# Generated by FakeRAM 2.0
VERSION 5.7 ;
BUSBITCHARS "[]" ;
PROPERTYDEFINITIONS
  MACRO width INTEGER ;
  MACRO depth INTEGER ;
  MACRO banks INTEGER ;
END PROPERTYDEFINITIONS
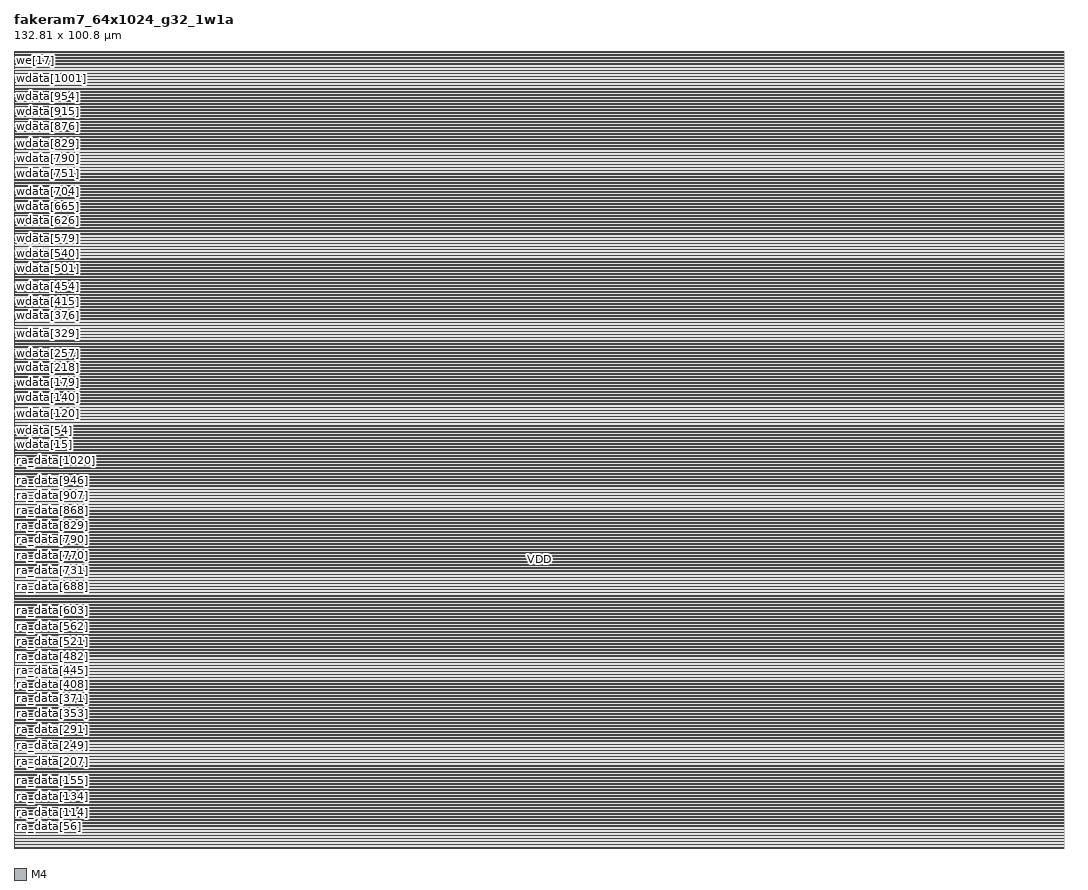
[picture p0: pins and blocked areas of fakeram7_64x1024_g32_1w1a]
MACRO fakeram7_64x1024_g32_1w1a
  PROPERTY width 1024 ;
  PROPERTY depth 64 ;
  PROPERTY banks 1 ;
  FOREIGN fakeram7_64x1024_g32_1w1a 0 0 ;
  SYMMETRY X Y R90 ;
  SIZE 132.8100 BY 100.8000 ;
  CLASS BLOCK ;
  PIN wdata[0]
    DIRECTION INPUT ;
    USE SIGNAL ;
    PORT
      LAYER M4 ;
      RECT 0.00000 49.24800 0.03600 49.27200 ;
    END
  END wdata[0]
  PIN wdata[1]
    DIRECTION INPUT ;
    USE SIGNAL ;
    PORT
      LAYER M4 ;
      RECT 0.00000 49.29600 0.03600 49.32000 ;
    END
  END wdata[1]
  PIN wdata[2]
    DIRECTION INPUT ;
    USE SIGNAL ;
    PORT
      LAYER M4 ;
      RECT 0.00000 49.34400 0.03600 49.36800 ;
    END
  END wdata[2]
  PIN wdata[3]
    DIRECTION INPUT ;
    USE SIGNAL ;
    PORT
      LAYER M4 ;
      RECT 0.00000 49.39200 0.03600 49.41600 ;
    END
  END wdata[3]
  PIN wdata[4]
    DIRECTION INPUT ;
    USE SIGNAL ;
    PORT
      LAYER M4 ;
      RECT 0.00000 49.44000 0.03600 49.46400 ;
    END
  END wdata[4]
  PIN wdata[5]
    DIRECTION INPUT ;
    USE SIGNAL ;
    PORT
      LAYER M4 ;
      RECT 0.00000 49.48800 0.03600 49.51200 ;
    END
  END wdata[5]
  PIN wdata[6]
    DIRECTION INPUT ;
    USE SIGNAL ;
    PORT
      LAYER M4 ;
      RECT 0.00000 49.53600 0.03600 49.56000 ;
    END
  END wdata[6]
  PIN wdata[7]
    DIRECTION INPUT ;
    USE SIGNAL ;
    PORT
      LAYER M4 ;
      RECT 0.00000 49.58400 0.03600 49.60800 ;
    END
  END wdata[7]
  PIN wdata[8]
    DIRECTION INPUT ;
    USE SIGNAL ;
    PORT
      LAYER M4 ;
      RECT 0.00000 49.63200 0.03600 49.65600 ;
    END
  END wdata[8]
  PIN wdata[9]
    DIRECTION INPUT ;
    USE SIGNAL ;
    PORT
      LAYER M4 ;
      RECT 0.00000 49.68000 0.03600 49.70400 ;
    END
  END wdata[9]
  PIN wdata[10]
    DIRECTION INPUT ;
    USE SIGNAL ;
    PORT
      LAYER M4 ;
      RECT 0.00000 49.72800 0.03600 49.75200 ;
    END
  END wdata[10]
  PIN wdata[11]
    DIRECTION INPUT ;
    USE SIGNAL ;
    PORT
      LAYER M4 ;
      RECT 0.00000 49.77600 0.03600 49.80000 ;
    END
  END wdata[11]
  PIN wdata[12]
    DIRECTION INPUT ;
    USE SIGNAL ;
    PORT
      LAYER M4 ;
      RECT 0.00000 49.82400 0.03600 49.84800 ;
    END
  END wdata[12]
  PIN wdata[13]
    DIRECTION INPUT ;
    USE SIGNAL ;
    PORT
      LAYER M4 ;
      RECT 0.00000 49.87200 0.03600 49.89600 ;
    END
  END wdata[13]
  PIN wdata[14]
    DIRECTION INPUT ;
    USE SIGNAL ;
    PORT
      LAYER M4 ;
      RECT 0.00000 49.92000 0.03600 49.94400 ;
    END
  END wdata[14]
  PIN wdata[15]
    DIRECTION INPUT ;
    USE SIGNAL ;
    PORT
      LAYER M4 ;
      RECT 0.00000 49.96800 0.03600 49.99200 ;
    END
  END wdata[15]
  PIN wdata[16]
    DIRECTION INPUT ;
    USE SIGNAL ;
    PORT
      LAYER M4 ;
      RECT 0.00000 50.01600 0.03600 50.04000 ;
    END
  END wdata[16]
  PIN wdata[17]
    DIRECTION INPUT ;
    USE SIGNAL ;
    PORT
      LAYER M4 ;
      RECT 0.00000 50.06400 0.03600 50.08800 ;
    END
  END wdata[17]
  PIN wdata[18]
    DIRECTION INPUT ;
    USE SIGNAL ;
    PORT
      LAYER M4 ;
      RECT 0.00000 50.11200 0.03600 50.13600 ;
    END
  END wdata[18]
  PIN wdata[19]
    DIRECTION INPUT ;
    USE SIGNAL ;
    PORT
      LAYER M4 ;
      RECT 0.00000 50.16000 0.03600 50.18400 ;
    END
  END wdata[19]
  PIN wdata[20]
    DIRECTION INPUT ;
    USE SIGNAL ;
    PORT
      LAYER M4 ;
      RECT 0.00000 50.20800 0.03600 50.23200 ;
    END
  END wdata[20]
  PIN wdata[21]
    DIRECTION INPUT ;
    USE SIGNAL ;
    PORT
      LAYER M4 ;
      RECT 0.00000 50.25600 0.03600 50.28000 ;
    END
  END wdata[21]
  PIN wdata[22]
    DIRECTION INPUT ;
    USE SIGNAL ;
    PORT
      LAYER M4 ;
      RECT 0.00000 50.30400 0.03600 50.32800 ;
    END
  END wdata[22]
  PIN wdata[23]
    DIRECTION INPUT ;
    USE SIGNAL ;
    PORT
      LAYER M4 ;
      RECT 0.00000 50.35200 0.03600 50.37600 ;
    END
  END wdata[23]
  PIN wdata[24]
    DIRECTION INPUT ;
    USE SIGNAL ;
    PORT
      LAYER M4 ;
      RECT 0.00000 50.40000 0.03600 50.42400 ;
    END
  END wdata[24]
  PIN wdata[25]
    DIRECTION INPUT ;
    USE SIGNAL ;
    PORT
      LAYER M4 ;
      RECT 0.00000 50.44800 0.03600 50.47200 ;
    END
  END wdata[25]
  PIN wdata[26]
    DIRECTION INPUT ;
    USE SIGNAL ;
    PORT
      LAYER M4 ;
      RECT 0.00000 50.49600 0.03600 50.52000 ;
    END
  END wdata[26]
  PIN wdata[27]
    DIRECTION INPUT ;
    USE SIGNAL ;
    PORT
      LAYER M4 ;
      RECT 0.00000 50.54400 0.03600 50.56800 ;
    END
  END wdata[27]
  PIN wdata[28]
    DIRECTION INPUT ;
    USE SIGNAL ;
    PORT
      LAYER M4 ;
      RECT 0.00000 50.59200 0.03600 50.61600 ;
    END
  END wdata[28]
  PIN wdata[29]
    DIRECTION INPUT ;
    USE SIGNAL ;
    PORT
      LAYER M4 ;
      RECT 0.00000 50.64000 0.03600 50.66400 ;
    END
  END wdata[29]
  PIN wdata[30]
    DIRECTION INPUT ;
    USE SIGNAL ;
    PORT
      LAYER M4 ;
      RECT 0.00000 50.68800 0.03600 50.71200 ;
    END
  END wdata[30]
  PIN wdata[31]
    DIRECTION INPUT ;
    USE SIGNAL ;
    PORT
      LAYER M4 ;
      RECT 0.00000 50.73600 0.03600 50.76000 ;
    END
  END wdata[31]
  PIN wdata[32]
    DIRECTION INPUT ;
    USE SIGNAL ;
    PORT
      LAYER M4 ;
      RECT 0.00000 50.78400 0.03600 50.80800 ;
    END
  END wdata[32]
  PIN wdata[33]
    DIRECTION INPUT ;
    USE SIGNAL ;
    PORT
      LAYER M4 ;
      RECT 0.00000 50.83200 0.03600 50.85600 ;
    END
  END wdata[33]
  PIN wdata[34]
    DIRECTION INPUT ;
    USE SIGNAL ;
    PORT
      LAYER M4 ;
      RECT 0.00000 50.88000 0.03600 50.90400 ;
    END
  END wdata[34]
  PIN wdata[35]
    DIRECTION INPUT ;
    USE SIGNAL ;
    PORT
      LAYER M4 ;
      RECT 0.00000 50.92800 0.03600 50.95200 ;
    END
  END wdata[35]
  PIN wdata[36]
    DIRECTION INPUT ;
    USE SIGNAL ;
    PORT
      LAYER M4 ;
      RECT 0.00000 50.97600 0.03600 51.00000 ;
    END
  END wdata[36]
  PIN wdata[37]
    DIRECTION INPUT ;
    USE SIGNAL ;
    PORT
      LAYER M4 ;
      RECT 0.00000 51.02400 0.03600 51.04800 ;
    END
  END wdata[37]
  PIN wdata[38]
    DIRECTION INPUT ;
    USE SIGNAL ;
    PORT
      LAYER M4 ;
      RECT 0.00000 51.07200 0.03600 51.09600 ;
    END
  END wdata[38]
  PIN wdata[39]
    DIRECTION INPUT ;
    USE SIGNAL ;
    PORT
      LAYER M4 ;
      RECT 0.00000 51.12000 0.03600 51.14400 ;
    END
  END wdata[39]
  PIN wdata[40]
    DIRECTION INPUT ;
    USE SIGNAL ;
    PORT
      LAYER M4 ;
      RECT 0.00000 51.16800 0.03600 51.19200 ;
    END
  END wdata[40]
  PIN wdata[41]
    DIRECTION INPUT ;
    USE SIGNAL ;
    PORT
      LAYER M4 ;
      RECT 0.00000 51.21600 0.03600 51.24000 ;
    END
  END wdata[41]
  PIN wdata[42]
    DIRECTION INPUT ;
    USE SIGNAL ;
    PORT
      LAYER M4 ;
      RECT 0.00000 51.26400 0.03600 51.28800 ;
    END
  END wdata[42]
  PIN wdata[43]
    DIRECTION INPUT ;
    USE SIGNAL ;
    PORT
      LAYER M4 ;
      RECT 0.00000 51.31200 0.03600 51.33600 ;
    END
  END wdata[43]
  PIN wdata[44]
    DIRECTION INPUT ;
    USE SIGNAL ;
    PORT
      LAYER M4 ;
      RECT 0.00000 51.36000 0.03600 51.38400 ;
    END
  END wdata[44]
  PIN wdata[45]
    DIRECTION INPUT ;
    USE SIGNAL ;
    PORT
      LAYER M4 ;
      RECT 0.00000 51.40800 0.03600 51.43200 ;
    END
  END wdata[45]
  PIN wdata[46]
    DIRECTION INPUT ;
    USE SIGNAL ;
    PORT
      LAYER M4 ;
      RECT 0.00000 51.45600 0.03600 51.48000 ;
    END
  END wdata[46]
  PIN wdata[47]
    DIRECTION INPUT ;
    USE SIGNAL ;
    PORT
      LAYER M4 ;
      RECT 0.00000 51.50400 0.03600 51.52800 ;
    END
  END wdata[47]
  PIN wdata[48]
    DIRECTION INPUT ;
    USE SIGNAL ;
    PORT
      LAYER M4 ;
      RECT 0.00000 51.55200 0.03600 51.57600 ;
    END
  END wdata[48]
  PIN wdata[49]
    DIRECTION INPUT ;
    USE SIGNAL ;
    PORT
      LAYER M4 ;
      RECT 0.00000 51.60000 0.03600 51.62400 ;
    END
  END wdata[49]
  PIN wdata[50]
    DIRECTION INPUT ;
    USE SIGNAL ;
    PORT
      LAYER M4 ;
      RECT 0.00000 51.64800 0.03600 51.67200 ;
    END
  END wdata[50]
  PIN wdata[51]
    DIRECTION INPUT ;
    USE SIGNAL ;
    PORT
      LAYER M4 ;
      RECT 0.00000 51.69600 0.03600 51.72000 ;
    END
  END wdata[51]
  PIN wdata[52]
    DIRECTION INPUT ;
    USE SIGNAL ;
    PORT
      LAYER M4 ;
      RECT 0.00000 51.74400 0.03600 51.76800 ;
    END
  END wdata[52]
  PIN wdata[53]
    DIRECTION INPUT ;
    USE SIGNAL ;
    PORT
      LAYER M4 ;
      RECT 0.00000 51.79200 0.03600 51.81600 ;
    END
  END wdata[53]
  PIN wdata[54]
    DIRECTION INPUT ;
    USE SIGNAL ;
    PORT
      LAYER M4 ;
      RECT 0.00000 51.84000 0.03600 51.86400 ;
    END
  END wdata[54]
  PIN wdata[55]
    DIRECTION INPUT ;
    USE SIGNAL ;
    PORT
      LAYER M4 ;
      RECT 0.00000 51.88800 0.03600 51.91200 ;
    END
  END wdata[55]
  PIN wdata[56]
    DIRECTION INPUT ;
    USE SIGNAL ;
    PORT
      LAYER M4 ;
      RECT 0.00000 51.93600 0.03600 51.96000 ;
    END
  END wdata[56]
  PIN wdata[57]
    DIRECTION INPUT ;
    USE SIGNAL ;
    PORT
      LAYER M4 ;
      RECT 0.00000 51.98400 0.03600 52.00800 ;
    END
  END wdata[57]
  PIN wdata[58]
    DIRECTION INPUT ;
    USE SIGNAL ;
    PORT
      LAYER M4 ;
      RECT 0.00000 52.03200 0.03600 52.05600 ;
    END
  END wdata[58]
  PIN wdata[59]
    DIRECTION INPUT ;
    USE SIGNAL ;
    PORT
      LAYER M4 ;
      RECT 0.00000 52.08000 0.03600 52.10400 ;
    END
  END wdata[59]
  PIN wdata[60]
    DIRECTION INPUT ;
    USE SIGNAL ;
    PORT
      LAYER M4 ;
      RECT 0.00000 52.12800 0.03600 52.15200 ;
    END
  END wdata[60]
  PIN wdata[61]
    DIRECTION INPUT ;
    USE SIGNAL ;
    PORT
      LAYER M4 ;
      RECT 0.00000 52.17600 0.03600 52.20000 ;
    END
  END wdata[61]
  PIN wdata[62]
    DIRECTION INPUT ;
    USE SIGNAL ;
    PORT
      LAYER M4 ;
      RECT 0.00000 52.22400 0.03600 52.24800 ;
    END
  END wdata[62]
  PIN wdata[63]
    DIRECTION INPUT ;
    USE SIGNAL ;
    PORT
      LAYER M4 ;
      RECT 0.00000 52.27200 0.03600 52.29600 ;
    END
  END wdata[63]
  PIN wdata[64]
    DIRECTION INPUT ;
    USE SIGNAL ;
    PORT
      LAYER M4 ;
      RECT 0.00000 52.32000 0.03600 52.34400 ;
    END
  END wdata[64]
  PIN wdata[65]
    DIRECTION INPUT ;
    USE SIGNAL ;
    PORT
      LAYER M4 ;
      RECT 0.00000 52.36800 0.03600 52.39200 ;
    END
  END wdata[65]
  PIN wdata[66]
    DIRECTION INPUT ;
    USE SIGNAL ;
    PORT
      LAYER M4 ;
      RECT 0.00000 52.41600 0.03600 52.44000 ;
    END
  END wdata[66]
  PIN wdata[67]
    DIRECTION INPUT ;
    USE SIGNAL ;
    PORT
      LAYER M4 ;
      RECT 0.00000 52.46400 0.03600 52.48800 ;
    END
  END wdata[67]
  PIN wdata[68]
    DIRECTION INPUT ;
    USE SIGNAL ;
    PORT
      LAYER M4 ;
      RECT 0.00000 52.51200 0.03600 52.53600 ;
    END
  END wdata[68]
  PIN wdata[69]
    DIRECTION INPUT ;
    USE SIGNAL ;
    PORT
      LAYER M4 ;
      RECT 0.00000 52.56000 0.03600 52.58400 ;
    END
  END wdata[69]
  PIN wdata[70]
    DIRECTION INPUT ;
    USE SIGNAL ;
    PORT
      LAYER M4 ;
      RECT 0.00000 52.60800 0.03600 52.63200 ;
    END
  END wdata[70]
  PIN wdata[71]
    DIRECTION INPUT ;
    USE SIGNAL ;
    PORT
      LAYER M4 ;
      RECT 0.00000 52.65600 0.03600 52.68000 ;
    END
  END wdata[71]
  PIN wdata[72]
    DIRECTION INPUT ;
    USE SIGNAL ;
    PORT
      LAYER M4 ;
      RECT 0.00000 52.70400 0.03600 52.72800 ;
    END
  END wdata[72]
  PIN wdata[73]
    DIRECTION INPUT ;
    USE SIGNAL ;
    PORT
      LAYER M4 ;
      RECT 0.00000 52.75200 0.03600 52.77600 ;
    END
  END wdata[73]
  PIN wdata[74]
    DIRECTION INPUT ;
    USE SIGNAL ;
    PORT
      LAYER M4 ;
      RECT 0.00000 52.80000 0.03600 52.82400 ;
    END
  END wdata[74]
  PIN wdata[75]
    DIRECTION INPUT ;
    USE SIGNAL ;
    PORT
      LAYER M4 ;
      RECT 0.00000 52.84800 0.03600 52.87200 ;
    END
  END wdata[75]
  PIN wdata[76]
    DIRECTION INPUT ;
    USE SIGNAL ;
    PORT
      LAYER M4 ;
      RECT 0.00000 52.89600 0.03600 52.92000 ;
    END
  END wdata[76]
  PIN wdata[77]
    DIRECTION INPUT ;
    USE SIGNAL ;
    PORT
      LAYER M4 ;
      RECT 0.00000 52.94400 0.03600 52.96800 ;
    END
  END wdata[77]
  PIN wdata[78]
    DIRECTION INPUT ;
    USE SIGNAL ;
    PORT
      LAYER M4 ;
      RECT 0.00000 52.99200 0.03600 53.01600 ;
    END
  END wdata[78]
  PIN wdata[79]
    DIRECTION INPUT ;
    USE SIGNAL ;
    PORT
      LAYER M4 ;
      RECT 0.00000 53.04000 0.03600 53.06400 ;
    END
  END wdata[79]
  PIN wdata[80]
    DIRECTION INPUT ;
    USE SIGNAL ;
    PORT
      LAYER M4 ;
      RECT 0.00000 53.08800 0.03600 53.11200 ;
    END
  END wdata[80]
  PIN wdata[81]
    DIRECTION INPUT ;
    USE SIGNAL ;
    PORT
      LAYER M4 ;
      RECT 0.00000 53.13600 0.03600 53.16000 ;
    END
  END wdata[81]
  PIN wdata[82]
    DIRECTION INPUT ;
    USE SIGNAL ;
    PORT
      LAYER M4 ;
      RECT 0.00000 53.18400 0.03600 53.20800 ;
    END
  END wdata[82]
  PIN wdata[83]
    DIRECTION INPUT ;
    USE SIGNAL ;
    PORT
      LAYER M4 ;
      RECT 0.00000 53.23200 0.03600 53.25600 ;
    END
  END wdata[83]
  PIN wdata[84]
    DIRECTION INPUT ;
    USE SIGNAL ;
    PORT
      LAYER M4 ;
      RECT 0.00000 53.28000 0.03600 53.30400 ;
    END
  END wdata[84]
  PIN wdata[85]
    DIRECTION INPUT ;
    USE SIGNAL ;
    PORT
      LAYER M4 ;
      RECT 0.00000 53.32800 0.03600 53.35200 ;
    END
  END wdata[85]
  PIN wdata[86]
    DIRECTION INPUT ;
    USE SIGNAL ;
    PORT
      LAYER M4 ;
      RECT 0.00000 53.37600 0.03600 53.40000 ;
    END
  END wdata[86]
  PIN wdata[87]
    DIRECTION INPUT ;
    USE SIGNAL ;
    PORT
      LAYER M4 ;
      RECT 0.00000 53.42400 0.03600 53.44800 ;
    END
  END wdata[87]
  PIN wdata[88]
    DIRECTION INPUT ;
    USE SIGNAL ;
    PORT
      LAYER M4 ;
      RECT 0.00000 53.47200 0.03600 53.49600 ;
    END
  END wdata[88]
  PIN wdata[89]
    DIRECTION INPUT ;
    USE SIGNAL ;
    PORT
      LAYER M4 ;
      RECT 0.00000 53.52000 0.03600 53.54400 ;
    END
  END wdata[89]
  PIN wdata[90]
    DIRECTION INPUT ;
    USE SIGNAL ;
    PORT
      LAYER M4 ;
      RECT 0.00000 53.56800 0.03600 53.59200 ;
    END
  END wdata[90]
  PIN wdata[91]
    DIRECTION INPUT ;
    USE SIGNAL ;
    PORT
      LAYER M4 ;
      RECT 0.00000 53.61600 0.03600 53.64000 ;
    END
  END wdata[91]
  PIN wdata[92]
    DIRECTION INPUT ;
    USE SIGNAL ;
    PORT
      LAYER M4 ;
      RECT 0.00000 53.66400 0.03600 53.68800 ;
    END
  END wdata[92]
  PIN wdata[93]
    DIRECTION INPUT ;
    USE SIGNAL ;
    PORT
      LAYER M4 ;
      RECT 0.00000 53.71200 0.03600 53.73600 ;
    END
  END wdata[93]
  PIN wdata[94]
    DIRECTION INPUT ;
    USE SIGNAL ;
    PORT
      LAYER M4 ;
      RECT 0.00000 53.76000 0.03600 53.78400 ;
    END
  END wdata[94]
  PIN wdata[95]
    DIRECTION INPUT ;
    USE SIGNAL ;
    PORT
      LAYER M4 ;
      RECT 0.00000 53.80800 0.03600 53.83200 ;
    END
  END wdata[95]
  PIN wdata[96]
    DIRECTION INPUT ;
    USE SIGNAL ;
    PORT
      LAYER M4 ;
      RECT 0.00000 53.85600 0.03600 53.88000 ;
    END
  END wdata[96]
  PIN wdata[97]
    DIRECTION INPUT ;
    USE SIGNAL ;
    PORT
      LAYER M4 ;
      RECT 0.00000 53.90400 0.03600 53.92800 ;
    END
  END wdata[97]
  PIN wdata[98]
    DIRECTION INPUT ;
    USE SIGNAL ;
    PORT
      LAYER M4 ;
      RECT 0.00000 53.95200 0.03600 53.97600 ;
    END
  END wdata[98]
  PIN wdata[99]
    DIRECTION INPUT ;
    USE SIGNAL ;
    PORT
      LAYER M4 ;
      RECT 0.00000 54.00000 0.03600 54.02400 ;
    END
  END wdata[99]
  PIN wdata[100]
    DIRECTION INPUT ;
    USE SIGNAL ;
    PORT
      LAYER M4 ;
      RECT 0.00000 54.04800 0.03600 54.07200 ;
    END
  END wdata[100]
  PIN wdata[101]
    DIRECTION INPUT ;
    USE SIGNAL ;
    PORT
      LAYER M4 ;
      RECT 0.00000 54.09600 0.03600 54.12000 ;
    END
  END wdata[101]
  PIN wdata[102]
    DIRECTION INPUT ;
    USE SIGNAL ;
    PORT
      LAYER M4 ;
      RECT 0.00000 54.14400 0.03600 54.16800 ;
    END
  END wdata[102]
  PIN wdata[103]
    DIRECTION INPUT ;
    USE SIGNAL ;
    PORT
      LAYER M4 ;
      RECT 0.00000 54.19200 0.03600 54.21600 ;
    END
  END wdata[103]
  PIN wdata[104]
    DIRECTION INPUT ;
    USE SIGNAL ;
    PORT
      LAYER M4 ;
      RECT 0.00000 54.24000 0.03600 54.26400 ;
    END
  END wdata[104]
  PIN wdata[105]
    DIRECTION INPUT ;
    USE SIGNAL ;
    PORT
      LAYER M4 ;
      RECT 0.00000 54.28800 0.03600 54.31200 ;
    END
  END wdata[105]
  PIN wdata[106]
    DIRECTION INPUT ;
    USE SIGNAL ;
    PORT
      LAYER M4 ;
      RECT 0.00000 54.33600 0.03600 54.36000 ;
    END
  END wdata[106]
  PIN wdata[107]
    DIRECTION INPUT ;
    USE SIGNAL ;
    PORT
      LAYER M4 ;
      RECT 0.00000 54.38400 0.03600 54.40800 ;
    END
  END wdata[107]
  PIN wdata[108]
    DIRECTION INPUT ;
    USE SIGNAL ;
    PORT
      LAYER M4 ;
      RECT 0.00000 54.43200 0.03600 54.45600 ;
    END
  END wdata[108]
  PIN wdata[109]
    DIRECTION INPUT ;
    USE SIGNAL ;
    PORT
      LAYER M4 ;
      RECT 0.00000 54.48000 0.03600 54.50400 ;
    END
  END wdata[109]
  PIN wdata[110]
    DIRECTION INPUT ;
    USE SIGNAL ;
    PORT
      LAYER M4 ;
      RECT 0.00000 54.52800 0.03600 54.55200 ;
    END
  END wdata[110]
  PIN wdata[111]
    DIRECTION INPUT ;
    USE SIGNAL ;
    PORT
      LAYER M4 ;
      RECT 0.00000 54.57600 0.03600 54.60000 ;
    END
  END wdata[111]
  PIN wdata[112]
    DIRECTION INPUT ;
    USE SIGNAL ;
    PORT
      LAYER M4 ;
      RECT 0.00000 54.62400 0.03600 54.64800 ;
    END
  END wdata[112]
  PIN wdata[113]
    DIRECTION INPUT ;
    USE SIGNAL ;
    PORT
      LAYER M4 ;
      RECT 0.00000 54.67200 0.03600 54.69600 ;
    END
  END wdata[113]
  PIN wdata[114]
    DIRECTION INPUT ;
    USE SIGNAL ;
    PORT
      LAYER M4 ;
      RECT 0.00000 54.72000 0.03600 54.74400 ;
    END
  END wdata[114]
  PIN wdata[115]
    DIRECTION INPUT ;
    USE SIGNAL ;
    PORT
      LAYER M4 ;
      RECT 0.00000 54.76800 0.03600 54.79200 ;
    END
  END wdata[115]
  PIN wdata[116]
    DIRECTION INPUT ;
    USE SIGNAL ;
    PORT
      LAYER M4 ;
      RECT 0.00000 54.81600 0.03600 54.84000 ;
    END
  END wdata[116]
  PIN wdata[117]
    DIRECTION INPUT ;
    USE SIGNAL ;
    PORT
      LAYER M4 ;
      RECT 0.00000 54.86400 0.03600 54.88800 ;
    END
  END wdata[117]
  PIN wdata[118]
    DIRECTION INPUT ;
    USE SIGNAL ;
    PORT
      LAYER M4 ;
      RECT 0.00000 54.91200 0.03600 54.93600 ;
    END
  END wdata[118]
  PIN wdata[119]
    DIRECTION INPUT ;
    USE SIGNAL ;
    PORT
      LAYER M4 ;
      RECT 0.00000 54.96000 0.03600 54.98400 ;
    END
  END wdata[119]
  PIN wdata[120]
    DIRECTION INPUT ;
    USE SIGNAL ;
    PORT
      LAYER M4 ;
      RECT 0.00000 55.00800 0.03600 55.03200 ;
    END
  END wdata[120]
  PIN wdata[121]
    DIRECTION INPUT ;
    USE SIGNAL ;
    PORT
      LAYER M4 ;
      RECT 0.00000 55.05600 0.03600 55.08000 ;
    END
  END wdata[121]
  PIN wdata[122]
    DIRECTION INPUT ;
    USE SIGNAL ;
    PORT
      LAYER M4 ;
      RECT 0.00000 55.10400 0.03600 55.12800 ;
    END
  END wdata[122]
  PIN wdata[123]
    DIRECTION INPUT ;
    USE SIGNAL ;
    PORT
      LAYER M4 ;
      RECT 0.00000 55.15200 0.03600 55.17600 ;
    END
  END wdata[123]
  PIN wdata[124]
    DIRECTION INPUT ;
    USE SIGNAL ;
    PORT
      LAYER M4 ;
      RECT 0.00000 55.20000 0.03600 55.22400 ;
    END
  END wdata[124]
  PIN wdata[125]
    DIRECTION INPUT ;
    USE SIGNAL ;
    PORT
      LAYER M4 ;
      RECT 0.00000 55.24800 0.03600 55.27200 ;
    END
  END wdata[125]
  PIN wdata[126]
    DIRECTION INPUT ;
    USE SIGNAL ;
    PORT
      LAYER M4 ;
      RECT 0.00000 55.29600 0.03600 55.32000 ;
    END
  END wdata[126]
  PIN wdata[127]
    DIRECTION INPUT ;
    USE SIGNAL ;
    PORT
      LAYER M4 ;
      RECT 0.00000 55.34400 0.03600 55.36800 ;
    END
  END wdata[127]
  PIN wdata[128]
    DIRECTION INPUT ;
    USE SIGNAL ;
    PORT
      LAYER M4 ;
      RECT 0.00000 55.39200 0.03600 55.41600 ;
    END
  END wdata[128]
  PIN wdata[129]
    DIRECTION INPUT ;
    USE SIGNAL ;
    PORT
      LAYER M4 ;
      RECT 0.00000 55.44000 0.03600 55.46400 ;
    END
  END wdata[129]
  PIN wdata[130]
    DIRECTION INPUT ;
    USE SIGNAL ;
    PORT
      LAYER M4 ;
      RECT 0.00000 55.48800 0.03600 55.51200 ;
    END
  END wdata[130]
  PIN wdata[131]
    DIRECTION INPUT ;
    USE SIGNAL ;
    PORT
      LAYER M4 ;
      RECT 0.00000 55.53600 0.03600 55.56000 ;
    END
  END wdata[131]
  PIN wdata[132]
    DIRECTION INPUT ;
    USE SIGNAL ;
    PORT
      LAYER M4 ;
      RECT 0.00000 55.58400 0.03600 55.60800 ;
    END
  END wdata[132]
  PIN wdata[133]
    DIRECTION INPUT ;
    USE SIGNAL ;
    PORT
      LAYER M4 ;
      RECT 0.00000 55.63200 0.03600 55.65600 ;
    END
  END wdata[133]
  PIN wdata[134]
    DIRECTION INPUT ;
    USE SIGNAL ;
    PORT
      LAYER M4 ;
      RECT 0.00000 55.68000 0.03600 55.70400 ;
    END
  END wdata[134]
  PIN wdata[135]
    DIRECTION INPUT ;
    USE SIGNAL ;
    PORT
      LAYER M4 ;
      RECT 0.00000 55.72800 0.03600 55.75200 ;
    END
  END wdata[135]
  PIN wdata[136]
    DIRECTION INPUT ;
    USE SIGNAL ;
    PORT
      LAYER M4 ;
      RECT 0.00000 55.77600 0.03600 55.80000 ;
    END
  END wdata[136]
  PIN wdata[137]
    DIRECTION INPUT ;
    USE SIGNAL ;
    PORT
      LAYER M4 ;
      RECT 0.00000 55.82400 0.03600 55.84800 ;
    END
  END wdata[137]
  PIN wdata[138]
    DIRECTION INPUT ;
    USE SIGNAL ;
    PORT
      LAYER M4 ;
      RECT 0.00000 55.87200 0.03600 55.89600 ;
    END
  END wdata[138]
  PIN wdata[139]
    DIRECTION INPUT ;
    USE SIGNAL ;
    PORT
      LAYER M4 ;
      RECT 0.00000 55.92000 0.03600 55.94400 ;
    END
  END wdata[139]
  PIN wdata[140]
    DIRECTION INPUT ;
    USE SIGNAL ;
    PORT
      LAYER M4 ;
      RECT 0.00000 55.96800 0.03600 55.99200 ;
    END
  END wdata[140]
  PIN wdata[141]
    DIRECTION INPUT ;
    USE SIGNAL ;
    PORT
      LAYER M4 ;
      RECT 0.00000 56.01600 0.03600 56.04000 ;
    END
  END wdata[141]
  PIN wdata[142]
    DIRECTION INPUT ;
    USE SIGNAL ;
    PORT
      LAYER M4 ;
      RECT 0.00000 56.06400 0.03600 56.08800 ;
    END
  END wdata[142]
  PIN wdata[143]
    DIRECTION INPUT ;
    USE SIGNAL ;
    PORT
      LAYER M4 ;
      RECT 0.00000 56.11200 0.03600 56.13600 ;
    END
  END wdata[143]
  PIN wdata[144]
    DIRECTION INPUT ;
    USE SIGNAL ;
    PORT
      LAYER M4 ;
      RECT 0.00000 56.16000 0.03600 56.18400 ;
    END
  END wdata[144]
  PIN wdata[145]
    DIRECTION INPUT ;
    USE SIGNAL ;
    PORT
      LAYER M4 ;
      RECT 0.00000 56.20800 0.03600 56.23200 ;
    END
  END wdata[145]
  PIN wdata[146]
    DIRECTION INPUT ;
    USE SIGNAL ;
    PORT
      LAYER M4 ;
      RECT 0.00000 56.25600 0.03600 56.28000 ;
    END
  END wdata[146]
  PIN wdata[147]
    DIRECTION INPUT ;
    USE SIGNAL ;
    PORT
      LAYER M4 ;
      RECT 0.00000 56.30400 0.03600 56.32800 ;
    END
  END wdata[147]
  PIN wdata[148]
    DIRECTION INPUT ;
    USE SIGNAL ;
    PORT
      LAYER M4 ;
      RECT 0.00000 56.35200 0.03600 56.37600 ;
    END
  END wdata[148]
  PIN wdata[149]
    DIRECTION INPUT ;
    USE SIGNAL ;
    PORT
      LAYER M4 ;
      RECT 0.00000 56.40000 0.03600 56.42400 ;
    END
  END wdata[149]
  PIN wdata[150]
    DIRECTION INPUT ;
    USE SIGNAL ;
    PORT
      LAYER M4 ;
      RECT 0.00000 56.44800 0.03600 56.47200 ;
    END
  END wdata[150]
  PIN wdata[151]
    DIRECTION INPUT ;
    USE SIGNAL ;
    PORT
      LAYER M4 ;
      RECT 0.00000 56.49600 0.03600 56.52000 ;
    END
  END wdata[151]
  PIN wdata[152]
    DIRECTION INPUT ;
    USE SIGNAL ;
    PORT
      LAYER M4 ;
      RECT 0.00000 56.54400 0.03600 56.56800 ;
    END
  END wdata[152]
  PIN wdata[153]
    DIRECTION INPUT ;
    USE SIGNAL ;
    PORT
      LAYER M4 ;
      RECT 0.00000 56.59200 0.03600 56.61600 ;
    END
  END wdata[153]
  PIN wdata[154]
    DIRECTION INPUT ;
    USE SIGNAL ;
    PORT
      LAYER M4 ;
      RECT 0.00000 56.64000 0.03600 56.66400 ;
    END
  END wdata[154]
  PIN wdata[155]
    DIRECTION INPUT ;
    USE SIGNAL ;
    PORT
      LAYER M4 ;
      RECT 0.00000 56.68800 0.03600 56.71200 ;
    END
  END wdata[155]
  PIN wdata[156]
    DIRECTION INPUT ;
    USE SIGNAL ;
    PORT
      LAYER M4 ;
      RECT 0.00000 56.73600 0.03600 56.76000 ;
    END
  END wdata[156]
  PIN wdata[157]
    DIRECTION INPUT ;
    USE SIGNAL ;
    PORT
      LAYER M4 ;
      RECT 0.00000 56.78400 0.03600 56.80800 ;
    END
  END wdata[157]
  PIN wdata[158]
    DIRECTION INPUT ;
    USE SIGNAL ;
    PORT
      LAYER M4 ;
      RECT 0.00000 56.83200 0.03600 56.85600 ;
    END
  END wdata[158]
  PIN wdata[159]
    DIRECTION INPUT ;
    USE SIGNAL ;
    PORT
      LAYER M4 ;
      RECT 0.00000 56.88000 0.03600 56.90400 ;
    END
  END wdata[159]
  PIN wdata[160]
    DIRECTION INPUT ;
    USE SIGNAL ;
    PORT
      LAYER M4 ;
      RECT 0.00000 56.92800 0.03600 56.95200 ;
    END
  END wdata[160]
  PIN wdata[161]
    DIRECTION INPUT ;
    USE SIGNAL ;
    PORT
      LAYER M4 ;
      RECT 0.00000 56.97600 0.03600 57.00000 ;
    END
  END wdata[161]
  PIN wdata[162]
    DIRECTION INPUT ;
    USE SIGNAL ;
    PORT
      LAYER M4 ;
      RECT 0.00000 57.02400 0.03600 57.04800 ;
    END
  END wdata[162]
  PIN wdata[163]
    DIRECTION INPUT ;
    USE SIGNAL ;
    PORT
      LAYER M4 ;
      RECT 0.00000 57.07200 0.03600 57.09600 ;
    END
  END wdata[163]
  PIN wdata[164]
    DIRECTION INPUT ;
    USE SIGNAL ;
    PORT
      LAYER M4 ;
      RECT 0.00000 57.12000 0.03600 57.14400 ;
    END
  END wdata[164]
  PIN wdata[165]
    DIRECTION INPUT ;
    USE SIGNAL ;
    PORT
      LAYER M4 ;
      RECT 0.00000 57.16800 0.03600 57.19200 ;
    END
  END wdata[165]
  PIN wdata[166]
    DIRECTION INPUT ;
    USE SIGNAL ;
    PORT
      LAYER M4 ;
      RECT 0.00000 57.21600 0.03600 57.24000 ;
    END
  END wdata[166]
  PIN wdata[167]
    DIRECTION INPUT ;
    USE SIGNAL ;
    PORT
      LAYER M4 ;
      RECT 0.00000 57.26400 0.03600 57.28800 ;
    END
  END wdata[167]
  PIN wdata[168]
    DIRECTION INPUT ;
    USE SIGNAL ;
    PORT
      LAYER M4 ;
      RECT 0.00000 57.31200 0.03600 57.33600 ;
    END
  END wdata[168]
  PIN wdata[169]
    DIRECTION INPUT ;
    USE SIGNAL ;
    PORT
      LAYER M4 ;
      RECT 0.00000 57.36000 0.03600 57.38400 ;
    END
  END wdata[169]
  PIN wdata[170]
    DIRECTION INPUT ;
    USE SIGNAL ;
    PORT
      LAYER M4 ;
      RECT 0.00000 57.40800 0.03600 57.43200 ;
    END
  END wdata[170]
  PIN wdata[171]
    DIRECTION INPUT ;
    USE SIGNAL ;
    PORT
      LAYER M4 ;
      RECT 0.00000 57.45600 0.03600 57.48000 ;
    END
  END wdata[171]
  PIN wdata[172]
    DIRECTION INPUT ;
    USE SIGNAL ;
    PORT
      LAYER M4 ;
      RECT 0.00000 57.50400 0.03600 57.52800 ;
    END
  END wdata[172]
  PIN wdata[173]
    DIRECTION INPUT ;
    USE SIGNAL ;
    PORT
      LAYER M4 ;
      RECT 0.00000 57.55200 0.03600 57.57600 ;
    END
  END wdata[173]
  PIN wdata[174]
    DIRECTION INPUT ;
    USE SIGNAL ;
    PORT
      LAYER M4 ;
      RECT 0.00000 57.60000 0.03600 57.62400 ;
    END
  END wdata[174]
  PIN wdata[175]
    DIRECTION INPUT ;
    USE SIGNAL ;
    PORT
      LAYER M4 ;
      RECT 0.00000 57.64800 0.03600 57.67200 ;
    END
  END wdata[175]
  PIN wdata[176]
    DIRECTION INPUT ;
    USE SIGNAL ;
    PORT
      LAYER M4 ;
      RECT 0.00000 57.69600 0.03600 57.72000 ;
    END
  END wdata[176]
  PIN wdata[177]
    DIRECTION INPUT ;
    USE SIGNAL ;
    PORT
      LAYER M4 ;
      RECT 0.00000 57.74400 0.03600 57.76800 ;
    END
  END wdata[177]
  PIN wdata[178]
    DIRECTION INPUT ;
    USE SIGNAL ;
    PORT
      LAYER M4 ;
      RECT 0.00000 57.79200 0.03600 57.81600 ;
    END
  END wdata[178]
  PIN wdata[179]
    DIRECTION INPUT ;
    USE SIGNAL ;
    PORT
      LAYER M4 ;
      RECT 0.00000 57.84000 0.03600 57.86400 ;
    END
  END wdata[179]
  PIN wdata[180]
    DIRECTION INPUT ;
    USE SIGNAL ;
    PORT
      LAYER M4 ;
      RECT 0.00000 57.88800 0.03600 57.91200 ;
    END
  END wdata[180]
  PIN wdata[181]
    DIRECTION INPUT ;
    USE SIGNAL ;
    PORT
      LAYER M4 ;
      RECT 0.00000 57.93600 0.03600 57.96000 ;
    END
  END wdata[181]
  PIN wdata[182]
    DIRECTION INPUT ;
    USE SIGNAL ;
    PORT
      LAYER M4 ;
      RECT 0.00000 57.98400 0.03600 58.00800 ;
    END
  END wdata[182]
  PIN wdata[183]
    DIRECTION INPUT ;
    USE SIGNAL ;
    PORT
      LAYER M4 ;
      RECT 0.00000 58.03200 0.03600 58.05600 ;
    END
  END wdata[183]
  PIN wdata[184]
    DIRECTION INPUT ;
    USE SIGNAL ;
    PORT
      LAYER M4 ;
      RECT 0.00000 58.08000 0.03600 58.10400 ;
    END
  END wdata[184]
  PIN wdata[185]
    DIRECTION INPUT ;
    USE SIGNAL ;
    PORT
      LAYER M4 ;
      RECT 0.00000 58.12800 0.03600 58.15200 ;
    END
  END wdata[185]
  PIN wdata[186]
    DIRECTION INPUT ;
    USE SIGNAL ;
    PORT
      LAYER M4 ;
      RECT 0.00000 58.17600 0.03600 58.20000 ;
    END
  END wdata[186]
  PIN wdata[187]
    DIRECTION INPUT ;
    USE SIGNAL ;
    PORT
      LAYER M4 ;
      RECT 0.00000 58.22400 0.03600 58.24800 ;
    END
  END wdata[187]
  PIN wdata[188]
    DIRECTION INPUT ;
    USE SIGNAL ;
    PORT
      LAYER M4 ;
      RECT 0.00000 58.27200 0.03600 58.29600 ;
    END
  END wdata[188]
  PIN wdata[189]
    DIRECTION INPUT ;
    USE SIGNAL ;
    PORT
      LAYER M4 ;
      RECT 0.00000 58.32000 0.03600 58.34400 ;
    END
  END wdata[189]
  PIN wdata[190]
    DIRECTION INPUT ;
    USE SIGNAL ;
    PORT
      LAYER M4 ;
      RECT 0.00000 58.36800 0.03600 58.39200 ;
    END
  END wdata[190]
  PIN wdata[191]
    DIRECTION INPUT ;
    USE SIGNAL ;
    PORT
      LAYER M4 ;
      RECT 0.00000 58.41600 0.03600 58.44000 ;
    END
  END wdata[191]
  PIN wdata[192]
    DIRECTION INPUT ;
    USE SIGNAL ;
    PORT
      LAYER M4 ;
      RECT 0.00000 58.46400 0.03600 58.48800 ;
    END
  END wdata[192]
  PIN wdata[193]
    DIRECTION INPUT ;
    USE SIGNAL ;
    PORT
      LAYER M4 ;
      RECT 0.00000 58.51200 0.03600 58.53600 ;
    END
  END wdata[193]
  PIN wdata[194]
    DIRECTION INPUT ;
    USE SIGNAL ;
    PORT
      LAYER M4 ;
      RECT 0.00000 58.56000 0.03600 58.58400 ;
    END
  END wdata[194]
  PIN wdata[195]
    DIRECTION INPUT ;
    USE SIGNAL ;
    PORT
      LAYER M4 ;
      RECT 0.00000 58.60800 0.03600 58.63200 ;
    END
  END wdata[195]
  PIN wdata[196]
    DIRECTION INPUT ;
    USE SIGNAL ;
    PORT
      LAYER M4 ;
      RECT 0.00000 58.65600 0.03600 58.68000 ;
    END
  END wdata[196]
  PIN wdata[197]
    DIRECTION INPUT ;
    USE SIGNAL ;
    PORT
      LAYER M4 ;
      RECT 0.00000 58.70400 0.03600 58.72800 ;
    END
  END wdata[197]
  PIN wdata[198]
    DIRECTION INPUT ;
    USE SIGNAL ;
    PORT
      LAYER M4 ;
      RECT 0.00000 58.75200 0.03600 58.77600 ;
    END
  END wdata[198]
  PIN wdata[199]
    DIRECTION INPUT ;
    USE SIGNAL ;
    PORT
      LAYER M4 ;
      RECT 0.00000 58.80000 0.03600 58.82400 ;
    END
  END wdata[199]
  PIN wdata[200]
    DIRECTION INPUT ;
    USE SIGNAL ;
    PORT
      LAYER M4 ;
      RECT 0.00000 58.84800 0.03600 58.87200 ;
    END
  END wdata[200]
  PIN wdata[201]
    DIRECTION INPUT ;
    USE SIGNAL ;
    PORT
      LAYER M4 ;
      RECT 0.00000 58.89600 0.03600 58.92000 ;
    END
  END wdata[201]
  PIN wdata[202]
    DIRECTION INPUT ;
    USE SIGNAL ;
    PORT
      LAYER M4 ;
      RECT 0.00000 58.94400 0.03600 58.96800 ;
    END
  END wdata[202]
  PIN wdata[203]
    DIRECTION INPUT ;
    USE SIGNAL ;
    PORT
      LAYER M4 ;
      RECT 0.00000 58.99200 0.03600 59.01600 ;
    END
  END wdata[203]
  PIN wdata[204]
    DIRECTION INPUT ;
    USE SIGNAL ;
    PORT
      LAYER M4 ;
      RECT 0.00000 59.04000 0.03600 59.06400 ;
    END
  END wdata[204]
  PIN wdata[205]
    DIRECTION INPUT ;
    USE SIGNAL ;
    PORT
      LAYER M4 ;
      RECT 0.00000 59.08800 0.03600 59.11200 ;
    END
  END wdata[205]
  PIN wdata[206]
    DIRECTION INPUT ;
    USE SIGNAL ;
    PORT
      LAYER M4 ;
      RECT 0.00000 59.13600 0.03600 59.16000 ;
    END
  END wdata[206]
  PIN wdata[207]
    DIRECTION INPUT ;
    USE SIGNAL ;
    PORT
      LAYER M4 ;
      RECT 0.00000 59.18400 0.03600 59.20800 ;
    END
  END wdata[207]
  PIN wdata[208]
    DIRECTION INPUT ;
    USE SIGNAL ;
    PORT
      LAYER M4 ;
      RECT 0.00000 59.23200 0.03600 59.25600 ;
    END
  END wdata[208]
  PIN wdata[209]
    DIRECTION INPUT ;
    USE SIGNAL ;
    PORT
      LAYER M4 ;
      RECT 0.00000 59.28000 0.03600 59.30400 ;
    END
  END wdata[209]
  PIN wdata[210]
    DIRECTION INPUT ;
    USE SIGNAL ;
    PORT
      LAYER M4 ;
      RECT 0.00000 59.32800 0.03600 59.35200 ;
    END
  END wdata[210]
  PIN wdata[211]
    DIRECTION INPUT ;
    USE SIGNAL ;
    PORT
      LAYER M4 ;
      RECT 0.00000 59.37600 0.03600 59.40000 ;
    END
  END wdata[211]
  PIN wdata[212]
    DIRECTION INPUT ;
    USE SIGNAL ;
    PORT
      LAYER M4 ;
      RECT 0.00000 59.42400 0.03600 59.44800 ;
    END
  END wdata[212]
  PIN wdata[213]
    DIRECTION INPUT ;
    USE SIGNAL ;
    PORT
      LAYER M4 ;
      RECT 0.00000 59.47200 0.03600 59.49600 ;
    END
  END wdata[213]
  PIN wdata[214]
    DIRECTION INPUT ;
    USE SIGNAL ;
    PORT
      LAYER M4 ;
      RECT 0.00000 59.52000 0.03600 59.54400 ;
    END
  END wdata[214]
  PIN wdata[215]
    DIRECTION INPUT ;
    USE SIGNAL ;
    PORT
      LAYER M4 ;
      RECT 0.00000 59.56800 0.03600 59.59200 ;
    END
  END wdata[215]
  PIN wdata[216]
    DIRECTION INPUT ;
    USE SIGNAL ;
    PORT
      LAYER M4 ;
      RECT 0.00000 59.61600 0.03600 59.64000 ;
    END
  END wdata[216]
  PIN wdata[217]
    DIRECTION INPUT ;
    USE SIGNAL ;
    PORT
      LAYER M4 ;
      RECT 0.00000 59.66400 0.03600 59.68800 ;
    END
  END wdata[217]
  PIN wdata[218]
    DIRECTION INPUT ;
    USE SIGNAL ;
    PORT
      LAYER M4 ;
      RECT 0.00000 59.71200 0.03600 59.73600 ;
    END
  END wdata[218]
  PIN wdata[219]
    DIRECTION INPUT ;
    USE SIGNAL ;
    PORT
      LAYER M4 ;
      RECT 0.00000 59.76000 0.03600 59.78400 ;
    END
  END wdata[219]
  PIN wdata[220]
    DIRECTION INPUT ;
    USE SIGNAL ;
    PORT
      LAYER M4 ;
      RECT 0.00000 59.80800 0.03600 59.83200 ;
    END
  END wdata[220]
  PIN wdata[221]
    DIRECTION INPUT ;
    USE SIGNAL ;
    PORT
      LAYER M4 ;
      RECT 0.00000 59.85600 0.03600 59.88000 ;
    END
  END wdata[221]
  PIN wdata[222]
    DIRECTION INPUT ;
    USE SIGNAL ;
    PORT
      LAYER M4 ;
      RECT 0.00000 59.90400 0.03600 59.92800 ;
    END
  END wdata[222]
  PIN wdata[223]
    DIRECTION INPUT ;
    USE SIGNAL ;
    PORT
      LAYER M4 ;
      RECT 0.00000 59.95200 0.03600 59.97600 ;
    END
  END wdata[223]
  PIN wdata[224]
    DIRECTION INPUT ;
    USE SIGNAL ;
    PORT
      LAYER M4 ;
      RECT 0.00000 60.00000 0.03600 60.02400 ;
    END
  END wdata[224]
  PIN wdata[225]
    DIRECTION INPUT ;
    USE SIGNAL ;
    PORT
      LAYER M4 ;
      RECT 0.00000 60.04800 0.03600 60.07200 ;
    END
  END wdata[225]
  PIN wdata[226]
    DIRECTION INPUT ;
    USE SIGNAL ;
    PORT
      LAYER M4 ;
      RECT 0.00000 60.09600 0.03600 60.12000 ;
    END
  END wdata[226]
  PIN wdata[227]
    DIRECTION INPUT ;
    USE SIGNAL ;
    PORT
      LAYER M4 ;
      RECT 0.00000 60.14400 0.03600 60.16800 ;
    END
  END wdata[227]
  PIN wdata[228]
    DIRECTION INPUT ;
    USE SIGNAL ;
    PORT
      LAYER M4 ;
      RECT 0.00000 60.19200 0.03600 60.21600 ;
    END
  END wdata[228]
  PIN wdata[229]
    DIRECTION INPUT ;
    USE SIGNAL ;
    PORT
      LAYER M4 ;
      RECT 0.00000 60.24000 0.03600 60.26400 ;
    END
  END wdata[229]
  PIN wdata[230]
    DIRECTION INPUT ;
    USE SIGNAL ;
    PORT
      LAYER M4 ;
      RECT 0.00000 60.28800 0.03600 60.31200 ;
    END
  END wdata[230]
  PIN wdata[231]
    DIRECTION INPUT ;
    USE SIGNAL ;
    PORT
      LAYER M4 ;
      RECT 0.00000 60.33600 0.03600 60.36000 ;
    END
  END wdata[231]
  PIN wdata[232]
    DIRECTION INPUT ;
    USE SIGNAL ;
    PORT
      LAYER M4 ;
      RECT 0.00000 60.38400 0.03600 60.40800 ;
    END
  END wdata[232]
  PIN wdata[233]
    DIRECTION INPUT ;
    USE SIGNAL ;
    PORT
      LAYER M4 ;
      RECT 0.00000 60.43200 0.03600 60.45600 ;
    END
  END wdata[233]
  PIN wdata[234]
    DIRECTION INPUT ;
    USE SIGNAL ;
    PORT
      LAYER M4 ;
      RECT 0.00000 60.48000 0.03600 60.50400 ;
    END
  END wdata[234]
  PIN wdata[235]
    DIRECTION INPUT ;
    USE SIGNAL ;
    PORT
      LAYER M4 ;
      RECT 0.00000 60.52800 0.03600 60.55200 ;
    END
  END wdata[235]
  PIN wdata[236]
    DIRECTION INPUT ;
    USE SIGNAL ;
    PORT
      LAYER M4 ;
      RECT 0.00000 60.57600 0.03600 60.60000 ;
    END
  END wdata[236]
  PIN wdata[237]
    DIRECTION INPUT ;
    USE SIGNAL ;
    PORT
      LAYER M4 ;
      RECT 0.00000 60.62400 0.03600 60.64800 ;
    END
  END wdata[237]
  PIN wdata[238]
    DIRECTION INPUT ;
    USE SIGNAL ;
    PORT
      LAYER M4 ;
      RECT 0.00000 60.67200 0.03600 60.69600 ;
    END
  END wdata[238]
  PIN wdata[239]
    DIRECTION INPUT ;
    USE SIGNAL ;
    PORT
      LAYER M4 ;
      RECT 0.00000 60.72000 0.03600 60.74400 ;
    END
  END wdata[239]
  PIN wdata[240]
    DIRECTION INPUT ;
    USE SIGNAL ;
    PORT
      LAYER M4 ;
      RECT 0.00000 60.76800 0.03600 60.79200 ;
    END
  END wdata[240]
  PIN wdata[241]
    DIRECTION INPUT ;
    USE SIGNAL ;
    PORT
      LAYER M4 ;
      RECT 0.00000 60.81600 0.03600 60.84000 ;
    END
  END wdata[241]
  PIN wdata[242]
    DIRECTION INPUT ;
    USE SIGNAL ;
    PORT
      LAYER M4 ;
      RECT 0.00000 60.86400 0.03600 60.88800 ;
    END
  END wdata[242]
  PIN wdata[243]
    DIRECTION INPUT ;
    USE SIGNAL ;
    PORT
      LAYER M4 ;
      RECT 0.00000 60.91200 0.03600 60.93600 ;
    END
  END wdata[243]
  PIN wdata[244]
    DIRECTION INPUT ;
    USE SIGNAL ;
    PORT
      LAYER M4 ;
      RECT 0.00000 60.96000 0.03600 60.98400 ;
    END
  END wdata[244]
  PIN wdata[245]
    DIRECTION INPUT ;
    USE SIGNAL ;
    PORT
      LAYER M4 ;
      RECT 0.00000 61.00800 0.03600 61.03200 ;
    END
  END wdata[245]
  PIN wdata[246]
    DIRECTION INPUT ;
    USE SIGNAL ;
    PORT
      LAYER M4 ;
      RECT 0.00000 61.05600 0.03600 61.08000 ;
    END
  END wdata[246]
  PIN wdata[247]
    DIRECTION INPUT ;
    USE SIGNAL ;
    PORT
      LAYER M4 ;
      RECT 0.00000 61.10400 0.03600 61.12800 ;
    END
  END wdata[247]
  PIN wdata[248]
    DIRECTION INPUT ;
    USE SIGNAL ;
    PORT
      LAYER M4 ;
      RECT 0.00000 61.15200 0.03600 61.17600 ;
    END
  END wdata[248]
  PIN wdata[249]
    DIRECTION INPUT ;
    USE SIGNAL ;
    PORT
      LAYER M4 ;
      RECT 0.00000 61.20000 0.03600 61.22400 ;
    END
  END wdata[249]
  PIN wdata[250]
    DIRECTION INPUT ;
    USE SIGNAL ;
    PORT
      LAYER M4 ;
      RECT 0.00000 61.24800 0.03600 61.27200 ;
    END
  END wdata[250]
  PIN wdata[251]
    DIRECTION INPUT ;
    USE SIGNAL ;
    PORT
      LAYER M4 ;
      RECT 0.00000 61.29600 0.03600 61.32000 ;
    END
  END wdata[251]
  PIN wdata[252]
    DIRECTION INPUT ;
    USE SIGNAL ;
    PORT
      LAYER M4 ;
      RECT 0.00000 61.34400 0.03600 61.36800 ;
    END
  END wdata[252]
  PIN wdata[253]
    DIRECTION INPUT ;
    USE SIGNAL ;
    PORT
      LAYER M4 ;
      RECT 0.00000 61.39200 0.03600 61.41600 ;
    END
  END wdata[253]
  PIN wdata[254]
    DIRECTION INPUT ;
    USE SIGNAL ;
    PORT
      LAYER M4 ;
      RECT 0.00000 61.44000 0.03600 61.46400 ;
    END
  END wdata[254]
  PIN wdata[255]
    DIRECTION INPUT ;
    USE SIGNAL ;
    PORT
      LAYER M4 ;
      RECT 0.00000 61.48800 0.03600 61.51200 ;
    END
  END wdata[255]
  PIN wdata[256]
    DIRECTION INPUT ;
    USE SIGNAL ;
    PORT
      LAYER M4 ;
      RECT 0.00000 61.53600 0.03600 61.56000 ;
    END
  END wdata[256]
  PIN wdata[257]
    DIRECTION INPUT ;
    USE SIGNAL ;
    PORT
      LAYER M4 ;
      RECT 0.00000 61.58400 0.03600 61.60800 ;
    END
  END wdata[257]
  PIN wdata[258]
    DIRECTION INPUT ;
    USE SIGNAL ;
    PORT
      LAYER M4 ;
      RECT 0.00000 61.63200 0.03600 61.65600 ;
    END
  END wdata[258]
  PIN wdata[259]
    DIRECTION INPUT ;
    USE SIGNAL ;
    PORT
      LAYER M4 ;
      RECT 0.00000 61.68000 0.03600 61.70400 ;
    END
  END wdata[259]
  PIN wdata[260]
    DIRECTION INPUT ;
    USE SIGNAL ;
    PORT
      LAYER M4 ;
      RECT 0.00000 61.72800 0.03600 61.75200 ;
    END
  END wdata[260]
  PIN wdata[261]
    DIRECTION INPUT ;
    USE SIGNAL ;
    PORT
      LAYER M4 ;
      RECT 0.00000 61.77600 0.03600 61.80000 ;
    END
  END wdata[261]
  PIN wdata[262]
    DIRECTION INPUT ;
    USE SIGNAL ;
    PORT
      LAYER M4 ;
      RECT 0.00000 61.82400 0.03600 61.84800 ;
    END
  END wdata[262]
  PIN wdata[263]
    DIRECTION INPUT ;
    USE SIGNAL ;
    PORT
      LAYER M4 ;
      RECT 0.00000 61.87200 0.03600 61.89600 ;
    END
  END wdata[263]
  PIN wdata[264]
    DIRECTION INPUT ;
    USE SIGNAL ;
    PORT
      LAYER M4 ;
      RECT 0.00000 61.92000 0.03600 61.94400 ;
    END
  END wdata[264]
  PIN wdata[265]
    DIRECTION INPUT ;
    USE SIGNAL ;
    PORT
      LAYER M4 ;
      RECT 0.00000 61.96800 0.03600 61.99200 ;
    END
  END wdata[265]
  PIN wdata[266]
    DIRECTION INPUT ;
    USE SIGNAL ;
    PORT
      LAYER M4 ;
      RECT 0.00000 62.01600 0.03600 62.04000 ;
    END
  END wdata[266]
  PIN wdata[267]
    DIRECTION INPUT ;
    USE SIGNAL ;
    PORT
      LAYER M4 ;
      RECT 0.00000 62.06400 0.03600 62.08800 ;
    END
  END wdata[267]
  PIN wdata[268]
    DIRECTION INPUT ;
    USE SIGNAL ;
    PORT
      LAYER M4 ;
      RECT 0.00000 62.11200 0.03600 62.13600 ;
    END
  END wdata[268]
  PIN wdata[269]
    DIRECTION INPUT ;
    USE SIGNAL ;
    PORT
      LAYER M4 ;
      RECT 0.00000 62.16000 0.03600 62.18400 ;
    END
  END wdata[269]
  PIN wdata[270]
    DIRECTION INPUT ;
    USE SIGNAL ;
    PORT
      LAYER M4 ;
      RECT 0.00000 62.20800 0.03600 62.23200 ;
    END
  END wdata[270]
  PIN wdata[271]
    DIRECTION INPUT ;
    USE SIGNAL ;
    PORT
      LAYER M4 ;
      RECT 0.00000 62.25600 0.03600 62.28000 ;
    END
  END wdata[271]
  PIN wdata[272]
    DIRECTION INPUT ;
    USE SIGNAL ;
    PORT
      LAYER M4 ;
      RECT 0.00000 62.30400 0.03600 62.32800 ;
    END
  END wdata[272]
  PIN wdata[273]
    DIRECTION INPUT ;
    USE SIGNAL ;
    PORT
      LAYER M4 ;
      RECT 0.00000 62.35200 0.03600 62.37600 ;
    END
  END wdata[273]
  PIN wdata[274]
    DIRECTION INPUT ;
    USE SIGNAL ;
    PORT
      LAYER M4 ;
      RECT 0.00000 62.40000 0.03600 62.42400 ;
    END
  END wdata[274]
  PIN wdata[275]
    DIRECTION INPUT ;
    USE SIGNAL ;
    PORT
      LAYER M4 ;
      RECT 0.00000 62.44800 0.03600 62.47200 ;
    END
  END wdata[275]
  PIN wdata[276]
    DIRECTION INPUT ;
    USE SIGNAL ;
    PORT
      LAYER M4 ;
      RECT 0.00000 62.49600 0.03600 62.52000 ;
    END
  END wdata[276]
  PIN wdata[277]
    DIRECTION INPUT ;
    USE SIGNAL ;
    PORT
      LAYER M4 ;
      RECT 0.00000 62.54400 0.03600 62.56800 ;
    END
  END wdata[277]
  PIN wdata[278]
    DIRECTION INPUT ;
    USE SIGNAL ;
    PORT
      LAYER M4 ;
      RECT 0.00000 62.59200 0.03600 62.61600 ;
    END
  END wdata[278]
  PIN wdata[279]
    DIRECTION INPUT ;
    USE SIGNAL ;
    PORT
      LAYER M4 ;
      RECT 0.00000 62.64000 0.03600 62.66400 ;
    END
  END wdata[279]
  PIN wdata[280]
    DIRECTION INPUT ;
    USE SIGNAL ;
    PORT
      LAYER M4 ;
      RECT 0.00000 62.68800 0.03600 62.71200 ;
    END
  END wdata[280]
  PIN wdata[281]
    DIRECTION INPUT ;
    USE SIGNAL ;
    PORT
      LAYER M4 ;
      RECT 0.00000 62.73600 0.03600 62.76000 ;
    END
  END wdata[281]
  PIN wdata[282]
    DIRECTION INPUT ;
    USE SIGNAL ;
    PORT
      LAYER M4 ;
      RECT 0.00000 62.78400 0.03600 62.80800 ;
    END
  END wdata[282]
  PIN wdata[283]
    DIRECTION INPUT ;
    USE SIGNAL ;
    PORT
      LAYER M4 ;
      RECT 0.00000 62.83200 0.03600 62.85600 ;
    END
  END wdata[283]
  PIN wdata[284]
    DIRECTION INPUT ;
    USE SIGNAL ;
    PORT
      LAYER M4 ;
      RECT 0.00000 62.88000 0.03600 62.90400 ;
    END
  END wdata[284]
  PIN wdata[285]
    DIRECTION INPUT ;
    USE SIGNAL ;
    PORT
      LAYER M4 ;
      RECT 0.00000 62.92800 0.03600 62.95200 ;
    END
  END wdata[285]
  PIN wdata[286]
    DIRECTION INPUT ;
    USE SIGNAL ;
    PORT
      LAYER M4 ;
      RECT 0.00000 62.97600 0.03600 63.00000 ;
    END
  END wdata[286]
  PIN wdata[287]
    DIRECTION INPUT ;
    USE SIGNAL ;
    PORT
      LAYER M4 ;
      RECT 0.00000 63.02400 0.03600 63.04800 ;
    END
  END wdata[287]
  PIN wdata[288]
    DIRECTION INPUT ;
    USE SIGNAL ;
    PORT
      LAYER M4 ;
      RECT 0.00000 63.07200 0.03600 63.09600 ;
    END
  END wdata[288]
  PIN wdata[289]
    DIRECTION INPUT ;
    USE SIGNAL ;
    PORT
      LAYER M4 ;
      RECT 0.00000 63.12000 0.03600 63.14400 ;
    END
  END wdata[289]
  PIN wdata[290]
    DIRECTION INPUT ;
    USE SIGNAL ;
    PORT
      LAYER M4 ;
      RECT 0.00000 63.16800 0.03600 63.19200 ;
    END
  END wdata[290]
  PIN wdata[291]
    DIRECTION INPUT ;
    USE SIGNAL ;
    PORT
      LAYER M4 ;
      RECT 0.00000 63.21600 0.03600 63.24000 ;
    END
  END wdata[291]
  PIN wdata[292]
    DIRECTION INPUT ;
    USE SIGNAL ;
    PORT
      LAYER M4 ;
      RECT 0.00000 63.26400 0.03600 63.28800 ;
    END
  END wdata[292]
  PIN wdata[293]
    DIRECTION INPUT ;
    USE SIGNAL ;
    PORT
      LAYER M4 ;
      RECT 0.00000 63.31200 0.03600 63.33600 ;
    END
  END wdata[293]
  PIN wdata[294]
    DIRECTION INPUT ;
    USE SIGNAL ;
    PORT
      LAYER M4 ;
      RECT 0.00000 63.36000 0.03600 63.38400 ;
    END
  END wdata[294]
  PIN wdata[295]
    DIRECTION INPUT ;
    USE SIGNAL ;
    PORT
      LAYER M4 ;
      RECT 0.00000 63.40800 0.03600 63.43200 ;
    END
  END wdata[295]
  PIN wdata[296]
    DIRECTION INPUT ;
    USE SIGNAL ;
    PORT
      LAYER M4 ;
      RECT 0.00000 63.45600 0.03600 63.48000 ;
    END
  END wdata[296]
  PIN wdata[297]
    DIRECTION INPUT ;
    USE SIGNAL ;
    PORT
      LAYER M4 ;
      RECT 0.00000 63.50400 0.03600 63.52800 ;
    END
  END wdata[297]
  PIN wdata[298]
    DIRECTION INPUT ;
    USE SIGNAL ;
    PORT
      LAYER M4 ;
      RECT 0.00000 63.55200 0.03600 63.57600 ;
    END
  END wdata[298]
  PIN wdata[299]
    DIRECTION INPUT ;
    USE SIGNAL ;
    PORT
      LAYER M4 ;
      RECT 0.00000 63.60000 0.03600 63.62400 ;
    END
  END wdata[299]
  PIN wdata[300]
    DIRECTION INPUT ;
    USE SIGNAL ;
    PORT
      LAYER M4 ;
      RECT 0.00000 63.64800 0.03600 63.67200 ;
    END
  END wdata[300]
  PIN wdata[301]
    DIRECTION INPUT ;
    USE SIGNAL ;
    PORT
      LAYER M4 ;
      RECT 0.00000 63.69600 0.03600 63.72000 ;
    END
  END wdata[301]
  PIN wdata[302]
    DIRECTION INPUT ;
    USE SIGNAL ;
    PORT
      LAYER M4 ;
      RECT 0.00000 63.74400 0.03600 63.76800 ;
    END
  END wdata[302]
  PIN wdata[303]
    DIRECTION INPUT ;
    USE SIGNAL ;
    PORT
      LAYER M4 ;
      RECT 0.00000 63.79200 0.03600 63.81600 ;
    END
  END wdata[303]
  PIN wdata[304]
    DIRECTION INPUT ;
    USE SIGNAL ;
    PORT
      LAYER M4 ;
      RECT 0.00000 63.84000 0.03600 63.86400 ;
    END
  END wdata[304]
  PIN wdata[305]
    DIRECTION INPUT ;
    USE SIGNAL ;
    PORT
      LAYER M4 ;
      RECT 0.00000 63.88800 0.03600 63.91200 ;
    END
  END wdata[305]
  PIN wdata[306]
    DIRECTION INPUT ;
    USE SIGNAL ;
    PORT
      LAYER M4 ;
      RECT 0.00000 63.93600 0.03600 63.96000 ;
    END
  END wdata[306]
  PIN wdata[307]
    DIRECTION INPUT ;
    USE SIGNAL ;
    PORT
      LAYER M4 ;
      RECT 0.00000 63.98400 0.03600 64.00800 ;
    END
  END wdata[307]
  PIN wdata[308]
    DIRECTION INPUT ;
    USE SIGNAL ;
    PORT
      LAYER M4 ;
      RECT 0.00000 64.03200 0.03600 64.05600 ;
    END
  END wdata[308]
  PIN wdata[309]
    DIRECTION INPUT ;
    USE SIGNAL ;
    PORT
      LAYER M4 ;
      RECT 0.00000 64.08000 0.03600 64.10400 ;
    END
  END wdata[309]
  PIN wdata[310]
    DIRECTION INPUT ;
    USE SIGNAL ;
    PORT
      LAYER M4 ;
      RECT 0.00000 64.12800 0.03600 64.15200 ;
    END
  END wdata[310]
  PIN wdata[311]
    DIRECTION INPUT ;
    USE SIGNAL ;
    PORT
      LAYER M4 ;
      RECT 0.00000 64.17600 0.03600 64.20000 ;
    END
  END wdata[311]
  PIN wdata[312]
    DIRECTION INPUT ;
    USE SIGNAL ;
    PORT
      LAYER M4 ;
      RECT 0.00000 64.22400 0.03600 64.24800 ;
    END
  END wdata[312]
  PIN wdata[313]
    DIRECTION INPUT ;
    USE SIGNAL ;
    PORT
      LAYER M4 ;
      RECT 0.00000 64.27200 0.03600 64.29600 ;
    END
  END wdata[313]
  PIN wdata[314]
    DIRECTION INPUT ;
    USE SIGNAL ;
    PORT
      LAYER M4 ;
      RECT 0.00000 64.32000 0.03600 64.34400 ;
    END
  END wdata[314]
  PIN wdata[315]
    DIRECTION INPUT ;
    USE SIGNAL ;
    PORT
      LAYER M4 ;
      RECT 0.00000 64.36800 0.03600 64.39200 ;
    END
  END wdata[315]
  PIN wdata[316]
    DIRECTION INPUT ;
    USE SIGNAL ;
    PORT
      LAYER M4 ;
      RECT 0.00000 64.41600 0.03600 64.44000 ;
    END
  END wdata[316]
  PIN wdata[317]
    DIRECTION INPUT ;
    USE SIGNAL ;
    PORT
      LAYER M4 ;
      RECT 0.00000 64.46400 0.03600 64.48800 ;
    END
  END wdata[317]
  PIN wdata[318]
    DIRECTION INPUT ;
    USE SIGNAL ;
    PORT
      LAYER M4 ;
      RECT 0.00000 64.51200 0.03600 64.53600 ;
    END
  END wdata[318]
  PIN wdata[319]
    DIRECTION INPUT ;
    USE SIGNAL ;
    PORT
      LAYER M4 ;
      RECT 0.00000 64.56000 0.03600 64.58400 ;
    END
  END wdata[319]
  PIN wdata[320]
    DIRECTION INPUT ;
    USE SIGNAL ;
    PORT
      LAYER M4 ;
      RECT 0.00000 64.60800 0.03600 64.63200 ;
    END
  END wdata[320]
  PIN wdata[321]
    DIRECTION INPUT ;
    USE SIGNAL ;
    PORT
      LAYER M4 ;
      RECT 0.00000 64.65600 0.03600 64.68000 ;
    END
  END wdata[321]
  PIN wdata[322]
    DIRECTION INPUT ;
    USE SIGNAL ;
    PORT
      LAYER M4 ;
      RECT 0.00000 64.70400 0.03600 64.72800 ;
    END
  END wdata[322]
  PIN wdata[323]
    DIRECTION INPUT ;
    USE SIGNAL ;
    PORT
      LAYER M4 ;
      RECT 0.00000 64.75200 0.03600 64.77600 ;
    END
  END wdata[323]
  PIN wdata[324]
    DIRECTION INPUT ;
    USE SIGNAL ;
    PORT
      LAYER M4 ;
      RECT 0.00000 64.80000 0.03600 64.82400 ;
    END
  END wdata[324]
  PIN wdata[325]
    DIRECTION INPUT ;
    USE SIGNAL ;
    PORT
      LAYER M4 ;
      RECT 0.00000 64.84800 0.03600 64.87200 ;
    END
  END wdata[325]
  PIN wdata[326]
    DIRECTION INPUT ;
    USE SIGNAL ;
    PORT
      LAYER M4 ;
      RECT 0.00000 64.89600 0.03600 64.92000 ;
    END
  END wdata[326]
  PIN wdata[327]
    DIRECTION INPUT ;
    USE SIGNAL ;
    PORT
      LAYER M4 ;
      RECT 0.00000 64.94400 0.03600 64.96800 ;
    END
  END wdata[327]
  PIN wdata[328]
    DIRECTION INPUT ;
    USE SIGNAL ;
    PORT
      LAYER M4 ;
      RECT 0.00000 64.99200 0.03600 65.01600 ;
    END
  END wdata[328]
  PIN wdata[329]
    DIRECTION INPUT ;
    USE SIGNAL ;
    PORT
      LAYER M4 ;
      RECT 0.00000 65.04000 0.03600 65.06400 ;
    END
  END wdata[329]
  PIN wdata[330]
    DIRECTION INPUT ;
    USE SIGNAL ;
    PORT
      LAYER M4 ;
      RECT 0.00000 65.08800 0.03600 65.11200 ;
    END
  END wdata[330]
  PIN wdata[331]
    DIRECTION INPUT ;
    USE SIGNAL ;
    PORT
      LAYER M4 ;
      RECT 0.00000 65.13600 0.03600 65.16000 ;
    END
  END wdata[331]
  PIN wdata[332]
    DIRECTION INPUT ;
    USE SIGNAL ;
    PORT
      LAYER M4 ;
      RECT 0.00000 65.18400 0.03600 65.20800 ;
    END
  END wdata[332]
  PIN wdata[333]
    DIRECTION INPUT ;
    USE SIGNAL ;
    PORT
      LAYER M4 ;
      RECT 0.00000 65.23200 0.03600 65.25600 ;
    END
  END wdata[333]
  PIN wdata[334]
    DIRECTION INPUT ;
    USE SIGNAL ;
    PORT
      LAYER M4 ;
      RECT 0.00000 65.28000 0.03600 65.30400 ;
    END
  END wdata[334]
  PIN wdata[335]
    DIRECTION INPUT ;
    USE SIGNAL ;
    PORT
      LAYER M4 ;
      RECT 0.00000 65.32800 0.03600 65.35200 ;
    END
  END wdata[335]
  PIN wdata[336]
    DIRECTION INPUT ;
    USE SIGNAL ;
    PORT
      LAYER M4 ;
      RECT 0.00000 65.37600 0.03600 65.40000 ;
    END
  END wdata[336]
  PIN wdata[337]
    DIRECTION INPUT ;
    USE SIGNAL ;
    PORT
      LAYER M4 ;
      RECT 0.00000 65.42400 0.03600 65.44800 ;
    END
  END wdata[337]
  PIN wdata[338]
    DIRECTION INPUT ;
    USE SIGNAL ;
    PORT
      LAYER M4 ;
      RECT 0.00000 65.47200 0.03600 65.49600 ;
    END
  END wdata[338]
  PIN wdata[339]
    DIRECTION INPUT ;
    USE SIGNAL ;
    PORT
      LAYER M4 ;
      RECT 0.00000 65.52000 0.03600 65.54400 ;
    END
  END wdata[339]
  PIN wdata[340]
    DIRECTION INPUT ;
    USE SIGNAL ;
    PORT
      LAYER M4 ;
      RECT 0.00000 65.56800 0.03600 65.59200 ;
    END
  END wdata[340]
  PIN wdata[341]
    DIRECTION INPUT ;
    USE SIGNAL ;
    PORT
      LAYER M4 ;
      RECT 0.00000 65.61600 0.03600 65.64000 ;
    END
  END wdata[341]
  PIN wdata[342]
    DIRECTION INPUT ;
    USE SIGNAL ;
    PORT
      LAYER M4 ;
      RECT 0.00000 65.66400 0.03600 65.68800 ;
    END
  END wdata[342]
  PIN wdata[343]
    DIRECTION INPUT ;
    USE SIGNAL ;
    PORT
      LAYER M4 ;
      RECT 0.00000 65.71200 0.03600 65.73600 ;
    END
  END wdata[343]
  PIN wdata[344]
    DIRECTION INPUT ;
    USE SIGNAL ;
    PORT
      LAYER M4 ;
      RECT 0.00000 65.76000 0.03600 65.78400 ;
    END
  END wdata[344]
  PIN wdata[345]
    DIRECTION INPUT ;
    USE SIGNAL ;
    PORT
      LAYER M4 ;
      RECT 0.00000 65.80800 0.03600 65.83200 ;
    END
  END wdata[345]
  PIN wdata[346]
    DIRECTION INPUT ;
    USE SIGNAL ;
    PORT
      LAYER M4 ;
      RECT 0.00000 65.85600 0.03600 65.88000 ;
    END
  END wdata[346]
  PIN wdata[347]
    DIRECTION INPUT ;
    USE SIGNAL ;
    PORT
      LAYER M4 ;
      RECT 0.00000 65.90400 0.03600 65.92800 ;
    END
  END wdata[347]
  PIN wdata[348]
    DIRECTION INPUT ;
    USE SIGNAL ;
    PORT
      LAYER M4 ;
      RECT 0.00000 65.95200 0.03600 65.97600 ;
    END
  END wdata[348]
  PIN wdata[349]
    DIRECTION INPUT ;
    USE SIGNAL ;
    PORT
      LAYER M4 ;
      RECT 0.00000 66.00000 0.03600 66.02400 ;
    END
  END wdata[349]
  PIN wdata[350]
    DIRECTION INPUT ;
    USE SIGNAL ;
    PORT
      LAYER M4 ;
      RECT 0.00000 66.04800 0.03600 66.07200 ;
    END
  END wdata[350]
  PIN wdata[351]
    DIRECTION INPUT ;
    USE SIGNAL ;
    PORT
      LAYER M4 ;
      RECT 0.00000 66.09600 0.03600 66.12000 ;
    END
  END wdata[351]
  PIN wdata[352]
    DIRECTION INPUT ;
    USE SIGNAL ;
    PORT
      LAYER M4 ;
      RECT 0.00000 66.14400 0.03600 66.16800 ;
    END
  END wdata[352]
  PIN wdata[353]
    DIRECTION INPUT ;
    USE SIGNAL ;
    PORT
      LAYER M4 ;
      RECT 0.00000 66.19200 0.03600 66.21600 ;
    END
  END wdata[353]
  PIN wdata[354]
    DIRECTION INPUT ;
    USE SIGNAL ;
    PORT
      LAYER M4 ;
      RECT 0.00000 66.24000 0.03600 66.26400 ;
    END
  END wdata[354]
  PIN wdata[355]
    DIRECTION INPUT ;
    USE SIGNAL ;
    PORT
      LAYER M4 ;
      RECT 0.00000 66.28800 0.03600 66.31200 ;
    END
  END wdata[355]
  PIN wdata[356]
    DIRECTION INPUT ;
    USE SIGNAL ;
    PORT
      LAYER M4 ;
      RECT 0.00000 66.33600 0.03600 66.36000 ;
    END
  END wdata[356]
  PIN wdata[357]
    DIRECTION INPUT ;
    USE SIGNAL ;
    PORT
      LAYER M4 ;
      RECT 0.00000 66.38400 0.03600 66.40800 ;
    END
  END wdata[357]
  PIN wdata[358]
    DIRECTION INPUT ;
    USE SIGNAL ;
    PORT
      LAYER M4 ;
      RECT 0.00000 66.43200 0.03600 66.45600 ;
    END
  END wdata[358]
  PIN wdata[359]
    DIRECTION INPUT ;
    USE SIGNAL ;
    PORT
      LAYER M4 ;
      RECT 0.00000 66.48000 0.03600 66.50400 ;
    END
  END wdata[359]
  PIN wdata[360]
    DIRECTION INPUT ;
    USE SIGNAL ;
    PORT
      LAYER M4 ;
      RECT 0.00000 66.52800 0.03600 66.55200 ;
    END
  END wdata[360]
  PIN wdata[361]
    DIRECTION INPUT ;
    USE SIGNAL ;
    PORT
      LAYER M4 ;
      RECT 0.00000 66.57600 0.03600 66.60000 ;
    END
  END wdata[361]
  PIN wdata[362]
    DIRECTION INPUT ;
    USE SIGNAL ;
    PORT
      LAYER M4 ;
      RECT 0.00000 66.62400 0.03600 66.64800 ;
    END
  END wdata[362]
  PIN wdata[363]
    DIRECTION INPUT ;
    USE SIGNAL ;
    PORT
      LAYER M4 ;
      RECT 0.00000 66.67200 0.03600 66.69600 ;
    END
  END wdata[363]
  PIN wdata[364]
    DIRECTION INPUT ;
    USE SIGNAL ;
    PORT
      LAYER M4 ;
      RECT 0.00000 66.72000 0.03600 66.74400 ;
    END
  END wdata[364]
  PIN wdata[365]
    DIRECTION INPUT ;
    USE SIGNAL ;
    PORT
      LAYER M4 ;
      RECT 0.00000 66.76800 0.03600 66.79200 ;
    END
  END wdata[365]
  PIN wdata[366]
    DIRECTION INPUT ;
    USE SIGNAL ;
    PORT
      LAYER M4 ;
      RECT 0.00000 66.81600 0.03600 66.84000 ;
    END
  END wdata[366]
  PIN wdata[367]
    DIRECTION INPUT ;
    USE SIGNAL ;
    PORT
      LAYER M4 ;
      RECT 0.00000 66.86400 0.03600 66.88800 ;
    END
  END wdata[367]
  PIN wdata[368]
    DIRECTION INPUT ;
    USE SIGNAL ;
    PORT
      LAYER M4 ;
      RECT 0.00000 66.91200 0.03600 66.93600 ;
    END
  END wdata[368]
  PIN wdata[369]
    DIRECTION INPUT ;
    USE SIGNAL ;
    PORT
      LAYER M4 ;
      RECT 0.00000 66.96000 0.03600 66.98400 ;
    END
  END wdata[369]
  PIN wdata[370]
    DIRECTION INPUT ;
    USE SIGNAL ;
    PORT
      LAYER M4 ;
      RECT 0.00000 67.00800 0.03600 67.03200 ;
    END
  END wdata[370]
  PIN wdata[371]
    DIRECTION INPUT ;
    USE SIGNAL ;
    PORT
      LAYER M4 ;
      RECT 0.00000 67.05600 0.03600 67.08000 ;
    END
  END wdata[371]
  PIN wdata[372]
    DIRECTION INPUT ;
    USE SIGNAL ;
    PORT
      LAYER M4 ;
      RECT 0.00000 67.10400 0.03600 67.12800 ;
    END
  END wdata[372]
  PIN wdata[373]
    DIRECTION INPUT ;
    USE SIGNAL ;
    PORT
      LAYER M4 ;
      RECT 0.00000 67.15200 0.03600 67.17600 ;
    END
  END wdata[373]
  PIN wdata[374]
    DIRECTION INPUT ;
    USE SIGNAL ;
    PORT
      LAYER M4 ;
      RECT 0.00000 67.20000 0.03600 67.22400 ;
    END
  END wdata[374]
  PIN wdata[375]
    DIRECTION INPUT ;
    USE SIGNAL ;
    PORT
      LAYER M4 ;
      RECT 0.00000 67.24800 0.03600 67.27200 ;
    END
  END wdata[375]
  PIN wdata[376]
    DIRECTION INPUT ;
    USE SIGNAL ;
    PORT
      LAYER M4 ;
      RECT 0.00000 67.29600 0.03600 67.32000 ;
    END
  END wdata[376]
  PIN wdata[377]
    DIRECTION INPUT ;
    USE SIGNAL ;
    PORT
      LAYER M4 ;
      RECT 0.00000 67.34400 0.03600 67.36800 ;
    END
  END wdata[377]
  PIN wdata[378]
    DIRECTION INPUT ;
    USE SIGNAL ;
    PORT
      LAYER M4 ;
      RECT 0.00000 67.39200 0.03600 67.41600 ;
    END
  END wdata[378]
  PIN wdata[379]
    DIRECTION INPUT ;
    USE SIGNAL ;
    PORT
      LAYER M4 ;
      RECT 0.00000 67.44000 0.03600 67.46400 ;
    END
  END wdata[379]
  PIN wdata[380]
    DIRECTION INPUT ;
    USE SIGNAL ;
    PORT
      LAYER M4 ;
      RECT 0.00000 67.48800 0.03600 67.51200 ;
    END
  END wdata[380]
  PIN wdata[381]
    DIRECTION INPUT ;
    USE SIGNAL ;
    PORT
      LAYER M4 ;
      RECT 0.00000 67.53600 0.03600 67.56000 ;
    END
  END wdata[381]
  PIN wdata[382]
    DIRECTION INPUT ;
    USE SIGNAL ;
    PORT
      LAYER M4 ;
      RECT 0.00000 67.58400 0.03600 67.60800 ;
    END
  END wdata[382]
  PIN wdata[383]
    DIRECTION INPUT ;
    USE SIGNAL ;
    PORT
      LAYER M4 ;
      RECT 0.00000 67.63200 0.03600 67.65600 ;
    END
  END wdata[383]
  PIN wdata[384]
    DIRECTION INPUT ;
    USE SIGNAL ;
    PORT
      LAYER M4 ;
      RECT 0.00000 67.68000 0.03600 67.70400 ;
    END
  END wdata[384]
  PIN wdata[385]
    DIRECTION INPUT ;
    USE SIGNAL ;
    PORT
      LAYER M4 ;
      RECT 0.00000 67.72800 0.03600 67.75200 ;
    END
  END wdata[385]
  PIN wdata[386]
    DIRECTION INPUT ;
    USE SIGNAL ;
    PORT
      LAYER M4 ;
      RECT 0.00000 67.77600 0.03600 67.80000 ;
    END
  END wdata[386]
  PIN wdata[387]
    DIRECTION INPUT ;
    USE SIGNAL ;
    PORT
      LAYER M4 ;
      RECT 0.00000 67.82400 0.03600 67.84800 ;
    END
  END wdata[387]
  PIN wdata[388]
    DIRECTION INPUT ;
    USE SIGNAL ;
    PORT
      LAYER M4 ;
      RECT 0.00000 67.87200 0.03600 67.89600 ;
    END
  END wdata[388]
  PIN wdata[389]
    DIRECTION INPUT ;
    USE SIGNAL ;
    PORT
      LAYER M4 ;
      RECT 0.00000 67.92000 0.03600 67.94400 ;
    END
  END wdata[389]
  PIN wdata[390]
    DIRECTION INPUT ;
    USE SIGNAL ;
    PORT
      LAYER M4 ;
      RECT 0.00000 67.96800 0.03600 67.99200 ;
    END
  END wdata[390]
  PIN wdata[391]
    DIRECTION INPUT ;
    USE SIGNAL ;
    PORT
      LAYER M4 ;
      RECT 0.00000 68.01600 0.03600 68.04000 ;
    END
  END wdata[391]
  PIN wdata[392]
    DIRECTION INPUT ;
    USE SIGNAL ;
    PORT
      LAYER M4 ;
      RECT 0.00000 68.06400 0.03600 68.08800 ;
    END
  END wdata[392]
  PIN wdata[393]
    DIRECTION INPUT ;
    USE SIGNAL ;
    PORT
      LAYER M4 ;
      RECT 0.00000 68.11200 0.03600 68.13600 ;
    END
  END wdata[393]
  PIN wdata[394]
    DIRECTION INPUT ;
    USE SIGNAL ;
    PORT
      LAYER M4 ;
      RECT 0.00000 68.16000 0.03600 68.18400 ;
    END
  END wdata[394]
  PIN wdata[395]
    DIRECTION INPUT ;
    USE SIGNAL ;
    PORT
      LAYER M4 ;
      RECT 0.00000 68.20800 0.03600 68.23200 ;
    END
  END wdata[395]
  PIN wdata[396]
    DIRECTION INPUT ;
    USE SIGNAL ;
    PORT
      LAYER M4 ;
      RECT 0.00000 68.25600 0.03600 68.28000 ;
    END
  END wdata[396]
  PIN wdata[397]
    DIRECTION INPUT ;
    USE SIGNAL ;
    PORT
      LAYER M4 ;
      RECT 0.00000 68.30400 0.03600 68.32800 ;
    END
  END wdata[397]
  PIN wdata[398]
    DIRECTION INPUT ;
    USE SIGNAL ;
    PORT
      LAYER M4 ;
      RECT 0.00000 68.35200 0.03600 68.37600 ;
    END
  END wdata[398]
  PIN wdata[399]
    DIRECTION INPUT ;
    USE SIGNAL ;
    PORT
      LAYER M4 ;
      RECT 0.00000 68.40000 0.03600 68.42400 ;
    END
  END wdata[399]
  PIN wdata[400]
    DIRECTION INPUT ;
    USE SIGNAL ;
    PORT
      LAYER M4 ;
      RECT 0.00000 68.44800 0.03600 68.47200 ;
    END
  END wdata[400]
  PIN wdata[401]
    DIRECTION INPUT ;
    USE SIGNAL ;
    PORT
      LAYER M4 ;
      RECT 0.00000 68.49600 0.03600 68.52000 ;
    END
  END wdata[401]
  PIN wdata[402]
    DIRECTION INPUT ;
    USE SIGNAL ;
    PORT
      LAYER M4 ;
      RECT 0.00000 68.54400 0.03600 68.56800 ;
    END
  END wdata[402]
  PIN wdata[403]
    DIRECTION INPUT ;
    USE SIGNAL ;
    PORT
      LAYER M4 ;
      RECT 0.00000 68.59200 0.03600 68.61600 ;
    END
  END wdata[403]
  PIN wdata[404]
    DIRECTION INPUT ;
    USE SIGNAL ;
    PORT
      LAYER M4 ;
      RECT 0.00000 68.64000 0.03600 68.66400 ;
    END
  END wdata[404]
  PIN wdata[405]
    DIRECTION INPUT ;
    USE SIGNAL ;
    PORT
      LAYER M4 ;
      RECT 0.00000 68.68800 0.03600 68.71200 ;
    END
  END wdata[405]
  PIN wdata[406]
    DIRECTION INPUT ;
    USE SIGNAL ;
    PORT
      LAYER M4 ;
      RECT 0.00000 68.73600 0.03600 68.76000 ;
    END
  END wdata[406]
  PIN wdata[407]
    DIRECTION INPUT ;
    USE SIGNAL ;
    PORT
      LAYER M4 ;
      RECT 0.00000 68.78400 0.03600 68.80800 ;
    END
  END wdata[407]
  PIN wdata[408]
    DIRECTION INPUT ;
    USE SIGNAL ;
    PORT
      LAYER M4 ;
      RECT 0.00000 68.83200 0.03600 68.85600 ;
    END
  END wdata[408]
  PIN wdata[409]
    DIRECTION INPUT ;
    USE SIGNAL ;
    PORT
      LAYER M4 ;
      RECT 0.00000 68.88000 0.03600 68.90400 ;
    END
  END wdata[409]
  PIN wdata[410]
    DIRECTION INPUT ;
    USE SIGNAL ;
    PORT
      LAYER M4 ;
      RECT 0.00000 68.92800 0.03600 68.95200 ;
    END
  END wdata[410]
  PIN wdata[411]
    DIRECTION INPUT ;
    USE SIGNAL ;
    PORT
      LAYER M4 ;
      RECT 0.00000 68.97600 0.03600 69.00000 ;
    END
  END wdata[411]
  PIN wdata[412]
    DIRECTION INPUT ;
    USE SIGNAL ;
    PORT
      LAYER M4 ;
      RECT 0.00000 69.02400 0.03600 69.04800 ;
    END
  END wdata[412]
  PIN wdata[413]
    DIRECTION INPUT ;
    USE SIGNAL ;
    PORT
      LAYER M4 ;
      RECT 0.00000 69.07200 0.03600 69.09600 ;
    END
  END wdata[413]
  PIN wdata[414]
    DIRECTION INPUT ;
    USE SIGNAL ;
    PORT
      LAYER M4 ;
      RECT 0.00000 69.12000 0.03600 69.14400 ;
    END
  END wdata[414]
  PIN wdata[415]
    DIRECTION INPUT ;
    USE SIGNAL ;
    PORT
      LAYER M4 ;
      RECT 0.00000 69.16800 0.03600 69.19200 ;
    END
  END wdata[415]
  PIN wdata[416]
    DIRECTION INPUT ;
    USE SIGNAL ;
    PORT
      LAYER M4 ;
      RECT 0.00000 69.21600 0.03600 69.24000 ;
    END
  END wdata[416]
  PIN wdata[417]
    DIRECTION INPUT ;
    USE SIGNAL ;
    PORT
      LAYER M4 ;
      RECT 0.00000 69.26400 0.03600 69.28800 ;
    END
  END wdata[417]
  PIN wdata[418]
    DIRECTION INPUT ;
    USE SIGNAL ;
    PORT
      LAYER M4 ;
      RECT 0.00000 69.31200 0.03600 69.33600 ;
    END
  END wdata[418]
  PIN wdata[419]
    DIRECTION INPUT ;
    USE SIGNAL ;
    PORT
      LAYER M4 ;
      RECT 0.00000 69.36000 0.03600 69.38400 ;
    END
  END wdata[419]
  PIN wdata[420]
    DIRECTION INPUT ;
    USE SIGNAL ;
    PORT
      LAYER M4 ;
      RECT 0.00000 69.40800 0.03600 69.43200 ;
    END
  END wdata[420]
  PIN wdata[421]
    DIRECTION INPUT ;
    USE SIGNAL ;
    PORT
      LAYER M4 ;
      RECT 0.00000 69.45600 0.03600 69.48000 ;
    END
  END wdata[421]
  PIN wdata[422]
    DIRECTION INPUT ;
    USE SIGNAL ;
    PORT
      LAYER M4 ;
      RECT 0.00000 69.50400 0.03600 69.52800 ;
    END
  END wdata[422]
  PIN wdata[423]
    DIRECTION INPUT ;
    USE SIGNAL ;
    PORT
      LAYER M4 ;
      RECT 0.00000 69.55200 0.03600 69.57600 ;
    END
  END wdata[423]
  PIN wdata[424]
    DIRECTION INPUT ;
    USE SIGNAL ;
    PORT
      LAYER M4 ;
      RECT 0.00000 69.60000 0.03600 69.62400 ;
    END
  END wdata[424]
  PIN wdata[425]
    DIRECTION INPUT ;
    USE SIGNAL ;
    PORT
      LAYER M4 ;
      RECT 0.00000 69.64800 0.03600 69.67200 ;
    END
  END wdata[425]
  PIN wdata[426]
    DIRECTION INPUT ;
    USE SIGNAL ;
    PORT
      LAYER M4 ;
      RECT 0.00000 69.69600 0.03600 69.72000 ;
    END
  END wdata[426]
  PIN wdata[427]
    DIRECTION INPUT ;
    USE SIGNAL ;
    PORT
      LAYER M4 ;
      RECT 0.00000 69.74400 0.03600 69.76800 ;
    END
  END wdata[427]
  PIN wdata[428]
    DIRECTION INPUT ;
    USE SIGNAL ;
    PORT
      LAYER M4 ;
      RECT 0.00000 69.79200 0.03600 69.81600 ;
    END
  END wdata[428]
  PIN wdata[429]
    DIRECTION INPUT ;
    USE SIGNAL ;
    PORT
      LAYER M4 ;
      RECT 0.00000 69.84000 0.03600 69.86400 ;
    END
  END wdata[429]
  PIN wdata[430]
    DIRECTION INPUT ;
    USE SIGNAL ;
    PORT
      LAYER M4 ;
      RECT 0.00000 69.88800 0.03600 69.91200 ;
    END
  END wdata[430]
  PIN wdata[431]
    DIRECTION INPUT ;
    USE SIGNAL ;
    PORT
      LAYER M4 ;
      RECT 0.00000 69.93600 0.03600 69.96000 ;
    END
  END wdata[431]
  PIN wdata[432]
    DIRECTION INPUT ;
    USE SIGNAL ;
    PORT
      LAYER M4 ;
      RECT 0.00000 69.98400 0.03600 70.00800 ;
    END
  END wdata[432]
  PIN wdata[433]
    DIRECTION INPUT ;
    USE SIGNAL ;
    PORT
      LAYER M4 ;
      RECT 0.00000 70.03200 0.03600 70.05600 ;
    END
  END wdata[433]
  PIN wdata[434]
    DIRECTION INPUT ;
    USE SIGNAL ;
    PORT
      LAYER M4 ;
      RECT 0.00000 70.08000 0.03600 70.10400 ;
    END
  END wdata[434]
  PIN wdata[435]
    DIRECTION INPUT ;
    USE SIGNAL ;
    PORT
      LAYER M4 ;
      RECT 0.00000 70.12800 0.03600 70.15200 ;
    END
  END wdata[435]
  PIN wdata[436]
    DIRECTION INPUT ;
    USE SIGNAL ;
    PORT
      LAYER M4 ;
      RECT 0.00000 70.17600 0.03600 70.20000 ;
    END
  END wdata[436]
  PIN wdata[437]
    DIRECTION INPUT ;
    USE SIGNAL ;
    PORT
      LAYER M4 ;
      RECT 0.00000 70.22400 0.03600 70.24800 ;
    END
  END wdata[437]
  PIN wdata[438]
    DIRECTION INPUT ;
    USE SIGNAL ;
    PORT
      LAYER M4 ;
      RECT 0.00000 70.27200 0.03600 70.29600 ;
    END
  END wdata[438]
  PIN wdata[439]
    DIRECTION INPUT ;
    USE SIGNAL ;
    PORT
      LAYER M4 ;
      RECT 0.00000 70.32000 0.03600 70.34400 ;
    END
  END wdata[439]
  PIN wdata[440]
    DIRECTION INPUT ;
    USE SIGNAL ;
    PORT
      LAYER M4 ;
      RECT 0.00000 70.36800 0.03600 70.39200 ;
    END
  END wdata[440]
  PIN wdata[441]
    DIRECTION INPUT ;
    USE SIGNAL ;
    PORT
      LAYER M4 ;
      RECT 0.00000 70.41600 0.03600 70.44000 ;
    END
  END wdata[441]
  PIN wdata[442]
    DIRECTION INPUT ;
    USE SIGNAL ;
    PORT
      LAYER M4 ;
      RECT 0.00000 70.46400 0.03600 70.48800 ;
    END
  END wdata[442]
  PIN wdata[443]
    DIRECTION INPUT ;
    USE SIGNAL ;
    PORT
      LAYER M4 ;
      RECT 0.00000 70.51200 0.03600 70.53600 ;
    END
  END wdata[443]
  PIN wdata[444]
    DIRECTION INPUT ;
    USE SIGNAL ;
    PORT
      LAYER M4 ;
      RECT 0.00000 70.56000 0.03600 70.58400 ;
    END
  END wdata[444]
  PIN wdata[445]
    DIRECTION INPUT ;
    USE SIGNAL ;
    PORT
      LAYER M4 ;
      RECT 0.00000 70.60800 0.03600 70.63200 ;
    END
  END wdata[445]
  PIN wdata[446]
    DIRECTION INPUT ;
    USE SIGNAL ;
    PORT
      LAYER M4 ;
      RECT 0.00000 70.65600 0.03600 70.68000 ;
    END
  END wdata[446]
  PIN wdata[447]
    DIRECTION INPUT ;
    USE SIGNAL ;
    PORT
      LAYER M4 ;
      RECT 0.00000 70.70400 0.03600 70.72800 ;
    END
  END wdata[447]
  PIN wdata[448]
    DIRECTION INPUT ;
    USE SIGNAL ;
    PORT
      LAYER M4 ;
      RECT 0.00000 70.75200 0.03600 70.77600 ;
    END
  END wdata[448]
  PIN wdata[449]
    DIRECTION INPUT ;
    USE SIGNAL ;
    PORT
      LAYER M4 ;
      RECT 0.00000 70.80000 0.03600 70.82400 ;
    END
  END wdata[449]
  PIN wdata[450]
    DIRECTION INPUT ;
    USE SIGNAL ;
    PORT
      LAYER M4 ;
      RECT 0.00000 70.84800 0.03600 70.87200 ;
    END
  END wdata[450]
  PIN wdata[451]
    DIRECTION INPUT ;
    USE SIGNAL ;
    PORT
      LAYER M4 ;
      RECT 0.00000 70.89600 0.03600 70.92000 ;
    END
  END wdata[451]
  PIN wdata[452]
    DIRECTION INPUT ;
    USE SIGNAL ;
    PORT
      LAYER M4 ;
      RECT 0.00000 70.94400 0.03600 70.96800 ;
    END
  END wdata[452]
  PIN wdata[453]
    DIRECTION INPUT ;
    USE SIGNAL ;
    PORT
      LAYER M4 ;
      RECT 0.00000 70.99200 0.03600 71.01600 ;
    END
  END wdata[453]
  PIN wdata[454]
    DIRECTION INPUT ;
    USE SIGNAL ;
    PORT
      LAYER M4 ;
      RECT 0.00000 71.04000 0.03600 71.06400 ;
    END
  END wdata[454]
  PIN wdata[455]
    DIRECTION INPUT ;
    USE SIGNAL ;
    PORT
      LAYER M4 ;
      RECT 0.00000 71.08800 0.03600 71.11200 ;
    END
  END wdata[455]
  PIN wdata[456]
    DIRECTION INPUT ;
    USE SIGNAL ;
    PORT
      LAYER M4 ;
      RECT 0.00000 71.13600 0.03600 71.16000 ;
    END
  END wdata[456]
  PIN wdata[457]
    DIRECTION INPUT ;
    USE SIGNAL ;
    PORT
      LAYER M4 ;
      RECT 0.00000 71.18400 0.03600 71.20800 ;
    END
  END wdata[457]
  PIN wdata[458]
    DIRECTION INPUT ;
    USE SIGNAL ;
    PORT
      LAYER M4 ;
      RECT 0.00000 71.23200 0.03600 71.25600 ;
    END
  END wdata[458]
  PIN wdata[459]
    DIRECTION INPUT ;
    USE SIGNAL ;
    PORT
      LAYER M4 ;
      RECT 0.00000 71.28000 0.03600 71.30400 ;
    END
  END wdata[459]
  PIN wdata[460]
    DIRECTION INPUT ;
    USE SIGNAL ;
    PORT
      LAYER M4 ;
      RECT 0.00000 71.32800 0.03600 71.35200 ;
    END
  END wdata[460]
  PIN wdata[461]
    DIRECTION INPUT ;
    USE SIGNAL ;
    PORT
      LAYER M4 ;
      RECT 0.00000 71.37600 0.03600 71.40000 ;
    END
  END wdata[461]
  PIN wdata[462]
    DIRECTION INPUT ;
    USE SIGNAL ;
    PORT
      LAYER M4 ;
      RECT 0.00000 71.42400 0.03600 71.44800 ;
    END
  END wdata[462]
  PIN wdata[463]
    DIRECTION INPUT ;
    USE SIGNAL ;
    PORT
      LAYER M4 ;
      RECT 0.00000 71.47200 0.03600 71.49600 ;
    END
  END wdata[463]
  PIN wdata[464]
    DIRECTION INPUT ;
    USE SIGNAL ;
    PORT
      LAYER M4 ;
      RECT 0.00000 71.52000 0.03600 71.54400 ;
    END
  END wdata[464]
  PIN wdata[465]
    DIRECTION INPUT ;
    USE SIGNAL ;
    PORT
      LAYER M4 ;
      RECT 0.00000 71.56800 0.03600 71.59200 ;
    END
  END wdata[465]
  PIN wdata[466]
    DIRECTION INPUT ;
    USE SIGNAL ;
    PORT
      LAYER M4 ;
      RECT 0.00000 71.61600 0.03600 71.64000 ;
    END
  END wdata[466]
  PIN wdata[467]
    DIRECTION INPUT ;
    USE SIGNAL ;
    PORT
      LAYER M4 ;
      RECT 0.00000 71.66400 0.03600 71.68800 ;
    END
  END wdata[467]
  PIN wdata[468]
    DIRECTION INPUT ;
    USE SIGNAL ;
    PORT
      LAYER M4 ;
      RECT 0.00000 71.71200 0.03600 71.73600 ;
    END
  END wdata[468]
  PIN wdata[469]
    DIRECTION INPUT ;
    USE SIGNAL ;
    PORT
      LAYER M4 ;
      RECT 0.00000 71.76000 0.03600 71.78400 ;
    END
  END wdata[469]
  PIN wdata[470]
    DIRECTION INPUT ;
    USE SIGNAL ;
    PORT
      LAYER M4 ;
      RECT 0.00000 71.80800 0.03600 71.83200 ;
    END
  END wdata[470]
  PIN wdata[471]
    DIRECTION INPUT ;
    USE SIGNAL ;
    PORT
      LAYER M4 ;
      RECT 0.00000 71.85600 0.03600 71.88000 ;
    END
  END wdata[471]
  PIN wdata[472]
    DIRECTION INPUT ;
    USE SIGNAL ;
    PORT
      LAYER M4 ;
      RECT 0.00000 71.90400 0.03600 71.92800 ;
    END
  END wdata[472]
  PIN wdata[473]
    DIRECTION INPUT ;
    USE SIGNAL ;
    PORT
      LAYER M4 ;
      RECT 0.00000 71.95200 0.03600 71.97600 ;
    END
  END wdata[473]
  PIN wdata[474]
    DIRECTION INPUT ;
    USE SIGNAL ;
    PORT
      LAYER M4 ;
      RECT 0.00000 72.00000 0.03600 72.02400 ;
    END
  END wdata[474]
  PIN wdata[475]
    DIRECTION INPUT ;
    USE SIGNAL ;
    PORT
      LAYER M4 ;
      RECT 0.00000 72.04800 0.03600 72.07200 ;
    END
  END wdata[475]
  PIN wdata[476]
    DIRECTION INPUT ;
    USE SIGNAL ;
    PORT
      LAYER M4 ;
      RECT 0.00000 72.09600 0.03600 72.12000 ;
    END
  END wdata[476]
  PIN wdata[477]
    DIRECTION INPUT ;
    USE SIGNAL ;
    PORT
      LAYER M4 ;
      RECT 0.00000 72.14400 0.03600 72.16800 ;
    END
  END wdata[477]
  PIN wdata[478]
    DIRECTION INPUT ;
    USE SIGNAL ;
    PORT
      LAYER M4 ;
      RECT 0.00000 72.19200 0.03600 72.21600 ;
    END
  END wdata[478]
  PIN wdata[479]
    DIRECTION INPUT ;
    USE SIGNAL ;
    PORT
      LAYER M4 ;
      RECT 0.00000 72.24000 0.03600 72.26400 ;
    END
  END wdata[479]
  PIN wdata[480]
    DIRECTION INPUT ;
    USE SIGNAL ;
    PORT
      LAYER M4 ;
      RECT 0.00000 72.28800 0.03600 72.31200 ;
    END
  END wdata[480]
  PIN wdata[481]
    DIRECTION INPUT ;
    USE SIGNAL ;
    PORT
      LAYER M4 ;
      RECT 0.00000 72.33600 0.03600 72.36000 ;
    END
  END wdata[481]
  PIN wdata[482]
    DIRECTION INPUT ;
    USE SIGNAL ;
    PORT
      LAYER M4 ;
      RECT 0.00000 72.38400 0.03600 72.40800 ;
    END
  END wdata[482]
  PIN wdata[483]
    DIRECTION INPUT ;
    USE SIGNAL ;
    PORT
      LAYER M4 ;
      RECT 0.00000 72.43200 0.03600 72.45600 ;
    END
  END wdata[483]
  PIN wdata[484]
    DIRECTION INPUT ;
    USE SIGNAL ;
    PORT
      LAYER M4 ;
      RECT 0.00000 72.48000 0.03600 72.50400 ;
    END
  END wdata[484]
  PIN wdata[485]
    DIRECTION INPUT ;
    USE SIGNAL ;
    PORT
      LAYER M4 ;
      RECT 0.00000 72.52800 0.03600 72.55200 ;
    END
  END wdata[485]
  PIN wdata[486]
    DIRECTION INPUT ;
    USE SIGNAL ;
    PORT
      LAYER M4 ;
      RECT 0.00000 72.57600 0.03600 72.60000 ;
    END
  END wdata[486]
  PIN wdata[487]
    DIRECTION INPUT ;
    USE SIGNAL ;
    PORT
      LAYER M4 ;
      RECT 0.00000 72.62400 0.03600 72.64800 ;
    END
  END wdata[487]
  PIN wdata[488]
    DIRECTION INPUT ;
    USE SIGNAL ;
    PORT
      LAYER M4 ;
      RECT 0.00000 72.67200 0.03600 72.69600 ;
    END
  END wdata[488]
  PIN wdata[489]
    DIRECTION INPUT ;
    USE SIGNAL ;
    PORT
      LAYER M4 ;
      RECT 0.00000 72.72000 0.03600 72.74400 ;
    END
  END wdata[489]
  PIN wdata[490]
    DIRECTION INPUT ;
    USE SIGNAL ;
    PORT
      LAYER M4 ;
      RECT 0.00000 72.76800 0.03600 72.79200 ;
    END
  END wdata[490]
  PIN wdata[491]
    DIRECTION INPUT ;
    USE SIGNAL ;
    PORT
      LAYER M4 ;
      RECT 0.00000 72.81600 0.03600 72.84000 ;
    END
  END wdata[491]
  PIN wdata[492]
    DIRECTION INPUT ;
    USE SIGNAL ;
    PORT
      LAYER M4 ;
      RECT 0.00000 72.86400 0.03600 72.88800 ;
    END
  END wdata[492]
  PIN wdata[493]
    DIRECTION INPUT ;
    USE SIGNAL ;
    PORT
      LAYER M4 ;
      RECT 0.00000 72.91200 0.03600 72.93600 ;
    END
  END wdata[493]
  PIN wdata[494]
    DIRECTION INPUT ;
    USE SIGNAL ;
    PORT
      LAYER M4 ;
      RECT 0.00000 72.96000 0.03600 72.98400 ;
    END
  END wdata[494]
  PIN wdata[495]
    DIRECTION INPUT ;
    USE SIGNAL ;
    PORT
      LAYER M4 ;
      RECT 0.00000 73.00800 0.03600 73.03200 ;
    END
  END wdata[495]
  PIN wdata[496]
    DIRECTION INPUT ;
    USE SIGNAL ;
    PORT
      LAYER M4 ;
      RECT 0.00000 73.05600 0.03600 73.08000 ;
    END
  END wdata[496]
  PIN wdata[497]
    DIRECTION INPUT ;
    USE SIGNAL ;
    PORT
      LAYER M4 ;
      RECT 0.00000 73.10400 0.03600 73.12800 ;
    END
  END wdata[497]
  PIN wdata[498]
    DIRECTION INPUT ;
    USE SIGNAL ;
    PORT
      LAYER M4 ;
      RECT 0.00000 73.15200 0.03600 73.17600 ;
    END
  END wdata[498]
  PIN wdata[499]
    DIRECTION INPUT ;
    USE SIGNAL ;
    PORT
      LAYER M4 ;
      RECT 0.00000 73.20000 0.03600 73.22400 ;
    END
  END wdata[499]
  PIN wdata[500]
    DIRECTION INPUT ;
    USE SIGNAL ;
    PORT
      LAYER M4 ;
      RECT 0.00000 73.24800 0.03600 73.27200 ;
    END
  END wdata[500]
  PIN wdata[501]
    DIRECTION INPUT ;
    USE SIGNAL ;
    PORT
      LAYER M4 ;
      RECT 0.00000 73.29600 0.03600 73.32000 ;
    END
  END wdata[501]
  PIN wdata[502]
    DIRECTION INPUT ;
    USE SIGNAL ;
    PORT
      LAYER M4 ;
      RECT 0.00000 73.34400 0.03600 73.36800 ;
    END
  END wdata[502]
  PIN wdata[503]
    DIRECTION INPUT ;
    USE SIGNAL ;
    PORT
      LAYER M4 ;
      RECT 0.00000 73.39200 0.03600 73.41600 ;
    END
  END wdata[503]
  PIN wdata[504]
    DIRECTION INPUT ;
    USE SIGNAL ;
    PORT
      LAYER M4 ;
      RECT 0.00000 73.44000 0.03600 73.46400 ;
    END
  END wdata[504]
  PIN wdata[505]
    DIRECTION INPUT ;
    USE SIGNAL ;
    PORT
      LAYER M4 ;
      RECT 0.00000 73.48800 0.03600 73.51200 ;
    END
  END wdata[505]
  PIN wdata[506]
    DIRECTION INPUT ;
    USE SIGNAL ;
    PORT
      LAYER M4 ;
      RECT 0.00000 73.53600 0.03600 73.56000 ;
    END
  END wdata[506]
  PIN wdata[507]
    DIRECTION INPUT ;
    USE SIGNAL ;
    PORT
      LAYER M4 ;
      RECT 0.00000 73.58400 0.03600 73.60800 ;
    END
  END wdata[507]
  PIN wdata[508]
    DIRECTION INPUT ;
    USE SIGNAL ;
    PORT
      LAYER M4 ;
      RECT 0.00000 73.63200 0.03600 73.65600 ;
    END
  END wdata[508]
  PIN wdata[509]
    DIRECTION INPUT ;
    USE SIGNAL ;
    PORT
      LAYER M4 ;
      RECT 0.00000 73.68000 0.03600 73.70400 ;
    END
  END wdata[509]
  PIN wdata[510]
    DIRECTION INPUT ;
    USE SIGNAL ;
    PORT
      LAYER M4 ;
      RECT 0.00000 73.72800 0.03600 73.75200 ;
    END
  END wdata[510]
  PIN wdata[511]
    DIRECTION INPUT ;
    USE SIGNAL ;
    PORT
      LAYER M4 ;
      RECT 0.00000 73.77600 0.03600 73.80000 ;
    END
  END wdata[511]
  PIN wdata[512]
    DIRECTION INPUT ;
    USE SIGNAL ;
    PORT
      LAYER M4 ;
      RECT 0.00000 73.82400 0.03600 73.84800 ;
    END
  END wdata[512]
  PIN wdata[513]
    DIRECTION INPUT ;
    USE SIGNAL ;
    PORT
      LAYER M4 ;
      RECT 0.00000 73.87200 0.03600 73.89600 ;
    END
  END wdata[513]
  PIN wdata[514]
    DIRECTION INPUT ;
    USE SIGNAL ;
    PORT
      LAYER M4 ;
      RECT 0.00000 73.92000 0.03600 73.94400 ;
    END
  END wdata[514]
  PIN wdata[515]
    DIRECTION INPUT ;
    USE SIGNAL ;
    PORT
      LAYER M4 ;
      RECT 0.00000 73.96800 0.03600 73.99200 ;
    END
  END wdata[515]
  PIN wdata[516]
    DIRECTION INPUT ;
    USE SIGNAL ;
    PORT
      LAYER M4 ;
      RECT 0.00000 74.01600 0.03600 74.04000 ;
    END
  END wdata[516]
  PIN wdata[517]
    DIRECTION INPUT ;
    USE SIGNAL ;
    PORT
      LAYER M4 ;
      RECT 0.00000 74.06400 0.03600 74.08800 ;
    END
  END wdata[517]
  PIN wdata[518]
    DIRECTION INPUT ;
    USE SIGNAL ;
    PORT
      LAYER M4 ;
      RECT 0.00000 74.11200 0.03600 74.13600 ;
    END
  END wdata[518]
  PIN wdata[519]
    DIRECTION INPUT ;
    USE SIGNAL ;
    PORT
      LAYER M4 ;
      RECT 0.00000 74.16000 0.03600 74.18400 ;
    END
  END wdata[519]
  PIN wdata[520]
    DIRECTION INPUT ;
    USE SIGNAL ;
    PORT
      LAYER M4 ;
      RECT 0.00000 74.20800 0.03600 74.23200 ;
    END
  END wdata[520]
  PIN wdata[521]
    DIRECTION INPUT ;
    USE SIGNAL ;
    PORT
      LAYER M4 ;
      RECT 0.00000 74.25600 0.03600 74.28000 ;
    END
  END wdata[521]
  PIN wdata[522]
    DIRECTION INPUT ;
    USE SIGNAL ;
    PORT
      LAYER M4 ;
      RECT 0.00000 74.30400 0.03600 74.32800 ;
    END
  END wdata[522]
  PIN wdata[523]
    DIRECTION INPUT ;
    USE SIGNAL ;
    PORT
      LAYER M4 ;
      RECT 0.00000 74.35200 0.03600 74.37600 ;
    END
  END wdata[523]
  PIN wdata[524]
    DIRECTION INPUT ;
    USE SIGNAL ;
    PORT
      LAYER M4 ;
      RECT 0.00000 74.40000 0.03600 74.42400 ;
    END
  END wdata[524]
  PIN wdata[525]
    DIRECTION INPUT ;
    USE SIGNAL ;
    PORT
      LAYER M4 ;
      RECT 0.00000 74.44800 0.03600 74.47200 ;
    END
  END wdata[525]
  PIN wdata[526]
    DIRECTION INPUT ;
    USE SIGNAL ;
    PORT
      LAYER M4 ;
      RECT 0.00000 74.49600 0.03600 74.52000 ;
    END
  END wdata[526]
  PIN wdata[527]
    DIRECTION INPUT ;
    USE SIGNAL ;
    PORT
      LAYER M4 ;
      RECT 0.00000 74.54400 0.03600 74.56800 ;
    END
  END wdata[527]
  PIN wdata[528]
    DIRECTION INPUT ;
    USE SIGNAL ;
    PORT
      LAYER M4 ;
      RECT 0.00000 74.59200 0.03600 74.61600 ;
    END
  END wdata[528]
  PIN wdata[529]
    DIRECTION INPUT ;
    USE SIGNAL ;
    PORT
      LAYER M4 ;
      RECT 0.00000 74.64000 0.03600 74.66400 ;
    END
  END wdata[529]
  PIN wdata[530]
    DIRECTION INPUT ;
    USE SIGNAL ;
    PORT
      LAYER M4 ;
      RECT 0.00000 74.68800 0.03600 74.71200 ;
    END
  END wdata[530]
  PIN wdata[531]
    DIRECTION INPUT ;
    USE SIGNAL ;
    PORT
      LAYER M4 ;
      RECT 0.00000 74.73600 0.03600 74.76000 ;
    END
  END wdata[531]
  PIN wdata[532]
    DIRECTION INPUT ;
    USE SIGNAL ;
    PORT
      LAYER M4 ;
      RECT 0.00000 74.78400 0.03600 74.80800 ;
    END
  END wdata[532]
  PIN wdata[533]
    DIRECTION INPUT ;
    USE SIGNAL ;
    PORT
      LAYER M4 ;
      RECT 0.00000 74.83200 0.03600 74.85600 ;
    END
  END wdata[533]
  PIN wdata[534]
    DIRECTION INPUT ;
    USE SIGNAL ;
    PORT
      LAYER M4 ;
      RECT 0.00000 74.88000 0.03600 74.90400 ;
    END
  END wdata[534]
  PIN wdata[535]
    DIRECTION INPUT ;
    USE SIGNAL ;
    PORT
      LAYER M4 ;
      RECT 0.00000 74.92800 0.03600 74.95200 ;
    END
  END wdata[535]
  PIN wdata[536]
    DIRECTION INPUT ;
    USE SIGNAL ;
    PORT
      LAYER M4 ;
      RECT 0.00000 74.97600 0.03600 75.00000 ;
    END
  END wdata[536]
  PIN wdata[537]
    DIRECTION INPUT ;
    USE SIGNAL ;
    PORT
      LAYER M4 ;
      RECT 0.00000 75.02400 0.03600 75.04800 ;
    END
  END wdata[537]
  PIN wdata[538]
    DIRECTION INPUT ;
    USE SIGNAL ;
    PORT
      LAYER M4 ;
      RECT 0.00000 75.07200 0.03600 75.09600 ;
    END
  END wdata[538]
  PIN wdata[539]
    DIRECTION INPUT ;
    USE SIGNAL ;
    PORT
      LAYER M4 ;
      RECT 0.00000 75.12000 0.03600 75.14400 ;
    END
  END wdata[539]
  PIN wdata[540]
    DIRECTION INPUT ;
    USE SIGNAL ;
    PORT
      LAYER M4 ;
      RECT 0.00000 75.16800 0.03600 75.19200 ;
    END
  END wdata[540]
  PIN wdata[541]
    DIRECTION INPUT ;
    USE SIGNAL ;
    PORT
      LAYER M4 ;
      RECT 0.00000 75.21600 0.03600 75.24000 ;
    END
  END wdata[541]
  PIN wdata[542]
    DIRECTION INPUT ;
    USE SIGNAL ;
    PORT
      LAYER M4 ;
      RECT 0.00000 75.26400 0.03600 75.28800 ;
    END
  END wdata[542]
  PIN wdata[543]
    DIRECTION INPUT ;
    USE SIGNAL ;
    PORT
      LAYER M4 ;
      RECT 0.00000 75.31200 0.03600 75.33600 ;
    END
  END wdata[543]
  PIN wdata[544]
    DIRECTION INPUT ;
    USE SIGNAL ;
    PORT
      LAYER M4 ;
      RECT 0.00000 75.36000 0.03600 75.38400 ;
    END
  END wdata[544]
  PIN wdata[545]
    DIRECTION INPUT ;
    USE SIGNAL ;
    PORT
      LAYER M4 ;
      RECT 0.00000 75.40800 0.03600 75.43200 ;
    END
  END wdata[545]
  PIN wdata[546]
    DIRECTION INPUT ;
    USE SIGNAL ;
    PORT
      LAYER M4 ;
      RECT 0.00000 75.45600 0.03600 75.48000 ;
    END
  END wdata[546]
  PIN wdata[547]
    DIRECTION INPUT ;
    USE SIGNAL ;
    PORT
      LAYER M4 ;
      RECT 0.00000 75.50400 0.03600 75.52800 ;
    END
  END wdata[547]
  PIN wdata[548]
    DIRECTION INPUT ;
    USE SIGNAL ;
    PORT
      LAYER M4 ;
      RECT 0.00000 75.55200 0.03600 75.57600 ;
    END
  END wdata[548]
  PIN wdata[549]
    DIRECTION INPUT ;
    USE SIGNAL ;
    PORT
      LAYER M4 ;
      RECT 0.00000 75.60000 0.03600 75.62400 ;
    END
  END wdata[549]
  PIN wdata[550]
    DIRECTION INPUT ;
    USE SIGNAL ;
    PORT
      LAYER M4 ;
      RECT 0.00000 75.64800 0.03600 75.67200 ;
    END
  END wdata[550]
  PIN wdata[551]
    DIRECTION INPUT ;
    USE SIGNAL ;
    PORT
      LAYER M4 ;
      RECT 0.00000 75.69600 0.03600 75.72000 ;
    END
  END wdata[551]
  PIN wdata[552]
    DIRECTION INPUT ;
    USE SIGNAL ;
    PORT
      LAYER M4 ;
      RECT 0.00000 75.74400 0.03600 75.76800 ;
    END
  END wdata[552]
  PIN wdata[553]
    DIRECTION INPUT ;
    USE SIGNAL ;
    PORT
      LAYER M4 ;
      RECT 0.00000 75.79200 0.03600 75.81600 ;
    END
  END wdata[553]
  PIN wdata[554]
    DIRECTION INPUT ;
    USE SIGNAL ;
    PORT
      LAYER M4 ;
      RECT 0.00000 75.84000 0.03600 75.86400 ;
    END
  END wdata[554]
  PIN wdata[555]
    DIRECTION INPUT ;
    USE SIGNAL ;
    PORT
      LAYER M4 ;
      RECT 0.00000 75.88800 0.03600 75.91200 ;
    END
  END wdata[555]
  PIN wdata[556]
    DIRECTION INPUT ;
    USE SIGNAL ;
    PORT
      LAYER M4 ;
      RECT 0.00000 75.93600 0.03600 75.96000 ;
    END
  END wdata[556]
  PIN wdata[557]
    DIRECTION INPUT ;
    USE SIGNAL ;
    PORT
      LAYER M4 ;
      RECT 0.00000 75.98400 0.03600 76.00800 ;
    END
  END wdata[557]
  PIN wdata[558]
    DIRECTION INPUT ;
    USE SIGNAL ;
    PORT
      LAYER M4 ;
      RECT 0.00000 76.03200 0.03600 76.05600 ;
    END
  END wdata[558]
  PIN wdata[559]
    DIRECTION INPUT ;
    USE SIGNAL ;
    PORT
      LAYER M4 ;
      RECT 0.00000 76.08000 0.03600 76.10400 ;
    END
  END wdata[559]
  PIN wdata[560]
    DIRECTION INPUT ;
    USE SIGNAL ;
    PORT
      LAYER M4 ;
      RECT 0.00000 76.12800 0.03600 76.15200 ;
    END
  END wdata[560]
  PIN wdata[561]
    DIRECTION INPUT ;
    USE SIGNAL ;
    PORT
      LAYER M4 ;
      RECT 0.00000 76.17600 0.03600 76.20000 ;
    END
  END wdata[561]
  PIN wdata[562]
    DIRECTION INPUT ;
    USE SIGNAL ;
    PORT
      LAYER M4 ;
      RECT 0.00000 76.22400 0.03600 76.24800 ;
    END
  END wdata[562]
  PIN wdata[563]
    DIRECTION INPUT ;
    USE SIGNAL ;
    PORT
      LAYER M4 ;
      RECT 0.00000 76.27200 0.03600 76.29600 ;
    END
  END wdata[563]
  PIN wdata[564]
    DIRECTION INPUT ;
    USE SIGNAL ;
    PORT
      LAYER M4 ;
      RECT 0.00000 76.32000 0.03600 76.34400 ;
    END
  END wdata[564]
  PIN wdata[565]
    DIRECTION INPUT ;
    USE SIGNAL ;
    PORT
      LAYER M4 ;
      RECT 0.00000 76.36800 0.03600 76.39200 ;
    END
  END wdata[565]
  PIN wdata[566]
    DIRECTION INPUT ;
    USE SIGNAL ;
    PORT
      LAYER M4 ;
      RECT 0.00000 76.41600 0.03600 76.44000 ;
    END
  END wdata[566]
  PIN wdata[567]
    DIRECTION INPUT ;
    USE SIGNAL ;
    PORT
      LAYER M4 ;
      RECT 0.00000 76.46400 0.03600 76.48800 ;
    END
  END wdata[567]
  PIN wdata[568]
    DIRECTION INPUT ;
    USE SIGNAL ;
    PORT
      LAYER M4 ;
      RECT 0.00000 76.51200 0.03600 76.53600 ;
    END
  END wdata[568]
  PIN wdata[569]
    DIRECTION INPUT ;
    USE SIGNAL ;
    PORT
      LAYER M4 ;
      RECT 0.00000 76.56000 0.03600 76.58400 ;
    END
  END wdata[569]
  PIN wdata[570]
    DIRECTION INPUT ;
    USE SIGNAL ;
    PORT
      LAYER M4 ;
      RECT 0.00000 76.60800 0.03600 76.63200 ;
    END
  END wdata[570]
  PIN wdata[571]
    DIRECTION INPUT ;
    USE SIGNAL ;
    PORT
      LAYER M4 ;
      RECT 0.00000 76.65600 0.03600 76.68000 ;
    END
  END wdata[571]
  PIN wdata[572]
    DIRECTION INPUT ;
    USE SIGNAL ;
    PORT
      LAYER M4 ;
      RECT 0.00000 76.70400 0.03600 76.72800 ;
    END
  END wdata[572]
  PIN wdata[573]
    DIRECTION INPUT ;
    USE SIGNAL ;
    PORT
      LAYER M4 ;
      RECT 0.00000 76.75200 0.03600 76.77600 ;
    END
  END wdata[573]
  PIN wdata[574]
    DIRECTION INPUT ;
    USE SIGNAL ;
    PORT
      LAYER M4 ;
      RECT 0.00000 76.80000 0.03600 76.82400 ;
    END
  END wdata[574]
  PIN wdata[575]
    DIRECTION INPUT ;
    USE SIGNAL ;
    PORT
      LAYER M4 ;
      RECT 0.00000 76.84800 0.03600 76.87200 ;
    END
  END wdata[575]
  PIN wdata[576]
    DIRECTION INPUT ;
    USE SIGNAL ;
    PORT
      LAYER M4 ;
      RECT 0.00000 76.89600 0.03600 76.92000 ;
    END
  END wdata[576]
  PIN wdata[577]
    DIRECTION INPUT ;
    USE SIGNAL ;
    PORT
      LAYER M4 ;
      RECT 0.00000 76.94400 0.03600 76.96800 ;
    END
  END wdata[577]
  PIN wdata[578]
    DIRECTION INPUT ;
    USE SIGNAL ;
    PORT
      LAYER M4 ;
      RECT 0.00000 76.99200 0.03600 77.01600 ;
    END
  END wdata[578]
  PIN wdata[579]
    DIRECTION INPUT ;
    USE SIGNAL ;
    PORT
      LAYER M4 ;
      RECT 0.00000 77.04000 0.03600 77.06400 ;
    END
  END wdata[579]
  PIN wdata[580]
    DIRECTION INPUT ;
    USE SIGNAL ;
    PORT
      LAYER M4 ;
      RECT 0.00000 77.08800 0.03600 77.11200 ;
    END
  END wdata[580]
  PIN wdata[581]
    DIRECTION INPUT ;
    USE SIGNAL ;
    PORT
      LAYER M4 ;
      RECT 0.00000 77.13600 0.03600 77.16000 ;
    END
  END wdata[581]
  PIN wdata[582]
    DIRECTION INPUT ;
    USE SIGNAL ;
    PORT
      LAYER M4 ;
      RECT 0.00000 77.18400 0.03600 77.20800 ;
    END
  END wdata[582]
  PIN wdata[583]
    DIRECTION INPUT ;
    USE SIGNAL ;
    PORT
      LAYER M4 ;
      RECT 0.00000 77.23200 0.03600 77.25600 ;
    END
  END wdata[583]
  PIN wdata[584]
    DIRECTION INPUT ;
    USE SIGNAL ;
    PORT
      LAYER M4 ;
      RECT 0.00000 77.28000 0.03600 77.30400 ;
    END
  END wdata[584]
  PIN wdata[585]
    DIRECTION INPUT ;
    USE SIGNAL ;
    PORT
      LAYER M4 ;
      RECT 0.00000 77.32800 0.03600 77.35200 ;
    END
  END wdata[585]
  PIN wdata[586]
    DIRECTION INPUT ;
    USE SIGNAL ;
    PORT
      LAYER M4 ;
      RECT 0.00000 77.37600 0.03600 77.40000 ;
    END
  END wdata[586]
  PIN wdata[587]
    DIRECTION INPUT ;
    USE SIGNAL ;
    PORT
      LAYER M4 ;
      RECT 0.00000 77.42400 0.03600 77.44800 ;
    END
  END wdata[587]
  PIN wdata[588]
    DIRECTION INPUT ;
    USE SIGNAL ;
    PORT
      LAYER M4 ;
      RECT 0.00000 77.47200 0.03600 77.49600 ;
    END
  END wdata[588]
  PIN wdata[589]
    DIRECTION INPUT ;
    USE SIGNAL ;
    PORT
      LAYER M4 ;
      RECT 0.00000 77.52000 0.03600 77.54400 ;
    END
  END wdata[589]
  PIN wdata[590]
    DIRECTION INPUT ;
    USE SIGNAL ;
    PORT
      LAYER M4 ;
      RECT 0.00000 77.56800 0.03600 77.59200 ;
    END
  END wdata[590]
  PIN wdata[591]
    DIRECTION INPUT ;
    USE SIGNAL ;
    PORT
      LAYER M4 ;
      RECT 0.00000 77.61600 0.03600 77.64000 ;
    END
  END wdata[591]
  PIN wdata[592]
    DIRECTION INPUT ;
    USE SIGNAL ;
    PORT
      LAYER M4 ;
      RECT 0.00000 77.66400 0.03600 77.68800 ;
    END
  END wdata[592]
  PIN wdata[593]
    DIRECTION INPUT ;
    USE SIGNAL ;
    PORT
      LAYER M4 ;
      RECT 0.00000 77.71200 0.03600 77.73600 ;
    END
  END wdata[593]
  PIN wdata[594]
    DIRECTION INPUT ;
    USE SIGNAL ;
    PORT
      LAYER M4 ;
      RECT 0.00000 77.76000 0.03600 77.78400 ;
    END
  END wdata[594]
  PIN wdata[595]
    DIRECTION INPUT ;
    USE SIGNAL ;
    PORT
      LAYER M4 ;
      RECT 0.00000 77.80800 0.03600 77.83200 ;
    END
  END wdata[595]
  PIN wdata[596]
    DIRECTION INPUT ;
    USE SIGNAL ;
    PORT
      LAYER M4 ;
      RECT 0.00000 77.85600 0.03600 77.88000 ;
    END
  END wdata[596]
  PIN wdata[597]
    DIRECTION INPUT ;
    USE SIGNAL ;
    PORT
      LAYER M4 ;
      RECT 0.00000 77.90400 0.03600 77.92800 ;
    END
  END wdata[597]
  PIN wdata[598]
    DIRECTION INPUT ;
    USE SIGNAL ;
    PORT
      LAYER M4 ;
      RECT 0.00000 77.95200 0.03600 77.97600 ;
    END
  END wdata[598]
  PIN wdata[599]
    DIRECTION INPUT ;
    USE SIGNAL ;
    PORT
      LAYER M4 ;
      RECT 0.00000 78.00000 0.03600 78.02400 ;
    END
  END wdata[599]
  PIN wdata[600]
    DIRECTION INPUT ;
    USE SIGNAL ;
    PORT
      LAYER M4 ;
      RECT 0.00000 78.04800 0.03600 78.07200 ;
    END
  END wdata[600]
  PIN wdata[601]
    DIRECTION INPUT ;
    USE SIGNAL ;
    PORT
      LAYER M4 ;
      RECT 0.00000 78.09600 0.03600 78.12000 ;
    END
  END wdata[601]
  PIN wdata[602]
    DIRECTION INPUT ;
    USE SIGNAL ;
    PORT
      LAYER M4 ;
      RECT 0.00000 78.14400 0.03600 78.16800 ;
    END
  END wdata[602]
  PIN wdata[603]
    DIRECTION INPUT ;
    USE SIGNAL ;
    PORT
      LAYER M4 ;
      RECT 0.00000 78.19200 0.03600 78.21600 ;
    END
  END wdata[603]
  PIN wdata[604]
    DIRECTION INPUT ;
    USE SIGNAL ;
    PORT
      LAYER M4 ;
      RECT 0.00000 78.24000 0.03600 78.26400 ;
    END
  END wdata[604]
  PIN wdata[605]
    DIRECTION INPUT ;
    USE SIGNAL ;
    PORT
      LAYER M4 ;
      RECT 0.00000 78.28800 0.03600 78.31200 ;
    END
  END wdata[605]
  PIN wdata[606]
    DIRECTION INPUT ;
    USE SIGNAL ;
    PORT
      LAYER M4 ;
      RECT 0.00000 78.33600 0.03600 78.36000 ;
    END
  END wdata[606]
  PIN wdata[607]
    DIRECTION INPUT ;
    USE SIGNAL ;
    PORT
      LAYER M4 ;
      RECT 0.00000 78.38400 0.03600 78.40800 ;
    END
  END wdata[607]
  PIN wdata[608]
    DIRECTION INPUT ;
    USE SIGNAL ;
    PORT
      LAYER M4 ;
      RECT 0.00000 78.43200 0.03600 78.45600 ;
    END
  END wdata[608]
  PIN wdata[609]
    DIRECTION INPUT ;
    USE SIGNAL ;
    PORT
      LAYER M4 ;
      RECT 0.00000 78.48000 0.03600 78.50400 ;
    END
  END wdata[609]
  PIN wdata[610]
    DIRECTION INPUT ;
    USE SIGNAL ;
    PORT
      LAYER M4 ;
      RECT 0.00000 78.52800 0.03600 78.55200 ;
    END
  END wdata[610]
  PIN wdata[611]
    DIRECTION INPUT ;
    USE SIGNAL ;
    PORT
      LAYER M4 ;
      RECT 0.00000 78.57600 0.03600 78.60000 ;
    END
  END wdata[611]
  PIN wdata[612]
    DIRECTION INPUT ;
    USE SIGNAL ;
    PORT
      LAYER M4 ;
      RECT 0.00000 78.62400 0.03600 78.64800 ;
    END
  END wdata[612]
  PIN wdata[613]
    DIRECTION INPUT ;
    USE SIGNAL ;
    PORT
      LAYER M4 ;
      RECT 0.00000 78.67200 0.03600 78.69600 ;
    END
  END wdata[613]
  PIN wdata[614]
    DIRECTION INPUT ;
    USE SIGNAL ;
    PORT
      LAYER M4 ;
      RECT 0.00000 78.72000 0.03600 78.74400 ;
    END
  END wdata[614]
  PIN wdata[615]
    DIRECTION INPUT ;
    USE SIGNAL ;
    PORT
      LAYER M4 ;
      RECT 0.00000 78.76800 0.03600 78.79200 ;
    END
  END wdata[615]
  PIN wdata[616]
    DIRECTION INPUT ;
    USE SIGNAL ;
    PORT
      LAYER M4 ;
      RECT 0.00000 78.81600 0.03600 78.84000 ;
    END
  END wdata[616]
  PIN wdata[617]
    DIRECTION INPUT ;
    USE SIGNAL ;
    PORT
      LAYER M4 ;
      RECT 0.00000 78.86400 0.03600 78.88800 ;
    END
  END wdata[617]
  PIN wdata[618]
    DIRECTION INPUT ;
    USE SIGNAL ;
    PORT
      LAYER M4 ;
      RECT 0.00000 78.91200 0.03600 78.93600 ;
    END
  END wdata[618]
  PIN wdata[619]
    DIRECTION INPUT ;
    USE SIGNAL ;
    PORT
      LAYER M4 ;
      RECT 0.00000 78.96000 0.03600 78.98400 ;
    END
  END wdata[619]
  PIN wdata[620]
    DIRECTION INPUT ;
    USE SIGNAL ;
    PORT
      LAYER M4 ;
      RECT 0.00000 79.00800 0.03600 79.03200 ;
    END
  END wdata[620]
  PIN wdata[621]
    DIRECTION INPUT ;
    USE SIGNAL ;
    PORT
      LAYER M4 ;
      RECT 0.00000 79.05600 0.03600 79.08000 ;
    END
  END wdata[621]
  PIN wdata[622]
    DIRECTION INPUT ;
    USE SIGNAL ;
    PORT
      LAYER M4 ;
      RECT 0.00000 79.10400 0.03600 79.12800 ;
    END
  END wdata[622]
  PIN wdata[623]
    DIRECTION INPUT ;
    USE SIGNAL ;
    PORT
      LAYER M4 ;
      RECT 0.00000 79.15200 0.03600 79.17600 ;
    END
  END wdata[623]
  PIN wdata[624]
    DIRECTION INPUT ;
    USE SIGNAL ;
    PORT
      LAYER M4 ;
      RECT 0.00000 79.20000 0.03600 79.22400 ;
    END
  END wdata[624]
  PIN wdata[625]
    DIRECTION INPUT ;
    USE SIGNAL ;
    PORT
      LAYER M4 ;
      RECT 0.00000 79.24800 0.03600 79.27200 ;
    END
  END wdata[625]
  PIN wdata[626]
    DIRECTION INPUT ;
    USE SIGNAL ;
    PORT
      LAYER M4 ;
      RECT 0.00000 79.29600 0.03600 79.32000 ;
    END
  END wdata[626]
  PIN wdata[627]
    DIRECTION INPUT ;
    USE SIGNAL ;
    PORT
      LAYER M4 ;
      RECT 0.00000 79.34400 0.03600 79.36800 ;
    END
  END wdata[627]
  PIN wdata[628]
    DIRECTION INPUT ;
    USE SIGNAL ;
    PORT
      LAYER M4 ;
      RECT 0.00000 79.39200 0.03600 79.41600 ;
    END
  END wdata[628]
  PIN wdata[629]
    DIRECTION INPUT ;
    USE SIGNAL ;
    PORT
      LAYER M4 ;
      RECT 0.00000 79.44000 0.03600 79.46400 ;
    END
  END wdata[629]
  PIN wdata[630]
    DIRECTION INPUT ;
    USE SIGNAL ;
    PORT
      LAYER M4 ;
      RECT 0.00000 79.48800 0.03600 79.51200 ;
    END
  END wdata[630]
  PIN wdata[631]
    DIRECTION INPUT ;
    USE SIGNAL ;
    PORT
      LAYER M4 ;
      RECT 0.00000 79.53600 0.03600 79.56000 ;
    END
  END wdata[631]
  PIN wdata[632]
    DIRECTION INPUT ;
    USE SIGNAL ;
    PORT
      LAYER M4 ;
      RECT 0.00000 79.58400 0.03600 79.60800 ;
    END
  END wdata[632]
  PIN wdata[633]
    DIRECTION INPUT ;
    USE SIGNAL ;
    PORT
      LAYER M4 ;
      RECT 0.00000 79.63200 0.03600 79.65600 ;
    END
  END wdata[633]
  PIN wdata[634]
    DIRECTION INPUT ;
    USE SIGNAL ;
    PORT
      LAYER M4 ;
      RECT 0.00000 79.68000 0.03600 79.70400 ;
    END
  END wdata[634]
  PIN wdata[635]
    DIRECTION INPUT ;
    USE SIGNAL ;
    PORT
      LAYER M4 ;
      RECT 0.00000 79.72800 0.03600 79.75200 ;
    END
  END wdata[635]
  PIN wdata[636]
    DIRECTION INPUT ;
    USE SIGNAL ;
    PORT
      LAYER M4 ;
      RECT 0.00000 79.77600 0.03600 79.80000 ;
    END
  END wdata[636]
  PIN wdata[637]
    DIRECTION INPUT ;
    USE SIGNAL ;
    PORT
      LAYER M4 ;
      RECT 0.00000 79.82400 0.03600 79.84800 ;
    END
  END wdata[637]
  PIN wdata[638]
    DIRECTION INPUT ;
    USE SIGNAL ;
    PORT
      LAYER M4 ;
      RECT 0.00000 79.87200 0.03600 79.89600 ;
    END
  END wdata[638]
  PIN wdata[639]
    DIRECTION INPUT ;
    USE SIGNAL ;
    PORT
      LAYER M4 ;
      RECT 0.00000 79.92000 0.03600 79.94400 ;
    END
  END wdata[639]
  PIN wdata[640]
    DIRECTION INPUT ;
    USE SIGNAL ;
    PORT
      LAYER M4 ;
      RECT 0.00000 79.96800 0.03600 79.99200 ;
    END
  END wdata[640]
  PIN wdata[641]
    DIRECTION INPUT ;
    USE SIGNAL ;
    PORT
      LAYER M4 ;
      RECT 0.00000 80.01600 0.03600 80.04000 ;
    END
  END wdata[641]
  PIN wdata[642]
    DIRECTION INPUT ;
    USE SIGNAL ;
    PORT
      LAYER M4 ;
      RECT 0.00000 80.06400 0.03600 80.08800 ;
    END
  END wdata[642]
  PIN wdata[643]
    DIRECTION INPUT ;
    USE SIGNAL ;
    PORT
      LAYER M4 ;
      RECT 0.00000 80.11200 0.03600 80.13600 ;
    END
  END wdata[643]
  PIN wdata[644]
    DIRECTION INPUT ;
    USE SIGNAL ;
    PORT
      LAYER M4 ;
      RECT 0.00000 80.16000 0.03600 80.18400 ;
    END
  END wdata[644]
  PIN wdata[645]
    DIRECTION INPUT ;
    USE SIGNAL ;
    PORT
      LAYER M4 ;
      RECT 0.00000 80.20800 0.03600 80.23200 ;
    END
  END wdata[645]
  PIN wdata[646]
    DIRECTION INPUT ;
    USE SIGNAL ;
    PORT
      LAYER M4 ;
      RECT 0.00000 80.25600 0.03600 80.28000 ;
    END
  END wdata[646]
  PIN wdata[647]
    DIRECTION INPUT ;
    USE SIGNAL ;
    PORT
      LAYER M4 ;
      RECT 0.00000 80.30400 0.03600 80.32800 ;
    END
  END wdata[647]
  PIN wdata[648]
    DIRECTION INPUT ;
    USE SIGNAL ;
    PORT
      LAYER M4 ;
      RECT 0.00000 80.35200 0.03600 80.37600 ;
    END
  END wdata[648]
  PIN wdata[649]
    DIRECTION INPUT ;
    USE SIGNAL ;
    PORT
      LAYER M4 ;
      RECT 0.00000 80.40000 0.03600 80.42400 ;
    END
  END wdata[649]
  PIN wdata[650]
    DIRECTION INPUT ;
    USE SIGNAL ;
    PORT
      LAYER M4 ;
      RECT 0.00000 80.44800 0.03600 80.47200 ;
    END
  END wdata[650]
  PIN wdata[651]
    DIRECTION INPUT ;
    USE SIGNAL ;
    PORT
      LAYER M4 ;
      RECT 0.00000 80.49600 0.03600 80.52000 ;
    END
  END wdata[651]
  PIN wdata[652]
    DIRECTION INPUT ;
    USE SIGNAL ;
    PORT
      LAYER M4 ;
      RECT 0.00000 80.54400 0.03600 80.56800 ;
    END
  END wdata[652]
  PIN wdata[653]
    DIRECTION INPUT ;
    USE SIGNAL ;
    PORT
      LAYER M4 ;
      RECT 0.00000 80.59200 0.03600 80.61600 ;
    END
  END wdata[653]
  PIN wdata[654]
    DIRECTION INPUT ;
    USE SIGNAL ;
    PORT
      LAYER M4 ;
      RECT 0.00000 80.64000 0.03600 80.66400 ;
    END
  END wdata[654]
  PIN wdata[655]
    DIRECTION INPUT ;
    USE SIGNAL ;
    PORT
      LAYER M4 ;
      RECT 0.00000 80.68800 0.03600 80.71200 ;
    END
  END wdata[655]
  PIN wdata[656]
    DIRECTION INPUT ;
    USE SIGNAL ;
    PORT
      LAYER M4 ;
      RECT 0.00000 80.73600 0.03600 80.76000 ;
    END
  END wdata[656]
  PIN wdata[657]
    DIRECTION INPUT ;
    USE SIGNAL ;
    PORT
      LAYER M4 ;
      RECT 0.00000 80.78400 0.03600 80.80800 ;
    END
  END wdata[657]
  PIN wdata[658]
    DIRECTION INPUT ;
    USE SIGNAL ;
    PORT
      LAYER M4 ;
      RECT 0.00000 80.83200 0.03600 80.85600 ;
    END
  END wdata[658]
  PIN wdata[659]
    DIRECTION INPUT ;
    USE SIGNAL ;
    PORT
      LAYER M4 ;
      RECT 0.00000 80.88000 0.03600 80.90400 ;
    END
  END wdata[659]
  PIN wdata[660]
    DIRECTION INPUT ;
    USE SIGNAL ;
    PORT
      LAYER M4 ;
      RECT 0.00000 80.92800 0.03600 80.95200 ;
    END
  END wdata[660]
  PIN wdata[661]
    DIRECTION INPUT ;
    USE SIGNAL ;
    PORT
      LAYER M4 ;
      RECT 0.00000 80.97600 0.03600 81.00000 ;
    END
  END wdata[661]
  PIN wdata[662]
    DIRECTION INPUT ;
    USE SIGNAL ;
    PORT
      LAYER M4 ;
      RECT 0.00000 81.02400 0.03600 81.04800 ;
    END
  END wdata[662]
  PIN wdata[663]
    DIRECTION INPUT ;
    USE SIGNAL ;
    PORT
      LAYER M4 ;
      RECT 0.00000 81.07200 0.03600 81.09600 ;
    END
  END wdata[663]
  PIN wdata[664]
    DIRECTION INPUT ;
    USE SIGNAL ;
    PORT
      LAYER M4 ;
      RECT 0.00000 81.12000 0.03600 81.14400 ;
    END
  END wdata[664]
  PIN wdata[665]
    DIRECTION INPUT ;
    USE SIGNAL ;
    PORT
      LAYER M4 ;
      RECT 0.00000 81.16800 0.03600 81.19200 ;
    END
  END wdata[665]
  PIN wdata[666]
    DIRECTION INPUT ;
    USE SIGNAL ;
    PORT
      LAYER M4 ;
      RECT 0.00000 81.21600 0.03600 81.24000 ;
    END
  END wdata[666]
  PIN wdata[667]
    DIRECTION INPUT ;
    USE SIGNAL ;
    PORT
      LAYER M4 ;
      RECT 0.00000 81.26400 0.03600 81.28800 ;
    END
  END wdata[667]
  PIN wdata[668]
    DIRECTION INPUT ;
    USE SIGNAL ;
    PORT
      LAYER M4 ;
      RECT 0.00000 81.31200 0.03600 81.33600 ;
    END
  END wdata[668]
  PIN wdata[669]
    DIRECTION INPUT ;
    USE SIGNAL ;
    PORT
      LAYER M4 ;
      RECT 0.00000 81.36000 0.03600 81.38400 ;
    END
  END wdata[669]
  PIN wdata[670]
    DIRECTION INPUT ;
    USE SIGNAL ;
    PORT
      LAYER M4 ;
      RECT 0.00000 81.40800 0.03600 81.43200 ;
    END
  END wdata[670]
  PIN wdata[671]
    DIRECTION INPUT ;
    USE SIGNAL ;
    PORT
      LAYER M4 ;
      RECT 0.00000 81.45600 0.03600 81.48000 ;
    END
  END wdata[671]
  PIN wdata[672]
    DIRECTION INPUT ;
    USE SIGNAL ;
    PORT
      LAYER M4 ;
      RECT 0.00000 81.50400 0.03600 81.52800 ;
    END
  END wdata[672]
  PIN wdata[673]
    DIRECTION INPUT ;
    USE SIGNAL ;
    PORT
      LAYER M4 ;
      RECT 0.00000 81.55200 0.03600 81.57600 ;
    END
  END wdata[673]
  PIN wdata[674]
    DIRECTION INPUT ;
    USE SIGNAL ;
    PORT
      LAYER M4 ;
      RECT 0.00000 81.60000 0.03600 81.62400 ;
    END
  END wdata[674]
  PIN wdata[675]
    DIRECTION INPUT ;
    USE SIGNAL ;
    PORT
      LAYER M4 ;
      RECT 0.00000 81.64800 0.03600 81.67200 ;
    END
  END wdata[675]
  PIN wdata[676]
    DIRECTION INPUT ;
    USE SIGNAL ;
    PORT
      LAYER M4 ;
      RECT 0.00000 81.69600 0.03600 81.72000 ;
    END
  END wdata[676]
  PIN wdata[677]
    DIRECTION INPUT ;
    USE SIGNAL ;
    PORT
      LAYER M4 ;
      RECT 0.00000 81.74400 0.03600 81.76800 ;
    END
  END wdata[677]
  PIN wdata[678]
    DIRECTION INPUT ;
    USE SIGNAL ;
    PORT
      LAYER M4 ;
      RECT 0.00000 81.79200 0.03600 81.81600 ;
    END
  END wdata[678]
  PIN wdata[679]
    DIRECTION INPUT ;
    USE SIGNAL ;
    PORT
      LAYER M4 ;
      RECT 0.00000 81.84000 0.03600 81.86400 ;
    END
  END wdata[679]
  PIN wdata[680]
    DIRECTION INPUT ;
    USE SIGNAL ;
    PORT
      LAYER M4 ;
      RECT 0.00000 81.88800 0.03600 81.91200 ;
    END
  END wdata[680]
  PIN wdata[681]
    DIRECTION INPUT ;
    USE SIGNAL ;
    PORT
      LAYER M4 ;
      RECT 0.00000 81.93600 0.03600 81.96000 ;
    END
  END wdata[681]
  PIN wdata[682]
    DIRECTION INPUT ;
    USE SIGNAL ;
    PORT
      LAYER M4 ;
      RECT 0.00000 81.98400 0.03600 82.00800 ;
    END
  END wdata[682]
  PIN wdata[683]
    DIRECTION INPUT ;
    USE SIGNAL ;
    PORT
      LAYER M4 ;
      RECT 0.00000 82.03200 0.03600 82.05600 ;
    END
  END wdata[683]
  PIN wdata[684]
    DIRECTION INPUT ;
    USE SIGNAL ;
    PORT
      LAYER M4 ;
      RECT 0.00000 82.08000 0.03600 82.10400 ;
    END
  END wdata[684]
  PIN wdata[685]
    DIRECTION INPUT ;
    USE SIGNAL ;
    PORT
      LAYER M4 ;
      RECT 0.00000 82.12800 0.03600 82.15200 ;
    END
  END wdata[685]
  PIN wdata[686]
    DIRECTION INPUT ;
    USE SIGNAL ;
    PORT
      LAYER M4 ;
      RECT 0.00000 82.17600 0.03600 82.20000 ;
    END
  END wdata[686]
  PIN wdata[687]
    DIRECTION INPUT ;
    USE SIGNAL ;
    PORT
      LAYER M4 ;
      RECT 0.00000 82.22400 0.03600 82.24800 ;
    END
  END wdata[687]
  PIN wdata[688]
    DIRECTION INPUT ;
    USE SIGNAL ;
    PORT
      LAYER M4 ;
      RECT 0.00000 82.27200 0.03600 82.29600 ;
    END
  END wdata[688]
  PIN wdata[689]
    DIRECTION INPUT ;
    USE SIGNAL ;
    PORT
      LAYER M4 ;
      RECT 0.00000 82.32000 0.03600 82.34400 ;
    END
  END wdata[689]
  PIN wdata[690]
    DIRECTION INPUT ;
    USE SIGNAL ;
    PORT
      LAYER M4 ;
      RECT 0.00000 82.36800 0.03600 82.39200 ;
    END
  END wdata[690]
  PIN wdata[691]
    DIRECTION INPUT ;
    USE SIGNAL ;
    PORT
      LAYER M4 ;
      RECT 0.00000 82.41600 0.03600 82.44000 ;
    END
  END wdata[691]
  PIN wdata[692]
    DIRECTION INPUT ;
    USE SIGNAL ;
    PORT
      LAYER M4 ;
      RECT 0.00000 82.46400 0.03600 82.48800 ;
    END
  END wdata[692]
  PIN wdata[693]
    DIRECTION INPUT ;
    USE SIGNAL ;
    PORT
      LAYER M4 ;
      RECT 0.00000 82.51200 0.03600 82.53600 ;
    END
  END wdata[693]
  PIN wdata[694]
    DIRECTION INPUT ;
    USE SIGNAL ;
    PORT
      LAYER M4 ;
      RECT 0.00000 82.56000 0.03600 82.58400 ;
    END
  END wdata[694]
  PIN wdata[695]
    DIRECTION INPUT ;
    USE SIGNAL ;
    PORT
      LAYER M4 ;
      RECT 0.00000 82.60800 0.03600 82.63200 ;
    END
  END wdata[695]
  PIN wdata[696]
    DIRECTION INPUT ;
    USE SIGNAL ;
    PORT
      LAYER M4 ;
      RECT 0.00000 82.65600 0.03600 82.68000 ;
    END
  END wdata[696]
  PIN wdata[697]
    DIRECTION INPUT ;
    USE SIGNAL ;
    PORT
      LAYER M4 ;
      RECT 0.00000 82.70400 0.03600 82.72800 ;
    END
  END wdata[697]
  PIN wdata[698]
    DIRECTION INPUT ;
    USE SIGNAL ;
    PORT
      LAYER M4 ;
      RECT 0.00000 82.75200 0.03600 82.77600 ;
    END
  END wdata[698]
  PIN wdata[699]
    DIRECTION INPUT ;
    USE SIGNAL ;
    PORT
      LAYER M4 ;
      RECT 0.00000 82.80000 0.03600 82.82400 ;
    END
  END wdata[699]
  PIN wdata[700]
    DIRECTION INPUT ;
    USE SIGNAL ;
    PORT
      LAYER M4 ;
      RECT 0.00000 82.84800 0.03600 82.87200 ;
    END
  END wdata[700]
  PIN wdata[701]
    DIRECTION INPUT ;
    USE SIGNAL ;
    PORT
      LAYER M4 ;
      RECT 0.00000 82.89600 0.03600 82.92000 ;
    END
  END wdata[701]
  PIN wdata[702]
    DIRECTION INPUT ;
    USE SIGNAL ;
    PORT
      LAYER M4 ;
      RECT 0.00000 82.94400 0.03600 82.96800 ;
    END
  END wdata[702]
  PIN wdata[703]
    DIRECTION INPUT ;
    USE SIGNAL ;
    PORT
      LAYER M4 ;
      RECT 0.00000 82.99200 0.03600 83.01600 ;
    END
  END wdata[703]
  PIN wdata[704]
    DIRECTION INPUT ;
    USE SIGNAL ;
    PORT
      LAYER M4 ;
      RECT 0.00000 83.04000 0.03600 83.06400 ;
    END
  END wdata[704]
  PIN wdata[705]
    DIRECTION INPUT ;
    USE SIGNAL ;
    PORT
      LAYER M4 ;
      RECT 0.00000 83.08800 0.03600 83.11200 ;
    END
  END wdata[705]
  PIN wdata[706]
    DIRECTION INPUT ;
    USE SIGNAL ;
    PORT
      LAYER M4 ;
      RECT 0.00000 83.13600 0.03600 83.16000 ;
    END
  END wdata[706]
  PIN wdata[707]
    DIRECTION INPUT ;
    USE SIGNAL ;
    PORT
      LAYER M4 ;
      RECT 0.00000 83.18400 0.03600 83.20800 ;
    END
  END wdata[707]
  PIN wdata[708]
    DIRECTION INPUT ;
    USE SIGNAL ;
    PORT
      LAYER M4 ;
      RECT 0.00000 83.23200 0.03600 83.25600 ;
    END
  END wdata[708]
  PIN wdata[709]
    DIRECTION INPUT ;
    USE SIGNAL ;
    PORT
      LAYER M4 ;
      RECT 0.00000 83.28000 0.03600 83.30400 ;
    END
  END wdata[709]
  PIN wdata[710]
    DIRECTION INPUT ;
    USE SIGNAL ;
    PORT
      LAYER M4 ;
      RECT 0.00000 83.32800 0.03600 83.35200 ;
    END
  END wdata[710]
  PIN wdata[711]
    DIRECTION INPUT ;
    USE SIGNAL ;
    PORT
      LAYER M4 ;
      RECT 0.00000 83.37600 0.03600 83.40000 ;
    END
  END wdata[711]
  PIN wdata[712]
    DIRECTION INPUT ;
    USE SIGNAL ;
    PORT
      LAYER M4 ;
      RECT 0.00000 83.42400 0.03600 83.44800 ;
    END
  END wdata[712]
  PIN wdata[713]
    DIRECTION INPUT ;
    USE SIGNAL ;
    PORT
      LAYER M4 ;
      RECT 0.00000 83.47200 0.03600 83.49600 ;
    END
  END wdata[713]
  PIN wdata[714]
    DIRECTION INPUT ;
    USE SIGNAL ;
    PORT
      LAYER M4 ;
      RECT 0.00000 83.52000 0.03600 83.54400 ;
    END
  END wdata[714]
  PIN wdata[715]
    DIRECTION INPUT ;
    USE SIGNAL ;
    PORT
      LAYER M4 ;
      RECT 0.00000 83.56800 0.03600 83.59200 ;
    END
  END wdata[715]
  PIN wdata[716]
    DIRECTION INPUT ;
    USE SIGNAL ;
    PORT
      LAYER M4 ;
      RECT 0.00000 83.61600 0.03600 83.64000 ;
    END
  END wdata[716]
  PIN wdata[717]
    DIRECTION INPUT ;
    USE SIGNAL ;
    PORT
      LAYER M4 ;
      RECT 0.00000 83.66400 0.03600 83.68800 ;
    END
  END wdata[717]
  PIN wdata[718]
    DIRECTION INPUT ;
    USE SIGNAL ;
    PORT
      LAYER M4 ;
      RECT 0.00000 83.71200 0.03600 83.73600 ;
    END
  END wdata[718]
  PIN wdata[719]
    DIRECTION INPUT ;
    USE SIGNAL ;
    PORT
      LAYER M4 ;
      RECT 0.00000 83.76000 0.03600 83.78400 ;
    END
  END wdata[719]
  PIN wdata[720]
    DIRECTION INPUT ;
    USE SIGNAL ;
    PORT
      LAYER M4 ;
      RECT 0.00000 83.80800 0.03600 83.83200 ;
    END
  END wdata[720]
  PIN wdata[721]
    DIRECTION INPUT ;
    USE SIGNAL ;
    PORT
      LAYER M4 ;
      RECT 0.00000 83.85600 0.03600 83.88000 ;
    END
  END wdata[721]
  PIN wdata[722]
    DIRECTION INPUT ;
    USE SIGNAL ;
    PORT
      LAYER M4 ;
      RECT 0.00000 83.90400 0.03600 83.92800 ;
    END
  END wdata[722]
  PIN wdata[723]
    DIRECTION INPUT ;
    USE SIGNAL ;
    PORT
      LAYER M4 ;
      RECT 0.00000 83.95200 0.03600 83.97600 ;
    END
  END wdata[723]
  PIN wdata[724]
    DIRECTION INPUT ;
    USE SIGNAL ;
    PORT
      LAYER M4 ;
      RECT 0.00000 84.00000 0.03600 84.02400 ;
    END
  END wdata[724]
  PIN wdata[725]
    DIRECTION INPUT ;
    USE SIGNAL ;
    PORT
      LAYER M4 ;
      RECT 0.00000 84.04800 0.03600 84.07200 ;
    END
  END wdata[725]
  PIN wdata[726]
    DIRECTION INPUT ;
    USE SIGNAL ;
    PORT
      LAYER M4 ;
      RECT 0.00000 84.09600 0.03600 84.12000 ;
    END
  END wdata[726]
  PIN wdata[727]
    DIRECTION INPUT ;
    USE SIGNAL ;
    PORT
      LAYER M4 ;
      RECT 0.00000 84.14400 0.03600 84.16800 ;
    END
  END wdata[727]
  PIN wdata[728]
    DIRECTION INPUT ;
    USE SIGNAL ;
    PORT
      LAYER M4 ;
      RECT 0.00000 84.19200 0.03600 84.21600 ;
    END
  END wdata[728]
  PIN wdata[729]
    DIRECTION INPUT ;
    USE SIGNAL ;
    PORT
      LAYER M4 ;
      RECT 0.00000 84.24000 0.03600 84.26400 ;
    END
  END wdata[729]
  PIN wdata[730]
    DIRECTION INPUT ;
    USE SIGNAL ;
    PORT
      LAYER M4 ;
      RECT 0.00000 84.28800 0.03600 84.31200 ;
    END
  END wdata[730]
  PIN wdata[731]
    DIRECTION INPUT ;
    USE SIGNAL ;
    PORT
      LAYER M4 ;
      RECT 0.00000 84.33600 0.03600 84.36000 ;
    END
  END wdata[731]
  PIN wdata[732]
    DIRECTION INPUT ;
    USE SIGNAL ;
    PORT
      LAYER M4 ;
      RECT 0.00000 84.38400 0.03600 84.40800 ;
    END
  END wdata[732]
  PIN wdata[733]
    DIRECTION INPUT ;
    USE SIGNAL ;
    PORT
      LAYER M4 ;
      RECT 0.00000 84.43200 0.03600 84.45600 ;
    END
  END wdata[733]
  PIN wdata[734]
    DIRECTION INPUT ;
    USE SIGNAL ;
    PORT
      LAYER M4 ;
      RECT 0.00000 84.48000 0.03600 84.50400 ;
    END
  END wdata[734]
  PIN wdata[735]
    DIRECTION INPUT ;
    USE SIGNAL ;
    PORT
      LAYER M4 ;
      RECT 0.00000 84.52800 0.03600 84.55200 ;
    END
  END wdata[735]
  PIN wdata[736]
    DIRECTION INPUT ;
    USE SIGNAL ;
    PORT
      LAYER M4 ;
      RECT 0.00000 84.57600 0.03600 84.60000 ;
    END
  END wdata[736]
  PIN wdata[737]
    DIRECTION INPUT ;
    USE SIGNAL ;
    PORT
      LAYER M4 ;
      RECT 0.00000 84.62400 0.03600 84.64800 ;
    END
  END wdata[737]
  PIN wdata[738]
    DIRECTION INPUT ;
    USE SIGNAL ;
    PORT
      LAYER M4 ;
      RECT 0.00000 84.67200 0.03600 84.69600 ;
    END
  END wdata[738]
  PIN wdata[739]
    DIRECTION INPUT ;
    USE SIGNAL ;
    PORT
      LAYER M4 ;
      RECT 0.00000 84.72000 0.03600 84.74400 ;
    END
  END wdata[739]
  PIN wdata[740]
    DIRECTION INPUT ;
    USE SIGNAL ;
    PORT
      LAYER M4 ;
      RECT 0.00000 84.76800 0.03600 84.79200 ;
    END
  END wdata[740]
  PIN wdata[741]
    DIRECTION INPUT ;
    USE SIGNAL ;
    PORT
      LAYER M4 ;
      RECT 0.00000 84.81600 0.03600 84.84000 ;
    END
  END wdata[741]
  PIN wdata[742]
    DIRECTION INPUT ;
    USE SIGNAL ;
    PORT
      LAYER M4 ;
      RECT 0.00000 84.86400 0.03600 84.88800 ;
    END
  END wdata[742]
  PIN wdata[743]
    DIRECTION INPUT ;
    USE SIGNAL ;
    PORT
      LAYER M4 ;
      RECT 0.00000 84.91200 0.03600 84.93600 ;
    END
  END wdata[743]
  PIN wdata[744]
    DIRECTION INPUT ;
    USE SIGNAL ;
    PORT
      LAYER M4 ;
      RECT 0.00000 84.96000 0.03600 84.98400 ;
    END
  END wdata[744]
  PIN wdata[745]
    DIRECTION INPUT ;
    USE SIGNAL ;
    PORT
      LAYER M4 ;
      RECT 0.00000 85.00800 0.03600 85.03200 ;
    END
  END wdata[745]
  PIN wdata[746]
    DIRECTION INPUT ;
    USE SIGNAL ;
    PORT
      LAYER M4 ;
      RECT 0.00000 85.05600 0.03600 85.08000 ;
    END
  END wdata[746]
  PIN wdata[747]
    DIRECTION INPUT ;
    USE SIGNAL ;
    PORT
      LAYER M4 ;
      RECT 0.00000 85.10400 0.03600 85.12800 ;
    END
  END wdata[747]
  PIN wdata[748]
    DIRECTION INPUT ;
    USE SIGNAL ;
    PORT
      LAYER M4 ;
      RECT 0.00000 85.15200 0.03600 85.17600 ;
    END
  END wdata[748]
  PIN wdata[749]
    DIRECTION INPUT ;
    USE SIGNAL ;
    PORT
      LAYER M4 ;
      RECT 0.00000 85.20000 0.03600 85.22400 ;
    END
  END wdata[749]
  PIN wdata[750]
    DIRECTION INPUT ;
    USE SIGNAL ;
    PORT
      LAYER M4 ;
      RECT 0.00000 85.24800 0.03600 85.27200 ;
    END
  END wdata[750]
  PIN wdata[751]
    DIRECTION INPUT ;
    USE SIGNAL ;
    PORT
      LAYER M4 ;
      RECT 0.00000 85.29600 0.03600 85.32000 ;
    END
  END wdata[751]
  PIN wdata[752]
    DIRECTION INPUT ;
    USE SIGNAL ;
    PORT
      LAYER M4 ;
      RECT 0.00000 85.34400 0.03600 85.36800 ;
    END
  END wdata[752]
  PIN wdata[753]
    DIRECTION INPUT ;
    USE SIGNAL ;
    PORT
      LAYER M4 ;
      RECT 0.00000 85.39200 0.03600 85.41600 ;
    END
  END wdata[753]
  PIN wdata[754]
    DIRECTION INPUT ;
    USE SIGNAL ;
    PORT
      LAYER M4 ;
      RECT 0.00000 85.44000 0.03600 85.46400 ;
    END
  END wdata[754]
  PIN wdata[755]
    DIRECTION INPUT ;
    USE SIGNAL ;
    PORT
      LAYER M4 ;
      RECT 0.00000 85.48800 0.03600 85.51200 ;
    END
  END wdata[755]
  PIN wdata[756]
    DIRECTION INPUT ;
    USE SIGNAL ;
    PORT
      LAYER M4 ;
      RECT 0.00000 85.53600 0.03600 85.56000 ;
    END
  END wdata[756]
  PIN wdata[757]
    DIRECTION INPUT ;
    USE SIGNAL ;
    PORT
      LAYER M4 ;
      RECT 0.00000 85.58400 0.03600 85.60800 ;
    END
  END wdata[757]
  PIN wdata[758]
    DIRECTION INPUT ;
    USE SIGNAL ;
    PORT
      LAYER M4 ;
      RECT 0.00000 85.63200 0.03600 85.65600 ;
    END
  END wdata[758]
  PIN wdata[759]
    DIRECTION INPUT ;
    USE SIGNAL ;
    PORT
      LAYER M4 ;
      RECT 0.00000 85.68000 0.03600 85.70400 ;
    END
  END wdata[759]
  PIN wdata[760]
    DIRECTION INPUT ;
    USE SIGNAL ;
    PORT
      LAYER M4 ;
      RECT 0.00000 85.72800 0.03600 85.75200 ;
    END
  END wdata[760]
  PIN wdata[761]
    DIRECTION INPUT ;
    USE SIGNAL ;
    PORT
      LAYER M4 ;
      RECT 0.00000 85.77600 0.03600 85.80000 ;
    END
  END wdata[761]
  PIN wdata[762]
    DIRECTION INPUT ;
    USE SIGNAL ;
    PORT
      LAYER M4 ;
      RECT 0.00000 85.82400 0.03600 85.84800 ;
    END
  END wdata[762]
  PIN wdata[763]
    DIRECTION INPUT ;
    USE SIGNAL ;
    PORT
      LAYER M4 ;
      RECT 0.00000 85.87200 0.03600 85.89600 ;
    END
  END wdata[763]
  PIN wdata[764]
    DIRECTION INPUT ;
    USE SIGNAL ;
    PORT
      LAYER M4 ;
      RECT 0.00000 85.92000 0.03600 85.94400 ;
    END
  END wdata[764]
  PIN wdata[765]
    DIRECTION INPUT ;
    USE SIGNAL ;
    PORT
      LAYER M4 ;
      RECT 0.00000 85.96800 0.03600 85.99200 ;
    END
  END wdata[765]
  PIN wdata[766]
    DIRECTION INPUT ;
    USE SIGNAL ;
    PORT
      LAYER M4 ;
      RECT 0.00000 86.01600 0.03600 86.04000 ;
    END
  END wdata[766]
  PIN wdata[767]
    DIRECTION INPUT ;
    USE SIGNAL ;
    PORT
      LAYER M4 ;
      RECT 0.00000 86.06400 0.03600 86.08800 ;
    END
  END wdata[767]
  PIN wdata[768]
    DIRECTION INPUT ;
    USE SIGNAL ;
    PORT
      LAYER M4 ;
      RECT 0.00000 86.11200 0.03600 86.13600 ;
    END
  END wdata[768]
  PIN wdata[769]
    DIRECTION INPUT ;
    USE SIGNAL ;
    PORT
      LAYER M4 ;
      RECT 0.00000 86.16000 0.03600 86.18400 ;
    END
  END wdata[769]
  PIN wdata[770]
    DIRECTION INPUT ;
    USE SIGNAL ;
    PORT
      LAYER M4 ;
      RECT 0.00000 86.20800 0.03600 86.23200 ;
    END
  END wdata[770]
  PIN wdata[771]
    DIRECTION INPUT ;
    USE SIGNAL ;
    PORT
      LAYER M4 ;
      RECT 0.00000 86.25600 0.03600 86.28000 ;
    END
  END wdata[771]
  PIN wdata[772]
    DIRECTION INPUT ;
    USE SIGNAL ;
    PORT
      LAYER M4 ;
      RECT 0.00000 86.30400 0.03600 86.32800 ;
    END
  END wdata[772]
  PIN wdata[773]
    DIRECTION INPUT ;
    USE SIGNAL ;
    PORT
      LAYER M4 ;
      RECT 0.00000 86.35200 0.03600 86.37600 ;
    END
  END wdata[773]
  PIN wdata[774]
    DIRECTION INPUT ;
    USE SIGNAL ;
    PORT
      LAYER M4 ;
      RECT 0.00000 86.40000 0.03600 86.42400 ;
    END
  END wdata[774]
  PIN wdata[775]
    DIRECTION INPUT ;
    USE SIGNAL ;
    PORT
      LAYER M4 ;
      RECT 0.00000 86.44800 0.03600 86.47200 ;
    END
  END wdata[775]
  PIN wdata[776]
    DIRECTION INPUT ;
    USE SIGNAL ;
    PORT
      LAYER M4 ;
      RECT 0.00000 86.49600 0.03600 86.52000 ;
    END
  END wdata[776]
  PIN wdata[777]
    DIRECTION INPUT ;
    USE SIGNAL ;
    PORT
      LAYER M4 ;
      RECT 0.00000 86.54400 0.03600 86.56800 ;
    END
  END wdata[777]
  PIN wdata[778]
    DIRECTION INPUT ;
    USE SIGNAL ;
    PORT
      LAYER M4 ;
      RECT 0.00000 86.59200 0.03600 86.61600 ;
    END
  END wdata[778]
  PIN wdata[779]
    DIRECTION INPUT ;
    USE SIGNAL ;
    PORT
      LAYER M4 ;
      RECT 0.00000 86.64000 0.03600 86.66400 ;
    END
  END wdata[779]
  PIN wdata[780]
    DIRECTION INPUT ;
    USE SIGNAL ;
    PORT
      LAYER M4 ;
      RECT 0.00000 86.68800 0.03600 86.71200 ;
    END
  END wdata[780]
  PIN wdata[781]
    DIRECTION INPUT ;
    USE SIGNAL ;
    PORT
      LAYER M4 ;
      RECT 0.00000 86.73600 0.03600 86.76000 ;
    END
  END wdata[781]
  PIN wdata[782]
    DIRECTION INPUT ;
    USE SIGNAL ;
    PORT
      LAYER M4 ;
      RECT 0.00000 86.78400 0.03600 86.80800 ;
    END
  END wdata[782]
  PIN wdata[783]
    DIRECTION INPUT ;
    USE SIGNAL ;
    PORT
      LAYER M4 ;
      RECT 0.00000 86.83200 0.03600 86.85600 ;
    END
  END wdata[783]
  PIN wdata[784]
    DIRECTION INPUT ;
    USE SIGNAL ;
    PORT
      LAYER M4 ;
      RECT 0.00000 86.88000 0.03600 86.90400 ;
    END
  END wdata[784]
  PIN wdata[785]
    DIRECTION INPUT ;
    USE SIGNAL ;
    PORT
      LAYER M4 ;
      RECT 0.00000 86.92800 0.03600 86.95200 ;
    END
  END wdata[785]
  PIN wdata[786]
    DIRECTION INPUT ;
    USE SIGNAL ;
    PORT
      LAYER M4 ;
      RECT 0.00000 86.97600 0.03600 87.00000 ;
    END
  END wdata[786]
  PIN wdata[787]
    DIRECTION INPUT ;
    USE SIGNAL ;
    PORT
      LAYER M4 ;
      RECT 0.00000 87.02400 0.03600 87.04800 ;
    END
  END wdata[787]
  PIN wdata[788]
    DIRECTION INPUT ;
    USE SIGNAL ;
    PORT
      LAYER M4 ;
      RECT 0.00000 87.07200 0.03600 87.09600 ;
    END
  END wdata[788]
  PIN wdata[789]
    DIRECTION INPUT ;
    USE SIGNAL ;
    PORT
      LAYER M4 ;
      RECT 0.00000 87.12000 0.03600 87.14400 ;
    END
  END wdata[789]
  PIN wdata[790]
    DIRECTION INPUT ;
    USE SIGNAL ;
    PORT
      LAYER M4 ;
      RECT 0.00000 87.16800 0.03600 87.19200 ;
    END
  END wdata[790]
  PIN wdata[791]
    DIRECTION INPUT ;
    USE SIGNAL ;
    PORT
      LAYER M4 ;
      RECT 0.00000 87.21600 0.03600 87.24000 ;
    END
  END wdata[791]
  PIN wdata[792]
    DIRECTION INPUT ;
    USE SIGNAL ;
    PORT
      LAYER M4 ;
      RECT 0.00000 87.26400 0.03600 87.28800 ;
    END
  END wdata[792]
  PIN wdata[793]
    DIRECTION INPUT ;
    USE SIGNAL ;
    PORT
      LAYER M4 ;
      RECT 0.00000 87.31200 0.03600 87.33600 ;
    END
  END wdata[793]
  PIN wdata[794]
    DIRECTION INPUT ;
    USE SIGNAL ;
    PORT
      LAYER M4 ;
      RECT 0.00000 87.36000 0.03600 87.38400 ;
    END
  END wdata[794]
  PIN wdata[795]
    DIRECTION INPUT ;
    USE SIGNAL ;
    PORT
      LAYER M4 ;
      RECT 0.00000 87.40800 0.03600 87.43200 ;
    END
  END wdata[795]
  PIN wdata[796]
    DIRECTION INPUT ;
    USE SIGNAL ;
    PORT
      LAYER M4 ;
      RECT 0.00000 87.45600 0.03600 87.48000 ;
    END
  END wdata[796]
  PIN wdata[797]
    DIRECTION INPUT ;
    USE SIGNAL ;
    PORT
      LAYER M4 ;
      RECT 0.00000 87.50400 0.03600 87.52800 ;
    END
  END wdata[797]
  PIN wdata[798]
    DIRECTION INPUT ;
    USE SIGNAL ;
    PORT
      LAYER M4 ;
      RECT 0.00000 87.55200 0.03600 87.57600 ;
    END
  END wdata[798]
  PIN wdata[799]
    DIRECTION INPUT ;
    USE SIGNAL ;
    PORT
      LAYER M4 ;
      RECT 0.00000 87.60000 0.03600 87.62400 ;
    END
  END wdata[799]
  PIN wdata[800]
    DIRECTION INPUT ;
    USE SIGNAL ;
    PORT
      LAYER M4 ;
      RECT 0.00000 87.64800 0.03600 87.67200 ;
    END
  END wdata[800]
  PIN wdata[801]
    DIRECTION INPUT ;
    USE SIGNAL ;
    PORT
      LAYER M4 ;
      RECT 0.00000 87.69600 0.03600 87.72000 ;
    END
  END wdata[801]
  PIN wdata[802]
    DIRECTION INPUT ;
    USE SIGNAL ;
    PORT
      LAYER M4 ;
      RECT 0.00000 87.74400 0.03600 87.76800 ;
    END
  END wdata[802]
  PIN wdata[803]
    DIRECTION INPUT ;
    USE SIGNAL ;
    PORT
      LAYER M4 ;
      RECT 0.00000 87.79200 0.03600 87.81600 ;
    END
  END wdata[803]
  PIN wdata[804]
    DIRECTION INPUT ;
    USE SIGNAL ;
    PORT
      LAYER M4 ;
      RECT 0.00000 87.84000 0.03600 87.86400 ;
    END
  END wdata[804]
  PIN wdata[805]
    DIRECTION INPUT ;
    USE SIGNAL ;
    PORT
      LAYER M4 ;
      RECT 0.00000 87.88800 0.03600 87.91200 ;
    END
  END wdata[805]
  PIN wdata[806]
    DIRECTION INPUT ;
    USE SIGNAL ;
    PORT
      LAYER M4 ;
      RECT 0.00000 87.93600 0.03600 87.96000 ;
    END
  END wdata[806]
  PIN wdata[807]
    DIRECTION INPUT ;
    USE SIGNAL ;
    PORT
      LAYER M4 ;
      RECT 0.00000 87.98400 0.03600 88.00800 ;
    END
  END wdata[807]
  PIN wdata[808]
    DIRECTION INPUT ;
    USE SIGNAL ;
    PORT
      LAYER M4 ;
      RECT 0.00000 88.03200 0.03600 88.05600 ;
    END
  END wdata[808]
  PIN wdata[809]
    DIRECTION INPUT ;
    USE SIGNAL ;
    PORT
      LAYER M4 ;
      RECT 0.00000 88.08000 0.03600 88.10400 ;
    END
  END wdata[809]
  PIN wdata[810]
    DIRECTION INPUT ;
    USE SIGNAL ;
    PORT
      LAYER M4 ;
      RECT 0.00000 88.12800 0.03600 88.15200 ;
    END
  END wdata[810]
  PIN wdata[811]
    DIRECTION INPUT ;
    USE SIGNAL ;
    PORT
      LAYER M4 ;
      RECT 0.00000 88.17600 0.03600 88.20000 ;
    END
  END wdata[811]
  PIN wdata[812]
    DIRECTION INPUT ;
    USE SIGNAL ;
    PORT
      LAYER M4 ;
      RECT 0.00000 88.22400 0.03600 88.24800 ;
    END
  END wdata[812]
  PIN wdata[813]
    DIRECTION INPUT ;
    USE SIGNAL ;
    PORT
      LAYER M4 ;
      RECT 0.00000 88.27200 0.03600 88.29600 ;
    END
  END wdata[813]
  PIN wdata[814]
    DIRECTION INPUT ;
    USE SIGNAL ;
    PORT
      LAYER M4 ;
      RECT 0.00000 88.32000 0.03600 88.34400 ;
    END
  END wdata[814]
  PIN wdata[815]
    DIRECTION INPUT ;
    USE SIGNAL ;
    PORT
      LAYER M4 ;
      RECT 0.00000 88.36800 0.03600 88.39200 ;
    END
  END wdata[815]
  PIN wdata[816]
    DIRECTION INPUT ;
    USE SIGNAL ;
    PORT
      LAYER M4 ;
      RECT 0.00000 88.41600 0.03600 88.44000 ;
    END
  END wdata[816]
  PIN wdata[817]
    DIRECTION INPUT ;
    USE SIGNAL ;
    PORT
      LAYER M4 ;
      RECT 0.00000 88.46400 0.03600 88.48800 ;
    END
  END wdata[817]
  PIN wdata[818]
    DIRECTION INPUT ;
    USE SIGNAL ;
    PORT
      LAYER M4 ;
      RECT 0.00000 88.51200 0.03600 88.53600 ;
    END
  END wdata[818]
  PIN wdata[819]
    DIRECTION INPUT ;
    USE SIGNAL ;
    PORT
      LAYER M4 ;
      RECT 0.00000 88.56000 0.03600 88.58400 ;
    END
  END wdata[819]
  PIN wdata[820]
    DIRECTION INPUT ;
    USE SIGNAL ;
    PORT
      LAYER M4 ;
      RECT 0.00000 88.60800 0.03600 88.63200 ;
    END
  END wdata[820]
  PIN wdata[821]
    DIRECTION INPUT ;
    USE SIGNAL ;
    PORT
      LAYER M4 ;
      RECT 0.00000 88.65600 0.03600 88.68000 ;
    END
  END wdata[821]
  PIN wdata[822]
    DIRECTION INPUT ;
    USE SIGNAL ;
    PORT
      LAYER M4 ;
      RECT 0.00000 88.70400 0.03600 88.72800 ;
    END
  END wdata[822]
  PIN wdata[823]
    DIRECTION INPUT ;
    USE SIGNAL ;
    PORT
      LAYER M4 ;
      RECT 0.00000 88.75200 0.03600 88.77600 ;
    END
  END wdata[823]
  PIN wdata[824]
    DIRECTION INPUT ;
    USE SIGNAL ;
    PORT
      LAYER M4 ;
      RECT 0.00000 88.80000 0.03600 88.82400 ;
    END
  END wdata[824]
  PIN wdata[825]
    DIRECTION INPUT ;
    USE SIGNAL ;
    PORT
      LAYER M4 ;
      RECT 0.00000 88.84800 0.03600 88.87200 ;
    END
  END wdata[825]
  PIN wdata[826]
    DIRECTION INPUT ;
    USE SIGNAL ;
    PORT
      LAYER M4 ;
      RECT 0.00000 88.89600 0.03600 88.92000 ;
    END
  END wdata[826]
  PIN wdata[827]
    DIRECTION INPUT ;
    USE SIGNAL ;
    PORT
      LAYER M4 ;
      RECT 0.00000 88.94400 0.03600 88.96800 ;
    END
  END wdata[827]
  PIN wdata[828]
    DIRECTION INPUT ;
    USE SIGNAL ;
    PORT
      LAYER M4 ;
      RECT 0.00000 88.99200 0.03600 89.01600 ;
    END
  END wdata[828]
  PIN wdata[829]
    DIRECTION INPUT ;
    USE SIGNAL ;
    PORT
      LAYER M4 ;
      RECT 0.00000 89.04000 0.03600 89.06400 ;
    END
  END wdata[829]
  PIN wdata[830]
    DIRECTION INPUT ;
    USE SIGNAL ;
    PORT
      LAYER M4 ;
      RECT 0.00000 89.08800 0.03600 89.11200 ;
    END
  END wdata[830]
  PIN wdata[831]
    DIRECTION INPUT ;
    USE SIGNAL ;
    PORT
      LAYER M4 ;
      RECT 0.00000 89.13600 0.03600 89.16000 ;
    END
  END wdata[831]
  PIN wdata[832]
    DIRECTION INPUT ;
    USE SIGNAL ;
    PORT
      LAYER M4 ;
      RECT 0.00000 89.18400 0.03600 89.20800 ;
    END
  END wdata[832]
  PIN wdata[833]
    DIRECTION INPUT ;
    USE SIGNAL ;
    PORT
      LAYER M4 ;
      RECT 0.00000 89.23200 0.03600 89.25600 ;
    END
  END wdata[833]
  PIN wdata[834]
    DIRECTION INPUT ;
    USE SIGNAL ;
    PORT
      LAYER M4 ;
      RECT 0.00000 89.28000 0.03600 89.30400 ;
    END
  END wdata[834]
  PIN wdata[835]
    DIRECTION INPUT ;
    USE SIGNAL ;
    PORT
      LAYER M4 ;
      RECT 0.00000 89.32800 0.03600 89.35200 ;
    END
  END wdata[835]
  PIN wdata[836]
    DIRECTION INPUT ;
    USE SIGNAL ;
    PORT
      LAYER M4 ;
      RECT 0.00000 89.37600 0.03600 89.40000 ;
    END
  END wdata[836]
  PIN wdata[837]
    DIRECTION INPUT ;
    USE SIGNAL ;
    PORT
      LAYER M4 ;
      RECT 0.00000 89.42400 0.03600 89.44800 ;
    END
  END wdata[837]
  PIN wdata[838]
    DIRECTION INPUT ;
    USE SIGNAL ;
    PORT
      LAYER M4 ;
      RECT 0.00000 89.47200 0.03600 89.49600 ;
    END
  END wdata[838]
  PIN wdata[839]
    DIRECTION INPUT ;
    USE SIGNAL ;
    PORT
      LAYER M4 ;
      RECT 0.00000 89.52000 0.03600 89.54400 ;
    END
  END wdata[839]
  PIN wdata[840]
    DIRECTION INPUT ;
    USE SIGNAL ;
    PORT
      LAYER M4 ;
      RECT 0.00000 89.56800 0.03600 89.59200 ;
    END
  END wdata[840]
  PIN wdata[841]
    DIRECTION INPUT ;
    USE SIGNAL ;
    PORT
      LAYER M4 ;
      RECT 0.00000 89.61600 0.03600 89.64000 ;
    END
  END wdata[841]
  PIN wdata[842]
    DIRECTION INPUT ;
    USE SIGNAL ;
    PORT
      LAYER M4 ;
      RECT 0.00000 89.66400 0.03600 89.68800 ;
    END
  END wdata[842]
  PIN wdata[843]
    DIRECTION INPUT ;
    USE SIGNAL ;
    PORT
      LAYER M4 ;
      RECT 0.00000 89.71200 0.03600 89.73600 ;
    END
  END wdata[843]
  PIN wdata[844]
    DIRECTION INPUT ;
    USE SIGNAL ;
    PORT
      LAYER M4 ;
      RECT 0.00000 89.76000 0.03600 89.78400 ;
    END
  END wdata[844]
  PIN wdata[845]
    DIRECTION INPUT ;
    USE SIGNAL ;
    PORT
      LAYER M4 ;
      RECT 0.00000 89.80800 0.03600 89.83200 ;
    END
  END wdata[845]
  PIN wdata[846]
    DIRECTION INPUT ;
    USE SIGNAL ;
    PORT
      LAYER M4 ;
      RECT 0.00000 89.85600 0.03600 89.88000 ;
    END
  END wdata[846]
  PIN wdata[847]
    DIRECTION INPUT ;
    USE SIGNAL ;
    PORT
      LAYER M4 ;
      RECT 0.00000 89.90400 0.03600 89.92800 ;
    END
  END wdata[847]
  PIN wdata[848]
    DIRECTION INPUT ;
    USE SIGNAL ;
    PORT
      LAYER M4 ;
      RECT 0.00000 89.95200 0.03600 89.97600 ;
    END
  END wdata[848]
  PIN wdata[849]
    DIRECTION INPUT ;
    USE SIGNAL ;
    PORT
      LAYER M4 ;
      RECT 0.00000 90.00000 0.03600 90.02400 ;
    END
  END wdata[849]
  PIN wdata[850]
    DIRECTION INPUT ;
    USE SIGNAL ;
    PORT
      LAYER M4 ;
      RECT 0.00000 90.04800 0.03600 90.07200 ;
    END
  END wdata[850]
  PIN wdata[851]
    DIRECTION INPUT ;
    USE SIGNAL ;
    PORT
      LAYER M4 ;
      RECT 0.00000 90.09600 0.03600 90.12000 ;
    END
  END wdata[851]
  PIN wdata[852]
    DIRECTION INPUT ;
    USE SIGNAL ;
    PORT
      LAYER M4 ;
      RECT 0.00000 90.14400 0.03600 90.16800 ;
    END
  END wdata[852]
  PIN wdata[853]
    DIRECTION INPUT ;
    USE SIGNAL ;
    PORT
      LAYER M4 ;
      RECT 0.00000 90.19200 0.03600 90.21600 ;
    END
  END wdata[853]
  PIN wdata[854]
    DIRECTION INPUT ;
    USE SIGNAL ;
    PORT
      LAYER M4 ;
      RECT 0.00000 90.24000 0.03600 90.26400 ;
    END
  END wdata[854]
  PIN wdata[855]
    DIRECTION INPUT ;
    USE SIGNAL ;
    PORT
      LAYER M4 ;
      RECT 0.00000 90.28800 0.03600 90.31200 ;
    END
  END wdata[855]
  PIN wdata[856]
    DIRECTION INPUT ;
    USE SIGNAL ;
    PORT
      LAYER M4 ;
      RECT 0.00000 90.33600 0.03600 90.36000 ;
    END
  END wdata[856]
  PIN wdata[857]
    DIRECTION INPUT ;
    USE SIGNAL ;
    PORT
      LAYER M4 ;
      RECT 0.00000 90.38400 0.03600 90.40800 ;
    END
  END wdata[857]
  PIN wdata[858]
    DIRECTION INPUT ;
    USE SIGNAL ;
    PORT
      LAYER M4 ;
      RECT 0.00000 90.43200 0.03600 90.45600 ;
    END
  END wdata[858]
  PIN wdata[859]
    DIRECTION INPUT ;
    USE SIGNAL ;
    PORT
      LAYER M4 ;
      RECT 0.00000 90.48000 0.03600 90.50400 ;
    END
  END wdata[859]
  PIN wdata[860]
    DIRECTION INPUT ;
    USE SIGNAL ;
    PORT
      LAYER M4 ;
      RECT 0.00000 90.52800 0.03600 90.55200 ;
    END
  END wdata[860]
  PIN wdata[861]
    DIRECTION INPUT ;
    USE SIGNAL ;
    PORT
      LAYER M4 ;
      RECT 0.00000 90.57600 0.03600 90.60000 ;
    END
  END wdata[861]
  PIN wdata[862]
    DIRECTION INPUT ;
    USE SIGNAL ;
    PORT
      LAYER M4 ;
      RECT 0.00000 90.62400 0.03600 90.64800 ;
    END
  END wdata[862]
  PIN wdata[863]
    DIRECTION INPUT ;
    USE SIGNAL ;
    PORT
      LAYER M4 ;
      RECT 0.00000 90.67200 0.03600 90.69600 ;
    END
  END wdata[863]
  PIN wdata[864]
    DIRECTION INPUT ;
    USE SIGNAL ;
    PORT
      LAYER M4 ;
      RECT 0.00000 90.72000 0.03600 90.74400 ;
    END
  END wdata[864]
  PIN wdata[865]
    DIRECTION INPUT ;
    USE SIGNAL ;
    PORT
      LAYER M4 ;
      RECT 0.00000 90.76800 0.03600 90.79200 ;
    END
  END wdata[865]
  PIN wdata[866]
    DIRECTION INPUT ;
    USE SIGNAL ;
    PORT
      LAYER M4 ;
      RECT 0.00000 90.81600 0.03600 90.84000 ;
    END
  END wdata[866]
  PIN wdata[867]
    DIRECTION INPUT ;
    USE SIGNAL ;
    PORT
      LAYER M4 ;
      RECT 0.00000 90.86400 0.03600 90.88800 ;
    END
  END wdata[867]
  PIN wdata[868]
    DIRECTION INPUT ;
    USE SIGNAL ;
    PORT
      LAYER M4 ;
      RECT 0.00000 90.91200 0.03600 90.93600 ;
    END
  END wdata[868]
  PIN wdata[869]
    DIRECTION INPUT ;
    USE SIGNAL ;
    PORT
      LAYER M4 ;
      RECT 0.00000 90.96000 0.03600 90.98400 ;
    END
  END wdata[869]
  PIN wdata[870]
    DIRECTION INPUT ;
    USE SIGNAL ;
    PORT
      LAYER M4 ;
      RECT 0.00000 91.00800 0.03600 91.03200 ;
    END
  END wdata[870]
  PIN wdata[871]
    DIRECTION INPUT ;
    USE SIGNAL ;
    PORT
      LAYER M4 ;
      RECT 0.00000 91.05600 0.03600 91.08000 ;
    END
  END wdata[871]
  PIN wdata[872]
    DIRECTION INPUT ;
    USE SIGNAL ;
    PORT
      LAYER M4 ;
      RECT 0.00000 91.10400 0.03600 91.12800 ;
    END
  END wdata[872]
  PIN wdata[873]
    DIRECTION INPUT ;
    USE SIGNAL ;
    PORT
      LAYER M4 ;
      RECT 0.00000 91.15200 0.03600 91.17600 ;
    END
  END wdata[873]
  PIN wdata[874]
    DIRECTION INPUT ;
    USE SIGNAL ;
    PORT
      LAYER M4 ;
      RECT 0.00000 91.20000 0.03600 91.22400 ;
    END
  END wdata[874]
  PIN wdata[875]
    DIRECTION INPUT ;
    USE SIGNAL ;
    PORT
      LAYER M4 ;
      RECT 0.00000 91.24800 0.03600 91.27200 ;
    END
  END wdata[875]
  PIN wdata[876]
    DIRECTION INPUT ;
    USE SIGNAL ;
    PORT
      LAYER M4 ;
      RECT 0.00000 91.29600 0.03600 91.32000 ;
    END
  END wdata[876]
  PIN wdata[877]
    DIRECTION INPUT ;
    USE SIGNAL ;
    PORT
      LAYER M4 ;
      RECT 0.00000 91.34400 0.03600 91.36800 ;
    END
  END wdata[877]
  PIN wdata[878]
    DIRECTION INPUT ;
    USE SIGNAL ;
    PORT
      LAYER M4 ;
      RECT 0.00000 91.39200 0.03600 91.41600 ;
    END
  END wdata[878]
  PIN wdata[879]
    DIRECTION INPUT ;
    USE SIGNAL ;
    PORT
      LAYER M4 ;
      RECT 0.00000 91.44000 0.03600 91.46400 ;
    END
  END wdata[879]
  PIN wdata[880]
    DIRECTION INPUT ;
    USE SIGNAL ;
    PORT
      LAYER M4 ;
      RECT 0.00000 91.48800 0.03600 91.51200 ;
    END
  END wdata[880]
  PIN wdata[881]
    DIRECTION INPUT ;
    USE SIGNAL ;
    PORT
      LAYER M4 ;
      RECT 0.00000 91.53600 0.03600 91.56000 ;
    END
  END wdata[881]
  PIN wdata[882]
    DIRECTION INPUT ;
    USE SIGNAL ;
    PORT
      LAYER M4 ;
      RECT 0.00000 91.58400 0.03600 91.60800 ;
    END
  END wdata[882]
  PIN wdata[883]
    DIRECTION INPUT ;
    USE SIGNAL ;
    PORT
      LAYER M4 ;
      RECT 0.00000 91.63200 0.03600 91.65600 ;
    END
  END wdata[883]
  PIN wdata[884]
    DIRECTION INPUT ;
    USE SIGNAL ;
    PORT
      LAYER M4 ;
      RECT 0.00000 91.68000 0.03600 91.70400 ;
    END
  END wdata[884]
  PIN wdata[885]
    DIRECTION INPUT ;
    USE SIGNAL ;
    PORT
      LAYER M4 ;
      RECT 0.00000 91.72800 0.03600 91.75200 ;
    END
  END wdata[885]
  PIN wdata[886]
    DIRECTION INPUT ;
    USE SIGNAL ;
    PORT
      LAYER M4 ;
      RECT 0.00000 91.77600 0.03600 91.80000 ;
    END
  END wdata[886]
  PIN wdata[887]
    DIRECTION INPUT ;
    USE SIGNAL ;
    PORT
      LAYER M4 ;
      RECT 0.00000 91.82400 0.03600 91.84800 ;
    END
  END wdata[887]
  PIN wdata[888]
    DIRECTION INPUT ;
    USE SIGNAL ;
    PORT
      LAYER M4 ;
      RECT 0.00000 91.87200 0.03600 91.89600 ;
    END
  END wdata[888]
  PIN wdata[889]
    DIRECTION INPUT ;
    USE SIGNAL ;
    PORT
      LAYER M4 ;
      RECT 0.00000 91.92000 0.03600 91.94400 ;
    END
  END wdata[889]
  PIN wdata[890]
    DIRECTION INPUT ;
    USE SIGNAL ;
    PORT
      LAYER M4 ;
      RECT 0.00000 91.96800 0.03600 91.99200 ;
    END
  END wdata[890]
  PIN wdata[891]
    DIRECTION INPUT ;
    USE SIGNAL ;
    PORT
      LAYER M4 ;
      RECT 0.00000 92.01600 0.03600 92.04000 ;
    END
  END wdata[891]
  PIN wdata[892]
    DIRECTION INPUT ;
    USE SIGNAL ;
    PORT
      LAYER M4 ;
      RECT 0.00000 92.06400 0.03600 92.08800 ;
    END
  END wdata[892]
  PIN wdata[893]
    DIRECTION INPUT ;
    USE SIGNAL ;
    PORT
      LAYER M4 ;
      RECT 0.00000 92.11200 0.03600 92.13600 ;
    END
  END wdata[893]
  PIN wdata[894]
    DIRECTION INPUT ;
    USE SIGNAL ;
    PORT
      LAYER M4 ;
      RECT 0.00000 92.16000 0.03600 92.18400 ;
    END
  END wdata[894]
  PIN wdata[895]
    DIRECTION INPUT ;
    USE SIGNAL ;
    PORT
      LAYER M4 ;
      RECT 0.00000 92.20800 0.03600 92.23200 ;
    END
  END wdata[895]
  PIN wdata[896]
    DIRECTION INPUT ;
    USE SIGNAL ;
    PORT
      LAYER M4 ;
      RECT 0.00000 92.25600 0.03600 92.28000 ;
    END
  END wdata[896]
  PIN wdata[897]
    DIRECTION INPUT ;
    USE SIGNAL ;
    PORT
      LAYER M4 ;
      RECT 0.00000 92.30400 0.03600 92.32800 ;
    END
  END wdata[897]
  PIN wdata[898]
    DIRECTION INPUT ;
    USE SIGNAL ;
    PORT
      LAYER M4 ;
      RECT 0.00000 92.35200 0.03600 92.37600 ;
    END
  END wdata[898]
  PIN wdata[899]
    DIRECTION INPUT ;
    USE SIGNAL ;
    PORT
      LAYER M4 ;
      RECT 0.00000 92.40000 0.03600 92.42400 ;
    END
  END wdata[899]
  PIN wdata[900]
    DIRECTION INPUT ;
    USE SIGNAL ;
    PORT
      LAYER M4 ;
      RECT 0.00000 92.44800 0.03600 92.47200 ;
    END
  END wdata[900]
  PIN wdata[901]
    DIRECTION INPUT ;
    USE SIGNAL ;
    PORT
      LAYER M4 ;
      RECT 0.00000 92.49600 0.03600 92.52000 ;
    END
  END wdata[901]
  PIN wdata[902]
    DIRECTION INPUT ;
    USE SIGNAL ;
    PORT
      LAYER M4 ;
      RECT 0.00000 92.54400 0.03600 92.56800 ;
    END
  END wdata[902]
  PIN wdata[903]
    DIRECTION INPUT ;
    USE SIGNAL ;
    PORT
      LAYER M4 ;
      RECT 0.00000 92.59200 0.03600 92.61600 ;
    END
  END wdata[903]
  PIN wdata[904]
    DIRECTION INPUT ;
    USE SIGNAL ;
    PORT
      LAYER M4 ;
      RECT 0.00000 92.64000 0.03600 92.66400 ;
    END
  END wdata[904]
  PIN wdata[905]
    DIRECTION INPUT ;
    USE SIGNAL ;
    PORT
      LAYER M4 ;
      RECT 0.00000 92.68800 0.03600 92.71200 ;
    END
  END wdata[905]
  PIN wdata[906]
    DIRECTION INPUT ;
    USE SIGNAL ;
    PORT
      LAYER M4 ;
      RECT 0.00000 92.73600 0.03600 92.76000 ;
    END
  END wdata[906]
  PIN wdata[907]
    DIRECTION INPUT ;
    USE SIGNAL ;
    PORT
      LAYER M4 ;
      RECT 0.00000 92.78400 0.03600 92.80800 ;
    END
  END wdata[907]
  PIN wdata[908]
    DIRECTION INPUT ;
    USE SIGNAL ;
    PORT
      LAYER M4 ;
      RECT 0.00000 92.83200 0.03600 92.85600 ;
    END
  END wdata[908]
  PIN wdata[909]
    DIRECTION INPUT ;
    USE SIGNAL ;
    PORT
      LAYER M4 ;
      RECT 0.00000 92.88000 0.03600 92.90400 ;
    END
  END wdata[909]
  PIN wdata[910]
    DIRECTION INPUT ;
    USE SIGNAL ;
    PORT
      LAYER M4 ;
      RECT 0.00000 92.92800 0.03600 92.95200 ;
    END
  END wdata[910]
  PIN wdata[911]
    DIRECTION INPUT ;
    USE SIGNAL ;
    PORT
      LAYER M4 ;
      RECT 0.00000 92.97600 0.03600 93.00000 ;
    END
  END wdata[911]
  PIN wdata[912]
    DIRECTION INPUT ;
    USE SIGNAL ;
    PORT
      LAYER M4 ;
      RECT 0.00000 93.02400 0.03600 93.04800 ;
    END
  END wdata[912]
  PIN wdata[913]
    DIRECTION INPUT ;
    USE SIGNAL ;
    PORT
      LAYER M4 ;
      RECT 0.00000 93.07200 0.03600 93.09600 ;
    END
  END wdata[913]
  PIN wdata[914]
    DIRECTION INPUT ;
    USE SIGNAL ;
    PORT
      LAYER M4 ;
      RECT 0.00000 93.12000 0.03600 93.14400 ;
    END
  END wdata[914]
  PIN wdata[915]
    DIRECTION INPUT ;
    USE SIGNAL ;
    PORT
      LAYER M4 ;
      RECT 0.00000 93.16800 0.03600 93.19200 ;
    END
  END wdata[915]
  PIN wdata[916]
    DIRECTION INPUT ;
    USE SIGNAL ;
    PORT
      LAYER M4 ;
      RECT 0.00000 93.21600 0.03600 93.24000 ;
    END
  END wdata[916]
  PIN wdata[917]
    DIRECTION INPUT ;
    USE SIGNAL ;
    PORT
      LAYER M4 ;
      RECT 0.00000 93.26400 0.03600 93.28800 ;
    END
  END wdata[917]
  PIN wdata[918]
    DIRECTION INPUT ;
    USE SIGNAL ;
    PORT
      LAYER M4 ;
      RECT 0.00000 93.31200 0.03600 93.33600 ;
    END
  END wdata[918]
  PIN wdata[919]
    DIRECTION INPUT ;
    USE SIGNAL ;
    PORT
      LAYER M4 ;
      RECT 0.00000 93.36000 0.03600 93.38400 ;
    END
  END wdata[919]
  PIN wdata[920]
    DIRECTION INPUT ;
    USE SIGNAL ;
    PORT
      LAYER M4 ;
      RECT 0.00000 93.40800 0.03600 93.43200 ;
    END
  END wdata[920]
  PIN wdata[921]
    DIRECTION INPUT ;
    USE SIGNAL ;
    PORT
      LAYER M4 ;
      RECT 0.00000 93.45600 0.03600 93.48000 ;
    END
  END wdata[921]
  PIN wdata[922]
    DIRECTION INPUT ;
    USE SIGNAL ;
    PORT
      LAYER M4 ;
      RECT 0.00000 93.50400 0.03600 93.52800 ;
    END
  END wdata[922]
  PIN wdata[923]
    DIRECTION INPUT ;
    USE SIGNAL ;
    PORT
      LAYER M4 ;
      RECT 0.00000 93.55200 0.03600 93.57600 ;
    END
  END wdata[923]
  PIN wdata[924]
    DIRECTION INPUT ;
    USE SIGNAL ;
    PORT
      LAYER M4 ;
      RECT 0.00000 93.60000 0.03600 93.62400 ;
    END
  END wdata[924]
  PIN wdata[925]
    DIRECTION INPUT ;
    USE SIGNAL ;
    PORT
      LAYER M4 ;
      RECT 0.00000 93.64800 0.03600 93.67200 ;
    END
  END wdata[925]
  PIN wdata[926]
    DIRECTION INPUT ;
    USE SIGNAL ;
    PORT
      LAYER M4 ;
      RECT 0.00000 93.69600 0.03600 93.72000 ;
    END
  END wdata[926]
  PIN wdata[927]
    DIRECTION INPUT ;
    USE SIGNAL ;
    PORT
      LAYER M4 ;
      RECT 0.00000 93.74400 0.03600 93.76800 ;
    END
  END wdata[927]
  PIN wdata[928]
    DIRECTION INPUT ;
    USE SIGNAL ;
    PORT
      LAYER M4 ;
      RECT 0.00000 93.79200 0.03600 93.81600 ;
    END
  END wdata[928]
  PIN wdata[929]
    DIRECTION INPUT ;
    USE SIGNAL ;
    PORT
      LAYER M4 ;
      RECT 0.00000 93.84000 0.03600 93.86400 ;
    END
  END wdata[929]
  PIN wdata[930]
    DIRECTION INPUT ;
    USE SIGNAL ;
    PORT
      LAYER M4 ;
      RECT 0.00000 93.88800 0.03600 93.91200 ;
    END
  END wdata[930]
  PIN wdata[931]
    DIRECTION INPUT ;
    USE SIGNAL ;
    PORT
      LAYER M4 ;
      RECT 0.00000 93.93600 0.03600 93.96000 ;
    END
  END wdata[931]
  PIN wdata[932]
    DIRECTION INPUT ;
    USE SIGNAL ;
    PORT
      LAYER M4 ;
      RECT 0.00000 93.98400 0.03600 94.00800 ;
    END
  END wdata[932]
  PIN wdata[933]
    DIRECTION INPUT ;
    USE SIGNAL ;
    PORT
      LAYER M4 ;
      RECT 0.00000 94.03200 0.03600 94.05600 ;
    END
  END wdata[933]
  PIN wdata[934]
    DIRECTION INPUT ;
    USE SIGNAL ;
    PORT
      LAYER M4 ;
      RECT 0.00000 94.08000 0.03600 94.10400 ;
    END
  END wdata[934]
  PIN wdata[935]
    DIRECTION INPUT ;
    USE SIGNAL ;
    PORT
      LAYER M4 ;
      RECT 0.00000 94.12800 0.03600 94.15200 ;
    END
  END wdata[935]
  PIN wdata[936]
    DIRECTION INPUT ;
    USE SIGNAL ;
    PORT
      LAYER M4 ;
      RECT 0.00000 94.17600 0.03600 94.20000 ;
    END
  END wdata[936]
  PIN wdata[937]
    DIRECTION INPUT ;
    USE SIGNAL ;
    PORT
      LAYER M4 ;
      RECT 0.00000 94.22400 0.03600 94.24800 ;
    END
  END wdata[937]
  PIN wdata[938]
    DIRECTION INPUT ;
    USE SIGNAL ;
    PORT
      LAYER M4 ;
      RECT 0.00000 94.27200 0.03600 94.29600 ;
    END
  END wdata[938]
  PIN wdata[939]
    DIRECTION INPUT ;
    USE SIGNAL ;
    PORT
      LAYER M4 ;
      RECT 0.00000 94.32000 0.03600 94.34400 ;
    END
  END wdata[939]
  PIN wdata[940]
    DIRECTION INPUT ;
    USE SIGNAL ;
    PORT
      LAYER M4 ;
      RECT 0.00000 94.36800 0.03600 94.39200 ;
    END
  END wdata[940]
  PIN wdata[941]
    DIRECTION INPUT ;
    USE SIGNAL ;
    PORT
      LAYER M4 ;
      RECT 0.00000 94.41600 0.03600 94.44000 ;
    END
  END wdata[941]
  PIN wdata[942]
    DIRECTION INPUT ;
    USE SIGNAL ;
    PORT
      LAYER M4 ;
      RECT 0.00000 94.46400 0.03600 94.48800 ;
    END
  END wdata[942]
  PIN wdata[943]
    DIRECTION INPUT ;
    USE SIGNAL ;
    PORT
      LAYER M4 ;
      RECT 0.00000 94.51200 0.03600 94.53600 ;
    END
  END wdata[943]
  PIN wdata[944]
    DIRECTION INPUT ;
    USE SIGNAL ;
    PORT
      LAYER M4 ;
      RECT 0.00000 94.56000 0.03600 94.58400 ;
    END
  END wdata[944]
  PIN wdata[945]
    DIRECTION INPUT ;
    USE SIGNAL ;
    PORT
      LAYER M4 ;
      RECT 0.00000 94.60800 0.03600 94.63200 ;
    END
  END wdata[945]
  PIN wdata[946]
    DIRECTION INPUT ;
    USE SIGNAL ;
    PORT
      LAYER M4 ;
      RECT 0.00000 94.65600 0.03600 94.68000 ;
    END
  END wdata[946]
  PIN wdata[947]
    DIRECTION INPUT ;
    USE SIGNAL ;
    PORT
      LAYER M4 ;
      RECT 0.00000 94.70400 0.03600 94.72800 ;
    END
  END wdata[947]
  PIN wdata[948]
    DIRECTION INPUT ;
    USE SIGNAL ;
    PORT
      LAYER M4 ;
      RECT 0.00000 94.75200 0.03600 94.77600 ;
    END
  END wdata[948]
  PIN wdata[949]
    DIRECTION INPUT ;
    USE SIGNAL ;
    PORT
      LAYER M4 ;
      RECT 0.00000 94.80000 0.03600 94.82400 ;
    END
  END wdata[949]
  PIN wdata[950]
    DIRECTION INPUT ;
    USE SIGNAL ;
    PORT
      LAYER M4 ;
      RECT 0.00000 94.84800 0.03600 94.87200 ;
    END
  END wdata[950]
  PIN wdata[951]
    DIRECTION INPUT ;
    USE SIGNAL ;
    PORT
      LAYER M4 ;
      RECT 0.00000 94.89600 0.03600 94.92000 ;
    END
  END wdata[951]
  PIN wdata[952]
    DIRECTION INPUT ;
    USE SIGNAL ;
    PORT
      LAYER M4 ;
      RECT 0.00000 94.94400 0.03600 94.96800 ;
    END
  END wdata[952]
  PIN wdata[953]
    DIRECTION INPUT ;
    USE SIGNAL ;
    PORT
      LAYER M4 ;
      RECT 0.00000 94.99200 0.03600 95.01600 ;
    END
  END wdata[953]
  PIN wdata[954]
    DIRECTION INPUT ;
    USE SIGNAL ;
    PORT
      LAYER M4 ;
      RECT 0.00000 95.04000 0.03600 95.06400 ;
    END
  END wdata[954]
  PIN wdata[955]
    DIRECTION INPUT ;
    USE SIGNAL ;
    PORT
      LAYER M4 ;
      RECT 0.00000 95.08800 0.03600 95.11200 ;
    END
  END wdata[955]
  PIN wdata[956]
    DIRECTION INPUT ;
    USE SIGNAL ;
    PORT
      LAYER M4 ;
      RECT 0.00000 95.13600 0.03600 95.16000 ;
    END
  END wdata[956]
  PIN wdata[957]
    DIRECTION INPUT ;
    USE SIGNAL ;
    PORT
      LAYER M4 ;
      RECT 0.00000 95.18400 0.03600 95.20800 ;
    END
  END wdata[957]
  PIN wdata[958]
    DIRECTION INPUT ;
    USE SIGNAL ;
    PORT
      LAYER M4 ;
      RECT 0.00000 95.23200 0.03600 95.25600 ;
    END
  END wdata[958]
  PIN wdata[959]
    DIRECTION INPUT ;
    USE SIGNAL ;
    PORT
      LAYER M4 ;
      RECT 0.00000 95.28000 0.03600 95.30400 ;
    END
  END wdata[959]
  PIN wdata[960]
    DIRECTION INPUT ;
    USE SIGNAL ;
    PORT
      LAYER M4 ;
      RECT 0.00000 95.32800 0.03600 95.35200 ;
    END
  END wdata[960]
  PIN wdata[961]
    DIRECTION INPUT ;
    USE SIGNAL ;
    PORT
      LAYER M4 ;
      RECT 0.00000 95.37600 0.03600 95.40000 ;
    END
  END wdata[961]
  PIN wdata[962]
    DIRECTION INPUT ;
    USE SIGNAL ;
    PORT
      LAYER M4 ;
      RECT 0.00000 95.42400 0.03600 95.44800 ;
    END
  END wdata[962]
  PIN wdata[963]
    DIRECTION INPUT ;
    USE SIGNAL ;
    PORT
      LAYER M4 ;
      RECT 0.00000 95.47200 0.03600 95.49600 ;
    END
  END wdata[963]
  PIN wdata[964]
    DIRECTION INPUT ;
    USE SIGNAL ;
    PORT
      LAYER M4 ;
      RECT 0.00000 95.52000 0.03600 95.54400 ;
    END
  END wdata[964]
  PIN wdata[965]
    DIRECTION INPUT ;
    USE SIGNAL ;
    PORT
      LAYER M4 ;
      RECT 0.00000 95.56800 0.03600 95.59200 ;
    END
  END wdata[965]
  PIN wdata[966]
    DIRECTION INPUT ;
    USE SIGNAL ;
    PORT
      LAYER M4 ;
      RECT 0.00000 95.61600 0.03600 95.64000 ;
    END
  END wdata[966]
  PIN wdata[967]
    DIRECTION INPUT ;
    USE SIGNAL ;
    PORT
      LAYER M4 ;
      RECT 0.00000 95.66400 0.03600 95.68800 ;
    END
  END wdata[967]
  PIN wdata[968]
    DIRECTION INPUT ;
    USE SIGNAL ;
    PORT
      LAYER M4 ;
      RECT 0.00000 95.71200 0.03600 95.73600 ;
    END
  END wdata[968]
  PIN wdata[969]
    DIRECTION INPUT ;
    USE SIGNAL ;
    PORT
      LAYER M4 ;
      RECT 0.00000 95.76000 0.03600 95.78400 ;
    END
  END wdata[969]
  PIN wdata[970]
    DIRECTION INPUT ;
    USE SIGNAL ;
    PORT
      LAYER M4 ;
      RECT 0.00000 95.80800 0.03600 95.83200 ;
    END
  END wdata[970]
  PIN wdata[971]
    DIRECTION INPUT ;
    USE SIGNAL ;
    PORT
      LAYER M4 ;
      RECT 0.00000 95.85600 0.03600 95.88000 ;
    END
  END wdata[971]
  PIN wdata[972]
    DIRECTION INPUT ;
    USE SIGNAL ;
    PORT
      LAYER M4 ;
      RECT 0.00000 95.90400 0.03600 95.92800 ;
    END
  END wdata[972]
  PIN wdata[973]
    DIRECTION INPUT ;
    USE SIGNAL ;
    PORT
      LAYER M4 ;
      RECT 0.00000 95.95200 0.03600 95.97600 ;
    END
  END wdata[973]
  PIN wdata[974]
    DIRECTION INPUT ;
    USE SIGNAL ;
    PORT
      LAYER M4 ;
      RECT 0.00000 96.00000 0.03600 96.02400 ;
    END
  END wdata[974]
  PIN wdata[975]
    DIRECTION INPUT ;
    USE SIGNAL ;
    PORT
      LAYER M4 ;
      RECT 0.00000 96.04800 0.03600 96.07200 ;
    END
  END wdata[975]
  PIN wdata[976]
    DIRECTION INPUT ;
    USE SIGNAL ;
    PORT
      LAYER M4 ;
      RECT 0.00000 96.09600 0.03600 96.12000 ;
    END
  END wdata[976]
  PIN wdata[977]
    DIRECTION INPUT ;
    USE SIGNAL ;
    PORT
      LAYER M4 ;
      RECT 0.00000 96.14400 0.03600 96.16800 ;
    END
  END wdata[977]
  PIN wdata[978]
    DIRECTION INPUT ;
    USE SIGNAL ;
    PORT
      LAYER M4 ;
      RECT 0.00000 96.19200 0.03600 96.21600 ;
    END
  END wdata[978]
  PIN wdata[979]
    DIRECTION INPUT ;
    USE SIGNAL ;
    PORT
      LAYER M4 ;
      RECT 0.00000 96.24000 0.03600 96.26400 ;
    END
  END wdata[979]
  PIN wdata[980]
    DIRECTION INPUT ;
    USE SIGNAL ;
    PORT
      LAYER M4 ;
      RECT 0.00000 96.28800 0.03600 96.31200 ;
    END
  END wdata[980]
  PIN wdata[981]
    DIRECTION INPUT ;
    USE SIGNAL ;
    PORT
      LAYER M4 ;
      RECT 0.00000 96.33600 0.03600 96.36000 ;
    END
  END wdata[981]
  PIN wdata[982]
    DIRECTION INPUT ;
    USE SIGNAL ;
    PORT
      LAYER M4 ;
      RECT 0.00000 96.38400 0.03600 96.40800 ;
    END
  END wdata[982]
  PIN wdata[983]
    DIRECTION INPUT ;
    USE SIGNAL ;
    PORT
      LAYER M4 ;
      RECT 0.00000 96.43200 0.03600 96.45600 ;
    END
  END wdata[983]
  PIN wdata[984]
    DIRECTION INPUT ;
    USE SIGNAL ;
    PORT
      LAYER M4 ;
      RECT 0.00000 96.48000 0.03600 96.50400 ;
    END
  END wdata[984]
  PIN wdata[985]
    DIRECTION INPUT ;
    USE SIGNAL ;
    PORT
      LAYER M4 ;
      RECT 0.00000 96.52800 0.03600 96.55200 ;
    END
  END wdata[985]
  PIN wdata[986]
    DIRECTION INPUT ;
    USE SIGNAL ;
    PORT
      LAYER M4 ;
      RECT 0.00000 96.57600 0.03600 96.60000 ;
    END
  END wdata[986]
  PIN wdata[987]
    DIRECTION INPUT ;
    USE SIGNAL ;
    PORT
      LAYER M4 ;
      RECT 0.00000 96.62400 0.03600 96.64800 ;
    END
  END wdata[987]
  PIN wdata[988]
    DIRECTION INPUT ;
    USE SIGNAL ;
    PORT
      LAYER M4 ;
      RECT 0.00000 96.67200 0.03600 96.69600 ;
    END
  END wdata[988]
  PIN wdata[989]
    DIRECTION INPUT ;
    USE SIGNAL ;
    PORT
      LAYER M4 ;
      RECT 0.00000 96.72000 0.03600 96.74400 ;
    END
  END wdata[989]
  PIN wdata[990]
    DIRECTION INPUT ;
    USE SIGNAL ;
    PORT
      LAYER M4 ;
      RECT 0.00000 96.76800 0.03600 96.79200 ;
    END
  END wdata[990]
  PIN wdata[991]
    DIRECTION INPUT ;
    USE SIGNAL ;
    PORT
      LAYER M4 ;
      RECT 0.00000 96.81600 0.03600 96.84000 ;
    END
  END wdata[991]
  PIN wdata[992]
    DIRECTION INPUT ;
    USE SIGNAL ;
    PORT
      LAYER M4 ;
      RECT 0.00000 96.86400 0.03600 96.88800 ;
    END
  END wdata[992]
  PIN wdata[993]
    DIRECTION INPUT ;
    USE SIGNAL ;
    PORT
      LAYER M4 ;
      RECT 0.00000 96.91200 0.03600 96.93600 ;
    END
  END wdata[993]
  PIN wdata[994]
    DIRECTION INPUT ;
    USE SIGNAL ;
    PORT
      LAYER M4 ;
      RECT 0.00000 96.96000 0.03600 96.98400 ;
    END
  END wdata[994]
  PIN wdata[995]
    DIRECTION INPUT ;
    USE SIGNAL ;
    PORT
      LAYER M4 ;
      RECT 0.00000 97.00800 0.03600 97.03200 ;
    END
  END wdata[995]
  PIN wdata[996]
    DIRECTION INPUT ;
    USE SIGNAL ;
    PORT
      LAYER M4 ;
      RECT 0.00000 97.05600 0.03600 97.08000 ;
    END
  END wdata[996]
  PIN wdata[997]
    DIRECTION INPUT ;
    USE SIGNAL ;
    PORT
      LAYER M4 ;
      RECT 0.00000 97.10400 0.03600 97.12800 ;
    END
  END wdata[997]
  PIN wdata[998]
    DIRECTION INPUT ;
    USE SIGNAL ;
    PORT
      LAYER M4 ;
      RECT 0.00000 97.15200 0.03600 97.17600 ;
    END
  END wdata[998]
  PIN wdata[999]
    DIRECTION INPUT ;
    USE SIGNAL ;
    PORT
      LAYER M4 ;
      RECT 0.00000 97.20000 0.03600 97.22400 ;
    END
  END wdata[999]
  PIN wdata[1000]
    DIRECTION INPUT ;
    USE SIGNAL ;
    PORT
      LAYER M4 ;
      RECT 0.00000 97.24800 0.03600 97.27200 ;
    END
  END wdata[1000]
  PIN wdata[1001]
    DIRECTION INPUT ;
    USE SIGNAL ;
    PORT
      LAYER M4 ;
      RECT 0.00000 97.29600 0.03600 97.32000 ;
    END
  END wdata[1001]
  PIN wdata[1002]
    DIRECTION INPUT ;
    USE SIGNAL ;
    PORT
      LAYER M4 ;
      RECT 0.00000 97.34400 0.03600 97.36800 ;
    END
  END wdata[1002]
  PIN wdata[1003]
    DIRECTION INPUT ;
    USE SIGNAL ;
    PORT
      LAYER M4 ;
      RECT 0.00000 97.39200 0.03600 97.41600 ;
    END
  END wdata[1003]
  PIN wdata[1004]
    DIRECTION INPUT ;
    USE SIGNAL ;
    PORT
      LAYER M4 ;
      RECT 0.00000 97.44000 0.03600 97.46400 ;
    END
  END wdata[1004]
  PIN wdata[1005]
    DIRECTION INPUT ;
    USE SIGNAL ;
    PORT
      LAYER M4 ;
      RECT 0.00000 97.48800 0.03600 97.51200 ;
    END
  END wdata[1005]
  PIN wdata[1006]
    DIRECTION INPUT ;
    USE SIGNAL ;
    PORT
      LAYER M4 ;
      RECT 0.00000 97.53600 0.03600 97.56000 ;
    END
  END wdata[1006]
  PIN wdata[1007]
    DIRECTION INPUT ;
    USE SIGNAL ;
    PORT
      LAYER M4 ;
      RECT 0.00000 97.58400 0.03600 97.60800 ;
    END
  END wdata[1007]
  PIN wdata[1008]
    DIRECTION INPUT ;
    USE SIGNAL ;
    PORT
      LAYER M4 ;
      RECT 0.00000 97.63200 0.03600 97.65600 ;
    END
  END wdata[1008]
  PIN wdata[1009]
    DIRECTION INPUT ;
    USE SIGNAL ;
    PORT
      LAYER M4 ;
      RECT 0.00000 97.68000 0.03600 97.70400 ;
    END
  END wdata[1009]
  PIN wdata[1010]
    DIRECTION INPUT ;
    USE SIGNAL ;
    PORT
      LAYER M4 ;
      RECT 0.00000 97.72800 0.03600 97.75200 ;
    END
  END wdata[1010]
  PIN wdata[1011]
    DIRECTION INPUT ;
    USE SIGNAL ;
    PORT
      LAYER M4 ;
      RECT 0.00000 97.77600 0.03600 97.80000 ;
    END
  END wdata[1011]
  PIN wdata[1012]
    DIRECTION INPUT ;
    USE SIGNAL ;
    PORT
      LAYER M4 ;
      RECT 0.00000 97.82400 0.03600 97.84800 ;
    END
  END wdata[1012]
  PIN wdata[1013]
    DIRECTION INPUT ;
    USE SIGNAL ;
    PORT
      LAYER M4 ;
      RECT 0.00000 97.87200 0.03600 97.89600 ;
    END
  END wdata[1013]
  PIN wdata[1014]
    DIRECTION INPUT ;
    USE SIGNAL ;
    PORT
      LAYER M4 ;
      RECT 0.00000 97.92000 0.03600 97.94400 ;
    END
  END wdata[1014]
  PIN wdata[1015]
    DIRECTION INPUT ;
    USE SIGNAL ;
    PORT
      LAYER M4 ;
      RECT 0.00000 97.96800 0.03600 97.99200 ;
    END
  END wdata[1015]
  PIN wdata[1016]
    DIRECTION INPUT ;
    USE SIGNAL ;
    PORT
      LAYER M4 ;
      RECT 0.00000 98.01600 0.03600 98.04000 ;
    END
  END wdata[1016]
  PIN wdata[1017]
    DIRECTION INPUT ;
    USE SIGNAL ;
    PORT
      LAYER M4 ;
      RECT 0.00000 98.06400 0.03600 98.08800 ;
    END
  END wdata[1017]
  PIN wdata[1018]
    DIRECTION INPUT ;
    USE SIGNAL ;
    PORT
      LAYER M4 ;
      RECT 0.00000 98.11200 0.03600 98.13600 ;
    END
  END wdata[1018]
  PIN wdata[1019]
    DIRECTION INPUT ;
    USE SIGNAL ;
    PORT
      LAYER M4 ;
      RECT 0.00000 98.16000 0.03600 98.18400 ;
    END
  END wdata[1019]
  PIN wdata[1020]
    DIRECTION INPUT ;
    USE SIGNAL ;
    PORT
      LAYER M4 ;
      RECT 0.00000 98.20800 0.03600 98.23200 ;
    END
  END wdata[1020]
  PIN wdata[1021]
    DIRECTION INPUT ;
    USE SIGNAL ;
    PORT
      LAYER M4 ;
      RECT 0.00000 98.25600 0.03600 98.28000 ;
    END
  END wdata[1021]
  PIN wdata[1022]
    DIRECTION INPUT ;
    USE SIGNAL ;
    PORT
      LAYER M4 ;
      RECT 0.00000 98.30400 0.03600 98.32800 ;
    END
  END wdata[1022]
  PIN wdata[1023]
    DIRECTION INPUT ;
    USE SIGNAL ;
    PORT
      LAYER M4 ;
      RECT 0.00000 98.35200 0.03600 98.37600 ;
    END
  END wdata[1023]
  PIN waddr[0]
    DIRECTION INPUT ;
    USE SIGNAL ;
    PORT
      LAYER M4 ;
      RECT 0.00000 98.44800 0.03600 98.47200 ;
    END
  END waddr[0]
  PIN waddr[1]
    DIRECTION INPUT ;
    USE SIGNAL ;
    PORT
      LAYER M4 ;
      RECT 0.00000 98.49600 0.03600 98.52000 ;
    END
  END waddr[1]
  PIN waddr[2]
    DIRECTION INPUT ;
    USE SIGNAL ;
    PORT
      LAYER M4 ;
      RECT 0.00000 98.54400 0.03600 98.56800 ;
    END
  END waddr[2]
  PIN waddr[3]
    DIRECTION INPUT ;
    USE SIGNAL ;
    PORT
      LAYER M4 ;
      RECT 0.00000 98.59200 0.03600 98.61600 ;
    END
  END waddr[3]
  PIN waddr[4]
    DIRECTION INPUT ;
    USE SIGNAL ;
    PORT
      LAYER M4 ;
      RECT 0.00000 98.64000 0.03600 98.66400 ;
    END
  END waddr[4]
  PIN waddr[5]
    DIRECTION INPUT ;
    USE SIGNAL ;
    PORT
      LAYER M4 ;
      RECT 0.00000 98.68800 0.03600 98.71200 ;
    END
  END waddr[5]
  PIN ra_data[0]
    DIRECTION OUTPUT ;
    USE SIGNAL ;
    PORT
      LAYER M4 ;
      RECT 0.00000 0.04800 0.03600 0.07200 ;
    END
  END ra_data[0]
  PIN ra_data[1]
    DIRECTION OUTPUT ;
    USE SIGNAL ;
    PORT
      LAYER M4 ;
      RECT 0.00000 0.09600 0.03600 0.12000 ;
    END
  END ra_data[1]
  PIN ra_data[2]
    DIRECTION OUTPUT ;
    USE SIGNAL ;
    PORT
      LAYER M4 ;
      RECT 0.00000 0.14400 0.03600 0.16800 ;
    END
  END ra_data[2]
  PIN ra_data[3]
    DIRECTION OUTPUT ;
    USE SIGNAL ;
    PORT
      LAYER M4 ;
      RECT 0.00000 0.19200 0.03600 0.21600 ;
    END
  END ra_data[3]
  PIN ra_data[4]
    DIRECTION OUTPUT ;
    USE SIGNAL ;
    PORT
      LAYER M4 ;
      RECT 0.00000 0.24000 0.03600 0.26400 ;
    END
  END ra_data[4]
  PIN ra_data[5]
    DIRECTION OUTPUT ;
    USE SIGNAL ;
    PORT
      LAYER M4 ;
      RECT 0.00000 0.28800 0.03600 0.31200 ;
    END
  END ra_data[5]
  PIN ra_data[6]
    DIRECTION OUTPUT ;
    USE SIGNAL ;
    PORT
      LAYER M4 ;
      RECT 0.00000 0.33600 0.03600 0.36000 ;
    END
  END ra_data[6]
  PIN ra_data[7]
    DIRECTION OUTPUT ;
    USE SIGNAL ;
    PORT
      LAYER M4 ;
      RECT 0.00000 0.38400 0.03600 0.40800 ;
    END
  END ra_data[7]
  PIN ra_data[8]
    DIRECTION OUTPUT ;
    USE SIGNAL ;
    PORT
      LAYER M4 ;
      RECT 0.00000 0.43200 0.03600 0.45600 ;
    END
  END ra_data[8]
  PIN ra_data[9]
    DIRECTION OUTPUT ;
    USE SIGNAL ;
    PORT
      LAYER M4 ;
      RECT 0.00000 0.48000 0.03600 0.50400 ;
    END
  END ra_data[9]
  PIN ra_data[10]
    DIRECTION OUTPUT ;
    USE SIGNAL ;
    PORT
      LAYER M4 ;
      RECT 0.00000 0.52800 0.03600 0.55200 ;
    END
  END ra_data[10]
  PIN ra_data[11]
    DIRECTION OUTPUT ;
    USE SIGNAL ;
    PORT
      LAYER M4 ;
      RECT 0.00000 0.57600 0.03600 0.60000 ;
    END
  END ra_data[11]
  PIN ra_data[12]
    DIRECTION OUTPUT ;
    USE SIGNAL ;
    PORT
      LAYER M4 ;
      RECT 0.00000 0.62400 0.03600 0.64800 ;
    END
  END ra_data[12]
  PIN ra_data[13]
    DIRECTION OUTPUT ;
    USE SIGNAL ;
    PORT
      LAYER M4 ;
      RECT 0.00000 0.67200 0.03600 0.69600 ;
    END
  END ra_data[13]
  PIN ra_data[14]
    DIRECTION OUTPUT ;
    USE SIGNAL ;
    PORT
      LAYER M4 ;
      RECT 0.00000 0.72000 0.03600 0.74400 ;
    END
  END ra_data[14]
  PIN ra_data[15]
    DIRECTION OUTPUT ;
    USE SIGNAL ;
    PORT
      LAYER M4 ;
      RECT 0.00000 0.76800 0.03600 0.79200 ;
    END
  END ra_data[15]
  PIN ra_data[16]
    DIRECTION OUTPUT ;
    USE SIGNAL ;
    PORT
      LAYER M4 ;
      RECT 0.00000 0.81600 0.03600 0.84000 ;
    END
  END ra_data[16]
  PIN ra_data[17]
    DIRECTION OUTPUT ;
    USE SIGNAL ;
    PORT
      LAYER M4 ;
      RECT 0.00000 0.86400 0.03600 0.88800 ;
    END
  END ra_data[17]
  PIN ra_data[18]
    DIRECTION OUTPUT ;
    USE SIGNAL ;
    PORT
      LAYER M4 ;
      RECT 0.00000 0.91200 0.03600 0.93600 ;
    END
  END ra_data[18]
  PIN ra_data[19]
    DIRECTION OUTPUT ;
    USE SIGNAL ;
    PORT
      LAYER M4 ;
      RECT 0.00000 0.96000 0.03600 0.98400 ;
    END
  END ra_data[19]
  PIN ra_data[20]
    DIRECTION OUTPUT ;
    USE SIGNAL ;
    PORT
      LAYER M4 ;
      RECT 0.00000 1.00800 0.03600 1.03200 ;
    END
  END ra_data[20]
  PIN ra_data[21]
    DIRECTION OUTPUT ;
    USE SIGNAL ;
    PORT
      LAYER M4 ;
      RECT 0.00000 1.05600 0.03600 1.08000 ;
    END
  END ra_data[21]
  PIN ra_data[22]
    DIRECTION OUTPUT ;
    USE SIGNAL ;
    PORT
      LAYER M4 ;
      RECT 0.00000 1.10400 0.03600 1.12800 ;
    END
  END ra_data[22]
  PIN ra_data[23]
    DIRECTION OUTPUT ;
    USE SIGNAL ;
    PORT
      LAYER M4 ;
      RECT 0.00000 1.15200 0.03600 1.17600 ;
    END
  END ra_data[23]
  PIN ra_data[24]
    DIRECTION OUTPUT ;
    USE SIGNAL ;
    PORT
      LAYER M4 ;
      RECT 0.00000 1.20000 0.03600 1.22400 ;
    END
  END ra_data[24]
  PIN ra_data[25]
    DIRECTION OUTPUT ;
    USE SIGNAL ;
    PORT
      LAYER M4 ;
      RECT 0.00000 1.24800 0.03600 1.27200 ;
    END
  END ra_data[25]
  PIN ra_data[26]
    DIRECTION OUTPUT ;
    USE SIGNAL ;
    PORT
      LAYER M4 ;
      RECT 0.00000 1.29600 0.03600 1.32000 ;
    END
  END ra_data[26]
  PIN ra_data[27]
    DIRECTION OUTPUT ;
    USE SIGNAL ;
    PORT
      LAYER M4 ;
      RECT 0.00000 1.34400 0.03600 1.36800 ;
    END
  END ra_data[27]
  PIN ra_data[28]
    DIRECTION OUTPUT ;
    USE SIGNAL ;
    PORT
      LAYER M4 ;
      RECT 0.00000 1.39200 0.03600 1.41600 ;
    END
  END ra_data[28]
  PIN ra_data[29]
    DIRECTION OUTPUT ;
    USE SIGNAL ;
    PORT
      LAYER M4 ;
      RECT 0.00000 1.44000 0.03600 1.46400 ;
    END
  END ra_data[29]
  PIN ra_data[30]
    DIRECTION OUTPUT ;
    USE SIGNAL ;
    PORT
      LAYER M4 ;
      RECT 0.00000 1.48800 0.03600 1.51200 ;
    END
  END ra_data[30]
  PIN ra_data[31]
    DIRECTION OUTPUT ;
    USE SIGNAL ;
    PORT
      LAYER M4 ;
      RECT 0.00000 1.53600 0.03600 1.56000 ;
    END
  END ra_data[31]
  PIN ra_data[32]
    DIRECTION OUTPUT ;
    USE SIGNAL ;
    PORT
      LAYER M4 ;
      RECT 0.00000 1.58400 0.03600 1.60800 ;
    END
  END ra_data[32]
  PIN ra_data[33]
    DIRECTION OUTPUT ;
    USE SIGNAL ;
    PORT
      LAYER M4 ;
      RECT 0.00000 1.63200 0.03600 1.65600 ;
    END
  END ra_data[33]
  PIN ra_data[34]
    DIRECTION OUTPUT ;
    USE SIGNAL ;
    PORT
      LAYER M4 ;
      RECT 0.00000 1.68000 0.03600 1.70400 ;
    END
  END ra_data[34]
  PIN ra_data[35]
    DIRECTION OUTPUT ;
    USE SIGNAL ;
    PORT
      LAYER M4 ;
      RECT 0.00000 1.72800 0.03600 1.75200 ;
    END
  END ra_data[35]
  PIN ra_data[36]
    DIRECTION OUTPUT ;
    USE SIGNAL ;
    PORT
      LAYER M4 ;
      RECT 0.00000 1.77600 0.03600 1.80000 ;
    END
  END ra_data[36]
  PIN ra_data[37]
    DIRECTION OUTPUT ;
    USE SIGNAL ;
    PORT
      LAYER M4 ;
      RECT 0.00000 1.82400 0.03600 1.84800 ;
    END
  END ra_data[37]
  PIN ra_data[38]
    DIRECTION OUTPUT ;
    USE SIGNAL ;
    PORT
      LAYER M4 ;
      RECT 0.00000 1.87200 0.03600 1.89600 ;
    END
  END ra_data[38]
  PIN ra_data[39]
    DIRECTION OUTPUT ;
    USE SIGNAL ;
    PORT
      LAYER M4 ;
      RECT 0.00000 1.92000 0.03600 1.94400 ;
    END
  END ra_data[39]
  PIN ra_data[40]
    DIRECTION OUTPUT ;
    USE SIGNAL ;
    PORT
      LAYER M4 ;
      RECT 0.00000 1.96800 0.03600 1.99200 ;
    END
  END ra_data[40]
  PIN ra_data[41]
    DIRECTION OUTPUT ;
    USE SIGNAL ;
    PORT
      LAYER M4 ;
      RECT 0.00000 2.01600 0.03600 2.04000 ;
    END
  END ra_data[41]
  PIN ra_data[42]
    DIRECTION OUTPUT ;
    USE SIGNAL ;
    PORT
      LAYER M4 ;
      RECT 0.00000 2.06400 0.03600 2.08800 ;
    END
  END ra_data[42]
  PIN ra_data[43]
    DIRECTION OUTPUT ;
    USE SIGNAL ;
    PORT
      LAYER M4 ;
      RECT 0.00000 2.11200 0.03600 2.13600 ;
    END
  END ra_data[43]
  PIN ra_data[44]
    DIRECTION OUTPUT ;
    USE SIGNAL ;
    PORT
      LAYER M4 ;
      RECT 0.00000 2.16000 0.03600 2.18400 ;
    END
  END ra_data[44]
  PIN ra_data[45]
    DIRECTION OUTPUT ;
    USE SIGNAL ;
    PORT
      LAYER M4 ;
      RECT 0.00000 2.20800 0.03600 2.23200 ;
    END
  END ra_data[45]
  PIN ra_data[46]
    DIRECTION OUTPUT ;
    USE SIGNAL ;
    PORT
      LAYER M4 ;
      RECT 0.00000 2.25600 0.03600 2.28000 ;
    END
  END ra_data[46]
  PIN ra_data[47]
    DIRECTION OUTPUT ;
    USE SIGNAL ;
    PORT
      LAYER M4 ;
      RECT 0.00000 2.30400 0.03600 2.32800 ;
    END
  END ra_data[47]
  PIN ra_data[48]
    DIRECTION OUTPUT ;
    USE SIGNAL ;
    PORT
      LAYER M4 ;
      RECT 0.00000 2.35200 0.03600 2.37600 ;
    END
  END ra_data[48]
  PIN ra_data[49]
    DIRECTION OUTPUT ;
    USE SIGNAL ;
    PORT
      LAYER M4 ;
      RECT 0.00000 2.40000 0.03600 2.42400 ;
    END
  END ra_data[49]
  PIN ra_data[50]
    DIRECTION OUTPUT ;
    USE SIGNAL ;
    PORT
      LAYER M4 ;
      RECT 0.00000 2.44800 0.03600 2.47200 ;
    END
  END ra_data[50]
  PIN ra_data[51]
    DIRECTION OUTPUT ;
    USE SIGNAL ;
    PORT
      LAYER M4 ;
      RECT 0.00000 2.49600 0.03600 2.52000 ;
    END
  END ra_data[51]
  PIN ra_data[52]
    DIRECTION OUTPUT ;
    USE SIGNAL ;
    PORT
      LAYER M4 ;
      RECT 0.00000 2.54400 0.03600 2.56800 ;
    END
  END ra_data[52]
  PIN ra_data[53]
    DIRECTION OUTPUT ;
    USE SIGNAL ;
    PORT
      LAYER M4 ;
      RECT 0.00000 2.59200 0.03600 2.61600 ;
    END
  END ra_data[53]
  PIN ra_data[54]
    DIRECTION OUTPUT ;
    USE SIGNAL ;
    PORT
      LAYER M4 ;
      RECT 0.00000 2.64000 0.03600 2.66400 ;
    END
  END ra_data[54]
  PIN ra_data[55]
    DIRECTION OUTPUT ;
    USE SIGNAL ;
    PORT
      LAYER M4 ;
      RECT 0.00000 2.68800 0.03600 2.71200 ;
    END
  END ra_data[55]
  PIN ra_data[56]
    DIRECTION OUTPUT ;
    USE SIGNAL ;
    PORT
      LAYER M4 ;
      RECT 0.00000 2.73600 0.03600 2.76000 ;
    END
  END ra_data[56]
  PIN ra_data[57]
    DIRECTION OUTPUT ;
    USE SIGNAL ;
    PORT
      LAYER M4 ;
      RECT 0.00000 2.78400 0.03600 2.80800 ;
    END
  END ra_data[57]
  PIN ra_data[58]
    DIRECTION OUTPUT ;
    USE SIGNAL ;
    PORT
      LAYER M4 ;
      RECT 0.00000 2.83200 0.03600 2.85600 ;
    END
  END ra_data[58]
  PIN ra_data[59]
    DIRECTION OUTPUT ;
    USE SIGNAL ;
    PORT
      LAYER M4 ;
      RECT 0.00000 2.88000 0.03600 2.90400 ;
    END
  END ra_data[59]
  PIN ra_data[60]
    DIRECTION OUTPUT ;
    USE SIGNAL ;
    PORT
      LAYER M4 ;
      RECT 0.00000 2.92800 0.03600 2.95200 ;
    END
  END ra_data[60]
  PIN ra_data[61]
    DIRECTION OUTPUT ;
    USE SIGNAL ;
    PORT
      LAYER M4 ;
      RECT 0.00000 2.97600 0.03600 3.00000 ;
    END
  END ra_data[61]
  PIN ra_data[62]
    DIRECTION OUTPUT ;
    USE SIGNAL ;
    PORT
      LAYER M4 ;
      RECT 0.00000 3.02400 0.03600 3.04800 ;
    END
  END ra_data[62]
  PIN ra_data[63]
    DIRECTION OUTPUT ;
    USE SIGNAL ;
    PORT
      LAYER M4 ;
      RECT 0.00000 3.07200 0.03600 3.09600 ;
    END
  END ra_data[63]
  PIN ra_data[64]
    DIRECTION OUTPUT ;
    USE SIGNAL ;
    PORT
      LAYER M4 ;
      RECT 0.00000 3.12000 0.03600 3.14400 ;
    END
  END ra_data[64]
  PIN ra_data[65]
    DIRECTION OUTPUT ;
    USE SIGNAL ;
    PORT
      LAYER M4 ;
      RECT 0.00000 3.16800 0.03600 3.19200 ;
    END
  END ra_data[65]
  PIN ra_data[66]
    DIRECTION OUTPUT ;
    USE SIGNAL ;
    PORT
      LAYER M4 ;
      RECT 0.00000 3.21600 0.03600 3.24000 ;
    END
  END ra_data[66]
  PIN ra_data[67]
    DIRECTION OUTPUT ;
    USE SIGNAL ;
    PORT
      LAYER M4 ;
      RECT 0.00000 3.26400 0.03600 3.28800 ;
    END
  END ra_data[67]
  PIN ra_data[68]
    DIRECTION OUTPUT ;
    USE SIGNAL ;
    PORT
      LAYER M4 ;
      RECT 0.00000 3.31200 0.03600 3.33600 ;
    END
  END ra_data[68]
  PIN ra_data[69]
    DIRECTION OUTPUT ;
    USE SIGNAL ;
    PORT
      LAYER M4 ;
      RECT 0.00000 3.36000 0.03600 3.38400 ;
    END
  END ra_data[69]
  PIN ra_data[70]
    DIRECTION OUTPUT ;
    USE SIGNAL ;
    PORT
      LAYER M4 ;
      RECT 0.00000 3.40800 0.03600 3.43200 ;
    END
  END ra_data[70]
  PIN ra_data[71]
    DIRECTION OUTPUT ;
    USE SIGNAL ;
    PORT
      LAYER M4 ;
      RECT 0.00000 3.45600 0.03600 3.48000 ;
    END
  END ra_data[71]
  PIN ra_data[72]
    DIRECTION OUTPUT ;
    USE SIGNAL ;
    PORT
      LAYER M4 ;
      RECT 0.00000 3.50400 0.03600 3.52800 ;
    END
  END ra_data[72]
  PIN ra_data[73]
    DIRECTION OUTPUT ;
    USE SIGNAL ;
    PORT
      LAYER M4 ;
      RECT 0.00000 3.55200 0.03600 3.57600 ;
    END
  END ra_data[73]
  PIN ra_data[74]
    DIRECTION OUTPUT ;
    USE SIGNAL ;
    PORT
      LAYER M4 ;
      RECT 0.00000 3.60000 0.03600 3.62400 ;
    END
  END ra_data[74]
  PIN ra_data[75]
    DIRECTION OUTPUT ;
    USE SIGNAL ;
    PORT
      LAYER M4 ;
      RECT 0.00000 3.64800 0.03600 3.67200 ;
    END
  END ra_data[75]
  PIN ra_data[76]
    DIRECTION OUTPUT ;
    USE SIGNAL ;
    PORT
      LAYER M4 ;
      RECT 0.00000 3.69600 0.03600 3.72000 ;
    END
  END ra_data[76]
  PIN ra_data[77]
    DIRECTION OUTPUT ;
    USE SIGNAL ;
    PORT
      LAYER M4 ;
      RECT 0.00000 3.74400 0.03600 3.76800 ;
    END
  END ra_data[77]
  PIN ra_data[78]
    DIRECTION OUTPUT ;
    USE SIGNAL ;
    PORT
      LAYER M4 ;
      RECT 0.00000 3.79200 0.03600 3.81600 ;
    END
  END ra_data[78]
  PIN ra_data[79]
    DIRECTION OUTPUT ;
    USE SIGNAL ;
    PORT
      LAYER M4 ;
      RECT 0.00000 3.84000 0.03600 3.86400 ;
    END
  END ra_data[79]
  PIN ra_data[80]
    DIRECTION OUTPUT ;
    USE SIGNAL ;
    PORT
      LAYER M4 ;
      RECT 0.00000 3.88800 0.03600 3.91200 ;
    END
  END ra_data[80]
  PIN ra_data[81]
    DIRECTION OUTPUT ;
    USE SIGNAL ;
    PORT
      LAYER M4 ;
      RECT 0.00000 3.93600 0.03600 3.96000 ;
    END
  END ra_data[81]
  PIN ra_data[82]
    DIRECTION OUTPUT ;
    USE SIGNAL ;
    PORT
      LAYER M4 ;
      RECT 0.00000 3.98400 0.03600 4.00800 ;
    END
  END ra_data[82]
  PIN ra_data[83]
    DIRECTION OUTPUT ;
    USE SIGNAL ;
    PORT
      LAYER M4 ;
      RECT 0.00000 4.03200 0.03600 4.05600 ;
    END
  END ra_data[83]
  PIN ra_data[84]
    DIRECTION OUTPUT ;
    USE SIGNAL ;
    PORT
      LAYER M4 ;
      RECT 0.00000 4.08000 0.03600 4.10400 ;
    END
  END ra_data[84]
  PIN ra_data[85]
    DIRECTION OUTPUT ;
    USE SIGNAL ;
    PORT
      LAYER M4 ;
      RECT 0.00000 4.12800 0.03600 4.15200 ;
    END
  END ra_data[85]
  PIN ra_data[86]
    DIRECTION OUTPUT ;
    USE SIGNAL ;
    PORT
      LAYER M4 ;
      RECT 0.00000 4.17600 0.03600 4.20000 ;
    END
  END ra_data[86]
  PIN ra_data[87]
    DIRECTION OUTPUT ;
    USE SIGNAL ;
    PORT
      LAYER M4 ;
      RECT 0.00000 4.22400 0.03600 4.24800 ;
    END
  END ra_data[87]
  PIN ra_data[88]
    DIRECTION OUTPUT ;
    USE SIGNAL ;
    PORT
      LAYER M4 ;
      RECT 0.00000 4.27200 0.03600 4.29600 ;
    END
  END ra_data[88]
  PIN ra_data[89]
    DIRECTION OUTPUT ;
    USE SIGNAL ;
    PORT
      LAYER M4 ;
      RECT 0.00000 4.32000 0.03600 4.34400 ;
    END
  END ra_data[89]
  PIN ra_data[90]
    DIRECTION OUTPUT ;
    USE SIGNAL ;
    PORT
      LAYER M4 ;
      RECT 0.00000 4.36800 0.03600 4.39200 ;
    END
  END ra_data[90]
  PIN ra_data[91]
    DIRECTION OUTPUT ;
    USE SIGNAL ;
    PORT
      LAYER M4 ;
      RECT 0.00000 4.41600 0.03600 4.44000 ;
    END
  END ra_data[91]
  PIN ra_data[92]
    DIRECTION OUTPUT ;
    USE SIGNAL ;
    PORT
      LAYER M4 ;
      RECT 0.00000 4.46400 0.03600 4.48800 ;
    END
  END ra_data[92]
  PIN ra_data[93]
    DIRECTION OUTPUT ;
    USE SIGNAL ;
    PORT
      LAYER M4 ;
      RECT 0.00000 4.51200 0.03600 4.53600 ;
    END
  END ra_data[93]
  PIN ra_data[94]
    DIRECTION OUTPUT ;
    USE SIGNAL ;
    PORT
      LAYER M4 ;
      RECT 0.00000 4.56000 0.03600 4.58400 ;
    END
  END ra_data[94]
  PIN ra_data[95]
    DIRECTION OUTPUT ;
    USE SIGNAL ;
    PORT
      LAYER M4 ;
      RECT 0.00000 4.60800 0.03600 4.63200 ;
    END
  END ra_data[95]
  PIN ra_data[96]
    DIRECTION OUTPUT ;
    USE SIGNAL ;
    PORT
      LAYER M4 ;
      RECT 0.00000 4.65600 0.03600 4.68000 ;
    END
  END ra_data[96]
  PIN ra_data[97]
    DIRECTION OUTPUT ;
    USE SIGNAL ;
    PORT
      LAYER M4 ;
      RECT 0.00000 4.70400 0.03600 4.72800 ;
    END
  END ra_data[97]
  PIN ra_data[98]
    DIRECTION OUTPUT ;
    USE SIGNAL ;
    PORT
      LAYER M4 ;
      RECT 0.00000 4.75200 0.03600 4.77600 ;
    END
  END ra_data[98]
  PIN ra_data[99]
    DIRECTION OUTPUT ;
    USE SIGNAL ;
    PORT
      LAYER M4 ;
      RECT 0.00000 4.80000 0.03600 4.82400 ;
    END
  END ra_data[99]
  PIN ra_data[100]
    DIRECTION OUTPUT ;
    USE SIGNAL ;
    PORT
      LAYER M4 ;
      RECT 0.00000 4.84800 0.03600 4.87200 ;
    END
  END ra_data[100]
  PIN ra_data[101]
    DIRECTION OUTPUT ;
    USE SIGNAL ;
    PORT
      LAYER M4 ;
      RECT 0.00000 4.89600 0.03600 4.92000 ;
    END
  END ra_data[101]
  PIN ra_data[102]
    DIRECTION OUTPUT ;
    USE SIGNAL ;
    PORT
      LAYER M4 ;
      RECT 0.00000 4.94400 0.03600 4.96800 ;
    END
  END ra_data[102]
  PIN ra_data[103]
    DIRECTION OUTPUT ;
    USE SIGNAL ;
    PORT
      LAYER M4 ;
      RECT 0.00000 4.99200 0.03600 5.01600 ;
    END
  END ra_data[103]
  PIN ra_data[104]
    DIRECTION OUTPUT ;
    USE SIGNAL ;
    PORT
      LAYER M4 ;
      RECT 0.00000 5.04000 0.03600 5.06400 ;
    END
  END ra_data[104]
  PIN ra_data[105]
    DIRECTION OUTPUT ;
    USE SIGNAL ;
    PORT
      LAYER M4 ;
      RECT 0.00000 5.08800 0.03600 5.11200 ;
    END
  END ra_data[105]
  PIN ra_data[106]
    DIRECTION OUTPUT ;
    USE SIGNAL ;
    PORT
      LAYER M4 ;
      RECT 0.00000 5.13600 0.03600 5.16000 ;
    END
  END ra_data[106]
  PIN ra_data[107]
    DIRECTION OUTPUT ;
    USE SIGNAL ;
    PORT
      LAYER M4 ;
      RECT 0.00000 5.18400 0.03600 5.20800 ;
    END
  END ra_data[107]
  PIN ra_data[108]
    DIRECTION OUTPUT ;
    USE SIGNAL ;
    PORT
      LAYER M4 ;
      RECT 0.00000 5.23200 0.03600 5.25600 ;
    END
  END ra_data[108]
  PIN ra_data[109]
    DIRECTION OUTPUT ;
    USE SIGNAL ;
    PORT
      LAYER M4 ;
      RECT 0.00000 5.28000 0.03600 5.30400 ;
    END
  END ra_data[109]
  PIN ra_data[110]
    DIRECTION OUTPUT ;
    USE SIGNAL ;
    PORT
      LAYER M4 ;
      RECT 0.00000 5.32800 0.03600 5.35200 ;
    END
  END ra_data[110]
  PIN ra_data[111]
    DIRECTION OUTPUT ;
    USE SIGNAL ;
    PORT
      LAYER M4 ;
      RECT 0.00000 5.37600 0.03600 5.40000 ;
    END
  END ra_data[111]
  PIN ra_data[112]
    DIRECTION OUTPUT ;
    USE SIGNAL ;
    PORT
      LAYER M4 ;
      RECT 0.00000 5.42400 0.03600 5.44800 ;
    END
  END ra_data[112]
  PIN ra_data[113]
    DIRECTION OUTPUT ;
    USE SIGNAL ;
    PORT
      LAYER M4 ;
      RECT 0.00000 5.47200 0.03600 5.49600 ;
    END
  END ra_data[113]
  PIN ra_data[114]
    DIRECTION OUTPUT ;
    USE SIGNAL ;
    PORT
      LAYER M4 ;
      RECT 0.00000 5.52000 0.03600 5.54400 ;
    END
  END ra_data[114]
  PIN ra_data[115]
    DIRECTION OUTPUT ;
    USE SIGNAL ;
    PORT
      LAYER M4 ;
      RECT 0.00000 5.56800 0.03600 5.59200 ;
    END
  END ra_data[115]
  PIN ra_data[116]
    DIRECTION OUTPUT ;
    USE SIGNAL ;
    PORT
      LAYER M4 ;
      RECT 0.00000 5.61600 0.03600 5.64000 ;
    END
  END ra_data[116]
  PIN ra_data[117]
    DIRECTION OUTPUT ;
    USE SIGNAL ;
    PORT
      LAYER M4 ;
      RECT 0.00000 5.66400 0.03600 5.68800 ;
    END
  END ra_data[117]
  PIN ra_data[118]
    DIRECTION OUTPUT ;
    USE SIGNAL ;
    PORT
      LAYER M4 ;
      RECT 0.00000 5.71200 0.03600 5.73600 ;
    END
  END ra_data[118]
  PIN ra_data[119]
    DIRECTION OUTPUT ;
    USE SIGNAL ;
    PORT
      LAYER M4 ;
      RECT 0.00000 5.76000 0.03600 5.78400 ;
    END
  END ra_data[119]
  PIN ra_data[120]
    DIRECTION OUTPUT ;
    USE SIGNAL ;
    PORT
      LAYER M4 ;
      RECT 0.00000 5.80800 0.03600 5.83200 ;
    END
  END ra_data[120]
  PIN ra_data[121]
    DIRECTION OUTPUT ;
    USE SIGNAL ;
    PORT
      LAYER M4 ;
      RECT 0.00000 5.85600 0.03600 5.88000 ;
    END
  END ra_data[121]
  PIN ra_data[122]
    DIRECTION OUTPUT ;
    USE SIGNAL ;
    PORT
      LAYER M4 ;
      RECT 0.00000 5.90400 0.03600 5.92800 ;
    END
  END ra_data[122]
  PIN ra_data[123]
    DIRECTION OUTPUT ;
    USE SIGNAL ;
    PORT
      LAYER M4 ;
      RECT 0.00000 5.95200 0.03600 5.97600 ;
    END
  END ra_data[123]
  PIN ra_data[124]
    DIRECTION OUTPUT ;
    USE SIGNAL ;
    PORT
      LAYER M4 ;
      RECT 0.00000 6.00000 0.03600 6.02400 ;
    END
  END ra_data[124]
  PIN ra_data[125]
    DIRECTION OUTPUT ;
    USE SIGNAL ;
    PORT
      LAYER M4 ;
      RECT 0.00000 6.04800 0.03600 6.07200 ;
    END
  END ra_data[125]
  PIN ra_data[126]
    DIRECTION OUTPUT ;
    USE SIGNAL ;
    PORT
      LAYER M4 ;
      RECT 0.00000 6.09600 0.03600 6.12000 ;
    END
  END ra_data[126]
  PIN ra_data[127]
    DIRECTION OUTPUT ;
    USE SIGNAL ;
    PORT
      LAYER M4 ;
      RECT 0.00000 6.14400 0.03600 6.16800 ;
    END
  END ra_data[127]
  PIN ra_data[128]
    DIRECTION OUTPUT ;
    USE SIGNAL ;
    PORT
      LAYER M4 ;
      RECT 0.00000 6.19200 0.03600 6.21600 ;
    END
  END ra_data[128]
  PIN ra_data[129]
    DIRECTION OUTPUT ;
    USE SIGNAL ;
    PORT
      LAYER M4 ;
      RECT 0.00000 6.24000 0.03600 6.26400 ;
    END
  END ra_data[129]
  PIN ra_data[130]
    DIRECTION OUTPUT ;
    USE SIGNAL ;
    PORT
      LAYER M4 ;
      RECT 0.00000 6.28800 0.03600 6.31200 ;
    END
  END ra_data[130]
  PIN ra_data[131]
    DIRECTION OUTPUT ;
    USE SIGNAL ;
    PORT
      LAYER M4 ;
      RECT 0.00000 6.33600 0.03600 6.36000 ;
    END
  END ra_data[131]
  PIN ra_data[132]
    DIRECTION OUTPUT ;
    USE SIGNAL ;
    PORT
      LAYER M4 ;
      RECT 0.00000 6.38400 0.03600 6.40800 ;
    END
  END ra_data[132]
  PIN ra_data[133]
    DIRECTION OUTPUT ;
    USE SIGNAL ;
    PORT
      LAYER M4 ;
      RECT 0.00000 6.43200 0.03600 6.45600 ;
    END
  END ra_data[133]
  PIN ra_data[134]
    DIRECTION OUTPUT ;
    USE SIGNAL ;
    PORT
      LAYER M4 ;
      RECT 0.00000 6.48000 0.03600 6.50400 ;
    END
  END ra_data[134]
  PIN ra_data[135]
    DIRECTION OUTPUT ;
    USE SIGNAL ;
    PORT
      LAYER M4 ;
      RECT 0.00000 6.52800 0.03600 6.55200 ;
    END
  END ra_data[135]
  PIN ra_data[136]
    DIRECTION OUTPUT ;
    USE SIGNAL ;
    PORT
      LAYER M4 ;
      RECT 0.00000 6.57600 0.03600 6.60000 ;
    END
  END ra_data[136]
  PIN ra_data[137]
    DIRECTION OUTPUT ;
    USE SIGNAL ;
    PORT
      LAYER M4 ;
      RECT 0.00000 6.62400 0.03600 6.64800 ;
    END
  END ra_data[137]
  PIN ra_data[138]
    DIRECTION OUTPUT ;
    USE SIGNAL ;
    PORT
      LAYER M4 ;
      RECT 0.00000 6.67200 0.03600 6.69600 ;
    END
  END ra_data[138]
  PIN ra_data[139]
    DIRECTION OUTPUT ;
    USE SIGNAL ;
    PORT
      LAYER M4 ;
      RECT 0.00000 6.72000 0.03600 6.74400 ;
    END
  END ra_data[139]
  PIN ra_data[140]
    DIRECTION OUTPUT ;
    USE SIGNAL ;
    PORT
      LAYER M4 ;
      RECT 0.00000 6.76800 0.03600 6.79200 ;
    END
  END ra_data[140]
  PIN ra_data[141]
    DIRECTION OUTPUT ;
    USE SIGNAL ;
    PORT
      LAYER M4 ;
      RECT 0.00000 6.81600 0.03600 6.84000 ;
    END
  END ra_data[141]
  PIN ra_data[142]
    DIRECTION OUTPUT ;
    USE SIGNAL ;
    PORT
      LAYER M4 ;
      RECT 0.00000 6.86400 0.03600 6.88800 ;
    END
  END ra_data[142]
  PIN ra_data[143]
    DIRECTION OUTPUT ;
    USE SIGNAL ;
    PORT
      LAYER M4 ;
      RECT 0.00000 6.91200 0.03600 6.93600 ;
    END
  END ra_data[143]
  PIN ra_data[144]
    DIRECTION OUTPUT ;
    USE SIGNAL ;
    PORT
      LAYER M4 ;
      RECT 0.00000 6.96000 0.03600 6.98400 ;
    END
  END ra_data[144]
  PIN ra_data[145]
    DIRECTION OUTPUT ;
    USE SIGNAL ;
    PORT
      LAYER M4 ;
      RECT 0.00000 7.00800 0.03600 7.03200 ;
    END
  END ra_data[145]
  PIN ra_data[146]
    DIRECTION OUTPUT ;
    USE SIGNAL ;
    PORT
      LAYER M4 ;
      RECT 0.00000 7.05600 0.03600 7.08000 ;
    END
  END ra_data[146]
  PIN ra_data[147]
    DIRECTION OUTPUT ;
    USE SIGNAL ;
    PORT
      LAYER M4 ;
      RECT 0.00000 7.10400 0.03600 7.12800 ;
    END
  END ra_data[147]
  PIN ra_data[148]
    DIRECTION OUTPUT ;
    USE SIGNAL ;
    PORT
      LAYER M4 ;
      RECT 0.00000 7.15200 0.03600 7.17600 ;
    END
  END ra_data[148]
  PIN ra_data[149]
    DIRECTION OUTPUT ;
    USE SIGNAL ;
    PORT
      LAYER M4 ;
      RECT 0.00000 7.20000 0.03600 7.22400 ;
    END
  END ra_data[149]
  PIN ra_data[150]
    DIRECTION OUTPUT ;
    USE SIGNAL ;
    PORT
      LAYER M4 ;
      RECT 0.00000 7.24800 0.03600 7.27200 ;
    END
  END ra_data[150]
  PIN ra_data[151]
    DIRECTION OUTPUT ;
    USE SIGNAL ;
    PORT
      LAYER M4 ;
      RECT 0.00000 7.29600 0.03600 7.32000 ;
    END
  END ra_data[151]
  PIN ra_data[152]
    DIRECTION OUTPUT ;
    USE SIGNAL ;
    PORT
      LAYER M4 ;
      RECT 0.00000 7.34400 0.03600 7.36800 ;
    END
  END ra_data[152]
  PIN ra_data[153]
    DIRECTION OUTPUT ;
    USE SIGNAL ;
    PORT
      LAYER M4 ;
      RECT 0.00000 7.39200 0.03600 7.41600 ;
    END
  END ra_data[153]
  PIN ra_data[154]
    DIRECTION OUTPUT ;
    USE SIGNAL ;
    PORT
      LAYER M4 ;
      RECT 0.00000 7.44000 0.03600 7.46400 ;
    END
  END ra_data[154]
  PIN ra_data[155]
    DIRECTION OUTPUT ;
    USE SIGNAL ;
    PORT
      LAYER M4 ;
      RECT 0.00000 7.48800 0.03600 7.51200 ;
    END
  END ra_data[155]
  PIN ra_data[156]
    DIRECTION OUTPUT ;
    USE SIGNAL ;
    PORT
      LAYER M4 ;
      RECT 0.00000 7.53600 0.03600 7.56000 ;
    END
  END ra_data[156]
  PIN ra_data[157]
    DIRECTION OUTPUT ;
    USE SIGNAL ;
    PORT
      LAYER M4 ;
      RECT 0.00000 7.58400 0.03600 7.60800 ;
    END
  END ra_data[157]
  PIN ra_data[158]
    DIRECTION OUTPUT ;
    USE SIGNAL ;
    PORT
      LAYER M4 ;
      RECT 0.00000 7.63200 0.03600 7.65600 ;
    END
  END ra_data[158]
  PIN ra_data[159]
    DIRECTION OUTPUT ;
    USE SIGNAL ;
    PORT
      LAYER M4 ;
      RECT 0.00000 7.68000 0.03600 7.70400 ;
    END
  END ra_data[159]
  PIN ra_data[160]
    DIRECTION OUTPUT ;
    USE SIGNAL ;
    PORT
      LAYER M4 ;
      RECT 0.00000 7.72800 0.03600 7.75200 ;
    END
  END ra_data[160]
  PIN ra_data[161]
    DIRECTION OUTPUT ;
    USE SIGNAL ;
    PORT
      LAYER M4 ;
      RECT 0.00000 7.77600 0.03600 7.80000 ;
    END
  END ra_data[161]
  PIN ra_data[162]
    DIRECTION OUTPUT ;
    USE SIGNAL ;
    PORT
      LAYER M4 ;
      RECT 0.00000 7.82400 0.03600 7.84800 ;
    END
  END ra_data[162]
  PIN ra_data[163]
    DIRECTION OUTPUT ;
    USE SIGNAL ;
    PORT
      LAYER M4 ;
      RECT 0.00000 7.87200 0.03600 7.89600 ;
    END
  END ra_data[163]
  PIN ra_data[164]
    DIRECTION OUTPUT ;
    USE SIGNAL ;
    PORT
      LAYER M4 ;
      RECT 0.00000 7.92000 0.03600 7.94400 ;
    END
  END ra_data[164]
  PIN ra_data[165]
    DIRECTION OUTPUT ;
    USE SIGNAL ;
    PORT
      LAYER M4 ;
      RECT 0.00000 7.96800 0.03600 7.99200 ;
    END
  END ra_data[165]
  PIN ra_data[166]
    DIRECTION OUTPUT ;
    USE SIGNAL ;
    PORT
      LAYER M4 ;
      RECT 0.00000 8.01600 0.03600 8.04000 ;
    END
  END ra_data[166]
  PIN ra_data[167]
    DIRECTION OUTPUT ;
    USE SIGNAL ;
    PORT
      LAYER M4 ;
      RECT 0.00000 8.06400 0.03600 8.08800 ;
    END
  END ra_data[167]
  PIN ra_data[168]
    DIRECTION OUTPUT ;
    USE SIGNAL ;
    PORT
      LAYER M4 ;
      RECT 0.00000 8.11200 0.03600 8.13600 ;
    END
  END ra_data[168]
  PIN ra_data[169]
    DIRECTION OUTPUT ;
    USE SIGNAL ;
    PORT
      LAYER M4 ;
      RECT 0.00000 8.16000 0.03600 8.18400 ;
    END
  END ra_data[169]
  PIN ra_data[170]
    DIRECTION OUTPUT ;
    USE SIGNAL ;
    PORT
      LAYER M4 ;
      RECT 0.00000 8.20800 0.03600 8.23200 ;
    END
  END ra_data[170]
  PIN ra_data[171]
    DIRECTION OUTPUT ;
    USE SIGNAL ;
    PORT
      LAYER M4 ;
      RECT 0.00000 8.25600 0.03600 8.28000 ;
    END
  END ra_data[171]
  PIN ra_data[172]
    DIRECTION OUTPUT ;
    USE SIGNAL ;
    PORT
      LAYER M4 ;
      RECT 0.00000 8.30400 0.03600 8.32800 ;
    END
  END ra_data[172]
  PIN ra_data[173]
    DIRECTION OUTPUT ;
    USE SIGNAL ;
    PORT
      LAYER M4 ;
      RECT 0.00000 8.35200 0.03600 8.37600 ;
    END
  END ra_data[173]
  PIN ra_data[174]
    DIRECTION OUTPUT ;
    USE SIGNAL ;
    PORT
      LAYER M4 ;
      RECT 0.00000 8.40000 0.03600 8.42400 ;
    END
  END ra_data[174]
  PIN ra_data[175]
    DIRECTION OUTPUT ;
    USE SIGNAL ;
    PORT
      LAYER M4 ;
      RECT 0.00000 8.44800 0.03600 8.47200 ;
    END
  END ra_data[175]
  PIN ra_data[176]
    DIRECTION OUTPUT ;
    USE SIGNAL ;
    PORT
      LAYER M4 ;
      RECT 0.00000 8.49600 0.03600 8.52000 ;
    END
  END ra_data[176]
  PIN ra_data[177]
    DIRECTION OUTPUT ;
    USE SIGNAL ;
    PORT
      LAYER M4 ;
      RECT 0.00000 8.54400 0.03600 8.56800 ;
    END
  END ra_data[177]
  PIN ra_data[178]
    DIRECTION OUTPUT ;
    USE SIGNAL ;
    PORT
      LAYER M4 ;
      RECT 0.00000 8.59200 0.03600 8.61600 ;
    END
  END ra_data[178]
  PIN ra_data[179]
    DIRECTION OUTPUT ;
    USE SIGNAL ;
    PORT
      LAYER M4 ;
      RECT 0.00000 8.64000 0.03600 8.66400 ;
    END
  END ra_data[179]
  PIN ra_data[180]
    DIRECTION OUTPUT ;
    USE SIGNAL ;
    PORT
      LAYER M4 ;
      RECT 0.00000 8.68800 0.03600 8.71200 ;
    END
  END ra_data[180]
  PIN ra_data[181]
    DIRECTION OUTPUT ;
    USE SIGNAL ;
    PORT
      LAYER M4 ;
      RECT 0.00000 8.73600 0.03600 8.76000 ;
    END
  END ra_data[181]
  PIN ra_data[182]
    DIRECTION OUTPUT ;
    USE SIGNAL ;
    PORT
      LAYER M4 ;
      RECT 0.00000 8.78400 0.03600 8.80800 ;
    END
  END ra_data[182]
  PIN ra_data[183]
    DIRECTION OUTPUT ;
    USE SIGNAL ;
    PORT
      LAYER M4 ;
      RECT 0.00000 8.83200 0.03600 8.85600 ;
    END
  END ra_data[183]
  PIN ra_data[184]
    DIRECTION OUTPUT ;
    USE SIGNAL ;
    PORT
      LAYER M4 ;
      RECT 0.00000 8.88000 0.03600 8.90400 ;
    END
  END ra_data[184]
  PIN ra_data[185]
    DIRECTION OUTPUT ;
    USE SIGNAL ;
    PORT
      LAYER M4 ;
      RECT 0.00000 8.92800 0.03600 8.95200 ;
    END
  END ra_data[185]
  PIN ra_data[186]
    DIRECTION OUTPUT ;
    USE SIGNAL ;
    PORT
      LAYER M4 ;
      RECT 0.00000 8.97600 0.03600 9.00000 ;
    END
  END ra_data[186]
  PIN ra_data[187]
    DIRECTION OUTPUT ;
    USE SIGNAL ;
    PORT
      LAYER M4 ;
      RECT 0.00000 9.02400 0.03600 9.04800 ;
    END
  END ra_data[187]
  PIN ra_data[188]
    DIRECTION OUTPUT ;
    USE SIGNAL ;
    PORT
      LAYER M4 ;
      RECT 0.00000 9.07200 0.03600 9.09600 ;
    END
  END ra_data[188]
  PIN ra_data[189]
    DIRECTION OUTPUT ;
    USE SIGNAL ;
    PORT
      LAYER M4 ;
      RECT 0.00000 9.12000 0.03600 9.14400 ;
    END
  END ra_data[189]
  PIN ra_data[190]
    DIRECTION OUTPUT ;
    USE SIGNAL ;
    PORT
      LAYER M4 ;
      RECT 0.00000 9.16800 0.03600 9.19200 ;
    END
  END ra_data[190]
  PIN ra_data[191]
    DIRECTION OUTPUT ;
    USE SIGNAL ;
    PORT
      LAYER M4 ;
      RECT 0.00000 9.21600 0.03600 9.24000 ;
    END
  END ra_data[191]
  PIN ra_data[192]
    DIRECTION OUTPUT ;
    USE SIGNAL ;
    PORT
      LAYER M4 ;
      RECT 0.00000 9.26400 0.03600 9.28800 ;
    END
  END ra_data[192]
  PIN ra_data[193]
    DIRECTION OUTPUT ;
    USE SIGNAL ;
    PORT
      LAYER M4 ;
      RECT 0.00000 9.31200 0.03600 9.33600 ;
    END
  END ra_data[193]
  PIN ra_data[194]
    DIRECTION OUTPUT ;
    USE SIGNAL ;
    PORT
      LAYER M4 ;
      RECT 0.00000 9.36000 0.03600 9.38400 ;
    END
  END ra_data[194]
  PIN ra_data[195]
    DIRECTION OUTPUT ;
    USE SIGNAL ;
    PORT
      LAYER M4 ;
      RECT 0.00000 9.40800 0.03600 9.43200 ;
    END
  END ra_data[195]
  PIN ra_data[196]
    DIRECTION OUTPUT ;
    USE SIGNAL ;
    PORT
      LAYER M4 ;
      RECT 0.00000 9.45600 0.03600 9.48000 ;
    END
  END ra_data[196]
  PIN ra_data[197]
    DIRECTION OUTPUT ;
    USE SIGNAL ;
    PORT
      LAYER M4 ;
      RECT 0.00000 9.50400 0.03600 9.52800 ;
    END
  END ra_data[197]
  PIN ra_data[198]
    DIRECTION OUTPUT ;
    USE SIGNAL ;
    PORT
      LAYER M4 ;
      RECT 0.00000 9.55200 0.03600 9.57600 ;
    END
  END ra_data[198]
  PIN ra_data[199]
    DIRECTION OUTPUT ;
    USE SIGNAL ;
    PORT
      LAYER M4 ;
      RECT 0.00000 9.60000 0.03600 9.62400 ;
    END
  END ra_data[199]
  PIN ra_data[200]
    DIRECTION OUTPUT ;
    USE SIGNAL ;
    PORT
      LAYER M4 ;
      RECT 0.00000 9.64800 0.03600 9.67200 ;
    END
  END ra_data[200]
  PIN ra_data[201]
    DIRECTION OUTPUT ;
    USE SIGNAL ;
    PORT
      LAYER M4 ;
      RECT 0.00000 9.69600 0.03600 9.72000 ;
    END
  END ra_data[201]
  PIN ra_data[202]
    DIRECTION OUTPUT ;
    USE SIGNAL ;
    PORT
      LAYER M4 ;
      RECT 0.00000 9.74400 0.03600 9.76800 ;
    END
  END ra_data[202]
  PIN ra_data[203]
    DIRECTION OUTPUT ;
    USE SIGNAL ;
    PORT
      LAYER M4 ;
      RECT 0.00000 9.79200 0.03600 9.81600 ;
    END
  END ra_data[203]
  PIN ra_data[204]
    DIRECTION OUTPUT ;
    USE SIGNAL ;
    PORT
      LAYER M4 ;
      RECT 0.00000 9.84000 0.03600 9.86400 ;
    END
  END ra_data[204]
  PIN ra_data[205]
    DIRECTION OUTPUT ;
    USE SIGNAL ;
    PORT
      LAYER M4 ;
      RECT 0.00000 9.88800 0.03600 9.91200 ;
    END
  END ra_data[205]
  PIN ra_data[206]
    DIRECTION OUTPUT ;
    USE SIGNAL ;
    PORT
      LAYER M4 ;
      RECT 0.00000 9.93600 0.03600 9.96000 ;
    END
  END ra_data[206]
  PIN ra_data[207]
    DIRECTION OUTPUT ;
    USE SIGNAL ;
    PORT
      LAYER M4 ;
      RECT 0.00000 9.98400 0.03600 10.00800 ;
    END
  END ra_data[207]
  PIN ra_data[208]
    DIRECTION OUTPUT ;
    USE SIGNAL ;
    PORT
      LAYER M4 ;
      RECT 0.00000 10.03200 0.03600 10.05600 ;
    END
  END ra_data[208]
  PIN ra_data[209]
    DIRECTION OUTPUT ;
    USE SIGNAL ;
    PORT
      LAYER M4 ;
      RECT 0.00000 10.08000 0.03600 10.10400 ;
    END
  END ra_data[209]
  PIN ra_data[210]
    DIRECTION OUTPUT ;
    USE SIGNAL ;
    PORT
      LAYER M4 ;
      RECT 0.00000 10.12800 0.03600 10.15200 ;
    END
  END ra_data[210]
  PIN ra_data[211]
    DIRECTION OUTPUT ;
    USE SIGNAL ;
    PORT
      LAYER M4 ;
      RECT 0.00000 10.17600 0.03600 10.20000 ;
    END
  END ra_data[211]
  PIN ra_data[212]
    DIRECTION OUTPUT ;
    USE SIGNAL ;
    PORT
      LAYER M4 ;
      RECT 0.00000 10.22400 0.03600 10.24800 ;
    END
  END ra_data[212]
  PIN ra_data[213]
    DIRECTION OUTPUT ;
    USE SIGNAL ;
    PORT
      LAYER M4 ;
      RECT 0.00000 10.27200 0.03600 10.29600 ;
    END
  END ra_data[213]
  PIN ra_data[214]
    DIRECTION OUTPUT ;
    USE SIGNAL ;
    PORT
      LAYER M4 ;
      RECT 0.00000 10.32000 0.03600 10.34400 ;
    END
  END ra_data[214]
  PIN ra_data[215]
    DIRECTION OUTPUT ;
    USE SIGNAL ;
    PORT
      LAYER M4 ;
      RECT 0.00000 10.36800 0.03600 10.39200 ;
    END
  END ra_data[215]
  PIN ra_data[216]
    DIRECTION OUTPUT ;
    USE SIGNAL ;
    PORT
      LAYER M4 ;
      RECT 0.00000 10.41600 0.03600 10.44000 ;
    END
  END ra_data[216]
  PIN ra_data[217]
    DIRECTION OUTPUT ;
    USE SIGNAL ;
    PORT
      LAYER M4 ;
      RECT 0.00000 10.46400 0.03600 10.48800 ;
    END
  END ra_data[217]
  PIN ra_data[218]
    DIRECTION OUTPUT ;
    USE SIGNAL ;
    PORT
      LAYER M4 ;
      RECT 0.00000 10.51200 0.03600 10.53600 ;
    END
  END ra_data[218]
  PIN ra_data[219]
    DIRECTION OUTPUT ;
    USE SIGNAL ;
    PORT
      LAYER M4 ;
      RECT 0.00000 10.56000 0.03600 10.58400 ;
    END
  END ra_data[219]
  PIN ra_data[220]
    DIRECTION OUTPUT ;
    USE SIGNAL ;
    PORT
      LAYER M4 ;
      RECT 0.00000 10.60800 0.03600 10.63200 ;
    END
  END ra_data[220]
  PIN ra_data[221]
    DIRECTION OUTPUT ;
    USE SIGNAL ;
    PORT
      LAYER M4 ;
      RECT 0.00000 10.65600 0.03600 10.68000 ;
    END
  END ra_data[221]
  PIN ra_data[222]
    DIRECTION OUTPUT ;
    USE SIGNAL ;
    PORT
      LAYER M4 ;
      RECT 0.00000 10.70400 0.03600 10.72800 ;
    END
  END ra_data[222]
  PIN ra_data[223]
    DIRECTION OUTPUT ;
    USE SIGNAL ;
    PORT
      LAYER M4 ;
      RECT 0.00000 10.75200 0.03600 10.77600 ;
    END
  END ra_data[223]
  PIN ra_data[224]
    DIRECTION OUTPUT ;
    USE SIGNAL ;
    PORT
      LAYER M4 ;
      RECT 0.00000 10.80000 0.03600 10.82400 ;
    END
  END ra_data[224]
  PIN ra_data[225]
    DIRECTION OUTPUT ;
    USE SIGNAL ;
    PORT
      LAYER M4 ;
      RECT 0.00000 10.84800 0.03600 10.87200 ;
    END
  END ra_data[225]
  PIN ra_data[226]
    DIRECTION OUTPUT ;
    USE SIGNAL ;
    PORT
      LAYER M4 ;
      RECT 0.00000 10.89600 0.03600 10.92000 ;
    END
  END ra_data[226]
  PIN ra_data[227]
    DIRECTION OUTPUT ;
    USE SIGNAL ;
    PORT
      LAYER M4 ;
      RECT 0.00000 10.94400 0.03600 10.96800 ;
    END
  END ra_data[227]
  PIN ra_data[228]
    DIRECTION OUTPUT ;
    USE SIGNAL ;
    PORT
      LAYER M4 ;
      RECT 0.00000 10.99200 0.03600 11.01600 ;
    END
  END ra_data[228]
  PIN ra_data[229]
    DIRECTION OUTPUT ;
    USE SIGNAL ;
    PORT
      LAYER M4 ;
      RECT 0.00000 11.04000 0.03600 11.06400 ;
    END
  END ra_data[229]
  PIN ra_data[230]
    DIRECTION OUTPUT ;
    USE SIGNAL ;
    PORT
      LAYER M4 ;
      RECT 0.00000 11.08800 0.03600 11.11200 ;
    END
  END ra_data[230]
  PIN ra_data[231]
    DIRECTION OUTPUT ;
    USE SIGNAL ;
    PORT
      LAYER M4 ;
      RECT 0.00000 11.13600 0.03600 11.16000 ;
    END
  END ra_data[231]
  PIN ra_data[232]
    DIRECTION OUTPUT ;
    USE SIGNAL ;
    PORT
      LAYER M4 ;
      RECT 0.00000 11.18400 0.03600 11.20800 ;
    END
  END ra_data[232]
  PIN ra_data[233]
    DIRECTION OUTPUT ;
    USE SIGNAL ;
    PORT
      LAYER M4 ;
      RECT 0.00000 11.23200 0.03600 11.25600 ;
    END
  END ra_data[233]
  PIN ra_data[234]
    DIRECTION OUTPUT ;
    USE SIGNAL ;
    PORT
      LAYER M4 ;
      RECT 0.00000 11.28000 0.03600 11.30400 ;
    END
  END ra_data[234]
  PIN ra_data[235]
    DIRECTION OUTPUT ;
    USE SIGNAL ;
    PORT
      LAYER M4 ;
      RECT 0.00000 11.32800 0.03600 11.35200 ;
    END
  END ra_data[235]
  PIN ra_data[236]
    DIRECTION OUTPUT ;
    USE SIGNAL ;
    PORT
      LAYER M4 ;
      RECT 0.00000 11.37600 0.03600 11.40000 ;
    END
  END ra_data[236]
  PIN ra_data[237]
    DIRECTION OUTPUT ;
    USE SIGNAL ;
    PORT
      LAYER M4 ;
      RECT 0.00000 11.42400 0.03600 11.44800 ;
    END
  END ra_data[237]
  PIN ra_data[238]
    DIRECTION OUTPUT ;
    USE SIGNAL ;
    PORT
      LAYER M4 ;
      RECT 0.00000 11.47200 0.03600 11.49600 ;
    END
  END ra_data[238]
  PIN ra_data[239]
    DIRECTION OUTPUT ;
    USE SIGNAL ;
    PORT
      LAYER M4 ;
      RECT 0.00000 11.52000 0.03600 11.54400 ;
    END
  END ra_data[239]
  PIN ra_data[240]
    DIRECTION OUTPUT ;
    USE SIGNAL ;
    PORT
      LAYER M4 ;
      RECT 0.00000 11.56800 0.03600 11.59200 ;
    END
  END ra_data[240]
  PIN ra_data[241]
    DIRECTION OUTPUT ;
    USE SIGNAL ;
    PORT
      LAYER M4 ;
      RECT 0.00000 11.61600 0.03600 11.64000 ;
    END
  END ra_data[241]
  PIN ra_data[242]
    DIRECTION OUTPUT ;
    USE SIGNAL ;
    PORT
      LAYER M4 ;
      RECT 0.00000 11.66400 0.03600 11.68800 ;
    END
  END ra_data[242]
  PIN ra_data[243]
    DIRECTION OUTPUT ;
    USE SIGNAL ;
    PORT
      LAYER M4 ;
      RECT 0.00000 11.71200 0.03600 11.73600 ;
    END
  END ra_data[243]
  PIN ra_data[244]
    DIRECTION OUTPUT ;
    USE SIGNAL ;
    PORT
      LAYER M4 ;
      RECT 0.00000 11.76000 0.03600 11.78400 ;
    END
  END ra_data[244]
  PIN ra_data[245]
    DIRECTION OUTPUT ;
    USE SIGNAL ;
    PORT
      LAYER M4 ;
      RECT 0.00000 11.80800 0.03600 11.83200 ;
    END
  END ra_data[245]
  PIN ra_data[246]
    DIRECTION OUTPUT ;
    USE SIGNAL ;
    PORT
      LAYER M4 ;
      RECT 0.00000 11.85600 0.03600 11.88000 ;
    END
  END ra_data[246]
  PIN ra_data[247]
    DIRECTION OUTPUT ;
    USE SIGNAL ;
    PORT
      LAYER M4 ;
      RECT 0.00000 11.90400 0.03600 11.92800 ;
    END
  END ra_data[247]
  PIN ra_data[248]
    DIRECTION OUTPUT ;
    USE SIGNAL ;
    PORT
      LAYER M4 ;
      RECT 0.00000 11.95200 0.03600 11.97600 ;
    END
  END ra_data[248]
  PIN ra_data[249]
    DIRECTION OUTPUT ;
    USE SIGNAL ;
    PORT
      LAYER M4 ;
      RECT 0.00000 12.00000 0.03600 12.02400 ;
    END
  END ra_data[249]
  PIN ra_data[250]
    DIRECTION OUTPUT ;
    USE SIGNAL ;
    PORT
      LAYER M4 ;
      RECT 0.00000 12.04800 0.03600 12.07200 ;
    END
  END ra_data[250]
  PIN ra_data[251]
    DIRECTION OUTPUT ;
    USE SIGNAL ;
    PORT
      LAYER M4 ;
      RECT 0.00000 12.09600 0.03600 12.12000 ;
    END
  END ra_data[251]
  PIN ra_data[252]
    DIRECTION OUTPUT ;
    USE SIGNAL ;
    PORT
      LAYER M4 ;
      RECT 0.00000 12.14400 0.03600 12.16800 ;
    END
  END ra_data[252]
  PIN ra_data[253]
    DIRECTION OUTPUT ;
    USE SIGNAL ;
    PORT
      LAYER M4 ;
      RECT 0.00000 12.19200 0.03600 12.21600 ;
    END
  END ra_data[253]
  PIN ra_data[254]
    DIRECTION OUTPUT ;
    USE SIGNAL ;
    PORT
      LAYER M4 ;
      RECT 0.00000 12.24000 0.03600 12.26400 ;
    END
  END ra_data[254]
  PIN ra_data[255]
    DIRECTION OUTPUT ;
    USE SIGNAL ;
    PORT
      LAYER M4 ;
      RECT 0.00000 12.28800 0.03600 12.31200 ;
    END
  END ra_data[255]
  PIN ra_data[256]
    DIRECTION OUTPUT ;
    USE SIGNAL ;
    PORT
      LAYER M4 ;
      RECT 0.00000 12.33600 0.03600 12.36000 ;
    END
  END ra_data[256]
  PIN ra_data[257]
    DIRECTION OUTPUT ;
    USE SIGNAL ;
    PORT
      LAYER M4 ;
      RECT 0.00000 12.38400 0.03600 12.40800 ;
    END
  END ra_data[257]
  PIN ra_data[258]
    DIRECTION OUTPUT ;
    USE SIGNAL ;
    PORT
      LAYER M4 ;
      RECT 0.00000 12.43200 0.03600 12.45600 ;
    END
  END ra_data[258]
  PIN ra_data[259]
    DIRECTION OUTPUT ;
    USE SIGNAL ;
    PORT
      LAYER M4 ;
      RECT 0.00000 12.48000 0.03600 12.50400 ;
    END
  END ra_data[259]
  PIN ra_data[260]
    DIRECTION OUTPUT ;
    USE SIGNAL ;
    PORT
      LAYER M4 ;
      RECT 0.00000 12.52800 0.03600 12.55200 ;
    END
  END ra_data[260]
  PIN ra_data[261]
    DIRECTION OUTPUT ;
    USE SIGNAL ;
    PORT
      LAYER M4 ;
      RECT 0.00000 12.57600 0.03600 12.60000 ;
    END
  END ra_data[261]
  PIN ra_data[262]
    DIRECTION OUTPUT ;
    USE SIGNAL ;
    PORT
      LAYER M4 ;
      RECT 0.00000 12.62400 0.03600 12.64800 ;
    END
  END ra_data[262]
  PIN ra_data[263]
    DIRECTION OUTPUT ;
    USE SIGNAL ;
    PORT
      LAYER M4 ;
      RECT 0.00000 12.67200 0.03600 12.69600 ;
    END
  END ra_data[263]
  PIN ra_data[264]
    DIRECTION OUTPUT ;
    USE SIGNAL ;
    PORT
      LAYER M4 ;
      RECT 0.00000 12.72000 0.03600 12.74400 ;
    END
  END ra_data[264]
  PIN ra_data[265]
    DIRECTION OUTPUT ;
    USE SIGNAL ;
    PORT
      LAYER M4 ;
      RECT 0.00000 12.76800 0.03600 12.79200 ;
    END
  END ra_data[265]
  PIN ra_data[266]
    DIRECTION OUTPUT ;
    USE SIGNAL ;
    PORT
      LAYER M4 ;
      RECT 0.00000 12.81600 0.03600 12.84000 ;
    END
  END ra_data[266]
  PIN ra_data[267]
    DIRECTION OUTPUT ;
    USE SIGNAL ;
    PORT
      LAYER M4 ;
      RECT 0.00000 12.86400 0.03600 12.88800 ;
    END
  END ra_data[267]
  PIN ra_data[268]
    DIRECTION OUTPUT ;
    USE SIGNAL ;
    PORT
      LAYER M4 ;
      RECT 0.00000 12.91200 0.03600 12.93600 ;
    END
  END ra_data[268]
  PIN ra_data[269]
    DIRECTION OUTPUT ;
    USE SIGNAL ;
    PORT
      LAYER M4 ;
      RECT 0.00000 12.96000 0.03600 12.98400 ;
    END
  END ra_data[269]
  PIN ra_data[270]
    DIRECTION OUTPUT ;
    USE SIGNAL ;
    PORT
      LAYER M4 ;
      RECT 0.00000 13.00800 0.03600 13.03200 ;
    END
  END ra_data[270]
  PIN ra_data[271]
    DIRECTION OUTPUT ;
    USE SIGNAL ;
    PORT
      LAYER M4 ;
      RECT 0.00000 13.05600 0.03600 13.08000 ;
    END
  END ra_data[271]
  PIN ra_data[272]
    DIRECTION OUTPUT ;
    USE SIGNAL ;
    PORT
      LAYER M4 ;
      RECT 0.00000 13.10400 0.03600 13.12800 ;
    END
  END ra_data[272]
  PIN ra_data[273]
    DIRECTION OUTPUT ;
    USE SIGNAL ;
    PORT
      LAYER M4 ;
      RECT 0.00000 13.15200 0.03600 13.17600 ;
    END
  END ra_data[273]
  PIN ra_data[274]
    DIRECTION OUTPUT ;
    USE SIGNAL ;
    PORT
      LAYER M4 ;
      RECT 0.00000 13.20000 0.03600 13.22400 ;
    END
  END ra_data[274]
  PIN ra_data[275]
    DIRECTION OUTPUT ;
    USE SIGNAL ;
    PORT
      LAYER M4 ;
      RECT 0.00000 13.24800 0.03600 13.27200 ;
    END
  END ra_data[275]
  PIN ra_data[276]
    DIRECTION OUTPUT ;
    USE SIGNAL ;
    PORT
      LAYER M4 ;
      RECT 0.00000 13.29600 0.03600 13.32000 ;
    END
  END ra_data[276]
  PIN ra_data[277]
    DIRECTION OUTPUT ;
    USE SIGNAL ;
    PORT
      LAYER M4 ;
      RECT 0.00000 13.34400 0.03600 13.36800 ;
    END
  END ra_data[277]
  PIN ra_data[278]
    DIRECTION OUTPUT ;
    USE SIGNAL ;
    PORT
      LAYER M4 ;
      RECT 0.00000 13.39200 0.03600 13.41600 ;
    END
  END ra_data[278]
  PIN ra_data[279]
    DIRECTION OUTPUT ;
    USE SIGNAL ;
    PORT
      LAYER M4 ;
      RECT 0.00000 13.44000 0.03600 13.46400 ;
    END
  END ra_data[279]
  PIN ra_data[280]
    DIRECTION OUTPUT ;
    USE SIGNAL ;
    PORT
      LAYER M4 ;
      RECT 0.00000 13.48800 0.03600 13.51200 ;
    END
  END ra_data[280]
  PIN ra_data[281]
    DIRECTION OUTPUT ;
    USE SIGNAL ;
    PORT
      LAYER M4 ;
      RECT 0.00000 13.53600 0.03600 13.56000 ;
    END
  END ra_data[281]
  PIN ra_data[282]
    DIRECTION OUTPUT ;
    USE SIGNAL ;
    PORT
      LAYER M4 ;
      RECT 0.00000 13.58400 0.03600 13.60800 ;
    END
  END ra_data[282]
  PIN ra_data[283]
    DIRECTION OUTPUT ;
    USE SIGNAL ;
    PORT
      LAYER M4 ;
      RECT 0.00000 13.63200 0.03600 13.65600 ;
    END
  END ra_data[283]
  PIN ra_data[284]
    DIRECTION OUTPUT ;
    USE SIGNAL ;
    PORT
      LAYER M4 ;
      RECT 0.00000 13.68000 0.03600 13.70400 ;
    END
  END ra_data[284]
  PIN ra_data[285]
    DIRECTION OUTPUT ;
    USE SIGNAL ;
    PORT
      LAYER M4 ;
      RECT 0.00000 13.72800 0.03600 13.75200 ;
    END
  END ra_data[285]
  PIN ra_data[286]
    DIRECTION OUTPUT ;
    USE SIGNAL ;
    PORT
      LAYER M4 ;
      RECT 0.00000 13.77600 0.03600 13.80000 ;
    END
  END ra_data[286]
  PIN ra_data[287]
    DIRECTION OUTPUT ;
    USE SIGNAL ;
    PORT
      LAYER M4 ;
      RECT 0.00000 13.82400 0.03600 13.84800 ;
    END
  END ra_data[287]
  PIN ra_data[288]
    DIRECTION OUTPUT ;
    USE SIGNAL ;
    PORT
      LAYER M4 ;
      RECT 0.00000 13.87200 0.03600 13.89600 ;
    END
  END ra_data[288]
  PIN ra_data[289]
    DIRECTION OUTPUT ;
    USE SIGNAL ;
    PORT
      LAYER M4 ;
      RECT 0.00000 13.92000 0.03600 13.94400 ;
    END
  END ra_data[289]
  PIN ra_data[290]
    DIRECTION OUTPUT ;
    USE SIGNAL ;
    PORT
      LAYER M4 ;
      RECT 0.00000 13.96800 0.03600 13.99200 ;
    END
  END ra_data[290]
  PIN ra_data[291]
    DIRECTION OUTPUT ;
    USE SIGNAL ;
    PORT
      LAYER M4 ;
      RECT 0.00000 14.01600 0.03600 14.04000 ;
    END
  END ra_data[291]
  PIN ra_data[292]
    DIRECTION OUTPUT ;
    USE SIGNAL ;
    PORT
      LAYER M4 ;
      RECT 0.00000 14.06400 0.03600 14.08800 ;
    END
  END ra_data[292]
  PIN ra_data[293]
    DIRECTION OUTPUT ;
    USE SIGNAL ;
    PORT
      LAYER M4 ;
      RECT 0.00000 14.11200 0.03600 14.13600 ;
    END
  END ra_data[293]
  PIN ra_data[294]
    DIRECTION OUTPUT ;
    USE SIGNAL ;
    PORT
      LAYER M4 ;
      RECT 0.00000 14.16000 0.03600 14.18400 ;
    END
  END ra_data[294]
  PIN ra_data[295]
    DIRECTION OUTPUT ;
    USE SIGNAL ;
    PORT
      LAYER M4 ;
      RECT 0.00000 14.20800 0.03600 14.23200 ;
    END
  END ra_data[295]
  PIN ra_data[296]
    DIRECTION OUTPUT ;
    USE SIGNAL ;
    PORT
      LAYER M4 ;
      RECT 0.00000 14.25600 0.03600 14.28000 ;
    END
  END ra_data[296]
  PIN ra_data[297]
    DIRECTION OUTPUT ;
    USE SIGNAL ;
    PORT
      LAYER M4 ;
      RECT 0.00000 14.30400 0.03600 14.32800 ;
    END
  END ra_data[297]
  PIN ra_data[298]
    DIRECTION OUTPUT ;
    USE SIGNAL ;
    PORT
      LAYER M4 ;
      RECT 0.00000 14.35200 0.03600 14.37600 ;
    END
  END ra_data[298]
  PIN ra_data[299]
    DIRECTION OUTPUT ;
    USE SIGNAL ;
    PORT
      LAYER M4 ;
      RECT 0.00000 14.40000 0.03600 14.42400 ;
    END
  END ra_data[299]
  PIN ra_data[300]
    DIRECTION OUTPUT ;
    USE SIGNAL ;
    PORT
      LAYER M4 ;
      RECT 0.00000 14.44800 0.03600 14.47200 ;
    END
  END ra_data[300]
  PIN ra_data[301]
    DIRECTION OUTPUT ;
    USE SIGNAL ;
    PORT
      LAYER M4 ;
      RECT 0.00000 14.49600 0.03600 14.52000 ;
    END
  END ra_data[301]
  PIN ra_data[302]
    DIRECTION OUTPUT ;
    USE SIGNAL ;
    PORT
      LAYER M4 ;
      RECT 0.00000 14.54400 0.03600 14.56800 ;
    END
  END ra_data[302]
  PIN ra_data[303]
    DIRECTION OUTPUT ;
    USE SIGNAL ;
    PORT
      LAYER M4 ;
      RECT 0.00000 14.59200 0.03600 14.61600 ;
    END
  END ra_data[303]
  PIN ra_data[304]
    DIRECTION OUTPUT ;
    USE SIGNAL ;
    PORT
      LAYER M4 ;
      RECT 0.00000 14.64000 0.03600 14.66400 ;
    END
  END ra_data[304]
  PIN ra_data[305]
    DIRECTION OUTPUT ;
    USE SIGNAL ;
    PORT
      LAYER M4 ;
      RECT 0.00000 14.68800 0.03600 14.71200 ;
    END
  END ra_data[305]
  PIN ra_data[306]
    DIRECTION OUTPUT ;
    USE SIGNAL ;
    PORT
      LAYER M4 ;
      RECT 0.00000 14.73600 0.03600 14.76000 ;
    END
  END ra_data[306]
  PIN ra_data[307]
    DIRECTION OUTPUT ;
    USE SIGNAL ;
    PORT
      LAYER M4 ;
      RECT 0.00000 14.78400 0.03600 14.80800 ;
    END
  END ra_data[307]
  PIN ra_data[308]
    DIRECTION OUTPUT ;
    USE SIGNAL ;
    PORT
      LAYER M4 ;
      RECT 0.00000 14.83200 0.03600 14.85600 ;
    END
  END ra_data[308]
  PIN ra_data[309]
    DIRECTION OUTPUT ;
    USE SIGNAL ;
    PORT
      LAYER M4 ;
      RECT 0.00000 14.88000 0.03600 14.90400 ;
    END
  END ra_data[309]
  PIN ra_data[310]
    DIRECTION OUTPUT ;
    USE SIGNAL ;
    PORT
      LAYER M4 ;
      RECT 0.00000 14.92800 0.03600 14.95200 ;
    END
  END ra_data[310]
  PIN ra_data[311]
    DIRECTION OUTPUT ;
    USE SIGNAL ;
    PORT
      LAYER M4 ;
      RECT 0.00000 14.97600 0.03600 15.00000 ;
    END
  END ra_data[311]
  PIN ra_data[312]
    DIRECTION OUTPUT ;
    USE SIGNAL ;
    PORT
      LAYER M4 ;
      RECT 0.00000 15.02400 0.03600 15.04800 ;
    END
  END ra_data[312]
  PIN ra_data[313]
    DIRECTION OUTPUT ;
    USE SIGNAL ;
    PORT
      LAYER M4 ;
      RECT 0.00000 15.07200 0.03600 15.09600 ;
    END
  END ra_data[313]
  PIN ra_data[314]
    DIRECTION OUTPUT ;
    USE SIGNAL ;
    PORT
      LAYER M4 ;
      RECT 0.00000 15.12000 0.03600 15.14400 ;
    END
  END ra_data[314]
  PIN ra_data[315]
    DIRECTION OUTPUT ;
    USE SIGNAL ;
    PORT
      LAYER M4 ;
      RECT 0.00000 15.16800 0.03600 15.19200 ;
    END
  END ra_data[315]
  PIN ra_data[316]
    DIRECTION OUTPUT ;
    USE SIGNAL ;
    PORT
      LAYER M4 ;
      RECT 0.00000 15.21600 0.03600 15.24000 ;
    END
  END ra_data[316]
  PIN ra_data[317]
    DIRECTION OUTPUT ;
    USE SIGNAL ;
    PORT
      LAYER M4 ;
      RECT 0.00000 15.26400 0.03600 15.28800 ;
    END
  END ra_data[317]
  PIN ra_data[318]
    DIRECTION OUTPUT ;
    USE SIGNAL ;
    PORT
      LAYER M4 ;
      RECT 0.00000 15.31200 0.03600 15.33600 ;
    END
  END ra_data[318]
  PIN ra_data[319]
    DIRECTION OUTPUT ;
    USE SIGNAL ;
    PORT
      LAYER M4 ;
      RECT 0.00000 15.36000 0.03600 15.38400 ;
    END
  END ra_data[319]
  PIN ra_data[320]
    DIRECTION OUTPUT ;
    USE SIGNAL ;
    PORT
      LAYER M4 ;
      RECT 0.00000 15.40800 0.03600 15.43200 ;
    END
  END ra_data[320]
  PIN ra_data[321]
    DIRECTION OUTPUT ;
    USE SIGNAL ;
    PORT
      LAYER M4 ;
      RECT 0.00000 15.45600 0.03600 15.48000 ;
    END
  END ra_data[321]
  PIN ra_data[322]
    DIRECTION OUTPUT ;
    USE SIGNAL ;
    PORT
      LAYER M4 ;
      RECT 0.00000 15.50400 0.03600 15.52800 ;
    END
  END ra_data[322]
  PIN ra_data[323]
    DIRECTION OUTPUT ;
    USE SIGNAL ;
    PORT
      LAYER M4 ;
      RECT 0.00000 15.55200 0.03600 15.57600 ;
    END
  END ra_data[323]
  PIN ra_data[324]
    DIRECTION OUTPUT ;
    USE SIGNAL ;
    PORT
      LAYER M4 ;
      RECT 0.00000 15.60000 0.03600 15.62400 ;
    END
  END ra_data[324]
  PIN ra_data[325]
    DIRECTION OUTPUT ;
    USE SIGNAL ;
    PORT
      LAYER M4 ;
      RECT 0.00000 15.64800 0.03600 15.67200 ;
    END
  END ra_data[325]
  PIN ra_data[326]
    DIRECTION OUTPUT ;
    USE SIGNAL ;
    PORT
      LAYER M4 ;
      RECT 0.00000 15.69600 0.03600 15.72000 ;
    END
  END ra_data[326]
  PIN ra_data[327]
    DIRECTION OUTPUT ;
    USE SIGNAL ;
    PORT
      LAYER M4 ;
      RECT 0.00000 15.74400 0.03600 15.76800 ;
    END
  END ra_data[327]
  PIN ra_data[328]
    DIRECTION OUTPUT ;
    USE SIGNAL ;
    PORT
      LAYER M4 ;
      RECT 0.00000 15.79200 0.03600 15.81600 ;
    END
  END ra_data[328]
  PIN ra_data[329]
    DIRECTION OUTPUT ;
    USE SIGNAL ;
    PORT
      LAYER M4 ;
      RECT 0.00000 15.84000 0.03600 15.86400 ;
    END
  END ra_data[329]
  PIN ra_data[330]
    DIRECTION OUTPUT ;
    USE SIGNAL ;
    PORT
      LAYER M4 ;
      RECT 0.00000 15.88800 0.03600 15.91200 ;
    END
  END ra_data[330]
  PIN ra_data[331]
    DIRECTION OUTPUT ;
    USE SIGNAL ;
    PORT
      LAYER M4 ;
      RECT 0.00000 15.93600 0.03600 15.96000 ;
    END
  END ra_data[331]
  PIN ra_data[332]
    DIRECTION OUTPUT ;
    USE SIGNAL ;
    PORT
      LAYER M4 ;
      RECT 0.00000 15.98400 0.03600 16.00800 ;
    END
  END ra_data[332]
  PIN ra_data[333]
    DIRECTION OUTPUT ;
    USE SIGNAL ;
    PORT
      LAYER M4 ;
      RECT 0.00000 16.03200 0.03600 16.05600 ;
    END
  END ra_data[333]
  PIN ra_data[334]
    DIRECTION OUTPUT ;
    USE SIGNAL ;
    PORT
      LAYER M4 ;
      RECT 0.00000 16.08000 0.03600 16.10400 ;
    END
  END ra_data[334]
  PIN ra_data[335]
    DIRECTION OUTPUT ;
    USE SIGNAL ;
    PORT
      LAYER M4 ;
      RECT 0.00000 16.12800 0.03600 16.15200 ;
    END
  END ra_data[335]
  PIN ra_data[336]
    DIRECTION OUTPUT ;
    USE SIGNAL ;
    PORT
      LAYER M4 ;
      RECT 0.00000 16.17600 0.03600 16.20000 ;
    END
  END ra_data[336]
  PIN ra_data[337]
    DIRECTION OUTPUT ;
    USE SIGNAL ;
    PORT
      LAYER M4 ;
      RECT 0.00000 16.22400 0.03600 16.24800 ;
    END
  END ra_data[337]
  PIN ra_data[338]
    DIRECTION OUTPUT ;
    USE SIGNAL ;
    PORT
      LAYER M4 ;
      RECT 0.00000 16.27200 0.03600 16.29600 ;
    END
  END ra_data[338]
  PIN ra_data[339]
    DIRECTION OUTPUT ;
    USE SIGNAL ;
    PORT
      LAYER M4 ;
      RECT 0.00000 16.32000 0.03600 16.34400 ;
    END
  END ra_data[339]
  PIN ra_data[340]
    DIRECTION OUTPUT ;
    USE SIGNAL ;
    PORT
      LAYER M4 ;
      RECT 0.00000 16.36800 0.03600 16.39200 ;
    END
  END ra_data[340]
  PIN ra_data[341]
    DIRECTION OUTPUT ;
    USE SIGNAL ;
    PORT
      LAYER M4 ;
      RECT 0.00000 16.41600 0.03600 16.44000 ;
    END
  END ra_data[341]
  PIN ra_data[342]
    DIRECTION OUTPUT ;
    USE SIGNAL ;
    PORT
      LAYER M4 ;
      RECT 0.00000 16.46400 0.03600 16.48800 ;
    END
  END ra_data[342]
  PIN ra_data[343]
    DIRECTION OUTPUT ;
    USE SIGNAL ;
    PORT
      LAYER M4 ;
      RECT 0.00000 16.51200 0.03600 16.53600 ;
    END
  END ra_data[343]
  PIN ra_data[344]
    DIRECTION OUTPUT ;
    USE SIGNAL ;
    PORT
      LAYER M4 ;
      RECT 0.00000 16.56000 0.03600 16.58400 ;
    END
  END ra_data[344]
  PIN ra_data[345]
    DIRECTION OUTPUT ;
    USE SIGNAL ;
    PORT
      LAYER M4 ;
      RECT 0.00000 16.60800 0.03600 16.63200 ;
    END
  END ra_data[345]
  PIN ra_data[346]
    DIRECTION OUTPUT ;
    USE SIGNAL ;
    PORT
      LAYER M4 ;
      RECT 0.00000 16.65600 0.03600 16.68000 ;
    END
  END ra_data[346]
  PIN ra_data[347]
    DIRECTION OUTPUT ;
    USE SIGNAL ;
    PORT
      LAYER M4 ;
      RECT 0.00000 16.70400 0.03600 16.72800 ;
    END
  END ra_data[347]
  PIN ra_data[348]
    DIRECTION OUTPUT ;
    USE SIGNAL ;
    PORT
      LAYER M4 ;
      RECT 0.00000 16.75200 0.03600 16.77600 ;
    END
  END ra_data[348]
  PIN ra_data[349]
    DIRECTION OUTPUT ;
    USE SIGNAL ;
    PORT
      LAYER M4 ;
      RECT 0.00000 16.80000 0.03600 16.82400 ;
    END
  END ra_data[349]
  PIN ra_data[350]
    DIRECTION OUTPUT ;
    USE SIGNAL ;
    PORT
      LAYER M4 ;
      RECT 0.00000 16.84800 0.03600 16.87200 ;
    END
  END ra_data[350]
  PIN ra_data[351]
    DIRECTION OUTPUT ;
    USE SIGNAL ;
    PORT
      LAYER M4 ;
      RECT 0.00000 16.89600 0.03600 16.92000 ;
    END
  END ra_data[351]
  PIN ra_data[352]
    DIRECTION OUTPUT ;
    USE SIGNAL ;
    PORT
      LAYER M4 ;
      RECT 0.00000 16.94400 0.03600 16.96800 ;
    END
  END ra_data[352]
  PIN ra_data[353]
    DIRECTION OUTPUT ;
    USE SIGNAL ;
    PORT
      LAYER M4 ;
      RECT 0.00000 16.99200 0.03600 17.01600 ;
    END
  END ra_data[353]
  PIN ra_data[354]
    DIRECTION OUTPUT ;
    USE SIGNAL ;
    PORT
      LAYER M4 ;
      RECT 0.00000 17.04000 0.03600 17.06400 ;
    END
  END ra_data[354]
  PIN ra_data[355]
    DIRECTION OUTPUT ;
    USE SIGNAL ;
    PORT
      LAYER M4 ;
      RECT 0.00000 17.08800 0.03600 17.11200 ;
    END
  END ra_data[355]
  PIN ra_data[356]
    DIRECTION OUTPUT ;
    USE SIGNAL ;
    PORT
      LAYER M4 ;
      RECT 0.00000 17.13600 0.03600 17.16000 ;
    END
  END ra_data[356]
  PIN ra_data[357]
    DIRECTION OUTPUT ;
    USE SIGNAL ;
    PORT
      LAYER M4 ;
      RECT 0.00000 17.18400 0.03600 17.20800 ;
    END
  END ra_data[357]
  PIN ra_data[358]
    DIRECTION OUTPUT ;
    USE SIGNAL ;
    PORT
      LAYER M4 ;
      RECT 0.00000 17.23200 0.03600 17.25600 ;
    END
  END ra_data[358]
  PIN ra_data[359]
    DIRECTION OUTPUT ;
    USE SIGNAL ;
    PORT
      LAYER M4 ;
      RECT 0.00000 17.28000 0.03600 17.30400 ;
    END
  END ra_data[359]
  PIN ra_data[360]
    DIRECTION OUTPUT ;
    USE SIGNAL ;
    PORT
      LAYER M4 ;
      RECT 0.00000 17.32800 0.03600 17.35200 ;
    END
  END ra_data[360]
  PIN ra_data[361]
    DIRECTION OUTPUT ;
    USE SIGNAL ;
    PORT
      LAYER M4 ;
      RECT 0.00000 17.37600 0.03600 17.40000 ;
    END
  END ra_data[361]
  PIN ra_data[362]
    DIRECTION OUTPUT ;
    USE SIGNAL ;
    PORT
      LAYER M4 ;
      RECT 0.00000 17.42400 0.03600 17.44800 ;
    END
  END ra_data[362]
  PIN ra_data[363]
    DIRECTION OUTPUT ;
    USE SIGNAL ;
    PORT
      LAYER M4 ;
      RECT 0.00000 17.47200 0.03600 17.49600 ;
    END
  END ra_data[363]
  PIN ra_data[364]
    DIRECTION OUTPUT ;
    USE SIGNAL ;
    PORT
      LAYER M4 ;
      RECT 0.00000 17.52000 0.03600 17.54400 ;
    END
  END ra_data[364]
  PIN ra_data[365]
    DIRECTION OUTPUT ;
    USE SIGNAL ;
    PORT
      LAYER M4 ;
      RECT 0.00000 17.56800 0.03600 17.59200 ;
    END
  END ra_data[365]
  PIN ra_data[366]
    DIRECTION OUTPUT ;
    USE SIGNAL ;
    PORT
      LAYER M4 ;
      RECT 0.00000 17.61600 0.03600 17.64000 ;
    END
  END ra_data[366]
  PIN ra_data[367]
    DIRECTION OUTPUT ;
    USE SIGNAL ;
    PORT
      LAYER M4 ;
      RECT 0.00000 17.66400 0.03600 17.68800 ;
    END
  END ra_data[367]
  PIN ra_data[368]
    DIRECTION OUTPUT ;
    USE SIGNAL ;
    PORT
      LAYER M4 ;
      RECT 0.00000 17.71200 0.03600 17.73600 ;
    END
  END ra_data[368]
  PIN ra_data[369]
    DIRECTION OUTPUT ;
    USE SIGNAL ;
    PORT
      LAYER M4 ;
      RECT 0.00000 17.76000 0.03600 17.78400 ;
    END
  END ra_data[369]
  PIN ra_data[370]
    DIRECTION OUTPUT ;
    USE SIGNAL ;
    PORT
      LAYER M4 ;
      RECT 0.00000 17.80800 0.03600 17.83200 ;
    END
  END ra_data[370]
  PIN ra_data[371]
    DIRECTION OUTPUT ;
    USE SIGNAL ;
    PORT
      LAYER M4 ;
      RECT 0.00000 17.85600 0.03600 17.88000 ;
    END
  END ra_data[371]
  PIN ra_data[372]
    DIRECTION OUTPUT ;
    USE SIGNAL ;
    PORT
      LAYER M4 ;
      RECT 0.00000 17.90400 0.03600 17.92800 ;
    END
  END ra_data[372]
  PIN ra_data[373]
    DIRECTION OUTPUT ;
    USE SIGNAL ;
    PORT
      LAYER M4 ;
      RECT 0.00000 17.95200 0.03600 17.97600 ;
    END
  END ra_data[373]
  PIN ra_data[374]
    DIRECTION OUTPUT ;
    USE SIGNAL ;
    PORT
      LAYER M4 ;
      RECT 0.00000 18.00000 0.03600 18.02400 ;
    END
  END ra_data[374]
  PIN ra_data[375]
    DIRECTION OUTPUT ;
    USE SIGNAL ;
    PORT
      LAYER M4 ;
      RECT 0.00000 18.04800 0.03600 18.07200 ;
    END
  END ra_data[375]
  PIN ra_data[376]
    DIRECTION OUTPUT ;
    USE SIGNAL ;
    PORT
      LAYER M4 ;
      RECT 0.00000 18.09600 0.03600 18.12000 ;
    END
  END ra_data[376]
  PIN ra_data[377]
    DIRECTION OUTPUT ;
    USE SIGNAL ;
    PORT
      LAYER M4 ;
      RECT 0.00000 18.14400 0.03600 18.16800 ;
    END
  END ra_data[377]
  PIN ra_data[378]
    DIRECTION OUTPUT ;
    USE SIGNAL ;
    PORT
      LAYER M4 ;
      RECT 0.00000 18.19200 0.03600 18.21600 ;
    END
  END ra_data[378]
  PIN ra_data[379]
    DIRECTION OUTPUT ;
    USE SIGNAL ;
    PORT
      LAYER M4 ;
      RECT 0.00000 18.24000 0.03600 18.26400 ;
    END
  END ra_data[379]
  PIN ra_data[380]
    DIRECTION OUTPUT ;
    USE SIGNAL ;
    PORT
      LAYER M4 ;
      RECT 0.00000 18.28800 0.03600 18.31200 ;
    END
  END ra_data[380]
  PIN ra_data[381]
    DIRECTION OUTPUT ;
    USE SIGNAL ;
    PORT
      LAYER M4 ;
      RECT 0.00000 18.33600 0.03600 18.36000 ;
    END
  END ra_data[381]
  PIN ra_data[382]
    DIRECTION OUTPUT ;
    USE SIGNAL ;
    PORT
      LAYER M4 ;
      RECT 0.00000 18.38400 0.03600 18.40800 ;
    END
  END ra_data[382]
  PIN ra_data[383]
    DIRECTION OUTPUT ;
    USE SIGNAL ;
    PORT
      LAYER M4 ;
      RECT 0.00000 18.43200 0.03600 18.45600 ;
    END
  END ra_data[383]
  PIN ra_data[384]
    DIRECTION OUTPUT ;
    USE SIGNAL ;
    PORT
      LAYER M4 ;
      RECT 0.00000 18.48000 0.03600 18.50400 ;
    END
  END ra_data[384]
  PIN ra_data[385]
    DIRECTION OUTPUT ;
    USE SIGNAL ;
    PORT
      LAYER M4 ;
      RECT 0.00000 18.52800 0.03600 18.55200 ;
    END
  END ra_data[385]
  PIN ra_data[386]
    DIRECTION OUTPUT ;
    USE SIGNAL ;
    PORT
      LAYER M4 ;
      RECT 0.00000 18.57600 0.03600 18.60000 ;
    END
  END ra_data[386]
  PIN ra_data[387]
    DIRECTION OUTPUT ;
    USE SIGNAL ;
    PORT
      LAYER M4 ;
      RECT 0.00000 18.62400 0.03600 18.64800 ;
    END
  END ra_data[387]
  PIN ra_data[388]
    DIRECTION OUTPUT ;
    USE SIGNAL ;
    PORT
      LAYER M4 ;
      RECT 0.00000 18.67200 0.03600 18.69600 ;
    END
  END ra_data[388]
  PIN ra_data[389]
    DIRECTION OUTPUT ;
    USE SIGNAL ;
    PORT
      LAYER M4 ;
      RECT 0.00000 18.72000 0.03600 18.74400 ;
    END
  END ra_data[389]
  PIN ra_data[390]
    DIRECTION OUTPUT ;
    USE SIGNAL ;
    PORT
      LAYER M4 ;
      RECT 0.00000 18.76800 0.03600 18.79200 ;
    END
  END ra_data[390]
  PIN ra_data[391]
    DIRECTION OUTPUT ;
    USE SIGNAL ;
    PORT
      LAYER M4 ;
      RECT 0.00000 18.81600 0.03600 18.84000 ;
    END
  END ra_data[391]
  PIN ra_data[392]
    DIRECTION OUTPUT ;
    USE SIGNAL ;
    PORT
      LAYER M4 ;
      RECT 0.00000 18.86400 0.03600 18.88800 ;
    END
  END ra_data[392]
  PIN ra_data[393]
    DIRECTION OUTPUT ;
    USE SIGNAL ;
    PORT
      LAYER M4 ;
      RECT 0.00000 18.91200 0.03600 18.93600 ;
    END
  END ra_data[393]
  PIN ra_data[394]
    DIRECTION OUTPUT ;
    USE SIGNAL ;
    PORT
      LAYER M4 ;
      RECT 0.00000 18.96000 0.03600 18.98400 ;
    END
  END ra_data[394]
  PIN ra_data[395]
    DIRECTION OUTPUT ;
    USE SIGNAL ;
    PORT
      LAYER M4 ;
      RECT 0.00000 19.00800 0.03600 19.03200 ;
    END
  END ra_data[395]
  PIN ra_data[396]
    DIRECTION OUTPUT ;
    USE SIGNAL ;
    PORT
      LAYER M4 ;
      RECT 0.00000 19.05600 0.03600 19.08000 ;
    END
  END ra_data[396]
  PIN ra_data[397]
    DIRECTION OUTPUT ;
    USE SIGNAL ;
    PORT
      LAYER M4 ;
      RECT 0.00000 19.10400 0.03600 19.12800 ;
    END
  END ra_data[397]
  PIN ra_data[398]
    DIRECTION OUTPUT ;
    USE SIGNAL ;
    PORT
      LAYER M4 ;
      RECT 0.00000 19.15200 0.03600 19.17600 ;
    END
  END ra_data[398]
  PIN ra_data[399]
    DIRECTION OUTPUT ;
    USE SIGNAL ;
    PORT
      LAYER M4 ;
      RECT 0.00000 19.20000 0.03600 19.22400 ;
    END
  END ra_data[399]
  PIN ra_data[400]
    DIRECTION OUTPUT ;
    USE SIGNAL ;
    PORT
      LAYER M4 ;
      RECT 0.00000 19.24800 0.03600 19.27200 ;
    END
  END ra_data[400]
  PIN ra_data[401]
    DIRECTION OUTPUT ;
    USE SIGNAL ;
    PORT
      LAYER M4 ;
      RECT 0.00000 19.29600 0.03600 19.32000 ;
    END
  END ra_data[401]
  PIN ra_data[402]
    DIRECTION OUTPUT ;
    USE SIGNAL ;
    PORT
      LAYER M4 ;
      RECT 0.00000 19.34400 0.03600 19.36800 ;
    END
  END ra_data[402]
  PIN ra_data[403]
    DIRECTION OUTPUT ;
    USE SIGNAL ;
    PORT
      LAYER M4 ;
      RECT 0.00000 19.39200 0.03600 19.41600 ;
    END
  END ra_data[403]
  PIN ra_data[404]
    DIRECTION OUTPUT ;
    USE SIGNAL ;
    PORT
      LAYER M4 ;
      RECT 0.00000 19.44000 0.03600 19.46400 ;
    END
  END ra_data[404]
  PIN ra_data[405]
    DIRECTION OUTPUT ;
    USE SIGNAL ;
    PORT
      LAYER M4 ;
      RECT 0.00000 19.48800 0.03600 19.51200 ;
    END
  END ra_data[405]
  PIN ra_data[406]
    DIRECTION OUTPUT ;
    USE SIGNAL ;
    PORT
      LAYER M4 ;
      RECT 0.00000 19.53600 0.03600 19.56000 ;
    END
  END ra_data[406]
  PIN ra_data[407]
    DIRECTION OUTPUT ;
    USE SIGNAL ;
    PORT
      LAYER M4 ;
      RECT 0.00000 19.58400 0.03600 19.60800 ;
    END
  END ra_data[407]
  PIN ra_data[408]
    DIRECTION OUTPUT ;
    USE SIGNAL ;
    PORT
      LAYER M4 ;
      RECT 0.00000 19.63200 0.03600 19.65600 ;
    END
  END ra_data[408]
  PIN ra_data[409]
    DIRECTION OUTPUT ;
    USE SIGNAL ;
    PORT
      LAYER M4 ;
      RECT 0.00000 19.68000 0.03600 19.70400 ;
    END
  END ra_data[409]
  PIN ra_data[410]
    DIRECTION OUTPUT ;
    USE SIGNAL ;
    PORT
      LAYER M4 ;
      RECT 0.00000 19.72800 0.03600 19.75200 ;
    END
  END ra_data[410]
  PIN ra_data[411]
    DIRECTION OUTPUT ;
    USE SIGNAL ;
    PORT
      LAYER M4 ;
      RECT 0.00000 19.77600 0.03600 19.80000 ;
    END
  END ra_data[411]
  PIN ra_data[412]
    DIRECTION OUTPUT ;
    USE SIGNAL ;
    PORT
      LAYER M4 ;
      RECT 0.00000 19.82400 0.03600 19.84800 ;
    END
  END ra_data[412]
  PIN ra_data[413]
    DIRECTION OUTPUT ;
    USE SIGNAL ;
    PORT
      LAYER M4 ;
      RECT 0.00000 19.87200 0.03600 19.89600 ;
    END
  END ra_data[413]
  PIN ra_data[414]
    DIRECTION OUTPUT ;
    USE SIGNAL ;
    PORT
      LAYER M4 ;
      RECT 0.00000 19.92000 0.03600 19.94400 ;
    END
  END ra_data[414]
  PIN ra_data[415]
    DIRECTION OUTPUT ;
    USE SIGNAL ;
    PORT
      LAYER M4 ;
      RECT 0.00000 19.96800 0.03600 19.99200 ;
    END
  END ra_data[415]
  PIN ra_data[416]
    DIRECTION OUTPUT ;
    USE SIGNAL ;
    PORT
      LAYER M4 ;
      RECT 0.00000 20.01600 0.03600 20.04000 ;
    END
  END ra_data[416]
  PIN ra_data[417]
    DIRECTION OUTPUT ;
    USE SIGNAL ;
    PORT
      LAYER M4 ;
      RECT 0.00000 20.06400 0.03600 20.08800 ;
    END
  END ra_data[417]
  PIN ra_data[418]
    DIRECTION OUTPUT ;
    USE SIGNAL ;
    PORT
      LAYER M4 ;
      RECT 0.00000 20.11200 0.03600 20.13600 ;
    END
  END ra_data[418]
  PIN ra_data[419]
    DIRECTION OUTPUT ;
    USE SIGNAL ;
    PORT
      LAYER M4 ;
      RECT 0.00000 20.16000 0.03600 20.18400 ;
    END
  END ra_data[419]
  PIN ra_data[420]
    DIRECTION OUTPUT ;
    USE SIGNAL ;
    PORT
      LAYER M4 ;
      RECT 0.00000 20.20800 0.03600 20.23200 ;
    END
  END ra_data[420]
  PIN ra_data[421]
    DIRECTION OUTPUT ;
    USE SIGNAL ;
    PORT
      LAYER M4 ;
      RECT 0.00000 20.25600 0.03600 20.28000 ;
    END
  END ra_data[421]
  PIN ra_data[422]
    DIRECTION OUTPUT ;
    USE SIGNAL ;
    PORT
      LAYER M4 ;
      RECT 0.00000 20.30400 0.03600 20.32800 ;
    END
  END ra_data[422]
  PIN ra_data[423]
    DIRECTION OUTPUT ;
    USE SIGNAL ;
    PORT
      LAYER M4 ;
      RECT 0.00000 20.35200 0.03600 20.37600 ;
    END
  END ra_data[423]
  PIN ra_data[424]
    DIRECTION OUTPUT ;
    USE SIGNAL ;
    PORT
      LAYER M4 ;
      RECT 0.00000 20.40000 0.03600 20.42400 ;
    END
  END ra_data[424]
  PIN ra_data[425]
    DIRECTION OUTPUT ;
    USE SIGNAL ;
    PORT
      LAYER M4 ;
      RECT 0.00000 20.44800 0.03600 20.47200 ;
    END
  END ra_data[425]
  PIN ra_data[426]
    DIRECTION OUTPUT ;
    USE SIGNAL ;
    PORT
      LAYER M4 ;
      RECT 0.00000 20.49600 0.03600 20.52000 ;
    END
  END ra_data[426]
  PIN ra_data[427]
    DIRECTION OUTPUT ;
    USE SIGNAL ;
    PORT
      LAYER M4 ;
      RECT 0.00000 20.54400 0.03600 20.56800 ;
    END
  END ra_data[427]
  PIN ra_data[428]
    DIRECTION OUTPUT ;
    USE SIGNAL ;
    PORT
      LAYER M4 ;
      RECT 0.00000 20.59200 0.03600 20.61600 ;
    END
  END ra_data[428]
  PIN ra_data[429]
    DIRECTION OUTPUT ;
    USE SIGNAL ;
    PORT
      LAYER M4 ;
      RECT 0.00000 20.64000 0.03600 20.66400 ;
    END
  END ra_data[429]
  PIN ra_data[430]
    DIRECTION OUTPUT ;
    USE SIGNAL ;
    PORT
      LAYER M4 ;
      RECT 0.00000 20.68800 0.03600 20.71200 ;
    END
  END ra_data[430]
  PIN ra_data[431]
    DIRECTION OUTPUT ;
    USE SIGNAL ;
    PORT
      LAYER M4 ;
      RECT 0.00000 20.73600 0.03600 20.76000 ;
    END
  END ra_data[431]
  PIN ra_data[432]
    DIRECTION OUTPUT ;
    USE SIGNAL ;
    PORT
      LAYER M4 ;
      RECT 0.00000 20.78400 0.03600 20.80800 ;
    END
  END ra_data[432]
  PIN ra_data[433]
    DIRECTION OUTPUT ;
    USE SIGNAL ;
    PORT
      LAYER M4 ;
      RECT 0.00000 20.83200 0.03600 20.85600 ;
    END
  END ra_data[433]
  PIN ra_data[434]
    DIRECTION OUTPUT ;
    USE SIGNAL ;
    PORT
      LAYER M4 ;
      RECT 0.00000 20.88000 0.03600 20.90400 ;
    END
  END ra_data[434]
  PIN ra_data[435]
    DIRECTION OUTPUT ;
    USE SIGNAL ;
    PORT
      LAYER M4 ;
      RECT 0.00000 20.92800 0.03600 20.95200 ;
    END
  END ra_data[435]
  PIN ra_data[436]
    DIRECTION OUTPUT ;
    USE SIGNAL ;
    PORT
      LAYER M4 ;
      RECT 0.00000 20.97600 0.03600 21.00000 ;
    END
  END ra_data[436]
  PIN ra_data[437]
    DIRECTION OUTPUT ;
    USE SIGNAL ;
    PORT
      LAYER M4 ;
      RECT 0.00000 21.02400 0.03600 21.04800 ;
    END
  END ra_data[437]
  PIN ra_data[438]
    DIRECTION OUTPUT ;
    USE SIGNAL ;
    PORT
      LAYER M4 ;
      RECT 0.00000 21.07200 0.03600 21.09600 ;
    END
  END ra_data[438]
  PIN ra_data[439]
    DIRECTION OUTPUT ;
    USE SIGNAL ;
    PORT
      LAYER M4 ;
      RECT 0.00000 21.12000 0.03600 21.14400 ;
    END
  END ra_data[439]
  PIN ra_data[440]
    DIRECTION OUTPUT ;
    USE SIGNAL ;
    PORT
      LAYER M4 ;
      RECT 0.00000 21.16800 0.03600 21.19200 ;
    END
  END ra_data[440]
  PIN ra_data[441]
    DIRECTION OUTPUT ;
    USE SIGNAL ;
    PORT
      LAYER M4 ;
      RECT 0.00000 21.21600 0.03600 21.24000 ;
    END
  END ra_data[441]
  PIN ra_data[442]
    DIRECTION OUTPUT ;
    USE SIGNAL ;
    PORT
      LAYER M4 ;
      RECT 0.00000 21.26400 0.03600 21.28800 ;
    END
  END ra_data[442]
  PIN ra_data[443]
    DIRECTION OUTPUT ;
    USE SIGNAL ;
    PORT
      LAYER M4 ;
      RECT 0.00000 21.31200 0.03600 21.33600 ;
    END
  END ra_data[443]
  PIN ra_data[444]
    DIRECTION OUTPUT ;
    USE SIGNAL ;
    PORT
      LAYER M4 ;
      RECT 0.00000 21.36000 0.03600 21.38400 ;
    END
  END ra_data[444]
  PIN ra_data[445]
    DIRECTION OUTPUT ;
    USE SIGNAL ;
    PORT
      LAYER M4 ;
      RECT 0.00000 21.40800 0.03600 21.43200 ;
    END
  END ra_data[445]
  PIN ra_data[446]
    DIRECTION OUTPUT ;
    USE SIGNAL ;
    PORT
      LAYER M4 ;
      RECT 0.00000 21.45600 0.03600 21.48000 ;
    END
  END ra_data[446]
  PIN ra_data[447]
    DIRECTION OUTPUT ;
    USE SIGNAL ;
    PORT
      LAYER M4 ;
      RECT 0.00000 21.50400 0.03600 21.52800 ;
    END
  END ra_data[447]
  PIN ra_data[448]
    DIRECTION OUTPUT ;
    USE SIGNAL ;
    PORT
      LAYER M4 ;
      RECT 0.00000 21.55200 0.03600 21.57600 ;
    END
  END ra_data[448]
  PIN ra_data[449]
    DIRECTION OUTPUT ;
    USE SIGNAL ;
    PORT
      LAYER M4 ;
      RECT 0.00000 21.60000 0.03600 21.62400 ;
    END
  END ra_data[449]
  PIN ra_data[450]
    DIRECTION OUTPUT ;
    USE SIGNAL ;
    PORT
      LAYER M4 ;
      RECT 0.00000 21.64800 0.03600 21.67200 ;
    END
  END ra_data[450]
  PIN ra_data[451]
    DIRECTION OUTPUT ;
    USE SIGNAL ;
    PORT
      LAYER M4 ;
      RECT 0.00000 21.69600 0.03600 21.72000 ;
    END
  END ra_data[451]
  PIN ra_data[452]
    DIRECTION OUTPUT ;
    USE SIGNAL ;
    PORT
      LAYER M4 ;
      RECT 0.00000 21.74400 0.03600 21.76800 ;
    END
  END ra_data[452]
  PIN ra_data[453]
    DIRECTION OUTPUT ;
    USE SIGNAL ;
    PORT
      LAYER M4 ;
      RECT 0.00000 21.79200 0.03600 21.81600 ;
    END
  END ra_data[453]
  PIN ra_data[454]
    DIRECTION OUTPUT ;
    USE SIGNAL ;
    PORT
      LAYER M4 ;
      RECT 0.00000 21.84000 0.03600 21.86400 ;
    END
  END ra_data[454]
  PIN ra_data[455]
    DIRECTION OUTPUT ;
    USE SIGNAL ;
    PORT
      LAYER M4 ;
      RECT 0.00000 21.88800 0.03600 21.91200 ;
    END
  END ra_data[455]
  PIN ra_data[456]
    DIRECTION OUTPUT ;
    USE SIGNAL ;
    PORT
      LAYER M4 ;
      RECT 0.00000 21.93600 0.03600 21.96000 ;
    END
  END ra_data[456]
  PIN ra_data[457]
    DIRECTION OUTPUT ;
    USE SIGNAL ;
    PORT
      LAYER M4 ;
      RECT 0.00000 21.98400 0.03600 22.00800 ;
    END
  END ra_data[457]
  PIN ra_data[458]
    DIRECTION OUTPUT ;
    USE SIGNAL ;
    PORT
      LAYER M4 ;
      RECT 0.00000 22.03200 0.03600 22.05600 ;
    END
  END ra_data[458]
  PIN ra_data[459]
    DIRECTION OUTPUT ;
    USE SIGNAL ;
    PORT
      LAYER M4 ;
      RECT 0.00000 22.08000 0.03600 22.10400 ;
    END
  END ra_data[459]
  PIN ra_data[460]
    DIRECTION OUTPUT ;
    USE SIGNAL ;
    PORT
      LAYER M4 ;
      RECT 0.00000 22.12800 0.03600 22.15200 ;
    END
  END ra_data[460]
  PIN ra_data[461]
    DIRECTION OUTPUT ;
    USE SIGNAL ;
    PORT
      LAYER M4 ;
      RECT 0.00000 22.17600 0.03600 22.20000 ;
    END
  END ra_data[461]
  PIN ra_data[462]
    DIRECTION OUTPUT ;
    USE SIGNAL ;
    PORT
      LAYER M4 ;
      RECT 0.00000 22.22400 0.03600 22.24800 ;
    END
  END ra_data[462]
  PIN ra_data[463]
    DIRECTION OUTPUT ;
    USE SIGNAL ;
    PORT
      LAYER M4 ;
      RECT 0.00000 22.27200 0.03600 22.29600 ;
    END
  END ra_data[463]
  PIN ra_data[464]
    DIRECTION OUTPUT ;
    USE SIGNAL ;
    PORT
      LAYER M4 ;
      RECT 0.00000 22.32000 0.03600 22.34400 ;
    END
  END ra_data[464]
  PIN ra_data[465]
    DIRECTION OUTPUT ;
    USE SIGNAL ;
    PORT
      LAYER M4 ;
      RECT 0.00000 22.36800 0.03600 22.39200 ;
    END
  END ra_data[465]
  PIN ra_data[466]
    DIRECTION OUTPUT ;
    USE SIGNAL ;
    PORT
      LAYER M4 ;
      RECT 0.00000 22.41600 0.03600 22.44000 ;
    END
  END ra_data[466]
  PIN ra_data[467]
    DIRECTION OUTPUT ;
    USE SIGNAL ;
    PORT
      LAYER M4 ;
      RECT 0.00000 22.46400 0.03600 22.48800 ;
    END
  END ra_data[467]
  PIN ra_data[468]
    DIRECTION OUTPUT ;
    USE SIGNAL ;
    PORT
      LAYER M4 ;
      RECT 0.00000 22.51200 0.03600 22.53600 ;
    END
  END ra_data[468]
  PIN ra_data[469]
    DIRECTION OUTPUT ;
    USE SIGNAL ;
    PORT
      LAYER M4 ;
      RECT 0.00000 22.56000 0.03600 22.58400 ;
    END
  END ra_data[469]
  PIN ra_data[470]
    DIRECTION OUTPUT ;
    USE SIGNAL ;
    PORT
      LAYER M4 ;
      RECT 0.00000 22.60800 0.03600 22.63200 ;
    END
  END ra_data[470]
  PIN ra_data[471]
    DIRECTION OUTPUT ;
    USE SIGNAL ;
    PORT
      LAYER M4 ;
      RECT 0.00000 22.65600 0.03600 22.68000 ;
    END
  END ra_data[471]
  PIN ra_data[472]
    DIRECTION OUTPUT ;
    USE SIGNAL ;
    PORT
      LAYER M4 ;
      RECT 0.00000 22.70400 0.03600 22.72800 ;
    END
  END ra_data[472]
  PIN ra_data[473]
    DIRECTION OUTPUT ;
    USE SIGNAL ;
    PORT
      LAYER M4 ;
      RECT 0.00000 22.75200 0.03600 22.77600 ;
    END
  END ra_data[473]
  PIN ra_data[474]
    DIRECTION OUTPUT ;
    USE SIGNAL ;
    PORT
      LAYER M4 ;
      RECT 0.00000 22.80000 0.03600 22.82400 ;
    END
  END ra_data[474]
  PIN ra_data[475]
    DIRECTION OUTPUT ;
    USE SIGNAL ;
    PORT
      LAYER M4 ;
      RECT 0.00000 22.84800 0.03600 22.87200 ;
    END
  END ra_data[475]
  PIN ra_data[476]
    DIRECTION OUTPUT ;
    USE SIGNAL ;
    PORT
      LAYER M4 ;
      RECT 0.00000 22.89600 0.03600 22.92000 ;
    END
  END ra_data[476]
  PIN ra_data[477]
    DIRECTION OUTPUT ;
    USE SIGNAL ;
    PORT
      LAYER M4 ;
      RECT 0.00000 22.94400 0.03600 22.96800 ;
    END
  END ra_data[477]
  PIN ra_data[478]
    DIRECTION OUTPUT ;
    USE SIGNAL ;
    PORT
      LAYER M4 ;
      RECT 0.00000 22.99200 0.03600 23.01600 ;
    END
  END ra_data[478]
  PIN ra_data[479]
    DIRECTION OUTPUT ;
    USE SIGNAL ;
    PORT
      LAYER M4 ;
      RECT 0.00000 23.04000 0.03600 23.06400 ;
    END
  END ra_data[479]
  PIN ra_data[480]
    DIRECTION OUTPUT ;
    USE SIGNAL ;
    PORT
      LAYER M4 ;
      RECT 0.00000 23.08800 0.03600 23.11200 ;
    END
  END ra_data[480]
  PIN ra_data[481]
    DIRECTION OUTPUT ;
    USE SIGNAL ;
    PORT
      LAYER M4 ;
      RECT 0.00000 23.13600 0.03600 23.16000 ;
    END
  END ra_data[481]
  PIN ra_data[482]
    DIRECTION OUTPUT ;
    USE SIGNAL ;
    PORT
      LAYER M4 ;
      RECT 0.00000 23.18400 0.03600 23.20800 ;
    END
  END ra_data[482]
  PIN ra_data[483]
    DIRECTION OUTPUT ;
    USE SIGNAL ;
    PORT
      LAYER M4 ;
      RECT 0.00000 23.23200 0.03600 23.25600 ;
    END
  END ra_data[483]
  PIN ra_data[484]
    DIRECTION OUTPUT ;
    USE SIGNAL ;
    PORT
      LAYER M4 ;
      RECT 0.00000 23.28000 0.03600 23.30400 ;
    END
  END ra_data[484]
  PIN ra_data[485]
    DIRECTION OUTPUT ;
    USE SIGNAL ;
    PORT
      LAYER M4 ;
      RECT 0.00000 23.32800 0.03600 23.35200 ;
    END
  END ra_data[485]
  PIN ra_data[486]
    DIRECTION OUTPUT ;
    USE SIGNAL ;
    PORT
      LAYER M4 ;
      RECT 0.00000 23.37600 0.03600 23.40000 ;
    END
  END ra_data[486]
  PIN ra_data[487]
    DIRECTION OUTPUT ;
    USE SIGNAL ;
    PORT
      LAYER M4 ;
      RECT 0.00000 23.42400 0.03600 23.44800 ;
    END
  END ra_data[487]
  PIN ra_data[488]
    DIRECTION OUTPUT ;
    USE SIGNAL ;
    PORT
      LAYER M4 ;
      RECT 0.00000 23.47200 0.03600 23.49600 ;
    END
  END ra_data[488]
  PIN ra_data[489]
    DIRECTION OUTPUT ;
    USE SIGNAL ;
    PORT
      LAYER M4 ;
      RECT 0.00000 23.52000 0.03600 23.54400 ;
    END
  END ra_data[489]
  PIN ra_data[490]
    DIRECTION OUTPUT ;
    USE SIGNAL ;
    PORT
      LAYER M4 ;
      RECT 0.00000 23.56800 0.03600 23.59200 ;
    END
  END ra_data[490]
  PIN ra_data[491]
    DIRECTION OUTPUT ;
    USE SIGNAL ;
    PORT
      LAYER M4 ;
      RECT 0.00000 23.61600 0.03600 23.64000 ;
    END
  END ra_data[491]
  PIN ra_data[492]
    DIRECTION OUTPUT ;
    USE SIGNAL ;
    PORT
      LAYER M4 ;
      RECT 0.00000 23.66400 0.03600 23.68800 ;
    END
  END ra_data[492]
  PIN ra_data[493]
    DIRECTION OUTPUT ;
    USE SIGNAL ;
    PORT
      LAYER M4 ;
      RECT 0.00000 23.71200 0.03600 23.73600 ;
    END
  END ra_data[493]
  PIN ra_data[494]
    DIRECTION OUTPUT ;
    USE SIGNAL ;
    PORT
      LAYER M4 ;
      RECT 0.00000 23.76000 0.03600 23.78400 ;
    END
  END ra_data[494]
  PIN ra_data[495]
    DIRECTION OUTPUT ;
    USE SIGNAL ;
    PORT
      LAYER M4 ;
      RECT 0.00000 23.80800 0.03600 23.83200 ;
    END
  END ra_data[495]
  PIN ra_data[496]
    DIRECTION OUTPUT ;
    USE SIGNAL ;
    PORT
      LAYER M4 ;
      RECT 0.00000 23.85600 0.03600 23.88000 ;
    END
  END ra_data[496]
  PIN ra_data[497]
    DIRECTION OUTPUT ;
    USE SIGNAL ;
    PORT
      LAYER M4 ;
      RECT 0.00000 23.90400 0.03600 23.92800 ;
    END
  END ra_data[497]
  PIN ra_data[498]
    DIRECTION OUTPUT ;
    USE SIGNAL ;
    PORT
      LAYER M4 ;
      RECT 0.00000 23.95200 0.03600 23.97600 ;
    END
  END ra_data[498]
  PIN ra_data[499]
    DIRECTION OUTPUT ;
    USE SIGNAL ;
    PORT
      LAYER M4 ;
      RECT 0.00000 24.00000 0.03600 24.02400 ;
    END
  END ra_data[499]
  PIN ra_data[500]
    DIRECTION OUTPUT ;
    USE SIGNAL ;
    PORT
      LAYER M4 ;
      RECT 0.00000 24.04800 0.03600 24.07200 ;
    END
  END ra_data[500]
  PIN ra_data[501]
    DIRECTION OUTPUT ;
    USE SIGNAL ;
    PORT
      LAYER M4 ;
      RECT 0.00000 24.09600 0.03600 24.12000 ;
    END
  END ra_data[501]
  PIN ra_data[502]
    DIRECTION OUTPUT ;
    USE SIGNAL ;
    PORT
      LAYER M4 ;
      RECT 0.00000 24.14400 0.03600 24.16800 ;
    END
  END ra_data[502]
  PIN ra_data[503]
    DIRECTION OUTPUT ;
    USE SIGNAL ;
    PORT
      LAYER M4 ;
      RECT 0.00000 24.19200 0.03600 24.21600 ;
    END
  END ra_data[503]
  PIN ra_data[504]
    DIRECTION OUTPUT ;
    USE SIGNAL ;
    PORT
      LAYER M4 ;
      RECT 0.00000 24.24000 0.03600 24.26400 ;
    END
  END ra_data[504]
  PIN ra_data[505]
    DIRECTION OUTPUT ;
    USE SIGNAL ;
    PORT
      LAYER M4 ;
      RECT 0.00000 24.28800 0.03600 24.31200 ;
    END
  END ra_data[505]
  PIN ra_data[506]
    DIRECTION OUTPUT ;
    USE SIGNAL ;
    PORT
      LAYER M4 ;
      RECT 0.00000 24.33600 0.03600 24.36000 ;
    END
  END ra_data[506]
  PIN ra_data[507]
    DIRECTION OUTPUT ;
    USE SIGNAL ;
    PORT
      LAYER M4 ;
      RECT 0.00000 24.38400 0.03600 24.40800 ;
    END
  END ra_data[507]
  PIN ra_data[508]
    DIRECTION OUTPUT ;
    USE SIGNAL ;
    PORT
      LAYER M4 ;
      RECT 0.00000 24.43200 0.03600 24.45600 ;
    END
  END ra_data[508]
  PIN ra_data[509]
    DIRECTION OUTPUT ;
    USE SIGNAL ;
    PORT
      LAYER M4 ;
      RECT 0.00000 24.48000 0.03600 24.50400 ;
    END
  END ra_data[509]
  PIN ra_data[510]
    DIRECTION OUTPUT ;
    USE SIGNAL ;
    PORT
      LAYER M4 ;
      RECT 0.00000 24.52800 0.03600 24.55200 ;
    END
  END ra_data[510]
  PIN ra_data[511]
    DIRECTION OUTPUT ;
    USE SIGNAL ;
    PORT
      LAYER M4 ;
      RECT 0.00000 24.57600 0.03600 24.60000 ;
    END
  END ra_data[511]
  PIN ra_data[512]
    DIRECTION OUTPUT ;
    USE SIGNAL ;
    PORT
      LAYER M4 ;
      RECT 0.00000 24.62400 0.03600 24.64800 ;
    END
  END ra_data[512]
  PIN ra_data[513]
    DIRECTION OUTPUT ;
    USE SIGNAL ;
    PORT
      LAYER M4 ;
      RECT 0.00000 24.67200 0.03600 24.69600 ;
    END
  END ra_data[513]
  PIN ra_data[514]
    DIRECTION OUTPUT ;
    USE SIGNAL ;
    PORT
      LAYER M4 ;
      RECT 0.00000 24.72000 0.03600 24.74400 ;
    END
  END ra_data[514]
  PIN ra_data[515]
    DIRECTION OUTPUT ;
    USE SIGNAL ;
    PORT
      LAYER M4 ;
      RECT 0.00000 24.76800 0.03600 24.79200 ;
    END
  END ra_data[515]
  PIN ra_data[516]
    DIRECTION OUTPUT ;
    USE SIGNAL ;
    PORT
      LAYER M4 ;
      RECT 0.00000 24.81600 0.03600 24.84000 ;
    END
  END ra_data[516]
  PIN ra_data[517]
    DIRECTION OUTPUT ;
    USE SIGNAL ;
    PORT
      LAYER M4 ;
      RECT 0.00000 24.86400 0.03600 24.88800 ;
    END
  END ra_data[517]
  PIN ra_data[518]
    DIRECTION OUTPUT ;
    USE SIGNAL ;
    PORT
      LAYER M4 ;
      RECT 0.00000 24.91200 0.03600 24.93600 ;
    END
  END ra_data[518]
  PIN ra_data[519]
    DIRECTION OUTPUT ;
    USE SIGNAL ;
    PORT
      LAYER M4 ;
      RECT 0.00000 24.96000 0.03600 24.98400 ;
    END
  END ra_data[519]
  PIN ra_data[520]
    DIRECTION OUTPUT ;
    USE SIGNAL ;
    PORT
      LAYER M4 ;
      RECT 0.00000 25.00800 0.03600 25.03200 ;
    END
  END ra_data[520]
  PIN ra_data[521]
    DIRECTION OUTPUT ;
    USE SIGNAL ;
    PORT
      LAYER M4 ;
      RECT 0.00000 25.05600 0.03600 25.08000 ;
    END
  END ra_data[521]
  PIN ra_data[522]
    DIRECTION OUTPUT ;
    USE SIGNAL ;
    PORT
      LAYER M4 ;
      RECT 0.00000 25.10400 0.03600 25.12800 ;
    END
  END ra_data[522]
  PIN ra_data[523]
    DIRECTION OUTPUT ;
    USE SIGNAL ;
    PORT
      LAYER M4 ;
      RECT 0.00000 25.15200 0.03600 25.17600 ;
    END
  END ra_data[523]
  PIN ra_data[524]
    DIRECTION OUTPUT ;
    USE SIGNAL ;
    PORT
      LAYER M4 ;
      RECT 0.00000 25.20000 0.03600 25.22400 ;
    END
  END ra_data[524]
  PIN ra_data[525]
    DIRECTION OUTPUT ;
    USE SIGNAL ;
    PORT
      LAYER M4 ;
      RECT 0.00000 25.24800 0.03600 25.27200 ;
    END
  END ra_data[525]
  PIN ra_data[526]
    DIRECTION OUTPUT ;
    USE SIGNAL ;
    PORT
      LAYER M4 ;
      RECT 0.00000 25.29600 0.03600 25.32000 ;
    END
  END ra_data[526]
  PIN ra_data[527]
    DIRECTION OUTPUT ;
    USE SIGNAL ;
    PORT
      LAYER M4 ;
      RECT 0.00000 25.34400 0.03600 25.36800 ;
    END
  END ra_data[527]
  PIN ra_data[528]
    DIRECTION OUTPUT ;
    USE SIGNAL ;
    PORT
      LAYER M4 ;
      RECT 0.00000 25.39200 0.03600 25.41600 ;
    END
  END ra_data[528]
  PIN ra_data[529]
    DIRECTION OUTPUT ;
    USE SIGNAL ;
    PORT
      LAYER M4 ;
      RECT 0.00000 25.44000 0.03600 25.46400 ;
    END
  END ra_data[529]
  PIN ra_data[530]
    DIRECTION OUTPUT ;
    USE SIGNAL ;
    PORT
      LAYER M4 ;
      RECT 0.00000 25.48800 0.03600 25.51200 ;
    END
  END ra_data[530]
  PIN ra_data[531]
    DIRECTION OUTPUT ;
    USE SIGNAL ;
    PORT
      LAYER M4 ;
      RECT 0.00000 25.53600 0.03600 25.56000 ;
    END
  END ra_data[531]
  PIN ra_data[532]
    DIRECTION OUTPUT ;
    USE SIGNAL ;
    PORT
      LAYER M4 ;
      RECT 0.00000 25.58400 0.03600 25.60800 ;
    END
  END ra_data[532]
  PIN ra_data[533]
    DIRECTION OUTPUT ;
    USE SIGNAL ;
    PORT
      LAYER M4 ;
      RECT 0.00000 25.63200 0.03600 25.65600 ;
    END
  END ra_data[533]
  PIN ra_data[534]
    DIRECTION OUTPUT ;
    USE SIGNAL ;
    PORT
      LAYER M4 ;
      RECT 0.00000 25.68000 0.03600 25.70400 ;
    END
  END ra_data[534]
  PIN ra_data[535]
    DIRECTION OUTPUT ;
    USE SIGNAL ;
    PORT
      LAYER M4 ;
      RECT 0.00000 25.72800 0.03600 25.75200 ;
    END
  END ra_data[535]
  PIN ra_data[536]
    DIRECTION OUTPUT ;
    USE SIGNAL ;
    PORT
      LAYER M4 ;
      RECT 0.00000 25.77600 0.03600 25.80000 ;
    END
  END ra_data[536]
  PIN ra_data[537]
    DIRECTION OUTPUT ;
    USE SIGNAL ;
    PORT
      LAYER M4 ;
      RECT 0.00000 25.82400 0.03600 25.84800 ;
    END
  END ra_data[537]
  PIN ra_data[538]
    DIRECTION OUTPUT ;
    USE SIGNAL ;
    PORT
      LAYER M4 ;
      RECT 0.00000 25.87200 0.03600 25.89600 ;
    END
  END ra_data[538]
  PIN ra_data[539]
    DIRECTION OUTPUT ;
    USE SIGNAL ;
    PORT
      LAYER M4 ;
      RECT 0.00000 25.92000 0.03600 25.94400 ;
    END
  END ra_data[539]
  PIN ra_data[540]
    DIRECTION OUTPUT ;
    USE SIGNAL ;
    PORT
      LAYER M4 ;
      RECT 0.00000 25.96800 0.03600 25.99200 ;
    END
  END ra_data[540]
  PIN ra_data[541]
    DIRECTION OUTPUT ;
    USE SIGNAL ;
    PORT
      LAYER M4 ;
      RECT 0.00000 26.01600 0.03600 26.04000 ;
    END
  END ra_data[541]
  PIN ra_data[542]
    DIRECTION OUTPUT ;
    USE SIGNAL ;
    PORT
      LAYER M4 ;
      RECT 0.00000 26.06400 0.03600 26.08800 ;
    END
  END ra_data[542]
  PIN ra_data[543]
    DIRECTION OUTPUT ;
    USE SIGNAL ;
    PORT
      LAYER M4 ;
      RECT 0.00000 26.11200 0.03600 26.13600 ;
    END
  END ra_data[543]
  PIN ra_data[544]
    DIRECTION OUTPUT ;
    USE SIGNAL ;
    PORT
      LAYER M4 ;
      RECT 0.00000 26.16000 0.03600 26.18400 ;
    END
  END ra_data[544]
  PIN ra_data[545]
    DIRECTION OUTPUT ;
    USE SIGNAL ;
    PORT
      LAYER M4 ;
      RECT 0.00000 26.20800 0.03600 26.23200 ;
    END
  END ra_data[545]
  PIN ra_data[546]
    DIRECTION OUTPUT ;
    USE SIGNAL ;
    PORT
      LAYER M4 ;
      RECT 0.00000 26.25600 0.03600 26.28000 ;
    END
  END ra_data[546]
  PIN ra_data[547]
    DIRECTION OUTPUT ;
    USE SIGNAL ;
    PORT
      LAYER M4 ;
      RECT 0.00000 26.30400 0.03600 26.32800 ;
    END
  END ra_data[547]
  PIN ra_data[548]
    DIRECTION OUTPUT ;
    USE SIGNAL ;
    PORT
      LAYER M4 ;
      RECT 0.00000 26.35200 0.03600 26.37600 ;
    END
  END ra_data[548]
  PIN ra_data[549]
    DIRECTION OUTPUT ;
    USE SIGNAL ;
    PORT
      LAYER M4 ;
      RECT 0.00000 26.40000 0.03600 26.42400 ;
    END
  END ra_data[549]
  PIN ra_data[550]
    DIRECTION OUTPUT ;
    USE SIGNAL ;
    PORT
      LAYER M4 ;
      RECT 0.00000 26.44800 0.03600 26.47200 ;
    END
  END ra_data[550]
  PIN ra_data[551]
    DIRECTION OUTPUT ;
    USE SIGNAL ;
    PORT
      LAYER M4 ;
      RECT 0.00000 26.49600 0.03600 26.52000 ;
    END
  END ra_data[551]
  PIN ra_data[552]
    DIRECTION OUTPUT ;
    USE SIGNAL ;
    PORT
      LAYER M4 ;
      RECT 0.00000 26.54400 0.03600 26.56800 ;
    END
  END ra_data[552]
  PIN ra_data[553]
    DIRECTION OUTPUT ;
    USE SIGNAL ;
    PORT
      LAYER M4 ;
      RECT 0.00000 26.59200 0.03600 26.61600 ;
    END
  END ra_data[553]
  PIN ra_data[554]
    DIRECTION OUTPUT ;
    USE SIGNAL ;
    PORT
      LAYER M4 ;
      RECT 0.00000 26.64000 0.03600 26.66400 ;
    END
  END ra_data[554]
  PIN ra_data[555]
    DIRECTION OUTPUT ;
    USE SIGNAL ;
    PORT
      LAYER M4 ;
      RECT 0.00000 26.68800 0.03600 26.71200 ;
    END
  END ra_data[555]
  PIN ra_data[556]
    DIRECTION OUTPUT ;
    USE SIGNAL ;
    PORT
      LAYER M4 ;
      RECT 0.00000 26.73600 0.03600 26.76000 ;
    END
  END ra_data[556]
  PIN ra_data[557]
    DIRECTION OUTPUT ;
    USE SIGNAL ;
    PORT
      LAYER M4 ;
      RECT 0.00000 26.78400 0.03600 26.80800 ;
    END
  END ra_data[557]
  PIN ra_data[558]
    DIRECTION OUTPUT ;
    USE SIGNAL ;
    PORT
      LAYER M4 ;
      RECT 0.00000 26.83200 0.03600 26.85600 ;
    END
  END ra_data[558]
  PIN ra_data[559]
    DIRECTION OUTPUT ;
    USE SIGNAL ;
    PORT
      LAYER M4 ;
      RECT 0.00000 26.88000 0.03600 26.90400 ;
    END
  END ra_data[559]
  PIN ra_data[560]
    DIRECTION OUTPUT ;
    USE SIGNAL ;
    PORT
      LAYER M4 ;
      RECT 0.00000 26.92800 0.03600 26.95200 ;
    END
  END ra_data[560]
  PIN ra_data[561]
    DIRECTION OUTPUT ;
    USE SIGNAL ;
    PORT
      LAYER M4 ;
      RECT 0.00000 26.97600 0.03600 27.00000 ;
    END
  END ra_data[561]
  PIN ra_data[562]
    DIRECTION OUTPUT ;
    USE SIGNAL ;
    PORT
      LAYER M4 ;
      RECT 0.00000 27.02400 0.03600 27.04800 ;
    END
  END ra_data[562]
  PIN ra_data[563]
    DIRECTION OUTPUT ;
    USE SIGNAL ;
    PORT
      LAYER M4 ;
      RECT 0.00000 27.07200 0.03600 27.09600 ;
    END
  END ra_data[563]
  PIN ra_data[564]
    DIRECTION OUTPUT ;
    USE SIGNAL ;
    PORT
      LAYER M4 ;
      RECT 0.00000 27.12000 0.03600 27.14400 ;
    END
  END ra_data[564]
  PIN ra_data[565]
    DIRECTION OUTPUT ;
    USE SIGNAL ;
    PORT
      LAYER M4 ;
      RECT 0.00000 27.16800 0.03600 27.19200 ;
    END
  END ra_data[565]
  PIN ra_data[566]
    DIRECTION OUTPUT ;
    USE SIGNAL ;
    PORT
      LAYER M4 ;
      RECT 0.00000 27.21600 0.03600 27.24000 ;
    END
  END ra_data[566]
  PIN ra_data[567]
    DIRECTION OUTPUT ;
    USE SIGNAL ;
    PORT
      LAYER M4 ;
      RECT 0.00000 27.26400 0.03600 27.28800 ;
    END
  END ra_data[567]
  PIN ra_data[568]
    DIRECTION OUTPUT ;
    USE SIGNAL ;
    PORT
      LAYER M4 ;
      RECT 0.00000 27.31200 0.03600 27.33600 ;
    END
  END ra_data[568]
  PIN ra_data[569]
    DIRECTION OUTPUT ;
    USE SIGNAL ;
    PORT
      LAYER M4 ;
      RECT 0.00000 27.36000 0.03600 27.38400 ;
    END
  END ra_data[569]
  PIN ra_data[570]
    DIRECTION OUTPUT ;
    USE SIGNAL ;
    PORT
      LAYER M4 ;
      RECT 0.00000 27.40800 0.03600 27.43200 ;
    END
  END ra_data[570]
  PIN ra_data[571]
    DIRECTION OUTPUT ;
    USE SIGNAL ;
    PORT
      LAYER M4 ;
      RECT 0.00000 27.45600 0.03600 27.48000 ;
    END
  END ra_data[571]
  PIN ra_data[572]
    DIRECTION OUTPUT ;
    USE SIGNAL ;
    PORT
      LAYER M4 ;
      RECT 0.00000 27.50400 0.03600 27.52800 ;
    END
  END ra_data[572]
  PIN ra_data[573]
    DIRECTION OUTPUT ;
    USE SIGNAL ;
    PORT
      LAYER M4 ;
      RECT 0.00000 27.55200 0.03600 27.57600 ;
    END
  END ra_data[573]
  PIN ra_data[574]
    DIRECTION OUTPUT ;
    USE SIGNAL ;
    PORT
      LAYER M4 ;
      RECT 0.00000 27.60000 0.03600 27.62400 ;
    END
  END ra_data[574]
  PIN ra_data[575]
    DIRECTION OUTPUT ;
    USE SIGNAL ;
    PORT
      LAYER M4 ;
      RECT 0.00000 27.64800 0.03600 27.67200 ;
    END
  END ra_data[575]
  PIN ra_data[576]
    DIRECTION OUTPUT ;
    USE SIGNAL ;
    PORT
      LAYER M4 ;
      RECT 0.00000 27.69600 0.03600 27.72000 ;
    END
  END ra_data[576]
  PIN ra_data[577]
    DIRECTION OUTPUT ;
    USE SIGNAL ;
    PORT
      LAYER M4 ;
      RECT 0.00000 27.74400 0.03600 27.76800 ;
    END
  END ra_data[577]
  PIN ra_data[578]
    DIRECTION OUTPUT ;
    USE SIGNAL ;
    PORT
      LAYER M4 ;
      RECT 0.00000 27.79200 0.03600 27.81600 ;
    END
  END ra_data[578]
  PIN ra_data[579]
    DIRECTION OUTPUT ;
    USE SIGNAL ;
    PORT
      LAYER M4 ;
      RECT 0.00000 27.84000 0.03600 27.86400 ;
    END
  END ra_data[579]
  PIN ra_data[580]
    DIRECTION OUTPUT ;
    USE SIGNAL ;
    PORT
      LAYER M4 ;
      RECT 0.00000 27.88800 0.03600 27.91200 ;
    END
  END ra_data[580]
  PIN ra_data[581]
    DIRECTION OUTPUT ;
    USE SIGNAL ;
    PORT
      LAYER M4 ;
      RECT 0.00000 27.93600 0.03600 27.96000 ;
    END
  END ra_data[581]
  PIN ra_data[582]
    DIRECTION OUTPUT ;
    USE SIGNAL ;
    PORT
      LAYER M4 ;
      RECT 0.00000 27.98400 0.03600 28.00800 ;
    END
  END ra_data[582]
  PIN ra_data[583]
    DIRECTION OUTPUT ;
    USE SIGNAL ;
    PORT
      LAYER M4 ;
      RECT 0.00000 28.03200 0.03600 28.05600 ;
    END
  END ra_data[583]
  PIN ra_data[584]
    DIRECTION OUTPUT ;
    USE SIGNAL ;
    PORT
      LAYER M4 ;
      RECT 0.00000 28.08000 0.03600 28.10400 ;
    END
  END ra_data[584]
  PIN ra_data[585]
    DIRECTION OUTPUT ;
    USE SIGNAL ;
    PORT
      LAYER M4 ;
      RECT 0.00000 28.12800 0.03600 28.15200 ;
    END
  END ra_data[585]
  PIN ra_data[586]
    DIRECTION OUTPUT ;
    USE SIGNAL ;
    PORT
      LAYER M4 ;
      RECT 0.00000 28.17600 0.03600 28.20000 ;
    END
  END ra_data[586]
  PIN ra_data[587]
    DIRECTION OUTPUT ;
    USE SIGNAL ;
    PORT
      LAYER M4 ;
      RECT 0.00000 28.22400 0.03600 28.24800 ;
    END
  END ra_data[587]
  PIN ra_data[588]
    DIRECTION OUTPUT ;
    USE SIGNAL ;
    PORT
      LAYER M4 ;
      RECT 0.00000 28.27200 0.03600 28.29600 ;
    END
  END ra_data[588]
  PIN ra_data[589]
    DIRECTION OUTPUT ;
    USE SIGNAL ;
    PORT
      LAYER M4 ;
      RECT 0.00000 28.32000 0.03600 28.34400 ;
    END
  END ra_data[589]
  PIN ra_data[590]
    DIRECTION OUTPUT ;
    USE SIGNAL ;
    PORT
      LAYER M4 ;
      RECT 0.00000 28.36800 0.03600 28.39200 ;
    END
  END ra_data[590]
  PIN ra_data[591]
    DIRECTION OUTPUT ;
    USE SIGNAL ;
    PORT
      LAYER M4 ;
      RECT 0.00000 28.41600 0.03600 28.44000 ;
    END
  END ra_data[591]
  PIN ra_data[592]
    DIRECTION OUTPUT ;
    USE SIGNAL ;
    PORT
      LAYER M4 ;
      RECT 0.00000 28.46400 0.03600 28.48800 ;
    END
  END ra_data[592]
  PIN ra_data[593]
    DIRECTION OUTPUT ;
    USE SIGNAL ;
    PORT
      LAYER M4 ;
      RECT 0.00000 28.51200 0.03600 28.53600 ;
    END
  END ra_data[593]
  PIN ra_data[594]
    DIRECTION OUTPUT ;
    USE SIGNAL ;
    PORT
      LAYER M4 ;
      RECT 0.00000 28.56000 0.03600 28.58400 ;
    END
  END ra_data[594]
  PIN ra_data[595]
    DIRECTION OUTPUT ;
    USE SIGNAL ;
    PORT
      LAYER M4 ;
      RECT 0.00000 28.60800 0.03600 28.63200 ;
    END
  END ra_data[595]
  PIN ra_data[596]
    DIRECTION OUTPUT ;
    USE SIGNAL ;
    PORT
      LAYER M4 ;
      RECT 0.00000 28.65600 0.03600 28.68000 ;
    END
  END ra_data[596]
  PIN ra_data[597]
    DIRECTION OUTPUT ;
    USE SIGNAL ;
    PORT
      LAYER M4 ;
      RECT 0.00000 28.70400 0.03600 28.72800 ;
    END
  END ra_data[597]
  PIN ra_data[598]
    DIRECTION OUTPUT ;
    USE SIGNAL ;
    PORT
      LAYER M4 ;
      RECT 0.00000 28.75200 0.03600 28.77600 ;
    END
  END ra_data[598]
  PIN ra_data[599]
    DIRECTION OUTPUT ;
    USE SIGNAL ;
    PORT
      LAYER M4 ;
      RECT 0.00000 28.80000 0.03600 28.82400 ;
    END
  END ra_data[599]
  PIN ra_data[600]
    DIRECTION OUTPUT ;
    USE SIGNAL ;
    PORT
      LAYER M4 ;
      RECT 0.00000 28.84800 0.03600 28.87200 ;
    END
  END ra_data[600]
  PIN ra_data[601]
    DIRECTION OUTPUT ;
    USE SIGNAL ;
    PORT
      LAYER M4 ;
      RECT 0.00000 28.89600 0.03600 28.92000 ;
    END
  END ra_data[601]
  PIN ra_data[602]
    DIRECTION OUTPUT ;
    USE SIGNAL ;
    PORT
      LAYER M4 ;
      RECT 0.00000 28.94400 0.03600 28.96800 ;
    END
  END ra_data[602]
  PIN ra_data[603]
    DIRECTION OUTPUT ;
    USE SIGNAL ;
    PORT
      LAYER M4 ;
      RECT 0.00000 28.99200 0.03600 29.01600 ;
    END
  END ra_data[603]
  PIN ra_data[604]
    DIRECTION OUTPUT ;
    USE SIGNAL ;
    PORT
      LAYER M4 ;
      RECT 0.00000 29.04000 0.03600 29.06400 ;
    END
  END ra_data[604]
  PIN ra_data[605]
    DIRECTION OUTPUT ;
    USE SIGNAL ;
    PORT
      LAYER M4 ;
      RECT 0.00000 29.08800 0.03600 29.11200 ;
    END
  END ra_data[605]
  PIN ra_data[606]
    DIRECTION OUTPUT ;
    USE SIGNAL ;
    PORT
      LAYER M4 ;
      RECT 0.00000 29.13600 0.03600 29.16000 ;
    END
  END ra_data[606]
  PIN ra_data[607]
    DIRECTION OUTPUT ;
    USE SIGNAL ;
    PORT
      LAYER M4 ;
      RECT 0.00000 29.18400 0.03600 29.20800 ;
    END
  END ra_data[607]
  PIN ra_data[608]
    DIRECTION OUTPUT ;
    USE SIGNAL ;
    PORT
      LAYER M4 ;
      RECT 0.00000 29.23200 0.03600 29.25600 ;
    END
  END ra_data[608]
  PIN ra_data[609]
    DIRECTION OUTPUT ;
    USE SIGNAL ;
    PORT
      LAYER M4 ;
      RECT 0.00000 29.28000 0.03600 29.30400 ;
    END
  END ra_data[609]
  PIN ra_data[610]
    DIRECTION OUTPUT ;
    USE SIGNAL ;
    PORT
      LAYER M4 ;
      RECT 0.00000 29.32800 0.03600 29.35200 ;
    END
  END ra_data[610]
  PIN ra_data[611]
    DIRECTION OUTPUT ;
    USE SIGNAL ;
    PORT
      LAYER M4 ;
      RECT 0.00000 29.37600 0.03600 29.40000 ;
    END
  END ra_data[611]
  PIN ra_data[612]
    DIRECTION OUTPUT ;
    USE SIGNAL ;
    PORT
      LAYER M4 ;
      RECT 0.00000 29.42400 0.03600 29.44800 ;
    END
  END ra_data[612]
  PIN ra_data[613]
    DIRECTION OUTPUT ;
    USE SIGNAL ;
    PORT
      LAYER M4 ;
      RECT 0.00000 29.47200 0.03600 29.49600 ;
    END
  END ra_data[613]
  PIN ra_data[614]
    DIRECTION OUTPUT ;
    USE SIGNAL ;
    PORT
      LAYER M4 ;
      RECT 0.00000 29.52000 0.03600 29.54400 ;
    END
  END ra_data[614]
  PIN ra_data[615]
    DIRECTION OUTPUT ;
    USE SIGNAL ;
    PORT
      LAYER M4 ;
      RECT 0.00000 29.56800 0.03600 29.59200 ;
    END
  END ra_data[615]
  PIN ra_data[616]
    DIRECTION OUTPUT ;
    USE SIGNAL ;
    PORT
      LAYER M4 ;
      RECT 0.00000 29.61600 0.03600 29.64000 ;
    END
  END ra_data[616]
  PIN ra_data[617]
    DIRECTION OUTPUT ;
    USE SIGNAL ;
    PORT
      LAYER M4 ;
      RECT 0.00000 29.66400 0.03600 29.68800 ;
    END
  END ra_data[617]
  PIN ra_data[618]
    DIRECTION OUTPUT ;
    USE SIGNAL ;
    PORT
      LAYER M4 ;
      RECT 0.00000 29.71200 0.03600 29.73600 ;
    END
  END ra_data[618]
  PIN ra_data[619]
    DIRECTION OUTPUT ;
    USE SIGNAL ;
    PORT
      LAYER M4 ;
      RECT 0.00000 29.76000 0.03600 29.78400 ;
    END
  END ra_data[619]
  PIN ra_data[620]
    DIRECTION OUTPUT ;
    USE SIGNAL ;
    PORT
      LAYER M4 ;
      RECT 0.00000 29.80800 0.03600 29.83200 ;
    END
  END ra_data[620]
  PIN ra_data[621]
    DIRECTION OUTPUT ;
    USE SIGNAL ;
    PORT
      LAYER M4 ;
      RECT 0.00000 29.85600 0.03600 29.88000 ;
    END
  END ra_data[621]
  PIN ra_data[622]
    DIRECTION OUTPUT ;
    USE SIGNAL ;
    PORT
      LAYER M4 ;
      RECT 0.00000 29.90400 0.03600 29.92800 ;
    END
  END ra_data[622]
  PIN ra_data[623]
    DIRECTION OUTPUT ;
    USE SIGNAL ;
    PORT
      LAYER M4 ;
      RECT 0.00000 29.95200 0.03600 29.97600 ;
    END
  END ra_data[623]
  PIN ra_data[624]
    DIRECTION OUTPUT ;
    USE SIGNAL ;
    PORT
      LAYER M4 ;
      RECT 0.00000 30.00000 0.03600 30.02400 ;
    END
  END ra_data[624]
  PIN ra_data[625]
    DIRECTION OUTPUT ;
    USE SIGNAL ;
    PORT
      LAYER M4 ;
      RECT 0.00000 30.04800 0.03600 30.07200 ;
    END
  END ra_data[625]
  PIN ra_data[626]
    DIRECTION OUTPUT ;
    USE SIGNAL ;
    PORT
      LAYER M4 ;
      RECT 0.00000 30.09600 0.03600 30.12000 ;
    END
  END ra_data[626]
  PIN ra_data[627]
    DIRECTION OUTPUT ;
    USE SIGNAL ;
    PORT
      LAYER M4 ;
      RECT 0.00000 30.14400 0.03600 30.16800 ;
    END
  END ra_data[627]
  PIN ra_data[628]
    DIRECTION OUTPUT ;
    USE SIGNAL ;
    PORT
      LAYER M4 ;
      RECT 0.00000 30.19200 0.03600 30.21600 ;
    END
  END ra_data[628]
  PIN ra_data[629]
    DIRECTION OUTPUT ;
    USE SIGNAL ;
    PORT
      LAYER M4 ;
      RECT 0.00000 30.24000 0.03600 30.26400 ;
    END
  END ra_data[629]
  PIN ra_data[630]
    DIRECTION OUTPUT ;
    USE SIGNAL ;
    PORT
      LAYER M4 ;
      RECT 0.00000 30.28800 0.03600 30.31200 ;
    END
  END ra_data[630]
  PIN ra_data[631]
    DIRECTION OUTPUT ;
    USE SIGNAL ;
    PORT
      LAYER M4 ;
      RECT 0.00000 30.33600 0.03600 30.36000 ;
    END
  END ra_data[631]
  PIN ra_data[632]
    DIRECTION OUTPUT ;
    USE SIGNAL ;
    PORT
      LAYER M4 ;
      RECT 0.00000 30.38400 0.03600 30.40800 ;
    END
  END ra_data[632]
  PIN ra_data[633]
    DIRECTION OUTPUT ;
    USE SIGNAL ;
    PORT
      LAYER M4 ;
      RECT 0.00000 30.43200 0.03600 30.45600 ;
    END
  END ra_data[633]
  PIN ra_data[634]
    DIRECTION OUTPUT ;
    USE SIGNAL ;
    PORT
      LAYER M4 ;
      RECT 0.00000 30.48000 0.03600 30.50400 ;
    END
  END ra_data[634]
  PIN ra_data[635]
    DIRECTION OUTPUT ;
    USE SIGNAL ;
    PORT
      LAYER M4 ;
      RECT 0.00000 30.52800 0.03600 30.55200 ;
    END
  END ra_data[635]
  PIN ra_data[636]
    DIRECTION OUTPUT ;
    USE SIGNAL ;
    PORT
      LAYER M4 ;
      RECT 0.00000 30.57600 0.03600 30.60000 ;
    END
  END ra_data[636]
  PIN ra_data[637]
    DIRECTION OUTPUT ;
    USE SIGNAL ;
    PORT
      LAYER M4 ;
      RECT 0.00000 30.62400 0.03600 30.64800 ;
    END
  END ra_data[637]
  PIN ra_data[638]
    DIRECTION OUTPUT ;
    USE SIGNAL ;
    PORT
      LAYER M4 ;
      RECT 0.00000 30.67200 0.03600 30.69600 ;
    END
  END ra_data[638]
  PIN ra_data[639]
    DIRECTION OUTPUT ;
    USE SIGNAL ;
    PORT
      LAYER M4 ;
      RECT 0.00000 30.72000 0.03600 30.74400 ;
    END
  END ra_data[639]
  PIN ra_data[640]
    DIRECTION OUTPUT ;
    USE SIGNAL ;
    PORT
      LAYER M4 ;
      RECT 0.00000 30.76800 0.03600 30.79200 ;
    END
  END ra_data[640]
  PIN ra_data[641]
    DIRECTION OUTPUT ;
    USE SIGNAL ;
    PORT
      LAYER M4 ;
      RECT 0.00000 30.81600 0.03600 30.84000 ;
    END
  END ra_data[641]
  PIN ra_data[642]
    DIRECTION OUTPUT ;
    USE SIGNAL ;
    PORT
      LAYER M4 ;
      RECT 0.00000 30.86400 0.03600 30.88800 ;
    END
  END ra_data[642]
  PIN ra_data[643]
    DIRECTION OUTPUT ;
    USE SIGNAL ;
    PORT
      LAYER M4 ;
      RECT 0.00000 30.91200 0.03600 30.93600 ;
    END
  END ra_data[643]
  PIN ra_data[644]
    DIRECTION OUTPUT ;
    USE SIGNAL ;
    PORT
      LAYER M4 ;
      RECT 0.00000 30.96000 0.03600 30.98400 ;
    END
  END ra_data[644]
  PIN ra_data[645]
    DIRECTION OUTPUT ;
    USE SIGNAL ;
    PORT
      LAYER M4 ;
      RECT 0.00000 31.00800 0.03600 31.03200 ;
    END
  END ra_data[645]
  PIN ra_data[646]
    DIRECTION OUTPUT ;
    USE SIGNAL ;
    PORT
      LAYER M4 ;
      RECT 0.00000 31.05600 0.03600 31.08000 ;
    END
  END ra_data[646]
  PIN ra_data[647]
    DIRECTION OUTPUT ;
    USE SIGNAL ;
    PORT
      LAYER M4 ;
      RECT 0.00000 31.10400 0.03600 31.12800 ;
    END
  END ra_data[647]
  PIN ra_data[648]
    DIRECTION OUTPUT ;
    USE SIGNAL ;
    PORT
      LAYER M4 ;
      RECT 0.00000 31.15200 0.03600 31.17600 ;
    END
  END ra_data[648]
  PIN ra_data[649]
    DIRECTION OUTPUT ;
    USE SIGNAL ;
    PORT
      LAYER M4 ;
      RECT 0.00000 31.20000 0.03600 31.22400 ;
    END
  END ra_data[649]
  PIN ra_data[650]
    DIRECTION OUTPUT ;
    USE SIGNAL ;
    PORT
      LAYER M4 ;
      RECT 0.00000 31.24800 0.03600 31.27200 ;
    END
  END ra_data[650]
  PIN ra_data[651]
    DIRECTION OUTPUT ;
    USE SIGNAL ;
    PORT
      LAYER M4 ;
      RECT 0.00000 31.29600 0.03600 31.32000 ;
    END
  END ra_data[651]
  PIN ra_data[652]
    DIRECTION OUTPUT ;
    USE SIGNAL ;
    PORT
      LAYER M4 ;
      RECT 0.00000 31.34400 0.03600 31.36800 ;
    END
  END ra_data[652]
  PIN ra_data[653]
    DIRECTION OUTPUT ;
    USE SIGNAL ;
    PORT
      LAYER M4 ;
      RECT 0.00000 31.39200 0.03600 31.41600 ;
    END
  END ra_data[653]
  PIN ra_data[654]
    DIRECTION OUTPUT ;
    USE SIGNAL ;
    PORT
      LAYER M4 ;
      RECT 0.00000 31.44000 0.03600 31.46400 ;
    END
  END ra_data[654]
  PIN ra_data[655]
    DIRECTION OUTPUT ;
    USE SIGNAL ;
    PORT
      LAYER M4 ;
      RECT 0.00000 31.48800 0.03600 31.51200 ;
    END
  END ra_data[655]
  PIN ra_data[656]
    DIRECTION OUTPUT ;
    USE SIGNAL ;
    PORT
      LAYER M4 ;
      RECT 0.00000 31.53600 0.03600 31.56000 ;
    END
  END ra_data[656]
  PIN ra_data[657]
    DIRECTION OUTPUT ;
    USE SIGNAL ;
    PORT
      LAYER M4 ;
      RECT 0.00000 31.58400 0.03600 31.60800 ;
    END
  END ra_data[657]
  PIN ra_data[658]
    DIRECTION OUTPUT ;
    USE SIGNAL ;
    PORT
      LAYER M4 ;
      RECT 0.00000 31.63200 0.03600 31.65600 ;
    END
  END ra_data[658]
  PIN ra_data[659]
    DIRECTION OUTPUT ;
    USE SIGNAL ;
    PORT
      LAYER M4 ;
      RECT 0.00000 31.68000 0.03600 31.70400 ;
    END
  END ra_data[659]
  PIN ra_data[660]
    DIRECTION OUTPUT ;
    USE SIGNAL ;
    PORT
      LAYER M4 ;
      RECT 0.00000 31.72800 0.03600 31.75200 ;
    END
  END ra_data[660]
  PIN ra_data[661]
    DIRECTION OUTPUT ;
    USE SIGNAL ;
    PORT
      LAYER M4 ;
      RECT 0.00000 31.77600 0.03600 31.80000 ;
    END
  END ra_data[661]
  PIN ra_data[662]
    DIRECTION OUTPUT ;
    USE SIGNAL ;
    PORT
      LAYER M4 ;
      RECT 0.00000 31.82400 0.03600 31.84800 ;
    END
  END ra_data[662]
  PIN ra_data[663]
    DIRECTION OUTPUT ;
    USE SIGNAL ;
    PORT
      LAYER M4 ;
      RECT 0.00000 31.87200 0.03600 31.89600 ;
    END
  END ra_data[663]
  PIN ra_data[664]
    DIRECTION OUTPUT ;
    USE SIGNAL ;
    PORT
      LAYER M4 ;
      RECT 0.00000 31.92000 0.03600 31.94400 ;
    END
  END ra_data[664]
  PIN ra_data[665]
    DIRECTION OUTPUT ;
    USE SIGNAL ;
    PORT
      LAYER M4 ;
      RECT 0.00000 31.96800 0.03600 31.99200 ;
    END
  END ra_data[665]
  PIN ra_data[666]
    DIRECTION OUTPUT ;
    USE SIGNAL ;
    PORT
      LAYER M4 ;
      RECT 0.00000 32.01600 0.03600 32.04000 ;
    END
  END ra_data[666]
  PIN ra_data[667]
    DIRECTION OUTPUT ;
    USE SIGNAL ;
    PORT
      LAYER M4 ;
      RECT 0.00000 32.06400 0.03600 32.08800 ;
    END
  END ra_data[667]
  PIN ra_data[668]
    DIRECTION OUTPUT ;
    USE SIGNAL ;
    PORT
      LAYER M4 ;
      RECT 0.00000 32.11200 0.03600 32.13600 ;
    END
  END ra_data[668]
  PIN ra_data[669]
    DIRECTION OUTPUT ;
    USE SIGNAL ;
    PORT
      LAYER M4 ;
      RECT 0.00000 32.16000 0.03600 32.18400 ;
    END
  END ra_data[669]
  PIN ra_data[670]
    DIRECTION OUTPUT ;
    USE SIGNAL ;
    PORT
      LAYER M4 ;
      RECT 0.00000 32.20800 0.03600 32.23200 ;
    END
  END ra_data[670]
  PIN ra_data[671]
    DIRECTION OUTPUT ;
    USE SIGNAL ;
    PORT
      LAYER M4 ;
      RECT 0.00000 32.25600 0.03600 32.28000 ;
    END
  END ra_data[671]
  PIN ra_data[672]
    DIRECTION OUTPUT ;
    USE SIGNAL ;
    PORT
      LAYER M4 ;
      RECT 0.00000 32.30400 0.03600 32.32800 ;
    END
  END ra_data[672]
  PIN ra_data[673]
    DIRECTION OUTPUT ;
    USE SIGNAL ;
    PORT
      LAYER M4 ;
      RECT 0.00000 32.35200 0.03600 32.37600 ;
    END
  END ra_data[673]
  PIN ra_data[674]
    DIRECTION OUTPUT ;
    USE SIGNAL ;
    PORT
      LAYER M4 ;
      RECT 0.00000 32.40000 0.03600 32.42400 ;
    END
  END ra_data[674]
  PIN ra_data[675]
    DIRECTION OUTPUT ;
    USE SIGNAL ;
    PORT
      LAYER M4 ;
      RECT 0.00000 32.44800 0.03600 32.47200 ;
    END
  END ra_data[675]
  PIN ra_data[676]
    DIRECTION OUTPUT ;
    USE SIGNAL ;
    PORT
      LAYER M4 ;
      RECT 0.00000 32.49600 0.03600 32.52000 ;
    END
  END ra_data[676]
  PIN ra_data[677]
    DIRECTION OUTPUT ;
    USE SIGNAL ;
    PORT
      LAYER M4 ;
      RECT 0.00000 32.54400 0.03600 32.56800 ;
    END
  END ra_data[677]
  PIN ra_data[678]
    DIRECTION OUTPUT ;
    USE SIGNAL ;
    PORT
      LAYER M4 ;
      RECT 0.00000 32.59200 0.03600 32.61600 ;
    END
  END ra_data[678]
  PIN ra_data[679]
    DIRECTION OUTPUT ;
    USE SIGNAL ;
    PORT
      LAYER M4 ;
      RECT 0.00000 32.64000 0.03600 32.66400 ;
    END
  END ra_data[679]
  PIN ra_data[680]
    DIRECTION OUTPUT ;
    USE SIGNAL ;
    PORT
      LAYER M4 ;
      RECT 0.00000 32.68800 0.03600 32.71200 ;
    END
  END ra_data[680]
  PIN ra_data[681]
    DIRECTION OUTPUT ;
    USE SIGNAL ;
    PORT
      LAYER M4 ;
      RECT 0.00000 32.73600 0.03600 32.76000 ;
    END
  END ra_data[681]
  PIN ra_data[682]
    DIRECTION OUTPUT ;
    USE SIGNAL ;
    PORT
      LAYER M4 ;
      RECT 0.00000 32.78400 0.03600 32.80800 ;
    END
  END ra_data[682]
  PIN ra_data[683]
    DIRECTION OUTPUT ;
    USE SIGNAL ;
    PORT
      LAYER M4 ;
      RECT 0.00000 32.83200 0.03600 32.85600 ;
    END
  END ra_data[683]
  PIN ra_data[684]
    DIRECTION OUTPUT ;
    USE SIGNAL ;
    PORT
      LAYER M4 ;
      RECT 0.00000 32.88000 0.03600 32.90400 ;
    END
  END ra_data[684]
  PIN ra_data[685]
    DIRECTION OUTPUT ;
    USE SIGNAL ;
    PORT
      LAYER M4 ;
      RECT 0.00000 32.92800 0.03600 32.95200 ;
    END
  END ra_data[685]
  PIN ra_data[686]
    DIRECTION OUTPUT ;
    USE SIGNAL ;
    PORT
      LAYER M4 ;
      RECT 0.00000 32.97600 0.03600 33.00000 ;
    END
  END ra_data[686]
  PIN ra_data[687]
    DIRECTION OUTPUT ;
    USE SIGNAL ;
    PORT
      LAYER M4 ;
      RECT 0.00000 33.02400 0.03600 33.04800 ;
    END
  END ra_data[687]
  PIN ra_data[688]
    DIRECTION OUTPUT ;
    USE SIGNAL ;
    PORT
      LAYER M4 ;
      RECT 0.00000 33.07200 0.03600 33.09600 ;
    END
  END ra_data[688]
  PIN ra_data[689]
    DIRECTION OUTPUT ;
    USE SIGNAL ;
    PORT
      LAYER M4 ;
      RECT 0.00000 33.12000 0.03600 33.14400 ;
    END
  END ra_data[689]
  PIN ra_data[690]
    DIRECTION OUTPUT ;
    USE SIGNAL ;
    PORT
      LAYER M4 ;
      RECT 0.00000 33.16800 0.03600 33.19200 ;
    END
  END ra_data[690]
  PIN ra_data[691]
    DIRECTION OUTPUT ;
    USE SIGNAL ;
    PORT
      LAYER M4 ;
      RECT 0.00000 33.21600 0.03600 33.24000 ;
    END
  END ra_data[691]
  PIN ra_data[692]
    DIRECTION OUTPUT ;
    USE SIGNAL ;
    PORT
      LAYER M4 ;
      RECT 0.00000 33.26400 0.03600 33.28800 ;
    END
  END ra_data[692]
  PIN ra_data[693]
    DIRECTION OUTPUT ;
    USE SIGNAL ;
    PORT
      LAYER M4 ;
      RECT 0.00000 33.31200 0.03600 33.33600 ;
    END
  END ra_data[693]
  PIN ra_data[694]
    DIRECTION OUTPUT ;
    USE SIGNAL ;
    PORT
      LAYER M4 ;
      RECT 0.00000 33.36000 0.03600 33.38400 ;
    END
  END ra_data[694]
  PIN ra_data[695]
    DIRECTION OUTPUT ;
    USE SIGNAL ;
    PORT
      LAYER M4 ;
      RECT 0.00000 33.40800 0.03600 33.43200 ;
    END
  END ra_data[695]
  PIN ra_data[696]
    DIRECTION OUTPUT ;
    USE SIGNAL ;
    PORT
      LAYER M4 ;
      RECT 0.00000 33.45600 0.03600 33.48000 ;
    END
  END ra_data[696]
  PIN ra_data[697]
    DIRECTION OUTPUT ;
    USE SIGNAL ;
    PORT
      LAYER M4 ;
      RECT 0.00000 33.50400 0.03600 33.52800 ;
    END
  END ra_data[697]
  PIN ra_data[698]
    DIRECTION OUTPUT ;
    USE SIGNAL ;
    PORT
      LAYER M4 ;
      RECT 0.00000 33.55200 0.03600 33.57600 ;
    END
  END ra_data[698]
  PIN ra_data[699]
    DIRECTION OUTPUT ;
    USE SIGNAL ;
    PORT
      LAYER M4 ;
      RECT 0.00000 33.60000 0.03600 33.62400 ;
    END
  END ra_data[699]
  PIN ra_data[700]
    DIRECTION OUTPUT ;
    USE SIGNAL ;
    PORT
      LAYER M4 ;
      RECT 0.00000 33.64800 0.03600 33.67200 ;
    END
  END ra_data[700]
  PIN ra_data[701]
    DIRECTION OUTPUT ;
    USE SIGNAL ;
    PORT
      LAYER M4 ;
      RECT 0.00000 33.69600 0.03600 33.72000 ;
    END
  END ra_data[701]
  PIN ra_data[702]
    DIRECTION OUTPUT ;
    USE SIGNAL ;
    PORT
      LAYER M4 ;
      RECT 0.00000 33.74400 0.03600 33.76800 ;
    END
  END ra_data[702]
  PIN ra_data[703]
    DIRECTION OUTPUT ;
    USE SIGNAL ;
    PORT
      LAYER M4 ;
      RECT 0.00000 33.79200 0.03600 33.81600 ;
    END
  END ra_data[703]
  PIN ra_data[704]
    DIRECTION OUTPUT ;
    USE SIGNAL ;
    PORT
      LAYER M4 ;
      RECT 0.00000 33.84000 0.03600 33.86400 ;
    END
  END ra_data[704]
  PIN ra_data[705]
    DIRECTION OUTPUT ;
    USE SIGNAL ;
    PORT
      LAYER M4 ;
      RECT 0.00000 33.88800 0.03600 33.91200 ;
    END
  END ra_data[705]
  PIN ra_data[706]
    DIRECTION OUTPUT ;
    USE SIGNAL ;
    PORT
      LAYER M4 ;
      RECT 0.00000 33.93600 0.03600 33.96000 ;
    END
  END ra_data[706]
  PIN ra_data[707]
    DIRECTION OUTPUT ;
    USE SIGNAL ;
    PORT
      LAYER M4 ;
      RECT 0.00000 33.98400 0.03600 34.00800 ;
    END
  END ra_data[707]
  PIN ra_data[708]
    DIRECTION OUTPUT ;
    USE SIGNAL ;
    PORT
      LAYER M4 ;
      RECT 0.00000 34.03200 0.03600 34.05600 ;
    END
  END ra_data[708]
  PIN ra_data[709]
    DIRECTION OUTPUT ;
    USE SIGNAL ;
    PORT
      LAYER M4 ;
      RECT 0.00000 34.08000 0.03600 34.10400 ;
    END
  END ra_data[709]
  PIN ra_data[710]
    DIRECTION OUTPUT ;
    USE SIGNAL ;
    PORT
      LAYER M4 ;
      RECT 0.00000 34.12800 0.03600 34.15200 ;
    END
  END ra_data[710]
  PIN ra_data[711]
    DIRECTION OUTPUT ;
    USE SIGNAL ;
    PORT
      LAYER M4 ;
      RECT 0.00000 34.17600 0.03600 34.20000 ;
    END
  END ra_data[711]
  PIN ra_data[712]
    DIRECTION OUTPUT ;
    USE SIGNAL ;
    PORT
      LAYER M4 ;
      RECT 0.00000 34.22400 0.03600 34.24800 ;
    END
  END ra_data[712]
  PIN ra_data[713]
    DIRECTION OUTPUT ;
    USE SIGNAL ;
    PORT
      LAYER M4 ;
      RECT 0.00000 34.27200 0.03600 34.29600 ;
    END
  END ra_data[713]
  PIN ra_data[714]
    DIRECTION OUTPUT ;
    USE SIGNAL ;
    PORT
      LAYER M4 ;
      RECT 0.00000 34.32000 0.03600 34.34400 ;
    END
  END ra_data[714]
  PIN ra_data[715]
    DIRECTION OUTPUT ;
    USE SIGNAL ;
    PORT
      LAYER M4 ;
      RECT 0.00000 34.36800 0.03600 34.39200 ;
    END
  END ra_data[715]
  PIN ra_data[716]
    DIRECTION OUTPUT ;
    USE SIGNAL ;
    PORT
      LAYER M4 ;
      RECT 0.00000 34.41600 0.03600 34.44000 ;
    END
  END ra_data[716]
  PIN ra_data[717]
    DIRECTION OUTPUT ;
    USE SIGNAL ;
    PORT
      LAYER M4 ;
      RECT 0.00000 34.46400 0.03600 34.48800 ;
    END
  END ra_data[717]
  PIN ra_data[718]
    DIRECTION OUTPUT ;
    USE SIGNAL ;
    PORT
      LAYER M4 ;
      RECT 0.00000 34.51200 0.03600 34.53600 ;
    END
  END ra_data[718]
  PIN ra_data[719]
    DIRECTION OUTPUT ;
    USE SIGNAL ;
    PORT
      LAYER M4 ;
      RECT 0.00000 34.56000 0.03600 34.58400 ;
    END
  END ra_data[719]
  PIN ra_data[720]
    DIRECTION OUTPUT ;
    USE SIGNAL ;
    PORT
      LAYER M4 ;
      RECT 0.00000 34.60800 0.03600 34.63200 ;
    END
  END ra_data[720]
  PIN ra_data[721]
    DIRECTION OUTPUT ;
    USE SIGNAL ;
    PORT
      LAYER M4 ;
      RECT 0.00000 34.65600 0.03600 34.68000 ;
    END
  END ra_data[721]
  PIN ra_data[722]
    DIRECTION OUTPUT ;
    USE SIGNAL ;
    PORT
      LAYER M4 ;
      RECT 0.00000 34.70400 0.03600 34.72800 ;
    END
  END ra_data[722]
  PIN ra_data[723]
    DIRECTION OUTPUT ;
    USE SIGNAL ;
    PORT
      LAYER M4 ;
      RECT 0.00000 34.75200 0.03600 34.77600 ;
    END
  END ra_data[723]
  PIN ra_data[724]
    DIRECTION OUTPUT ;
    USE SIGNAL ;
    PORT
      LAYER M4 ;
      RECT 0.00000 34.80000 0.03600 34.82400 ;
    END
  END ra_data[724]
  PIN ra_data[725]
    DIRECTION OUTPUT ;
    USE SIGNAL ;
    PORT
      LAYER M4 ;
      RECT 0.00000 34.84800 0.03600 34.87200 ;
    END
  END ra_data[725]
  PIN ra_data[726]
    DIRECTION OUTPUT ;
    USE SIGNAL ;
    PORT
      LAYER M4 ;
      RECT 0.00000 34.89600 0.03600 34.92000 ;
    END
  END ra_data[726]
  PIN ra_data[727]
    DIRECTION OUTPUT ;
    USE SIGNAL ;
    PORT
      LAYER M4 ;
      RECT 0.00000 34.94400 0.03600 34.96800 ;
    END
  END ra_data[727]
  PIN ra_data[728]
    DIRECTION OUTPUT ;
    USE SIGNAL ;
    PORT
      LAYER M4 ;
      RECT 0.00000 34.99200 0.03600 35.01600 ;
    END
  END ra_data[728]
  PIN ra_data[729]
    DIRECTION OUTPUT ;
    USE SIGNAL ;
    PORT
      LAYER M4 ;
      RECT 0.00000 35.04000 0.03600 35.06400 ;
    END
  END ra_data[729]
  PIN ra_data[730]
    DIRECTION OUTPUT ;
    USE SIGNAL ;
    PORT
      LAYER M4 ;
      RECT 0.00000 35.08800 0.03600 35.11200 ;
    END
  END ra_data[730]
  PIN ra_data[731]
    DIRECTION OUTPUT ;
    USE SIGNAL ;
    PORT
      LAYER M4 ;
      RECT 0.00000 35.13600 0.03600 35.16000 ;
    END
  END ra_data[731]
  PIN ra_data[732]
    DIRECTION OUTPUT ;
    USE SIGNAL ;
    PORT
      LAYER M4 ;
      RECT 0.00000 35.18400 0.03600 35.20800 ;
    END
  END ra_data[732]
  PIN ra_data[733]
    DIRECTION OUTPUT ;
    USE SIGNAL ;
    PORT
      LAYER M4 ;
      RECT 0.00000 35.23200 0.03600 35.25600 ;
    END
  END ra_data[733]
  PIN ra_data[734]
    DIRECTION OUTPUT ;
    USE SIGNAL ;
    PORT
      LAYER M4 ;
      RECT 0.00000 35.28000 0.03600 35.30400 ;
    END
  END ra_data[734]
  PIN ra_data[735]
    DIRECTION OUTPUT ;
    USE SIGNAL ;
    PORT
      LAYER M4 ;
      RECT 0.00000 35.32800 0.03600 35.35200 ;
    END
  END ra_data[735]
  PIN ra_data[736]
    DIRECTION OUTPUT ;
    USE SIGNAL ;
    PORT
      LAYER M4 ;
      RECT 0.00000 35.37600 0.03600 35.40000 ;
    END
  END ra_data[736]
  PIN ra_data[737]
    DIRECTION OUTPUT ;
    USE SIGNAL ;
    PORT
      LAYER M4 ;
      RECT 0.00000 35.42400 0.03600 35.44800 ;
    END
  END ra_data[737]
  PIN ra_data[738]
    DIRECTION OUTPUT ;
    USE SIGNAL ;
    PORT
      LAYER M4 ;
      RECT 0.00000 35.47200 0.03600 35.49600 ;
    END
  END ra_data[738]
  PIN ra_data[739]
    DIRECTION OUTPUT ;
    USE SIGNAL ;
    PORT
      LAYER M4 ;
      RECT 0.00000 35.52000 0.03600 35.54400 ;
    END
  END ra_data[739]
  PIN ra_data[740]
    DIRECTION OUTPUT ;
    USE SIGNAL ;
    PORT
      LAYER M4 ;
      RECT 0.00000 35.56800 0.03600 35.59200 ;
    END
  END ra_data[740]
  PIN ra_data[741]
    DIRECTION OUTPUT ;
    USE SIGNAL ;
    PORT
      LAYER M4 ;
      RECT 0.00000 35.61600 0.03600 35.64000 ;
    END
  END ra_data[741]
  PIN ra_data[742]
    DIRECTION OUTPUT ;
    USE SIGNAL ;
    PORT
      LAYER M4 ;
      RECT 0.00000 35.66400 0.03600 35.68800 ;
    END
  END ra_data[742]
  PIN ra_data[743]
    DIRECTION OUTPUT ;
    USE SIGNAL ;
    PORT
      LAYER M4 ;
      RECT 0.00000 35.71200 0.03600 35.73600 ;
    END
  END ra_data[743]
  PIN ra_data[744]
    DIRECTION OUTPUT ;
    USE SIGNAL ;
    PORT
      LAYER M4 ;
      RECT 0.00000 35.76000 0.03600 35.78400 ;
    END
  END ra_data[744]
  PIN ra_data[745]
    DIRECTION OUTPUT ;
    USE SIGNAL ;
    PORT
      LAYER M4 ;
      RECT 0.00000 35.80800 0.03600 35.83200 ;
    END
  END ra_data[745]
  PIN ra_data[746]
    DIRECTION OUTPUT ;
    USE SIGNAL ;
    PORT
      LAYER M4 ;
      RECT 0.00000 35.85600 0.03600 35.88000 ;
    END
  END ra_data[746]
  PIN ra_data[747]
    DIRECTION OUTPUT ;
    USE SIGNAL ;
    PORT
      LAYER M4 ;
      RECT 0.00000 35.90400 0.03600 35.92800 ;
    END
  END ra_data[747]
  PIN ra_data[748]
    DIRECTION OUTPUT ;
    USE SIGNAL ;
    PORT
      LAYER M4 ;
      RECT 0.00000 35.95200 0.03600 35.97600 ;
    END
  END ra_data[748]
  PIN ra_data[749]
    DIRECTION OUTPUT ;
    USE SIGNAL ;
    PORT
      LAYER M4 ;
      RECT 0.00000 36.00000 0.03600 36.02400 ;
    END
  END ra_data[749]
  PIN ra_data[750]
    DIRECTION OUTPUT ;
    USE SIGNAL ;
    PORT
      LAYER M4 ;
      RECT 0.00000 36.04800 0.03600 36.07200 ;
    END
  END ra_data[750]
  PIN ra_data[751]
    DIRECTION OUTPUT ;
    USE SIGNAL ;
    PORT
      LAYER M4 ;
      RECT 0.00000 36.09600 0.03600 36.12000 ;
    END
  END ra_data[751]
  PIN ra_data[752]
    DIRECTION OUTPUT ;
    USE SIGNAL ;
    PORT
      LAYER M4 ;
      RECT 0.00000 36.14400 0.03600 36.16800 ;
    END
  END ra_data[752]
  PIN ra_data[753]
    DIRECTION OUTPUT ;
    USE SIGNAL ;
    PORT
      LAYER M4 ;
      RECT 0.00000 36.19200 0.03600 36.21600 ;
    END
  END ra_data[753]
  PIN ra_data[754]
    DIRECTION OUTPUT ;
    USE SIGNAL ;
    PORT
      LAYER M4 ;
      RECT 0.00000 36.24000 0.03600 36.26400 ;
    END
  END ra_data[754]
  PIN ra_data[755]
    DIRECTION OUTPUT ;
    USE SIGNAL ;
    PORT
      LAYER M4 ;
      RECT 0.00000 36.28800 0.03600 36.31200 ;
    END
  END ra_data[755]
  PIN ra_data[756]
    DIRECTION OUTPUT ;
    USE SIGNAL ;
    PORT
      LAYER M4 ;
      RECT 0.00000 36.33600 0.03600 36.36000 ;
    END
  END ra_data[756]
  PIN ra_data[757]
    DIRECTION OUTPUT ;
    USE SIGNAL ;
    PORT
      LAYER M4 ;
      RECT 0.00000 36.38400 0.03600 36.40800 ;
    END
  END ra_data[757]
  PIN ra_data[758]
    DIRECTION OUTPUT ;
    USE SIGNAL ;
    PORT
      LAYER M4 ;
      RECT 0.00000 36.43200 0.03600 36.45600 ;
    END
  END ra_data[758]
  PIN ra_data[759]
    DIRECTION OUTPUT ;
    USE SIGNAL ;
    PORT
      LAYER M4 ;
      RECT 0.00000 36.48000 0.03600 36.50400 ;
    END
  END ra_data[759]
  PIN ra_data[760]
    DIRECTION OUTPUT ;
    USE SIGNAL ;
    PORT
      LAYER M4 ;
      RECT 0.00000 36.52800 0.03600 36.55200 ;
    END
  END ra_data[760]
  PIN ra_data[761]
    DIRECTION OUTPUT ;
    USE SIGNAL ;
    PORT
      LAYER M4 ;
      RECT 0.00000 36.57600 0.03600 36.60000 ;
    END
  END ra_data[761]
  PIN ra_data[762]
    DIRECTION OUTPUT ;
    USE SIGNAL ;
    PORT
      LAYER M4 ;
      RECT 0.00000 36.62400 0.03600 36.64800 ;
    END
  END ra_data[762]
  PIN ra_data[763]
    DIRECTION OUTPUT ;
    USE SIGNAL ;
    PORT
      LAYER M4 ;
      RECT 0.00000 36.67200 0.03600 36.69600 ;
    END
  END ra_data[763]
  PIN ra_data[764]
    DIRECTION OUTPUT ;
    USE SIGNAL ;
    PORT
      LAYER M4 ;
      RECT 0.00000 36.72000 0.03600 36.74400 ;
    END
  END ra_data[764]
  PIN ra_data[765]
    DIRECTION OUTPUT ;
    USE SIGNAL ;
    PORT
      LAYER M4 ;
      RECT 0.00000 36.76800 0.03600 36.79200 ;
    END
  END ra_data[765]
  PIN ra_data[766]
    DIRECTION OUTPUT ;
    USE SIGNAL ;
    PORT
      LAYER M4 ;
      RECT 0.00000 36.81600 0.03600 36.84000 ;
    END
  END ra_data[766]
  PIN ra_data[767]
    DIRECTION OUTPUT ;
    USE SIGNAL ;
    PORT
      LAYER M4 ;
      RECT 0.00000 36.86400 0.03600 36.88800 ;
    END
  END ra_data[767]
  PIN ra_data[768]
    DIRECTION OUTPUT ;
    USE SIGNAL ;
    PORT
      LAYER M4 ;
      RECT 0.00000 36.91200 0.03600 36.93600 ;
    END
  END ra_data[768]
  PIN ra_data[769]
    DIRECTION OUTPUT ;
    USE SIGNAL ;
    PORT
      LAYER M4 ;
      RECT 0.00000 36.96000 0.03600 36.98400 ;
    END
  END ra_data[769]
  PIN ra_data[770]
    DIRECTION OUTPUT ;
    USE SIGNAL ;
    PORT
      LAYER M4 ;
      RECT 0.00000 37.00800 0.03600 37.03200 ;
    END
  END ra_data[770]
  PIN ra_data[771]
    DIRECTION OUTPUT ;
    USE SIGNAL ;
    PORT
      LAYER M4 ;
      RECT 0.00000 37.05600 0.03600 37.08000 ;
    END
  END ra_data[771]
  PIN ra_data[772]
    DIRECTION OUTPUT ;
    USE SIGNAL ;
    PORT
      LAYER M4 ;
      RECT 0.00000 37.10400 0.03600 37.12800 ;
    END
  END ra_data[772]
  PIN ra_data[773]
    DIRECTION OUTPUT ;
    USE SIGNAL ;
    PORT
      LAYER M4 ;
      RECT 0.00000 37.15200 0.03600 37.17600 ;
    END
  END ra_data[773]
  PIN ra_data[774]
    DIRECTION OUTPUT ;
    USE SIGNAL ;
    PORT
      LAYER M4 ;
      RECT 0.00000 37.20000 0.03600 37.22400 ;
    END
  END ra_data[774]
  PIN ra_data[775]
    DIRECTION OUTPUT ;
    USE SIGNAL ;
    PORT
      LAYER M4 ;
      RECT 0.00000 37.24800 0.03600 37.27200 ;
    END
  END ra_data[775]
  PIN ra_data[776]
    DIRECTION OUTPUT ;
    USE SIGNAL ;
    PORT
      LAYER M4 ;
      RECT 0.00000 37.29600 0.03600 37.32000 ;
    END
  END ra_data[776]
  PIN ra_data[777]
    DIRECTION OUTPUT ;
    USE SIGNAL ;
    PORT
      LAYER M4 ;
      RECT 0.00000 37.34400 0.03600 37.36800 ;
    END
  END ra_data[777]
  PIN ra_data[778]
    DIRECTION OUTPUT ;
    USE SIGNAL ;
    PORT
      LAYER M4 ;
      RECT 0.00000 37.39200 0.03600 37.41600 ;
    END
  END ra_data[778]
  PIN ra_data[779]
    DIRECTION OUTPUT ;
    USE SIGNAL ;
    PORT
      LAYER M4 ;
      RECT 0.00000 37.44000 0.03600 37.46400 ;
    END
  END ra_data[779]
  PIN ra_data[780]
    DIRECTION OUTPUT ;
    USE SIGNAL ;
    PORT
      LAYER M4 ;
      RECT 0.00000 37.48800 0.03600 37.51200 ;
    END
  END ra_data[780]
  PIN ra_data[781]
    DIRECTION OUTPUT ;
    USE SIGNAL ;
    PORT
      LAYER M4 ;
      RECT 0.00000 37.53600 0.03600 37.56000 ;
    END
  END ra_data[781]
  PIN ra_data[782]
    DIRECTION OUTPUT ;
    USE SIGNAL ;
    PORT
      LAYER M4 ;
      RECT 0.00000 37.58400 0.03600 37.60800 ;
    END
  END ra_data[782]
  PIN ra_data[783]
    DIRECTION OUTPUT ;
    USE SIGNAL ;
    PORT
      LAYER M4 ;
      RECT 0.00000 37.63200 0.03600 37.65600 ;
    END
  END ra_data[783]
  PIN ra_data[784]
    DIRECTION OUTPUT ;
    USE SIGNAL ;
    PORT
      LAYER M4 ;
      RECT 0.00000 37.68000 0.03600 37.70400 ;
    END
  END ra_data[784]
  PIN ra_data[785]
    DIRECTION OUTPUT ;
    USE SIGNAL ;
    PORT
      LAYER M4 ;
      RECT 0.00000 37.72800 0.03600 37.75200 ;
    END
  END ra_data[785]
  PIN ra_data[786]
    DIRECTION OUTPUT ;
    USE SIGNAL ;
    PORT
      LAYER M4 ;
      RECT 0.00000 37.77600 0.03600 37.80000 ;
    END
  END ra_data[786]
  PIN ra_data[787]
    DIRECTION OUTPUT ;
    USE SIGNAL ;
    PORT
      LAYER M4 ;
      RECT 0.00000 37.82400 0.03600 37.84800 ;
    END
  END ra_data[787]
  PIN ra_data[788]
    DIRECTION OUTPUT ;
    USE SIGNAL ;
    PORT
      LAYER M4 ;
      RECT 0.00000 37.87200 0.03600 37.89600 ;
    END
  END ra_data[788]
  PIN ra_data[789]
    DIRECTION OUTPUT ;
    USE SIGNAL ;
    PORT
      LAYER M4 ;
      RECT 0.00000 37.92000 0.03600 37.94400 ;
    END
  END ra_data[789]
  PIN ra_data[790]
    DIRECTION OUTPUT ;
    USE SIGNAL ;
    PORT
      LAYER M4 ;
      RECT 0.00000 37.96800 0.03600 37.99200 ;
    END
  END ra_data[790]
  PIN ra_data[791]
    DIRECTION OUTPUT ;
    USE SIGNAL ;
    PORT
      LAYER M4 ;
      RECT 0.00000 38.01600 0.03600 38.04000 ;
    END
  END ra_data[791]
  PIN ra_data[792]
    DIRECTION OUTPUT ;
    USE SIGNAL ;
    PORT
      LAYER M4 ;
      RECT 0.00000 38.06400 0.03600 38.08800 ;
    END
  END ra_data[792]
  PIN ra_data[793]
    DIRECTION OUTPUT ;
    USE SIGNAL ;
    PORT
      LAYER M4 ;
      RECT 0.00000 38.11200 0.03600 38.13600 ;
    END
  END ra_data[793]
  PIN ra_data[794]
    DIRECTION OUTPUT ;
    USE SIGNAL ;
    PORT
      LAYER M4 ;
      RECT 0.00000 38.16000 0.03600 38.18400 ;
    END
  END ra_data[794]
  PIN ra_data[795]
    DIRECTION OUTPUT ;
    USE SIGNAL ;
    PORT
      LAYER M4 ;
      RECT 0.00000 38.20800 0.03600 38.23200 ;
    END
  END ra_data[795]
  PIN ra_data[796]
    DIRECTION OUTPUT ;
    USE SIGNAL ;
    PORT
      LAYER M4 ;
      RECT 0.00000 38.25600 0.03600 38.28000 ;
    END
  END ra_data[796]
  PIN ra_data[797]
    DIRECTION OUTPUT ;
    USE SIGNAL ;
    PORT
      LAYER M4 ;
      RECT 0.00000 38.30400 0.03600 38.32800 ;
    END
  END ra_data[797]
  PIN ra_data[798]
    DIRECTION OUTPUT ;
    USE SIGNAL ;
    PORT
      LAYER M4 ;
      RECT 0.00000 38.35200 0.03600 38.37600 ;
    END
  END ra_data[798]
  PIN ra_data[799]
    DIRECTION OUTPUT ;
    USE SIGNAL ;
    PORT
      LAYER M4 ;
      RECT 0.00000 38.40000 0.03600 38.42400 ;
    END
  END ra_data[799]
  PIN ra_data[800]
    DIRECTION OUTPUT ;
    USE SIGNAL ;
    PORT
      LAYER M4 ;
      RECT 0.00000 38.44800 0.03600 38.47200 ;
    END
  END ra_data[800]
  PIN ra_data[801]
    DIRECTION OUTPUT ;
    USE SIGNAL ;
    PORT
      LAYER M4 ;
      RECT 0.00000 38.49600 0.03600 38.52000 ;
    END
  END ra_data[801]
  PIN ra_data[802]
    DIRECTION OUTPUT ;
    USE SIGNAL ;
    PORT
      LAYER M4 ;
      RECT 0.00000 38.54400 0.03600 38.56800 ;
    END
  END ra_data[802]
  PIN ra_data[803]
    DIRECTION OUTPUT ;
    USE SIGNAL ;
    PORT
      LAYER M4 ;
      RECT 0.00000 38.59200 0.03600 38.61600 ;
    END
  END ra_data[803]
  PIN ra_data[804]
    DIRECTION OUTPUT ;
    USE SIGNAL ;
    PORT
      LAYER M4 ;
      RECT 0.00000 38.64000 0.03600 38.66400 ;
    END
  END ra_data[804]
  PIN ra_data[805]
    DIRECTION OUTPUT ;
    USE SIGNAL ;
    PORT
      LAYER M4 ;
      RECT 0.00000 38.68800 0.03600 38.71200 ;
    END
  END ra_data[805]
  PIN ra_data[806]
    DIRECTION OUTPUT ;
    USE SIGNAL ;
    PORT
      LAYER M4 ;
      RECT 0.00000 38.73600 0.03600 38.76000 ;
    END
  END ra_data[806]
  PIN ra_data[807]
    DIRECTION OUTPUT ;
    USE SIGNAL ;
    PORT
      LAYER M4 ;
      RECT 0.00000 38.78400 0.03600 38.80800 ;
    END
  END ra_data[807]
  PIN ra_data[808]
    DIRECTION OUTPUT ;
    USE SIGNAL ;
    PORT
      LAYER M4 ;
      RECT 0.00000 38.83200 0.03600 38.85600 ;
    END
  END ra_data[808]
  PIN ra_data[809]
    DIRECTION OUTPUT ;
    USE SIGNAL ;
    PORT
      LAYER M4 ;
      RECT 0.00000 38.88000 0.03600 38.90400 ;
    END
  END ra_data[809]
  PIN ra_data[810]
    DIRECTION OUTPUT ;
    USE SIGNAL ;
    PORT
      LAYER M4 ;
      RECT 0.00000 38.92800 0.03600 38.95200 ;
    END
  END ra_data[810]
  PIN ra_data[811]
    DIRECTION OUTPUT ;
    USE SIGNAL ;
    PORT
      LAYER M4 ;
      RECT 0.00000 38.97600 0.03600 39.00000 ;
    END
  END ra_data[811]
  PIN ra_data[812]
    DIRECTION OUTPUT ;
    USE SIGNAL ;
    PORT
      LAYER M4 ;
      RECT 0.00000 39.02400 0.03600 39.04800 ;
    END
  END ra_data[812]
  PIN ra_data[813]
    DIRECTION OUTPUT ;
    USE SIGNAL ;
    PORT
      LAYER M4 ;
      RECT 0.00000 39.07200 0.03600 39.09600 ;
    END
  END ra_data[813]
  PIN ra_data[814]
    DIRECTION OUTPUT ;
    USE SIGNAL ;
    PORT
      LAYER M4 ;
      RECT 0.00000 39.12000 0.03600 39.14400 ;
    END
  END ra_data[814]
  PIN ra_data[815]
    DIRECTION OUTPUT ;
    USE SIGNAL ;
    PORT
      LAYER M4 ;
      RECT 0.00000 39.16800 0.03600 39.19200 ;
    END
  END ra_data[815]
  PIN ra_data[816]
    DIRECTION OUTPUT ;
    USE SIGNAL ;
    PORT
      LAYER M4 ;
      RECT 0.00000 39.21600 0.03600 39.24000 ;
    END
  END ra_data[816]
  PIN ra_data[817]
    DIRECTION OUTPUT ;
    USE SIGNAL ;
    PORT
      LAYER M4 ;
      RECT 0.00000 39.26400 0.03600 39.28800 ;
    END
  END ra_data[817]
  PIN ra_data[818]
    DIRECTION OUTPUT ;
    USE SIGNAL ;
    PORT
      LAYER M4 ;
      RECT 0.00000 39.31200 0.03600 39.33600 ;
    END
  END ra_data[818]
  PIN ra_data[819]
    DIRECTION OUTPUT ;
    USE SIGNAL ;
    PORT
      LAYER M4 ;
      RECT 0.00000 39.36000 0.03600 39.38400 ;
    END
  END ra_data[819]
  PIN ra_data[820]
    DIRECTION OUTPUT ;
    USE SIGNAL ;
    PORT
      LAYER M4 ;
      RECT 0.00000 39.40800 0.03600 39.43200 ;
    END
  END ra_data[820]
  PIN ra_data[821]
    DIRECTION OUTPUT ;
    USE SIGNAL ;
    PORT
      LAYER M4 ;
      RECT 0.00000 39.45600 0.03600 39.48000 ;
    END
  END ra_data[821]
  PIN ra_data[822]
    DIRECTION OUTPUT ;
    USE SIGNAL ;
    PORT
      LAYER M4 ;
      RECT 0.00000 39.50400 0.03600 39.52800 ;
    END
  END ra_data[822]
  PIN ra_data[823]
    DIRECTION OUTPUT ;
    USE SIGNAL ;
    PORT
      LAYER M4 ;
      RECT 0.00000 39.55200 0.03600 39.57600 ;
    END
  END ra_data[823]
  PIN ra_data[824]
    DIRECTION OUTPUT ;
    USE SIGNAL ;
    PORT
      LAYER M4 ;
      RECT 0.00000 39.60000 0.03600 39.62400 ;
    END
  END ra_data[824]
  PIN ra_data[825]
    DIRECTION OUTPUT ;
    USE SIGNAL ;
    PORT
      LAYER M4 ;
      RECT 0.00000 39.64800 0.03600 39.67200 ;
    END
  END ra_data[825]
  PIN ra_data[826]
    DIRECTION OUTPUT ;
    USE SIGNAL ;
    PORT
      LAYER M4 ;
      RECT 0.00000 39.69600 0.03600 39.72000 ;
    END
  END ra_data[826]
  PIN ra_data[827]
    DIRECTION OUTPUT ;
    USE SIGNAL ;
    PORT
      LAYER M4 ;
      RECT 0.00000 39.74400 0.03600 39.76800 ;
    END
  END ra_data[827]
  PIN ra_data[828]
    DIRECTION OUTPUT ;
    USE SIGNAL ;
    PORT
      LAYER M4 ;
      RECT 0.00000 39.79200 0.03600 39.81600 ;
    END
  END ra_data[828]
  PIN ra_data[829]
    DIRECTION OUTPUT ;
    USE SIGNAL ;
    PORT
      LAYER M4 ;
      RECT 0.00000 39.84000 0.03600 39.86400 ;
    END
  END ra_data[829]
  PIN ra_data[830]
    DIRECTION OUTPUT ;
    USE SIGNAL ;
    PORT
      LAYER M4 ;
      RECT 0.00000 39.88800 0.03600 39.91200 ;
    END
  END ra_data[830]
  PIN ra_data[831]
    DIRECTION OUTPUT ;
    USE SIGNAL ;
    PORT
      LAYER M4 ;
      RECT 0.00000 39.93600 0.03600 39.96000 ;
    END
  END ra_data[831]
  PIN ra_data[832]
    DIRECTION OUTPUT ;
    USE SIGNAL ;
    PORT
      LAYER M4 ;
      RECT 0.00000 39.98400 0.03600 40.00800 ;
    END
  END ra_data[832]
  PIN ra_data[833]
    DIRECTION OUTPUT ;
    USE SIGNAL ;
    PORT
      LAYER M4 ;
      RECT 0.00000 40.03200 0.03600 40.05600 ;
    END
  END ra_data[833]
  PIN ra_data[834]
    DIRECTION OUTPUT ;
    USE SIGNAL ;
    PORT
      LAYER M4 ;
      RECT 0.00000 40.08000 0.03600 40.10400 ;
    END
  END ra_data[834]
  PIN ra_data[835]
    DIRECTION OUTPUT ;
    USE SIGNAL ;
    PORT
      LAYER M4 ;
      RECT 0.00000 40.12800 0.03600 40.15200 ;
    END
  END ra_data[835]
  PIN ra_data[836]
    DIRECTION OUTPUT ;
    USE SIGNAL ;
    PORT
      LAYER M4 ;
      RECT 0.00000 40.17600 0.03600 40.20000 ;
    END
  END ra_data[836]
  PIN ra_data[837]
    DIRECTION OUTPUT ;
    USE SIGNAL ;
    PORT
      LAYER M4 ;
      RECT 0.00000 40.22400 0.03600 40.24800 ;
    END
  END ra_data[837]
  PIN ra_data[838]
    DIRECTION OUTPUT ;
    USE SIGNAL ;
    PORT
      LAYER M4 ;
      RECT 0.00000 40.27200 0.03600 40.29600 ;
    END
  END ra_data[838]
  PIN ra_data[839]
    DIRECTION OUTPUT ;
    USE SIGNAL ;
    PORT
      LAYER M4 ;
      RECT 0.00000 40.32000 0.03600 40.34400 ;
    END
  END ra_data[839]
  PIN ra_data[840]
    DIRECTION OUTPUT ;
    USE SIGNAL ;
    PORT
      LAYER M4 ;
      RECT 0.00000 40.36800 0.03600 40.39200 ;
    END
  END ra_data[840]
  PIN ra_data[841]
    DIRECTION OUTPUT ;
    USE SIGNAL ;
    PORT
      LAYER M4 ;
      RECT 0.00000 40.41600 0.03600 40.44000 ;
    END
  END ra_data[841]
  PIN ra_data[842]
    DIRECTION OUTPUT ;
    USE SIGNAL ;
    PORT
      LAYER M4 ;
      RECT 0.00000 40.46400 0.03600 40.48800 ;
    END
  END ra_data[842]
  PIN ra_data[843]
    DIRECTION OUTPUT ;
    USE SIGNAL ;
    PORT
      LAYER M4 ;
      RECT 0.00000 40.51200 0.03600 40.53600 ;
    END
  END ra_data[843]
  PIN ra_data[844]
    DIRECTION OUTPUT ;
    USE SIGNAL ;
    PORT
      LAYER M4 ;
      RECT 0.00000 40.56000 0.03600 40.58400 ;
    END
  END ra_data[844]
  PIN ra_data[845]
    DIRECTION OUTPUT ;
    USE SIGNAL ;
    PORT
      LAYER M4 ;
      RECT 0.00000 40.60800 0.03600 40.63200 ;
    END
  END ra_data[845]
  PIN ra_data[846]
    DIRECTION OUTPUT ;
    USE SIGNAL ;
    PORT
      LAYER M4 ;
      RECT 0.00000 40.65600 0.03600 40.68000 ;
    END
  END ra_data[846]
  PIN ra_data[847]
    DIRECTION OUTPUT ;
    USE SIGNAL ;
    PORT
      LAYER M4 ;
      RECT 0.00000 40.70400 0.03600 40.72800 ;
    END
  END ra_data[847]
  PIN ra_data[848]
    DIRECTION OUTPUT ;
    USE SIGNAL ;
    PORT
      LAYER M4 ;
      RECT 0.00000 40.75200 0.03600 40.77600 ;
    END
  END ra_data[848]
  PIN ra_data[849]
    DIRECTION OUTPUT ;
    USE SIGNAL ;
    PORT
      LAYER M4 ;
      RECT 0.00000 40.80000 0.03600 40.82400 ;
    END
  END ra_data[849]
  PIN ra_data[850]
    DIRECTION OUTPUT ;
    USE SIGNAL ;
    PORT
      LAYER M4 ;
      RECT 0.00000 40.84800 0.03600 40.87200 ;
    END
  END ra_data[850]
  PIN ra_data[851]
    DIRECTION OUTPUT ;
    USE SIGNAL ;
    PORT
      LAYER M4 ;
      RECT 0.00000 40.89600 0.03600 40.92000 ;
    END
  END ra_data[851]
  PIN ra_data[852]
    DIRECTION OUTPUT ;
    USE SIGNAL ;
    PORT
      LAYER M4 ;
      RECT 0.00000 40.94400 0.03600 40.96800 ;
    END
  END ra_data[852]
  PIN ra_data[853]
    DIRECTION OUTPUT ;
    USE SIGNAL ;
    PORT
      LAYER M4 ;
      RECT 0.00000 40.99200 0.03600 41.01600 ;
    END
  END ra_data[853]
  PIN ra_data[854]
    DIRECTION OUTPUT ;
    USE SIGNAL ;
    PORT
      LAYER M4 ;
      RECT 0.00000 41.04000 0.03600 41.06400 ;
    END
  END ra_data[854]
  PIN ra_data[855]
    DIRECTION OUTPUT ;
    USE SIGNAL ;
    PORT
      LAYER M4 ;
      RECT 0.00000 41.08800 0.03600 41.11200 ;
    END
  END ra_data[855]
  PIN ra_data[856]
    DIRECTION OUTPUT ;
    USE SIGNAL ;
    PORT
      LAYER M4 ;
      RECT 0.00000 41.13600 0.03600 41.16000 ;
    END
  END ra_data[856]
  PIN ra_data[857]
    DIRECTION OUTPUT ;
    USE SIGNAL ;
    PORT
      LAYER M4 ;
      RECT 0.00000 41.18400 0.03600 41.20800 ;
    END
  END ra_data[857]
  PIN ra_data[858]
    DIRECTION OUTPUT ;
    USE SIGNAL ;
    PORT
      LAYER M4 ;
      RECT 0.00000 41.23200 0.03600 41.25600 ;
    END
  END ra_data[858]
  PIN ra_data[859]
    DIRECTION OUTPUT ;
    USE SIGNAL ;
    PORT
      LAYER M4 ;
      RECT 0.00000 41.28000 0.03600 41.30400 ;
    END
  END ra_data[859]
  PIN ra_data[860]
    DIRECTION OUTPUT ;
    USE SIGNAL ;
    PORT
      LAYER M4 ;
      RECT 0.00000 41.32800 0.03600 41.35200 ;
    END
  END ra_data[860]
  PIN ra_data[861]
    DIRECTION OUTPUT ;
    USE SIGNAL ;
    PORT
      LAYER M4 ;
      RECT 0.00000 41.37600 0.03600 41.40000 ;
    END
  END ra_data[861]
  PIN ra_data[862]
    DIRECTION OUTPUT ;
    USE SIGNAL ;
    PORT
      LAYER M4 ;
      RECT 0.00000 41.42400 0.03600 41.44800 ;
    END
  END ra_data[862]
  PIN ra_data[863]
    DIRECTION OUTPUT ;
    USE SIGNAL ;
    PORT
      LAYER M4 ;
      RECT 0.00000 41.47200 0.03600 41.49600 ;
    END
  END ra_data[863]
  PIN ra_data[864]
    DIRECTION OUTPUT ;
    USE SIGNAL ;
    PORT
      LAYER M4 ;
      RECT 0.00000 41.52000 0.03600 41.54400 ;
    END
  END ra_data[864]
  PIN ra_data[865]
    DIRECTION OUTPUT ;
    USE SIGNAL ;
    PORT
      LAYER M4 ;
      RECT 0.00000 41.56800 0.03600 41.59200 ;
    END
  END ra_data[865]
  PIN ra_data[866]
    DIRECTION OUTPUT ;
    USE SIGNAL ;
    PORT
      LAYER M4 ;
      RECT 0.00000 41.61600 0.03600 41.64000 ;
    END
  END ra_data[866]
  PIN ra_data[867]
    DIRECTION OUTPUT ;
    USE SIGNAL ;
    PORT
      LAYER M4 ;
      RECT 0.00000 41.66400 0.03600 41.68800 ;
    END
  END ra_data[867]
  PIN ra_data[868]
    DIRECTION OUTPUT ;
    USE SIGNAL ;
    PORT
      LAYER M4 ;
      RECT 0.00000 41.71200 0.03600 41.73600 ;
    END
  END ra_data[868]
  PIN ra_data[869]
    DIRECTION OUTPUT ;
    USE SIGNAL ;
    PORT
      LAYER M4 ;
      RECT 0.00000 41.76000 0.03600 41.78400 ;
    END
  END ra_data[869]
  PIN ra_data[870]
    DIRECTION OUTPUT ;
    USE SIGNAL ;
    PORT
      LAYER M4 ;
      RECT 0.00000 41.80800 0.03600 41.83200 ;
    END
  END ra_data[870]
  PIN ra_data[871]
    DIRECTION OUTPUT ;
    USE SIGNAL ;
    PORT
      LAYER M4 ;
      RECT 0.00000 41.85600 0.03600 41.88000 ;
    END
  END ra_data[871]
  PIN ra_data[872]
    DIRECTION OUTPUT ;
    USE SIGNAL ;
    PORT
      LAYER M4 ;
      RECT 0.00000 41.90400 0.03600 41.92800 ;
    END
  END ra_data[872]
  PIN ra_data[873]
    DIRECTION OUTPUT ;
    USE SIGNAL ;
    PORT
      LAYER M4 ;
      RECT 0.00000 41.95200 0.03600 41.97600 ;
    END
  END ra_data[873]
  PIN ra_data[874]
    DIRECTION OUTPUT ;
    USE SIGNAL ;
    PORT
      LAYER M4 ;
      RECT 0.00000 42.00000 0.03600 42.02400 ;
    END
  END ra_data[874]
  PIN ra_data[875]
    DIRECTION OUTPUT ;
    USE SIGNAL ;
    PORT
      LAYER M4 ;
      RECT 0.00000 42.04800 0.03600 42.07200 ;
    END
  END ra_data[875]
  PIN ra_data[876]
    DIRECTION OUTPUT ;
    USE SIGNAL ;
    PORT
      LAYER M4 ;
      RECT 0.00000 42.09600 0.03600 42.12000 ;
    END
  END ra_data[876]
  PIN ra_data[877]
    DIRECTION OUTPUT ;
    USE SIGNAL ;
    PORT
      LAYER M4 ;
      RECT 0.00000 42.14400 0.03600 42.16800 ;
    END
  END ra_data[877]
  PIN ra_data[878]
    DIRECTION OUTPUT ;
    USE SIGNAL ;
    PORT
      LAYER M4 ;
      RECT 0.00000 42.19200 0.03600 42.21600 ;
    END
  END ra_data[878]
  PIN ra_data[879]
    DIRECTION OUTPUT ;
    USE SIGNAL ;
    PORT
      LAYER M4 ;
      RECT 0.00000 42.24000 0.03600 42.26400 ;
    END
  END ra_data[879]
  PIN ra_data[880]
    DIRECTION OUTPUT ;
    USE SIGNAL ;
    PORT
      LAYER M4 ;
      RECT 0.00000 42.28800 0.03600 42.31200 ;
    END
  END ra_data[880]
  PIN ra_data[881]
    DIRECTION OUTPUT ;
    USE SIGNAL ;
    PORT
      LAYER M4 ;
      RECT 0.00000 42.33600 0.03600 42.36000 ;
    END
  END ra_data[881]
  PIN ra_data[882]
    DIRECTION OUTPUT ;
    USE SIGNAL ;
    PORT
      LAYER M4 ;
      RECT 0.00000 42.38400 0.03600 42.40800 ;
    END
  END ra_data[882]
  PIN ra_data[883]
    DIRECTION OUTPUT ;
    USE SIGNAL ;
    PORT
      LAYER M4 ;
      RECT 0.00000 42.43200 0.03600 42.45600 ;
    END
  END ra_data[883]
  PIN ra_data[884]
    DIRECTION OUTPUT ;
    USE SIGNAL ;
    PORT
      LAYER M4 ;
      RECT 0.00000 42.48000 0.03600 42.50400 ;
    END
  END ra_data[884]
  PIN ra_data[885]
    DIRECTION OUTPUT ;
    USE SIGNAL ;
    PORT
      LAYER M4 ;
      RECT 0.00000 42.52800 0.03600 42.55200 ;
    END
  END ra_data[885]
  PIN ra_data[886]
    DIRECTION OUTPUT ;
    USE SIGNAL ;
    PORT
      LAYER M4 ;
      RECT 0.00000 42.57600 0.03600 42.60000 ;
    END
  END ra_data[886]
  PIN ra_data[887]
    DIRECTION OUTPUT ;
    USE SIGNAL ;
    PORT
      LAYER M4 ;
      RECT 0.00000 42.62400 0.03600 42.64800 ;
    END
  END ra_data[887]
  PIN ra_data[888]
    DIRECTION OUTPUT ;
    USE SIGNAL ;
    PORT
      LAYER M4 ;
      RECT 0.00000 42.67200 0.03600 42.69600 ;
    END
  END ra_data[888]
  PIN ra_data[889]
    DIRECTION OUTPUT ;
    USE SIGNAL ;
    PORT
      LAYER M4 ;
      RECT 0.00000 42.72000 0.03600 42.74400 ;
    END
  END ra_data[889]
  PIN ra_data[890]
    DIRECTION OUTPUT ;
    USE SIGNAL ;
    PORT
      LAYER M4 ;
      RECT 0.00000 42.76800 0.03600 42.79200 ;
    END
  END ra_data[890]
  PIN ra_data[891]
    DIRECTION OUTPUT ;
    USE SIGNAL ;
    PORT
      LAYER M4 ;
      RECT 0.00000 42.81600 0.03600 42.84000 ;
    END
  END ra_data[891]
  PIN ra_data[892]
    DIRECTION OUTPUT ;
    USE SIGNAL ;
    PORT
      LAYER M4 ;
      RECT 0.00000 42.86400 0.03600 42.88800 ;
    END
  END ra_data[892]
  PIN ra_data[893]
    DIRECTION OUTPUT ;
    USE SIGNAL ;
    PORT
      LAYER M4 ;
      RECT 0.00000 42.91200 0.03600 42.93600 ;
    END
  END ra_data[893]
  PIN ra_data[894]
    DIRECTION OUTPUT ;
    USE SIGNAL ;
    PORT
      LAYER M4 ;
      RECT 0.00000 42.96000 0.03600 42.98400 ;
    END
  END ra_data[894]
  PIN ra_data[895]
    DIRECTION OUTPUT ;
    USE SIGNAL ;
    PORT
      LAYER M4 ;
      RECT 0.00000 43.00800 0.03600 43.03200 ;
    END
  END ra_data[895]
  PIN ra_data[896]
    DIRECTION OUTPUT ;
    USE SIGNAL ;
    PORT
      LAYER M4 ;
      RECT 0.00000 43.05600 0.03600 43.08000 ;
    END
  END ra_data[896]
  PIN ra_data[897]
    DIRECTION OUTPUT ;
    USE SIGNAL ;
    PORT
      LAYER M4 ;
      RECT 0.00000 43.10400 0.03600 43.12800 ;
    END
  END ra_data[897]
  PIN ra_data[898]
    DIRECTION OUTPUT ;
    USE SIGNAL ;
    PORT
      LAYER M4 ;
      RECT 0.00000 43.15200 0.03600 43.17600 ;
    END
  END ra_data[898]
  PIN ra_data[899]
    DIRECTION OUTPUT ;
    USE SIGNAL ;
    PORT
      LAYER M4 ;
      RECT 0.00000 43.20000 0.03600 43.22400 ;
    END
  END ra_data[899]
  PIN ra_data[900]
    DIRECTION OUTPUT ;
    USE SIGNAL ;
    PORT
      LAYER M4 ;
      RECT 0.00000 43.24800 0.03600 43.27200 ;
    END
  END ra_data[900]
  PIN ra_data[901]
    DIRECTION OUTPUT ;
    USE SIGNAL ;
    PORT
      LAYER M4 ;
      RECT 0.00000 43.29600 0.03600 43.32000 ;
    END
  END ra_data[901]
  PIN ra_data[902]
    DIRECTION OUTPUT ;
    USE SIGNAL ;
    PORT
      LAYER M4 ;
      RECT 0.00000 43.34400 0.03600 43.36800 ;
    END
  END ra_data[902]
  PIN ra_data[903]
    DIRECTION OUTPUT ;
    USE SIGNAL ;
    PORT
      LAYER M4 ;
      RECT 0.00000 43.39200 0.03600 43.41600 ;
    END
  END ra_data[903]
  PIN ra_data[904]
    DIRECTION OUTPUT ;
    USE SIGNAL ;
    PORT
      LAYER M4 ;
      RECT 0.00000 43.44000 0.03600 43.46400 ;
    END
  END ra_data[904]
  PIN ra_data[905]
    DIRECTION OUTPUT ;
    USE SIGNAL ;
    PORT
      LAYER M4 ;
      RECT 0.00000 43.48800 0.03600 43.51200 ;
    END
  END ra_data[905]
  PIN ra_data[906]
    DIRECTION OUTPUT ;
    USE SIGNAL ;
    PORT
      LAYER M4 ;
      RECT 0.00000 43.53600 0.03600 43.56000 ;
    END
  END ra_data[906]
  PIN ra_data[907]
    DIRECTION OUTPUT ;
    USE SIGNAL ;
    PORT
      LAYER M4 ;
      RECT 0.00000 43.58400 0.03600 43.60800 ;
    END
  END ra_data[907]
  PIN ra_data[908]
    DIRECTION OUTPUT ;
    USE SIGNAL ;
    PORT
      LAYER M4 ;
      RECT 0.00000 43.63200 0.03600 43.65600 ;
    END
  END ra_data[908]
  PIN ra_data[909]
    DIRECTION OUTPUT ;
    USE SIGNAL ;
    PORT
      LAYER M4 ;
      RECT 0.00000 43.68000 0.03600 43.70400 ;
    END
  END ra_data[909]
  PIN ra_data[910]
    DIRECTION OUTPUT ;
    USE SIGNAL ;
    PORT
      LAYER M4 ;
      RECT 0.00000 43.72800 0.03600 43.75200 ;
    END
  END ra_data[910]
  PIN ra_data[911]
    DIRECTION OUTPUT ;
    USE SIGNAL ;
    PORT
      LAYER M4 ;
      RECT 0.00000 43.77600 0.03600 43.80000 ;
    END
  END ra_data[911]
  PIN ra_data[912]
    DIRECTION OUTPUT ;
    USE SIGNAL ;
    PORT
      LAYER M4 ;
      RECT 0.00000 43.82400 0.03600 43.84800 ;
    END
  END ra_data[912]
  PIN ra_data[913]
    DIRECTION OUTPUT ;
    USE SIGNAL ;
    PORT
      LAYER M4 ;
      RECT 0.00000 43.87200 0.03600 43.89600 ;
    END
  END ra_data[913]
  PIN ra_data[914]
    DIRECTION OUTPUT ;
    USE SIGNAL ;
    PORT
      LAYER M4 ;
      RECT 0.00000 43.92000 0.03600 43.94400 ;
    END
  END ra_data[914]
  PIN ra_data[915]
    DIRECTION OUTPUT ;
    USE SIGNAL ;
    PORT
      LAYER M4 ;
      RECT 0.00000 43.96800 0.03600 43.99200 ;
    END
  END ra_data[915]
  PIN ra_data[916]
    DIRECTION OUTPUT ;
    USE SIGNAL ;
    PORT
      LAYER M4 ;
      RECT 0.00000 44.01600 0.03600 44.04000 ;
    END
  END ra_data[916]
  PIN ra_data[917]
    DIRECTION OUTPUT ;
    USE SIGNAL ;
    PORT
      LAYER M4 ;
      RECT 0.00000 44.06400 0.03600 44.08800 ;
    END
  END ra_data[917]
  PIN ra_data[918]
    DIRECTION OUTPUT ;
    USE SIGNAL ;
    PORT
      LAYER M4 ;
      RECT 0.00000 44.11200 0.03600 44.13600 ;
    END
  END ra_data[918]
  PIN ra_data[919]
    DIRECTION OUTPUT ;
    USE SIGNAL ;
    PORT
      LAYER M4 ;
      RECT 0.00000 44.16000 0.03600 44.18400 ;
    END
  END ra_data[919]
  PIN ra_data[920]
    DIRECTION OUTPUT ;
    USE SIGNAL ;
    PORT
      LAYER M4 ;
      RECT 0.00000 44.20800 0.03600 44.23200 ;
    END
  END ra_data[920]
  PIN ra_data[921]
    DIRECTION OUTPUT ;
    USE SIGNAL ;
    PORT
      LAYER M4 ;
      RECT 0.00000 44.25600 0.03600 44.28000 ;
    END
  END ra_data[921]
  PIN ra_data[922]
    DIRECTION OUTPUT ;
    USE SIGNAL ;
    PORT
      LAYER M4 ;
      RECT 0.00000 44.30400 0.03600 44.32800 ;
    END
  END ra_data[922]
  PIN ra_data[923]
    DIRECTION OUTPUT ;
    USE SIGNAL ;
    PORT
      LAYER M4 ;
      RECT 0.00000 44.35200 0.03600 44.37600 ;
    END
  END ra_data[923]
  PIN ra_data[924]
    DIRECTION OUTPUT ;
    USE SIGNAL ;
    PORT
      LAYER M4 ;
      RECT 0.00000 44.40000 0.03600 44.42400 ;
    END
  END ra_data[924]
  PIN ra_data[925]
    DIRECTION OUTPUT ;
    USE SIGNAL ;
    PORT
      LAYER M4 ;
      RECT 0.00000 44.44800 0.03600 44.47200 ;
    END
  END ra_data[925]
  PIN ra_data[926]
    DIRECTION OUTPUT ;
    USE SIGNAL ;
    PORT
      LAYER M4 ;
      RECT 0.00000 44.49600 0.03600 44.52000 ;
    END
  END ra_data[926]
  PIN ra_data[927]
    DIRECTION OUTPUT ;
    USE SIGNAL ;
    PORT
      LAYER M4 ;
      RECT 0.00000 44.54400 0.03600 44.56800 ;
    END
  END ra_data[927]
  PIN ra_data[928]
    DIRECTION OUTPUT ;
    USE SIGNAL ;
    PORT
      LAYER M4 ;
      RECT 0.00000 44.59200 0.03600 44.61600 ;
    END
  END ra_data[928]
  PIN ra_data[929]
    DIRECTION OUTPUT ;
    USE SIGNAL ;
    PORT
      LAYER M4 ;
      RECT 0.00000 44.64000 0.03600 44.66400 ;
    END
  END ra_data[929]
  PIN ra_data[930]
    DIRECTION OUTPUT ;
    USE SIGNAL ;
    PORT
      LAYER M4 ;
      RECT 0.00000 44.68800 0.03600 44.71200 ;
    END
  END ra_data[930]
  PIN ra_data[931]
    DIRECTION OUTPUT ;
    USE SIGNAL ;
    PORT
      LAYER M4 ;
      RECT 0.00000 44.73600 0.03600 44.76000 ;
    END
  END ra_data[931]
  PIN ra_data[932]
    DIRECTION OUTPUT ;
    USE SIGNAL ;
    PORT
      LAYER M4 ;
      RECT 0.00000 44.78400 0.03600 44.80800 ;
    END
  END ra_data[932]
  PIN ra_data[933]
    DIRECTION OUTPUT ;
    USE SIGNAL ;
    PORT
      LAYER M4 ;
      RECT 0.00000 44.83200 0.03600 44.85600 ;
    END
  END ra_data[933]
  PIN ra_data[934]
    DIRECTION OUTPUT ;
    USE SIGNAL ;
    PORT
      LAYER M4 ;
      RECT 0.00000 44.88000 0.03600 44.90400 ;
    END
  END ra_data[934]
  PIN ra_data[935]
    DIRECTION OUTPUT ;
    USE SIGNAL ;
    PORT
      LAYER M4 ;
      RECT 0.00000 44.92800 0.03600 44.95200 ;
    END
  END ra_data[935]
  PIN ra_data[936]
    DIRECTION OUTPUT ;
    USE SIGNAL ;
    PORT
      LAYER M4 ;
      RECT 0.00000 44.97600 0.03600 45.00000 ;
    END
  END ra_data[936]
  PIN ra_data[937]
    DIRECTION OUTPUT ;
    USE SIGNAL ;
    PORT
      LAYER M4 ;
      RECT 0.00000 45.02400 0.03600 45.04800 ;
    END
  END ra_data[937]
  PIN ra_data[938]
    DIRECTION OUTPUT ;
    USE SIGNAL ;
    PORT
      LAYER M4 ;
      RECT 0.00000 45.07200 0.03600 45.09600 ;
    END
  END ra_data[938]
  PIN ra_data[939]
    DIRECTION OUTPUT ;
    USE SIGNAL ;
    PORT
      LAYER M4 ;
      RECT 0.00000 45.12000 0.03600 45.14400 ;
    END
  END ra_data[939]
  PIN ra_data[940]
    DIRECTION OUTPUT ;
    USE SIGNAL ;
    PORT
      LAYER M4 ;
      RECT 0.00000 45.16800 0.03600 45.19200 ;
    END
  END ra_data[940]
  PIN ra_data[941]
    DIRECTION OUTPUT ;
    USE SIGNAL ;
    PORT
      LAYER M4 ;
      RECT 0.00000 45.21600 0.03600 45.24000 ;
    END
  END ra_data[941]
  PIN ra_data[942]
    DIRECTION OUTPUT ;
    USE SIGNAL ;
    PORT
      LAYER M4 ;
      RECT 0.00000 45.26400 0.03600 45.28800 ;
    END
  END ra_data[942]
  PIN ra_data[943]
    DIRECTION OUTPUT ;
    USE SIGNAL ;
    PORT
      LAYER M4 ;
      RECT 0.00000 45.31200 0.03600 45.33600 ;
    END
  END ra_data[943]
  PIN ra_data[944]
    DIRECTION OUTPUT ;
    USE SIGNAL ;
    PORT
      LAYER M4 ;
      RECT 0.00000 45.36000 0.03600 45.38400 ;
    END
  END ra_data[944]
  PIN ra_data[945]
    DIRECTION OUTPUT ;
    USE SIGNAL ;
    PORT
      LAYER M4 ;
      RECT 0.00000 45.40800 0.03600 45.43200 ;
    END
  END ra_data[945]
  PIN ra_data[946]
    DIRECTION OUTPUT ;
    USE SIGNAL ;
    PORT
      LAYER M4 ;
      RECT 0.00000 45.45600 0.03600 45.48000 ;
    END
  END ra_data[946]
  PIN ra_data[947]
    DIRECTION OUTPUT ;
    USE SIGNAL ;
    PORT
      LAYER M4 ;
      RECT 0.00000 45.50400 0.03600 45.52800 ;
    END
  END ra_data[947]
  PIN ra_data[948]
    DIRECTION OUTPUT ;
    USE SIGNAL ;
    PORT
      LAYER M4 ;
      RECT 0.00000 45.55200 0.03600 45.57600 ;
    END
  END ra_data[948]
  PIN ra_data[949]
    DIRECTION OUTPUT ;
    USE SIGNAL ;
    PORT
      LAYER M4 ;
      RECT 0.00000 45.60000 0.03600 45.62400 ;
    END
  END ra_data[949]
  PIN ra_data[950]
    DIRECTION OUTPUT ;
    USE SIGNAL ;
    PORT
      LAYER M4 ;
      RECT 0.00000 45.64800 0.03600 45.67200 ;
    END
  END ra_data[950]
  PIN ra_data[951]
    DIRECTION OUTPUT ;
    USE SIGNAL ;
    PORT
      LAYER M4 ;
      RECT 0.00000 45.69600 0.03600 45.72000 ;
    END
  END ra_data[951]
  PIN ra_data[952]
    DIRECTION OUTPUT ;
    USE SIGNAL ;
    PORT
      LAYER M4 ;
      RECT 0.00000 45.74400 0.03600 45.76800 ;
    END
  END ra_data[952]
  PIN ra_data[953]
    DIRECTION OUTPUT ;
    USE SIGNAL ;
    PORT
      LAYER M4 ;
      RECT 0.00000 45.79200 0.03600 45.81600 ;
    END
  END ra_data[953]
  PIN ra_data[954]
    DIRECTION OUTPUT ;
    USE SIGNAL ;
    PORT
      LAYER M4 ;
      RECT 0.00000 45.84000 0.03600 45.86400 ;
    END
  END ra_data[954]
  PIN ra_data[955]
    DIRECTION OUTPUT ;
    USE SIGNAL ;
    PORT
      LAYER M4 ;
      RECT 0.00000 45.88800 0.03600 45.91200 ;
    END
  END ra_data[955]
  PIN ra_data[956]
    DIRECTION OUTPUT ;
    USE SIGNAL ;
    PORT
      LAYER M4 ;
      RECT 0.00000 45.93600 0.03600 45.96000 ;
    END
  END ra_data[956]
  PIN ra_data[957]
    DIRECTION OUTPUT ;
    USE SIGNAL ;
    PORT
      LAYER M4 ;
      RECT 0.00000 45.98400 0.03600 46.00800 ;
    END
  END ra_data[957]
  PIN ra_data[958]
    DIRECTION OUTPUT ;
    USE SIGNAL ;
    PORT
      LAYER M4 ;
      RECT 0.00000 46.03200 0.03600 46.05600 ;
    END
  END ra_data[958]
  PIN ra_data[959]
    DIRECTION OUTPUT ;
    USE SIGNAL ;
    PORT
      LAYER M4 ;
      RECT 0.00000 46.08000 0.03600 46.10400 ;
    END
  END ra_data[959]
  PIN ra_data[960]
    DIRECTION OUTPUT ;
    USE SIGNAL ;
    PORT
      LAYER M4 ;
      RECT 0.00000 46.12800 0.03600 46.15200 ;
    END
  END ra_data[960]
  PIN ra_data[961]
    DIRECTION OUTPUT ;
    USE SIGNAL ;
    PORT
      LAYER M4 ;
      RECT 0.00000 46.17600 0.03600 46.20000 ;
    END
  END ra_data[961]
  PIN ra_data[962]
    DIRECTION OUTPUT ;
    USE SIGNAL ;
    PORT
      LAYER M4 ;
      RECT 0.00000 46.22400 0.03600 46.24800 ;
    END
  END ra_data[962]
  PIN ra_data[963]
    DIRECTION OUTPUT ;
    USE SIGNAL ;
    PORT
      LAYER M4 ;
      RECT 0.00000 46.27200 0.03600 46.29600 ;
    END
  END ra_data[963]
  PIN ra_data[964]
    DIRECTION OUTPUT ;
    USE SIGNAL ;
    PORT
      LAYER M4 ;
      RECT 0.00000 46.32000 0.03600 46.34400 ;
    END
  END ra_data[964]
  PIN ra_data[965]
    DIRECTION OUTPUT ;
    USE SIGNAL ;
    PORT
      LAYER M4 ;
      RECT 0.00000 46.36800 0.03600 46.39200 ;
    END
  END ra_data[965]
  PIN ra_data[966]
    DIRECTION OUTPUT ;
    USE SIGNAL ;
    PORT
      LAYER M4 ;
      RECT 0.00000 46.41600 0.03600 46.44000 ;
    END
  END ra_data[966]
  PIN ra_data[967]
    DIRECTION OUTPUT ;
    USE SIGNAL ;
    PORT
      LAYER M4 ;
      RECT 0.00000 46.46400 0.03600 46.48800 ;
    END
  END ra_data[967]
  PIN ra_data[968]
    DIRECTION OUTPUT ;
    USE SIGNAL ;
    PORT
      LAYER M4 ;
      RECT 0.00000 46.51200 0.03600 46.53600 ;
    END
  END ra_data[968]
  PIN ra_data[969]
    DIRECTION OUTPUT ;
    USE SIGNAL ;
    PORT
      LAYER M4 ;
      RECT 0.00000 46.56000 0.03600 46.58400 ;
    END
  END ra_data[969]
  PIN ra_data[970]
    DIRECTION OUTPUT ;
    USE SIGNAL ;
    PORT
      LAYER M4 ;
      RECT 0.00000 46.60800 0.03600 46.63200 ;
    END
  END ra_data[970]
  PIN ra_data[971]
    DIRECTION OUTPUT ;
    USE SIGNAL ;
    PORT
      LAYER M4 ;
      RECT 0.00000 46.65600 0.03600 46.68000 ;
    END
  END ra_data[971]
  PIN ra_data[972]
    DIRECTION OUTPUT ;
    USE SIGNAL ;
    PORT
      LAYER M4 ;
      RECT 0.00000 46.70400 0.03600 46.72800 ;
    END
  END ra_data[972]
  PIN ra_data[973]
    DIRECTION OUTPUT ;
    USE SIGNAL ;
    PORT
      LAYER M4 ;
      RECT 0.00000 46.75200 0.03600 46.77600 ;
    END
  END ra_data[973]
  PIN ra_data[974]
    DIRECTION OUTPUT ;
    USE SIGNAL ;
    PORT
      LAYER M4 ;
      RECT 0.00000 46.80000 0.03600 46.82400 ;
    END
  END ra_data[974]
  PIN ra_data[975]
    DIRECTION OUTPUT ;
    USE SIGNAL ;
    PORT
      LAYER M4 ;
      RECT 0.00000 46.84800 0.03600 46.87200 ;
    END
  END ra_data[975]
  PIN ra_data[976]
    DIRECTION OUTPUT ;
    USE SIGNAL ;
    PORT
      LAYER M4 ;
      RECT 0.00000 46.89600 0.03600 46.92000 ;
    END
  END ra_data[976]
  PIN ra_data[977]
    DIRECTION OUTPUT ;
    USE SIGNAL ;
    PORT
      LAYER M4 ;
      RECT 0.00000 46.94400 0.03600 46.96800 ;
    END
  END ra_data[977]
  PIN ra_data[978]
    DIRECTION OUTPUT ;
    USE SIGNAL ;
    PORT
      LAYER M4 ;
      RECT 0.00000 46.99200 0.03600 47.01600 ;
    END
  END ra_data[978]
  PIN ra_data[979]
    DIRECTION OUTPUT ;
    USE SIGNAL ;
    PORT
      LAYER M4 ;
      RECT 0.00000 47.04000 0.03600 47.06400 ;
    END
  END ra_data[979]
  PIN ra_data[980]
    DIRECTION OUTPUT ;
    USE SIGNAL ;
    PORT
      LAYER M4 ;
      RECT 0.00000 47.08800 0.03600 47.11200 ;
    END
  END ra_data[980]
  PIN ra_data[981]
    DIRECTION OUTPUT ;
    USE SIGNAL ;
    PORT
      LAYER M4 ;
      RECT 0.00000 47.13600 0.03600 47.16000 ;
    END
  END ra_data[981]
  PIN ra_data[982]
    DIRECTION OUTPUT ;
    USE SIGNAL ;
    PORT
      LAYER M4 ;
      RECT 0.00000 47.18400 0.03600 47.20800 ;
    END
  END ra_data[982]
  PIN ra_data[983]
    DIRECTION OUTPUT ;
    USE SIGNAL ;
    PORT
      LAYER M4 ;
      RECT 0.00000 47.23200 0.03600 47.25600 ;
    END
  END ra_data[983]
  PIN ra_data[984]
    DIRECTION OUTPUT ;
    USE SIGNAL ;
    PORT
      LAYER M4 ;
      RECT 0.00000 47.28000 0.03600 47.30400 ;
    END
  END ra_data[984]
  PIN ra_data[985]
    DIRECTION OUTPUT ;
    USE SIGNAL ;
    PORT
      LAYER M4 ;
      RECT 0.00000 47.32800 0.03600 47.35200 ;
    END
  END ra_data[985]
  PIN ra_data[986]
    DIRECTION OUTPUT ;
    USE SIGNAL ;
    PORT
      LAYER M4 ;
      RECT 0.00000 47.37600 0.03600 47.40000 ;
    END
  END ra_data[986]
  PIN ra_data[987]
    DIRECTION OUTPUT ;
    USE SIGNAL ;
    PORT
      LAYER M4 ;
      RECT 0.00000 47.42400 0.03600 47.44800 ;
    END
  END ra_data[987]
  PIN ra_data[988]
    DIRECTION OUTPUT ;
    USE SIGNAL ;
    PORT
      LAYER M4 ;
      RECT 0.00000 47.47200 0.03600 47.49600 ;
    END
  END ra_data[988]
  PIN ra_data[989]
    DIRECTION OUTPUT ;
    USE SIGNAL ;
    PORT
      LAYER M4 ;
      RECT 0.00000 47.52000 0.03600 47.54400 ;
    END
  END ra_data[989]
  PIN ra_data[990]
    DIRECTION OUTPUT ;
    USE SIGNAL ;
    PORT
      LAYER M4 ;
      RECT 0.00000 47.56800 0.03600 47.59200 ;
    END
  END ra_data[990]
  PIN ra_data[991]
    DIRECTION OUTPUT ;
    USE SIGNAL ;
    PORT
      LAYER M4 ;
      RECT 0.00000 47.61600 0.03600 47.64000 ;
    END
  END ra_data[991]
  PIN ra_data[992]
    DIRECTION OUTPUT ;
    USE SIGNAL ;
    PORT
      LAYER M4 ;
      RECT 0.00000 47.66400 0.03600 47.68800 ;
    END
  END ra_data[992]
  PIN ra_data[993]
    DIRECTION OUTPUT ;
    USE SIGNAL ;
    PORT
      LAYER M4 ;
      RECT 0.00000 47.71200 0.03600 47.73600 ;
    END
  END ra_data[993]
  PIN ra_data[994]
    DIRECTION OUTPUT ;
    USE SIGNAL ;
    PORT
      LAYER M4 ;
      RECT 0.00000 47.76000 0.03600 47.78400 ;
    END
  END ra_data[994]
  PIN ra_data[995]
    DIRECTION OUTPUT ;
    USE SIGNAL ;
    PORT
      LAYER M4 ;
      RECT 0.00000 47.80800 0.03600 47.83200 ;
    END
  END ra_data[995]
  PIN ra_data[996]
    DIRECTION OUTPUT ;
    USE SIGNAL ;
    PORT
      LAYER M4 ;
      RECT 0.00000 47.85600 0.03600 47.88000 ;
    END
  END ra_data[996]
  PIN ra_data[997]
    DIRECTION OUTPUT ;
    USE SIGNAL ;
    PORT
      LAYER M4 ;
      RECT 0.00000 47.90400 0.03600 47.92800 ;
    END
  END ra_data[997]
  PIN ra_data[998]
    DIRECTION OUTPUT ;
    USE SIGNAL ;
    PORT
      LAYER M4 ;
      RECT 0.00000 47.95200 0.03600 47.97600 ;
    END
  END ra_data[998]
  PIN ra_data[999]
    DIRECTION OUTPUT ;
    USE SIGNAL ;
    PORT
      LAYER M4 ;
      RECT 0.00000 48.00000 0.03600 48.02400 ;
    END
  END ra_data[999]
  PIN ra_data[1000]
    DIRECTION OUTPUT ;
    USE SIGNAL ;
    PORT
      LAYER M4 ;
      RECT 0.00000 48.04800 0.03600 48.07200 ;
    END
  END ra_data[1000]
  PIN ra_data[1001]
    DIRECTION OUTPUT ;
    USE SIGNAL ;
    PORT
      LAYER M4 ;
      RECT 0.00000 48.09600 0.03600 48.12000 ;
    END
  END ra_data[1001]
  PIN ra_data[1002]
    DIRECTION OUTPUT ;
    USE SIGNAL ;
    PORT
      LAYER M4 ;
      RECT 0.00000 48.14400 0.03600 48.16800 ;
    END
  END ra_data[1002]
  PIN ra_data[1003]
    DIRECTION OUTPUT ;
    USE SIGNAL ;
    PORT
      LAYER M4 ;
      RECT 0.00000 48.19200 0.03600 48.21600 ;
    END
  END ra_data[1003]
  PIN ra_data[1004]
    DIRECTION OUTPUT ;
    USE SIGNAL ;
    PORT
      LAYER M4 ;
      RECT 0.00000 48.24000 0.03600 48.26400 ;
    END
  END ra_data[1004]
  PIN ra_data[1005]
    DIRECTION OUTPUT ;
    USE SIGNAL ;
    PORT
      LAYER M4 ;
      RECT 0.00000 48.28800 0.03600 48.31200 ;
    END
  END ra_data[1005]
  PIN ra_data[1006]
    DIRECTION OUTPUT ;
    USE SIGNAL ;
    PORT
      LAYER M4 ;
      RECT 0.00000 48.33600 0.03600 48.36000 ;
    END
  END ra_data[1006]
  PIN ra_data[1007]
    DIRECTION OUTPUT ;
    USE SIGNAL ;
    PORT
      LAYER M4 ;
      RECT 0.00000 48.38400 0.03600 48.40800 ;
    END
  END ra_data[1007]
  PIN ra_data[1008]
    DIRECTION OUTPUT ;
    USE SIGNAL ;
    PORT
      LAYER M4 ;
      RECT 0.00000 48.43200 0.03600 48.45600 ;
    END
  END ra_data[1008]
  PIN ra_data[1009]
    DIRECTION OUTPUT ;
    USE SIGNAL ;
    PORT
      LAYER M4 ;
      RECT 0.00000 48.48000 0.03600 48.50400 ;
    END
  END ra_data[1009]
  PIN ra_data[1010]
    DIRECTION OUTPUT ;
    USE SIGNAL ;
    PORT
      LAYER M4 ;
      RECT 0.00000 48.52800 0.03600 48.55200 ;
    END
  END ra_data[1010]
  PIN ra_data[1011]
    DIRECTION OUTPUT ;
    USE SIGNAL ;
    PORT
      LAYER M4 ;
      RECT 0.00000 48.57600 0.03600 48.60000 ;
    END
  END ra_data[1011]
  PIN ra_data[1012]
    DIRECTION OUTPUT ;
    USE SIGNAL ;
    PORT
      LAYER M4 ;
      RECT 0.00000 48.62400 0.03600 48.64800 ;
    END
  END ra_data[1012]
  PIN ra_data[1013]
    DIRECTION OUTPUT ;
    USE SIGNAL ;
    PORT
      LAYER M4 ;
      RECT 0.00000 48.67200 0.03600 48.69600 ;
    END
  END ra_data[1013]
  PIN ra_data[1014]
    DIRECTION OUTPUT ;
    USE SIGNAL ;
    PORT
      LAYER M4 ;
      RECT 0.00000 48.72000 0.03600 48.74400 ;
    END
  END ra_data[1014]
  PIN ra_data[1015]
    DIRECTION OUTPUT ;
    USE SIGNAL ;
    PORT
      LAYER M4 ;
      RECT 0.00000 48.76800 0.03600 48.79200 ;
    END
  END ra_data[1015]
  PIN ra_data[1016]
    DIRECTION OUTPUT ;
    USE SIGNAL ;
    PORT
      LAYER M4 ;
      RECT 0.00000 48.81600 0.03600 48.84000 ;
    END
  END ra_data[1016]
  PIN ra_data[1017]
    DIRECTION OUTPUT ;
    USE SIGNAL ;
    PORT
      LAYER M4 ;
      RECT 0.00000 48.86400 0.03600 48.88800 ;
    END
  END ra_data[1017]
  PIN ra_data[1018]
    DIRECTION OUTPUT ;
    USE SIGNAL ;
    PORT
      LAYER M4 ;
      RECT 0.00000 48.91200 0.03600 48.93600 ;
    END
  END ra_data[1018]
  PIN ra_data[1019]
    DIRECTION OUTPUT ;
    USE SIGNAL ;
    PORT
      LAYER M4 ;
      RECT 0.00000 48.96000 0.03600 48.98400 ;
    END
  END ra_data[1019]
  PIN ra_data[1020]
    DIRECTION OUTPUT ;
    USE SIGNAL ;
    PORT
      LAYER M4 ;
      RECT 0.00000 49.00800 0.03600 49.03200 ;
    END
  END ra_data[1020]
  PIN ra_data[1021]
    DIRECTION OUTPUT ;
    USE SIGNAL ;
    PORT
      LAYER M4 ;
      RECT 0.00000 49.05600 0.03600 49.08000 ;
    END
  END ra_data[1021]
  PIN ra_data[1022]
    DIRECTION OUTPUT ;
    USE SIGNAL ;
    PORT
      LAYER M4 ;
      RECT 0.00000 49.10400 0.03600 49.12800 ;
    END
  END ra_data[1022]
  PIN ra_data[1023]
    DIRECTION OUTPUT ;
    USE SIGNAL ;
    PORT
      LAYER M4 ;
      RECT 0.00000 49.15200 0.03600 49.17600 ;
    END
  END ra_data[1023]
  PIN ra_addr[0]
    DIRECTION INPUT ;
    USE SIGNAL ;
    PORT
      LAYER M4 ;
      RECT 0.00000 98.73600 0.03600 98.76000 ;
    END
  END ra_addr[0]
  PIN ra_addr[1]
    DIRECTION INPUT ;
    USE SIGNAL ;
    PORT
      LAYER M4 ;
      RECT 0.00000 98.78400 0.03600 98.80800 ;
    END
  END ra_addr[1]
  PIN ra_addr[2]
    DIRECTION INPUT ;
    USE SIGNAL ;
    PORT
      LAYER M4 ;
      RECT 0.00000 98.83200 0.03600 98.85600 ;
    END
  END ra_addr[2]
  PIN ra_addr[3]
    DIRECTION INPUT ;
    USE SIGNAL ;
    PORT
      LAYER M4 ;
      RECT 0.00000 98.88000 0.03600 98.90400 ;
    END
  END ra_addr[3]
  PIN ra_addr[4]
    DIRECTION INPUT ;
    USE SIGNAL ;
    PORT
      LAYER M4 ;
      RECT 0.00000 98.92800 0.03600 98.95200 ;
    END
  END ra_addr[4]
  PIN ra_addr[5]
    DIRECTION INPUT ;
    USE SIGNAL ;
    PORT
      LAYER M4 ;
      RECT 0.00000 98.97600 0.03600 99.00000 ;
    END
  END ra_addr[5]
  PIN we[0]
    DIRECTION INPUT ;
    USE SIGNAL ;
    PORT
      LAYER M4 ;
      RECT 0.00000 99.12000 0.03600 99.14400 ;
    END
  END we[0]
  PIN we[1]
    DIRECTION INPUT ;
    USE SIGNAL ;
    PORT
      LAYER M4 ;
      RECT 0.00000 99.16800 0.03600 99.19200 ;
    END
  END we[1]
  PIN we[2]
    DIRECTION INPUT ;
    USE SIGNAL ;
    PORT
      LAYER M4 ;
      RECT 0.00000 99.21600 0.03600 99.24000 ;
    END
  END we[2]
  PIN we[3]
    DIRECTION INPUT ;
    USE SIGNAL ;
    PORT
      LAYER M4 ;
      RECT 0.00000 99.26400 0.03600 99.28800 ;
    END
  END we[3]
  PIN we[4]
    DIRECTION INPUT ;
    USE SIGNAL ;
    PORT
      LAYER M4 ;
      RECT 0.00000 99.31200 0.03600 99.33600 ;
    END
  END we[4]
  PIN we[5]
    DIRECTION INPUT ;
    USE SIGNAL ;
    PORT
      LAYER M4 ;
      RECT 0.00000 99.36000 0.03600 99.38400 ;
    END
  END we[5]
  PIN we[6]
    DIRECTION INPUT ;
    USE SIGNAL ;
    PORT
      LAYER M4 ;
      RECT 0.00000 99.40800 0.03600 99.43200 ;
    END
  END we[6]
  PIN we[7]
    DIRECTION INPUT ;
    USE SIGNAL ;
    PORT
      LAYER M4 ;
      RECT 0.00000 99.45600 0.03600 99.48000 ;
    END
  END we[7]
  PIN we[8]
    DIRECTION INPUT ;
    USE SIGNAL ;
    PORT
      LAYER M4 ;
      RECT 0.00000 99.50400 0.03600 99.52800 ;
    END
  END we[8]
  PIN we[9]
    DIRECTION INPUT ;
    USE SIGNAL ;
    PORT
      LAYER M4 ;
      RECT 0.00000 99.55200 0.03600 99.57600 ;
    END
  END we[9]
  PIN we[10]
    DIRECTION INPUT ;
    USE SIGNAL ;
    PORT
      LAYER M4 ;
      RECT 0.00000 99.60000 0.03600 99.62400 ;
    END
  END we[10]
  PIN we[11]
    DIRECTION INPUT ;
    USE SIGNAL ;
    PORT
      LAYER M4 ;
      RECT 0.00000 99.64800 0.03600 99.67200 ;
    END
  END we[11]
  PIN we[12]
    DIRECTION INPUT ;
    USE SIGNAL ;
    PORT
      LAYER M4 ;
      RECT 0.00000 99.69600 0.03600 99.72000 ;
    END
  END we[12]
  PIN we[13]
    DIRECTION INPUT ;
    USE SIGNAL ;
    PORT
      LAYER M4 ;
      RECT 0.00000 99.74400 0.03600 99.76800 ;
    END
  END we[13]
  PIN we[14]
    DIRECTION INPUT ;
    USE SIGNAL ;
    PORT
      LAYER M4 ;
      RECT 0.00000 99.79200 0.03600 99.81600 ;
    END
  END we[14]
  PIN we[15]
    DIRECTION INPUT ;
    USE SIGNAL ;
    PORT
      LAYER M4 ;
      RECT 0.00000 99.84000 0.03600 99.86400 ;
    END
  END we[15]
  PIN we[16]
    DIRECTION INPUT ;
    USE SIGNAL ;
    PORT
      LAYER M4 ;
      RECT 0.00000 99.88800 0.03600 99.91200 ;
    END
  END we[16]
  PIN we[17]
    DIRECTION INPUT ;
    USE SIGNAL ;
    PORT
      LAYER M4 ;
      RECT 0.00000 99.93600 0.03600 99.96000 ;
    END
  END we[17]
  PIN we[18]
    DIRECTION INPUT ;
    USE SIGNAL ;
    PORT
      LAYER M4 ;
      RECT 0.00000 99.98400 0.03600 100.00800 ;
    END
  END we[18]
  PIN we[19]
    DIRECTION INPUT ;
    USE SIGNAL ;
    PORT
      LAYER M4 ;
      RECT 0.00000 100.03200 0.03600 100.05600 ;
    END
  END we[19]
  PIN we[20]
    DIRECTION INPUT ;
    USE SIGNAL ;
    PORT
      LAYER M4 ;
      RECT 0.00000 100.08000 0.03600 100.10400 ;
    END
  END we[20]
  PIN we[21]
    DIRECTION INPUT ;
    USE SIGNAL ;
    PORT
      LAYER M4 ;
      RECT 0.00000 100.12800 0.03600 100.15200 ;
    END
  END we[21]
  PIN we[22]
    DIRECTION INPUT ;
    USE SIGNAL ;
    PORT
      LAYER M4 ;
      RECT 0.00000 100.17600 0.03600 100.20000 ;
    END
  END we[22]
  PIN we[23]
    DIRECTION INPUT ;
    USE SIGNAL ;
    PORT
      LAYER M4 ;
      RECT 0.00000 100.22400 0.03600 100.24800 ;
    END
  END we[23]
  PIN we[24]
    DIRECTION INPUT ;
    USE SIGNAL ;
    PORT
      LAYER M4 ;
      RECT 0.00000 100.27200 0.03600 100.29600 ;
    END
  END we[24]
  PIN we[25]
    DIRECTION INPUT ;
    USE SIGNAL ;
    PORT
      LAYER M4 ;
      RECT 0.00000 100.32000 0.03600 100.34400 ;
    END
  END we[25]
  PIN we[26]
    DIRECTION INPUT ;
    USE SIGNAL ;
    PORT
      LAYER M4 ;
      RECT 0.00000 100.36800 0.03600 100.39200 ;
    END
  END we[26]
  PIN we[27]
    DIRECTION INPUT ;
    USE SIGNAL ;
    PORT
      LAYER M4 ;
      RECT 0.00000 100.41600 0.03600 100.44000 ;
    END
  END we[27]
  PIN we[28]
    DIRECTION INPUT ;
    USE SIGNAL ;
    PORT
      LAYER M4 ;
      RECT 0.00000 100.46400 0.03600 100.48800 ;
    END
  END we[28]
  PIN we[29]
    DIRECTION INPUT ;
    USE SIGNAL ;
    PORT
      LAYER M4 ;
      RECT 0.00000 100.51200 0.03600 100.53600 ;
    END
  END we[29]
  PIN we[30]
    DIRECTION INPUT ;
    USE SIGNAL ;
    PORT
      LAYER M4 ;
      RECT 0.00000 100.56000 0.03600 100.58400 ;
    END
  END we[30]
  PIN we[31]
    DIRECTION INPUT ;
    USE SIGNAL ;
    PORT
      LAYER M4 ;
      RECT 0.00000 100.60800 0.03600 100.63200 ;
    END
  END we[31]
  PIN clk
    DIRECTION INPUT ;
    USE SIGNAL ;
    PORT
      LAYER M4 ;
      RECT 0.00000 99.07200 0.03600 99.09600 ;
    END
  END clk
  PIN VDD
    DIRECTION INOUT ;
    USE POWER ;
    PORT
      LAYER M4 ;
      RECT 0.09600 0.38400 132.71400 0.48000 ;
      RECT 0.09600 1.15200 132.71400 1.24800 ;
      RECT 0.09600 1.92000 132.71400 2.01600 ;
      RECT 0.09600 2.68800 132.71400 2.78400 ;
      RECT 0.09600 3.45600 132.71400 3.55200 ;
      RECT 0.09600 4.22400 132.71400 4.32000 ;
      RECT 0.09600 4.99200 132.71400 5.08800 ;
      RECT 0.09600 5.76000 132.71400 5.85600 ;
      RECT 0.09600 6.52800 132.71400 6.62400 ;
      RECT 0.09600 7.29600 132.71400 7.39200 ;
      RECT 0.09600 8.06400 132.71400 8.16000 ;
      RECT 0.09600 8.83200 132.71400 8.92800 ;
      RECT 0.09600 9.60000 132.71400 9.69600 ;
      RECT 0.09600 10.36800 132.71400 10.46400 ;
      RECT 0.09600 11.13600 132.71400 11.23200 ;
      RECT 0.09600 11.90400 132.71400 12.00000 ;
      RECT 0.09600 12.67200 132.71400 12.76800 ;
      RECT 0.09600 13.44000 132.71400 13.53600 ;
      RECT 0.09600 14.20800 132.71400 14.30400 ;
      RECT 0.09600 14.97600 132.71400 15.07200 ;
      RECT 0.09600 15.74400 132.71400 15.84000 ;
      RECT 0.09600 16.51200 132.71400 16.60800 ;
      RECT 0.09600 17.28000 132.71400 17.37600 ;
      RECT 0.09600 18.04800 132.71400 18.14400 ;
      RECT 0.09600 18.81600 132.71400 18.91200 ;
      RECT 0.09600 19.58400 132.71400 19.68000 ;
      RECT 0.09600 20.35200 132.71400 20.44800 ;
      RECT 0.09600 21.12000 132.71400 21.21600 ;
      RECT 0.09600 21.88800 132.71400 21.98400 ;
      RECT 0.09600 22.65600 132.71400 22.75200 ;
      RECT 0.09600 23.42400 132.71400 23.52000 ;
      RECT 0.09600 24.19200 132.71400 24.28800 ;
      RECT 0.09600 24.96000 132.71400 25.05600 ;
      RECT 0.09600 25.72800 132.71400 25.82400 ;
      RECT 0.09600 26.49600 132.71400 26.59200 ;
      RECT 0.09600 27.26400 132.71400 27.36000 ;
      RECT 0.09600 28.03200 132.71400 28.12800 ;
      RECT 0.09600 28.80000 132.71400 28.89600 ;
      RECT 0.09600 29.56800 132.71400 29.66400 ;
      RECT 0.09600 30.33600 132.71400 30.43200 ;
      RECT 0.09600 31.10400 132.71400 31.20000 ;
      RECT 0.09600 31.87200 132.71400 31.96800 ;
      RECT 0.09600 32.64000 132.71400 32.73600 ;
      RECT 0.09600 33.40800 132.71400 33.50400 ;
      RECT 0.09600 34.17600 132.71400 34.27200 ;
      RECT 0.09600 34.94400 132.71400 35.04000 ;
      RECT 0.09600 35.71200 132.71400 35.80800 ;
      RECT 0.09600 36.48000 132.71400 36.57600 ;
      RECT 0.09600 37.24800 132.71400 37.34400 ;
      RECT 0.09600 38.01600 132.71400 38.11200 ;
      RECT 0.09600 38.78400 132.71400 38.88000 ;
      RECT 0.09600 39.55200 132.71400 39.64800 ;
      RECT 0.09600 40.32000 132.71400 40.41600 ;
      RECT 0.09600 41.08800 132.71400 41.18400 ;
      RECT 0.09600 41.85600 132.71400 41.95200 ;
      RECT 0.09600 42.62400 132.71400 42.72000 ;
      RECT 0.09600 43.39200 132.71400 43.48800 ;
      RECT 0.09600 44.16000 132.71400 44.25600 ;
      RECT 0.09600 44.92800 132.71400 45.02400 ;
      RECT 0.09600 45.69600 132.71400 45.79200 ;
      RECT 0.09600 46.46400 132.71400 46.56000 ;
      RECT 0.09600 47.23200 132.71400 47.32800 ;
      RECT 0.09600 48.00000 132.71400 48.09600 ;
      RECT 0.09600 48.76800 132.71400 48.86400 ;
      RECT 0.09600 49.53600 132.71400 49.63200 ;
      RECT 0.09600 50.30400 132.71400 50.40000 ;
      RECT 0.09600 51.07200 132.71400 51.16800 ;
      RECT 0.09600 51.84000 132.71400 51.93600 ;
      RECT 0.09600 52.60800 132.71400 52.70400 ;
      RECT 0.09600 53.37600 132.71400 53.47200 ;
      RECT 0.09600 54.14400 132.71400 54.24000 ;
      RECT 0.09600 54.91200 132.71400 55.00800 ;
      RECT 0.09600 55.68000 132.71400 55.77600 ;
      RECT 0.09600 56.44800 132.71400 56.54400 ;
      RECT 0.09600 57.21600 132.71400 57.31200 ;
      RECT 0.09600 57.98400 132.71400 58.08000 ;
      RECT 0.09600 58.75200 132.71400 58.84800 ;
      RECT 0.09600 59.52000 132.71400 59.61600 ;
      RECT 0.09600 60.28800 132.71400 60.38400 ;
      RECT 0.09600 61.05600 132.71400 61.15200 ;
      RECT 0.09600 61.82400 132.71400 61.92000 ;
      RECT 0.09600 62.59200 132.71400 62.68800 ;
      RECT 0.09600 63.36000 132.71400 63.45600 ;
      RECT 0.09600 64.12800 132.71400 64.22400 ;
      RECT 0.09600 64.89600 132.71400 64.99200 ;
      RECT 0.09600 65.66400 132.71400 65.76000 ;
      RECT 0.09600 66.43200 132.71400 66.52800 ;
      RECT 0.09600 67.20000 132.71400 67.29600 ;
      RECT 0.09600 67.96800 132.71400 68.06400 ;
      RECT 0.09600 68.73600 132.71400 68.83200 ;
      RECT 0.09600 69.50400 132.71400 69.60000 ;
      RECT 0.09600 70.27200 132.71400 70.36800 ;
      RECT 0.09600 71.04000 132.71400 71.13600 ;
      RECT 0.09600 71.80800 132.71400 71.90400 ;
      RECT 0.09600 72.57600 132.71400 72.67200 ;
      RECT 0.09600 73.34400 132.71400 73.44000 ;
      RECT 0.09600 74.11200 132.71400 74.20800 ;
      RECT 0.09600 74.88000 132.71400 74.97600 ;
      RECT 0.09600 75.64800 132.71400 75.74400 ;
      RECT 0.09600 76.41600 132.71400 76.51200 ;
      RECT 0.09600 77.18400 132.71400 77.28000 ;
      RECT 0.09600 77.95200 132.71400 78.04800 ;
      RECT 0.09600 78.72000 132.71400 78.81600 ;
      RECT 0.09600 79.48800 132.71400 79.58400 ;
      RECT 0.09600 80.25600 132.71400 80.35200 ;
      RECT 0.09600 81.02400 132.71400 81.12000 ;
      RECT 0.09600 81.79200 132.71400 81.88800 ;
      RECT 0.09600 82.56000 132.71400 82.65600 ;
      RECT 0.09600 83.32800 132.71400 83.42400 ;
      RECT 0.09600 84.09600 132.71400 84.19200 ;
      RECT 0.09600 84.86400 132.71400 84.96000 ;
      RECT 0.09600 85.63200 132.71400 85.72800 ;
      RECT 0.09600 86.40000 132.71400 86.49600 ;
      RECT 0.09600 87.16800 132.71400 87.26400 ;
      RECT 0.09600 87.93600 132.71400 88.03200 ;
      RECT 0.09600 88.70400 132.71400 88.80000 ;
      RECT 0.09600 89.47200 132.71400 89.56800 ;
      RECT 0.09600 90.24000 132.71400 90.33600 ;
      RECT 0.09600 91.00800 132.71400 91.10400 ;
      RECT 0.09600 91.77600 132.71400 91.87200 ;
      RECT 0.09600 92.54400 132.71400 92.64000 ;
      RECT 0.09600 93.31200 132.71400 93.40800 ;
      RECT 0.09600 94.08000 132.71400 94.17600 ;
      RECT 0.09600 94.84800 132.71400 94.94400 ;
      RECT 0.09600 95.61600 132.71400 95.71200 ;
      RECT 0.09600 96.38400 132.71400 96.48000 ;
      RECT 0.09600 97.15200 132.71400 97.24800 ;
      RECT 0.09600 97.92000 132.71400 98.01600 ;
      RECT 0.09600 98.68800 132.71400 98.78400 ;
      RECT 0.09600 99.45600 132.71400 99.55200 ;
      RECT 0.09600 100.22400 132.71400 100.32000 ;
    END
  END VDD
  PIN VSS
    DIRECTION INOUT ;
    USE GROUND ;
    PORT
      LAYER M4 ;
      RECT 0.09600 0.00000 132.71400 0.09600 ;
      RECT 0.09600 0.76800 132.71400 0.86400 ;
      RECT 0.09600 1.53600 132.71400 1.63200 ;
      RECT 0.09600 2.30400 132.71400 2.40000 ;
      RECT 0.09600 3.07200 132.71400 3.16800 ;
      RECT 0.09600 3.84000 132.71400 3.93600 ;
      RECT 0.09600 4.60800 132.71400 4.70400 ;
      RECT 0.09600 5.37600 132.71400 5.47200 ;
      RECT 0.09600 6.14400 132.71400 6.24000 ;
      RECT 0.09600 6.91200 132.71400 7.00800 ;
      RECT 0.09600 7.68000 132.71400 7.77600 ;
      RECT 0.09600 8.44800 132.71400 8.54400 ;
      RECT 0.09600 9.21600 132.71400 9.31200 ;
      RECT 0.09600 9.98400 132.71400 10.08000 ;
      RECT 0.09600 10.75200 132.71400 10.84800 ;
      RECT 0.09600 11.52000 132.71400 11.61600 ;
      RECT 0.09600 12.28800 132.71400 12.38400 ;
      RECT 0.09600 13.05600 132.71400 13.15200 ;
      RECT 0.09600 13.82400 132.71400 13.92000 ;
      RECT 0.09600 14.59200 132.71400 14.68800 ;
      RECT 0.09600 15.36000 132.71400 15.45600 ;
      RECT 0.09600 16.12800 132.71400 16.22400 ;
      RECT 0.09600 16.89600 132.71400 16.99200 ;
      RECT 0.09600 17.66400 132.71400 17.76000 ;
      RECT 0.09600 18.43200 132.71400 18.52800 ;
      RECT 0.09600 19.20000 132.71400 19.29600 ;
      RECT 0.09600 19.96800 132.71400 20.06400 ;
      RECT 0.09600 20.73600 132.71400 20.83200 ;
      RECT 0.09600 21.50400 132.71400 21.60000 ;
      RECT 0.09600 22.27200 132.71400 22.36800 ;
      RECT 0.09600 23.04000 132.71400 23.13600 ;
      RECT 0.09600 23.80800 132.71400 23.90400 ;
      RECT 0.09600 24.57600 132.71400 24.67200 ;
      RECT 0.09600 25.34400 132.71400 25.44000 ;
      RECT 0.09600 26.11200 132.71400 26.20800 ;
      RECT 0.09600 26.88000 132.71400 26.97600 ;
      RECT 0.09600 27.64800 132.71400 27.74400 ;
      RECT 0.09600 28.41600 132.71400 28.51200 ;
      RECT 0.09600 29.18400 132.71400 29.28000 ;
      RECT 0.09600 29.95200 132.71400 30.04800 ;
      RECT 0.09600 30.72000 132.71400 30.81600 ;
      RECT 0.09600 31.48800 132.71400 31.58400 ;
      RECT 0.09600 32.25600 132.71400 32.35200 ;
      RECT 0.09600 33.02400 132.71400 33.12000 ;
      RECT 0.09600 33.79200 132.71400 33.88800 ;
      RECT 0.09600 34.56000 132.71400 34.65600 ;
      RECT 0.09600 35.32800 132.71400 35.42400 ;
      RECT 0.09600 36.09600 132.71400 36.19200 ;
      RECT 0.09600 36.86400 132.71400 36.96000 ;
      RECT 0.09600 37.63200 132.71400 37.72800 ;
      RECT 0.09600 38.40000 132.71400 38.49600 ;
      RECT 0.09600 39.16800 132.71400 39.26400 ;
      RECT 0.09600 39.93600 132.71400 40.03200 ;
      RECT 0.09600 40.70400 132.71400 40.80000 ;
      RECT 0.09600 41.47200 132.71400 41.56800 ;
      RECT 0.09600 42.24000 132.71400 42.33600 ;
      RECT 0.09600 43.00800 132.71400 43.10400 ;
      RECT 0.09600 43.77600 132.71400 43.87200 ;
      RECT 0.09600 44.54400 132.71400 44.64000 ;
      RECT 0.09600 45.31200 132.71400 45.40800 ;
      RECT 0.09600 46.08000 132.71400 46.17600 ;
      RECT 0.09600 46.84800 132.71400 46.94400 ;
      RECT 0.09600 47.61600 132.71400 47.71200 ;
      RECT 0.09600 48.38400 132.71400 48.48000 ;
      RECT 0.09600 49.15200 132.71400 49.24800 ;
      RECT 0.09600 49.92000 132.71400 50.01600 ;
      RECT 0.09600 50.68800 132.71400 50.78400 ;
      RECT 0.09600 51.45600 132.71400 51.55200 ;
      RECT 0.09600 52.22400 132.71400 52.32000 ;
      RECT 0.09600 52.99200 132.71400 53.08800 ;
      RECT 0.09600 53.76000 132.71400 53.85600 ;
      RECT 0.09600 54.52800 132.71400 54.62400 ;
      RECT 0.09600 55.29600 132.71400 55.39200 ;
      RECT 0.09600 56.06400 132.71400 56.16000 ;
      RECT 0.09600 56.83200 132.71400 56.92800 ;
      RECT 0.09600 57.60000 132.71400 57.69600 ;
      RECT 0.09600 58.36800 132.71400 58.46400 ;
      RECT 0.09600 59.13600 132.71400 59.23200 ;
      RECT 0.09600 59.90400 132.71400 60.00000 ;
      RECT 0.09600 60.67200 132.71400 60.76800 ;
      RECT 0.09600 61.44000 132.71400 61.53600 ;
      RECT 0.09600 62.20800 132.71400 62.30400 ;
      RECT 0.09600 62.97600 132.71400 63.07200 ;
      RECT 0.09600 63.74400 132.71400 63.84000 ;
      RECT 0.09600 64.51200 132.71400 64.60800 ;
      RECT 0.09600 65.28000 132.71400 65.37600 ;
      RECT 0.09600 66.04800 132.71400 66.14400 ;
      RECT 0.09600 66.81600 132.71400 66.91200 ;
      RECT 0.09600 67.58400 132.71400 67.68000 ;
      RECT 0.09600 68.35200 132.71400 68.44800 ;
      RECT 0.09600 69.12000 132.71400 69.21600 ;
      RECT 0.09600 69.88800 132.71400 69.98400 ;
      RECT 0.09600 70.65600 132.71400 70.75200 ;
      RECT 0.09600 71.42400 132.71400 71.52000 ;
      RECT 0.09600 72.19200 132.71400 72.28800 ;
      RECT 0.09600 72.96000 132.71400 73.05600 ;
      RECT 0.09600 73.72800 132.71400 73.82400 ;
      RECT 0.09600 74.49600 132.71400 74.59200 ;
      RECT 0.09600 75.26400 132.71400 75.36000 ;
      RECT 0.09600 76.03200 132.71400 76.12800 ;
      RECT 0.09600 76.80000 132.71400 76.89600 ;
      RECT 0.09600 77.56800 132.71400 77.66400 ;
      RECT 0.09600 78.33600 132.71400 78.43200 ;
      RECT 0.09600 79.10400 132.71400 79.20000 ;
      RECT 0.09600 79.87200 132.71400 79.96800 ;
      RECT 0.09600 80.64000 132.71400 80.73600 ;
      RECT 0.09600 81.40800 132.71400 81.50400 ;
      RECT 0.09600 82.17600 132.71400 82.27200 ;
      RECT 0.09600 82.94400 132.71400 83.04000 ;
      RECT 0.09600 83.71200 132.71400 83.80800 ;
      RECT 0.09600 84.48000 132.71400 84.57600 ;
      RECT 0.09600 85.24800 132.71400 85.34400 ;
      RECT 0.09600 86.01600 132.71400 86.11200 ;
      RECT 0.09600 86.78400 132.71400 86.88000 ;
      RECT 0.09600 87.55200 132.71400 87.64800 ;
      RECT 0.09600 88.32000 132.71400 88.41600 ;
      RECT 0.09600 89.08800 132.71400 89.18400 ;
      RECT 0.09600 89.85600 132.71400 89.95200 ;
      RECT 0.09600 90.62400 132.71400 90.72000 ;
      RECT 0.09600 91.39200 132.71400 91.48800 ;
      RECT 0.09600 92.16000 132.71400 92.25600 ;
      RECT 0.09600 92.92800 132.71400 93.02400 ;
      RECT 0.09600 93.69600 132.71400 93.79200 ;
      RECT 0.09600 94.46400 132.71400 94.56000 ;
      RECT 0.09600 95.23200 132.71400 95.32800 ;
      RECT 0.09600 96.00000 132.71400 96.09600 ;
      RECT 0.09600 96.76800 132.71400 96.86400 ;
      RECT 0.09600 97.53600 132.71400 97.63200 ;
      RECT 0.09600 98.30400 132.71400 98.40000 ;
      RECT 0.09600 99.07200 132.71400 99.16800 ;
      RECT 0.09600 99.84000 132.71400 99.93600 ;
      RECT 0.09600 100.60800 132.71400 100.70400 ;
    END
  END VSS
  OBS
    LAYER M1 ;
    RECT 0 0 132.81000 100.80000 ;
    LAYER M2 ;
    RECT 0 0 132.81000 100.80000 ;
    LAYER M3 ;
    RECT 0 0 132.81000 100.80000 ;
    LAYER M4 ;
    RECT 0 0 132.81000 100.80000 ;
  END
END fakeram7_64x1024_g32_1w1a

END LIBRARY
